VERSION 5.8 ;
BUSBITCHARS "[]" ;
DIVIDERCHAR "/" ;
UNITS
    DATABASE MICRONS 1000 ;
END UNITS

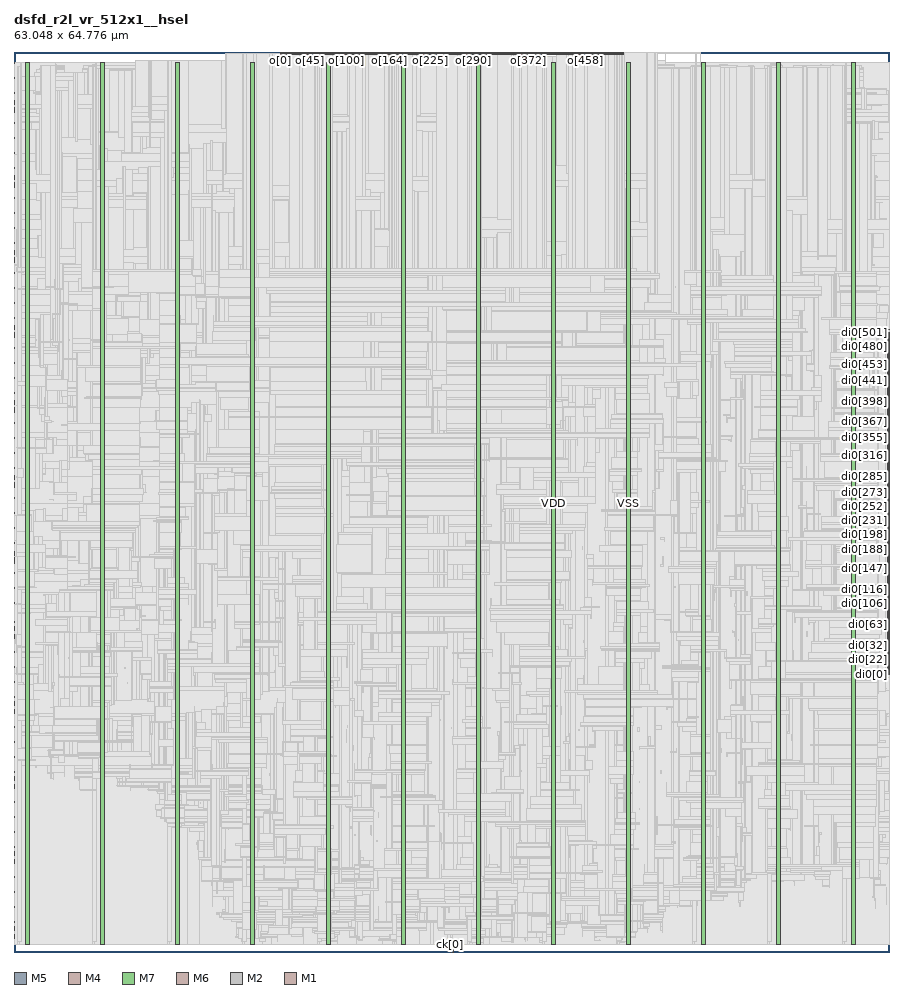
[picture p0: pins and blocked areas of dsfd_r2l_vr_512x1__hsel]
MACRO dsfd_r2l_vr_512x1__hsel
  FOREIGN dsfd_r2l_vr_512x1__hsel 0 0 ;
  CLASS BLOCK ;
  SIZE 63.048 BY 64.776 ;
  PIN ck[0]
    DIRECTION INPUT ;
    USE SIGNAL ;
    PORT
      LAYER M5 ;
        RECT  31.392 0 31.416 0.192 ;
    END
  END ck[0]
  PIN di0[0]
    DIRECTION INPUT ;
    USE SIGNAL ;
    PORT
      LAYER M4 ;
        RECT  62.856 19.968 63.048 19.992 ;
    END
  END di0[0]
  PIN di0[100]
    DIRECTION INPUT ;
    USE SIGNAL ;
    PORT
      LAYER M4 ;
        RECT  62.856 24.768 63.048 24.792 ;
    END
  END di0[100]
  PIN di0[101]
    DIRECTION INPUT ;
    USE SIGNAL ;
    PORT
      LAYER M4 ;
        RECT  62.856 24.816 63.048 24.84 ;
    END
  END di0[101]
  PIN di0[102]
    DIRECTION INPUT ;
    USE SIGNAL ;
    PORT
      LAYER M4 ;
        RECT  62.856 24.864 63.048 24.888 ;
    END
  END di0[102]
  PIN di0[103]
    DIRECTION INPUT ;
    USE SIGNAL ;
    PORT
      LAYER M4 ;
        RECT  62.856 24.912 63.048 24.936 ;
    END
  END di0[103]
  PIN di0[104]
    DIRECTION INPUT ;
    USE SIGNAL ;
    PORT
      LAYER M4 ;
        RECT  62.856 24.96 63.048 24.984 ;
    END
  END di0[104]
  PIN di0[105]
    DIRECTION INPUT ;
    USE SIGNAL ;
    PORT
      LAYER M4 ;
        RECT  62.856 25.008 63.048 25.032 ;
    END
  END di0[105]
  PIN di0[106]
    DIRECTION INPUT ;
    USE SIGNAL ;
    PORT
      LAYER M4 ;
        RECT  62.856 25.056 63.048 25.08 ;
    END
  END di0[106]
  PIN di0[107]
    DIRECTION INPUT ;
    USE SIGNAL ;
    PORT
      LAYER M4 ;
        RECT  62.856 25.104 63.048 25.128 ;
    END
  END di0[107]
  PIN di0[108]
    DIRECTION INPUT ;
    USE SIGNAL ;
    PORT
      LAYER M4 ;
        RECT  62.856 25.152 63.048 25.176 ;
    END
  END di0[108]
  PIN di0[109]
    DIRECTION INPUT ;
    USE SIGNAL ;
    PORT
      LAYER M4 ;
        RECT  62.856 25.2 63.048 25.224 ;
    END
  END di0[109]
  PIN di0[10]
    DIRECTION INPUT ;
    USE SIGNAL ;
    PORT
      LAYER M4 ;
        RECT  62.856 20.448 63.048 20.472 ;
    END
  END di0[10]
  PIN di0[110]
    DIRECTION INPUT ;
    USE SIGNAL ;
    PORT
      LAYER M4 ;
        RECT  62.856 25.248 63.048 25.272 ;
    END
  END di0[110]
  PIN di0[111]
    DIRECTION INPUT ;
    USE SIGNAL ;
    PORT
      LAYER M4 ;
        RECT  62.856 25.296 63.048 25.32 ;
    END
  END di0[111]
  PIN di0[112]
    DIRECTION INPUT ;
    USE SIGNAL ;
    PORT
      LAYER M4 ;
        RECT  62.856 25.344 63.048 25.368 ;
    END
  END di0[112]
  PIN di0[113]
    DIRECTION INPUT ;
    USE SIGNAL ;
    PORT
      LAYER M4 ;
        RECT  62.856 25.392 63.048 25.416 ;
    END
  END di0[113]
  PIN di0[114]
    DIRECTION INPUT ;
    USE SIGNAL ;
    PORT
      LAYER M4 ;
        RECT  62.856 25.44 63.048 25.464 ;
    END
  END di0[114]
  PIN di0[115]
    DIRECTION INPUT ;
    USE SIGNAL ;
    PORT
      LAYER M4 ;
        RECT  62.856 25.488 63.048 25.512 ;
    END
  END di0[115]
  PIN di0[116]
    DIRECTION INPUT ;
    USE SIGNAL ;
    PORT
      LAYER M4 ;
        RECT  62.856 25.536 63.048 25.56 ;
    END
  END di0[116]
  PIN di0[117]
    DIRECTION INPUT ;
    USE SIGNAL ;
    PORT
      LAYER M4 ;
        RECT  62.856 25.584 63.048 25.608 ;
    END
  END di0[117]
  PIN di0[118]
    DIRECTION INPUT ;
    USE SIGNAL ;
    PORT
      LAYER M4 ;
        RECT  62.856 25.632 63.048 25.656 ;
    END
  END di0[118]
  PIN di0[119]
    DIRECTION INPUT ;
    USE SIGNAL ;
    PORT
      LAYER M4 ;
        RECT  62.856 25.68 63.048 25.704 ;
    END
  END di0[119]
  PIN di0[11]
    DIRECTION INPUT ;
    USE SIGNAL ;
    PORT
      LAYER M4 ;
        RECT  62.856 20.496 63.048 20.52 ;
    END
  END di0[11]
  PIN di0[120]
    DIRECTION INPUT ;
    USE SIGNAL ;
    PORT
      LAYER M4 ;
        RECT  62.856 25.728 63.048 25.752 ;
    END
  END di0[120]
  PIN di0[121]
    DIRECTION INPUT ;
    USE SIGNAL ;
    PORT
      LAYER M4 ;
        RECT  62.856 25.776 63.048 25.8 ;
    END
  END di0[121]
  PIN di0[122]
    DIRECTION INPUT ;
    USE SIGNAL ;
    PORT
      LAYER M4 ;
        RECT  62.856 25.824 63.048 25.848 ;
    END
  END di0[122]
  PIN di0[123]
    DIRECTION INPUT ;
    USE SIGNAL ;
    PORT
      LAYER M4 ;
        RECT  62.856 25.872 63.048 25.896 ;
    END
  END di0[123]
  PIN di0[124]
    DIRECTION INPUT ;
    USE SIGNAL ;
    PORT
      LAYER M4 ;
        RECT  62.856 25.92 63.048 25.944 ;
    END
  END di0[124]
  PIN di0[125]
    DIRECTION INPUT ;
    USE SIGNAL ;
    PORT
      LAYER M4 ;
        RECT  62.856 25.968 63.048 25.992 ;
    END
  END di0[125]
  PIN di0[126]
    DIRECTION INPUT ;
    USE SIGNAL ;
    PORT
      LAYER M4 ;
        RECT  62.856 26.016 63.048 26.04 ;
    END
  END di0[126]
  PIN di0[127]
    DIRECTION INPUT ;
    USE SIGNAL ;
    PORT
      LAYER M4 ;
        RECT  62.856 26.064 63.048 26.088 ;
    END
  END di0[127]
  PIN di0[128]
    DIRECTION INPUT ;
    USE SIGNAL ;
    PORT
      LAYER M4 ;
        RECT  62.856 26.112 63.048 26.136 ;
    END
  END di0[128]
  PIN di0[129]
    DIRECTION INPUT ;
    USE SIGNAL ;
    PORT
      LAYER M4 ;
        RECT  62.856 26.16 63.048 26.184 ;
    END
  END di0[129]
  PIN di0[12]
    DIRECTION INPUT ;
    USE SIGNAL ;
    PORT
      LAYER M4 ;
        RECT  62.856 20.544 63.048 20.568 ;
    END
  END di0[12]
  PIN di0[130]
    DIRECTION INPUT ;
    USE SIGNAL ;
    PORT
      LAYER M4 ;
        RECT  62.856 26.208 63.048 26.232 ;
    END
  END di0[130]
  PIN di0[131]
    DIRECTION INPUT ;
    USE SIGNAL ;
    PORT
      LAYER M4 ;
        RECT  62.856 26.256 63.048 26.28 ;
    END
  END di0[131]
  PIN di0[132]
    DIRECTION INPUT ;
    USE SIGNAL ;
    PORT
      LAYER M4 ;
        RECT  62.856 26.304 63.048 26.328 ;
    END
  END di0[132]
  PIN di0[133]
    DIRECTION INPUT ;
    USE SIGNAL ;
    PORT
      LAYER M4 ;
        RECT  62.856 26.352 63.048 26.376 ;
    END
  END di0[133]
  PIN di0[134]
    DIRECTION INPUT ;
    USE SIGNAL ;
    PORT
      LAYER M4 ;
        RECT  62.856 26.4 63.048 26.424 ;
    END
  END di0[134]
  PIN di0[135]
    DIRECTION INPUT ;
    USE SIGNAL ;
    PORT
      LAYER M4 ;
        RECT  62.856 26.448 63.048 26.472 ;
    END
  END di0[135]
  PIN di0[136]
    DIRECTION INPUT ;
    USE SIGNAL ;
    PORT
      LAYER M4 ;
        RECT  62.856 26.496 63.048 26.52 ;
    END
  END di0[136]
  PIN di0[137]
    DIRECTION INPUT ;
    USE SIGNAL ;
    PORT
      LAYER M4 ;
        RECT  62.856 26.544 63.048 26.568 ;
    END
  END di0[137]
  PIN di0[138]
    DIRECTION INPUT ;
    USE SIGNAL ;
    PORT
      LAYER M4 ;
        RECT  62.856 26.592 63.048 26.616 ;
    END
  END di0[138]
  PIN di0[139]
    DIRECTION INPUT ;
    USE SIGNAL ;
    PORT
      LAYER M4 ;
        RECT  62.856 26.64 63.048 26.664 ;
    END
  END di0[139]
  PIN di0[13]
    DIRECTION INPUT ;
    USE SIGNAL ;
    PORT
      LAYER M4 ;
        RECT  62.856 20.592 63.048 20.616 ;
    END
  END di0[13]
  PIN di0[140]
    DIRECTION INPUT ;
    USE SIGNAL ;
    PORT
      LAYER M4 ;
        RECT  62.856 26.688 63.048 26.712 ;
    END
  END di0[140]
  PIN di0[141]
    DIRECTION INPUT ;
    USE SIGNAL ;
    PORT
      LAYER M4 ;
        RECT  62.856 26.736 63.048 26.76 ;
    END
  END di0[141]
  PIN di0[142]
    DIRECTION INPUT ;
    USE SIGNAL ;
    PORT
      LAYER M4 ;
        RECT  62.856 26.784 63.048 26.808 ;
    END
  END di0[142]
  PIN di0[143]
    DIRECTION INPUT ;
    USE SIGNAL ;
    PORT
      LAYER M4 ;
        RECT  62.856 26.832 63.048 26.856 ;
    END
  END di0[143]
  PIN di0[144]
    DIRECTION INPUT ;
    USE SIGNAL ;
    PORT
      LAYER M4 ;
        RECT  62.856 26.88 63.048 26.904 ;
    END
  END di0[144]
  PIN di0[145]
    DIRECTION INPUT ;
    USE SIGNAL ;
    PORT
      LAYER M4 ;
        RECT  62.856 26.928 63.048 26.952 ;
    END
  END di0[145]
  PIN di0[146]
    DIRECTION INPUT ;
    USE SIGNAL ;
    PORT
      LAYER M4 ;
        RECT  62.856 26.976 63.048 27 ;
    END
  END di0[146]
  PIN di0[147]
    DIRECTION INPUT ;
    USE SIGNAL ;
    PORT
      LAYER M4 ;
        RECT  62.856 27.024 63.048 27.048 ;
    END
  END di0[147]
  PIN di0[148]
    DIRECTION INPUT ;
    USE SIGNAL ;
    PORT
      LAYER M4 ;
        RECT  62.856 27.072 63.048 27.096 ;
    END
  END di0[148]
  PIN di0[149]
    DIRECTION INPUT ;
    USE SIGNAL ;
    PORT
      LAYER M4 ;
        RECT  62.856 27.12 63.048 27.144 ;
    END
  END di0[149]
  PIN di0[14]
    DIRECTION INPUT ;
    USE SIGNAL ;
    PORT
      LAYER M4 ;
        RECT  62.856 20.64 63.048 20.664 ;
    END
  END di0[14]
  PIN di0[150]
    DIRECTION INPUT ;
    USE SIGNAL ;
    PORT
      LAYER M4 ;
        RECT  62.856 27.168 63.048 27.192 ;
    END
  END di0[150]
  PIN di0[151]
    DIRECTION INPUT ;
    USE SIGNAL ;
    PORT
      LAYER M4 ;
        RECT  62.856 27.216 63.048 27.24 ;
    END
  END di0[151]
  PIN di0[152]
    DIRECTION INPUT ;
    USE SIGNAL ;
    PORT
      LAYER M4 ;
        RECT  62.856 27.264 63.048 27.288 ;
    END
  END di0[152]
  PIN di0[153]
    DIRECTION INPUT ;
    USE SIGNAL ;
    PORT
      LAYER M4 ;
        RECT  62.856 27.312 63.048 27.336 ;
    END
  END di0[153]
  PIN di0[154]
    DIRECTION INPUT ;
    USE SIGNAL ;
    PORT
      LAYER M4 ;
        RECT  62.856 27.36 63.048 27.384 ;
    END
  END di0[154]
  PIN di0[155]
    DIRECTION INPUT ;
    USE SIGNAL ;
    PORT
      LAYER M4 ;
        RECT  62.856 27.408 63.048 27.432 ;
    END
  END di0[155]
  PIN di0[156]
    DIRECTION INPUT ;
    USE SIGNAL ;
    PORT
      LAYER M4 ;
        RECT  62.856 27.456 63.048 27.48 ;
    END
  END di0[156]
  PIN di0[157]
    DIRECTION INPUT ;
    USE SIGNAL ;
    PORT
      LAYER M4 ;
        RECT  62.856 27.504 63.048 27.528 ;
    END
  END di0[157]
  PIN di0[158]
    DIRECTION INPUT ;
    USE SIGNAL ;
    PORT
      LAYER M4 ;
        RECT  62.856 27.552 63.048 27.576 ;
    END
  END di0[158]
  PIN di0[159]
    DIRECTION INPUT ;
    USE SIGNAL ;
    PORT
      LAYER M4 ;
        RECT  62.856 27.6 63.048 27.624 ;
    END
  END di0[159]
  PIN di0[15]
    DIRECTION INPUT ;
    USE SIGNAL ;
    PORT
      LAYER M4 ;
        RECT  62.856 20.688 63.048 20.712 ;
    END
  END di0[15]
  PIN di0[160]
    DIRECTION INPUT ;
    USE SIGNAL ;
    PORT
      LAYER M4 ;
        RECT  62.856 27.648 63.048 27.672 ;
    END
  END di0[160]
  PIN di0[161]
    DIRECTION INPUT ;
    USE SIGNAL ;
    PORT
      LAYER M4 ;
        RECT  62.856 27.696 63.048 27.72 ;
    END
  END di0[161]
  PIN di0[162]
    DIRECTION INPUT ;
    USE SIGNAL ;
    PORT
      LAYER M4 ;
        RECT  62.856 27.744 63.048 27.768 ;
    END
  END di0[162]
  PIN di0[163]
    DIRECTION INPUT ;
    USE SIGNAL ;
    PORT
      LAYER M4 ;
        RECT  62.856 27.792 63.048 27.816 ;
    END
  END di0[163]
  PIN di0[164]
    DIRECTION INPUT ;
    USE SIGNAL ;
    PORT
      LAYER M4 ;
        RECT  62.856 27.84 63.048 27.864 ;
    END
  END di0[164]
  PIN di0[165]
    DIRECTION INPUT ;
    USE SIGNAL ;
    PORT
      LAYER M4 ;
        RECT  62.856 27.888 63.048 27.912 ;
    END
  END di0[165]
  PIN di0[166]
    DIRECTION INPUT ;
    USE SIGNAL ;
    PORT
      LAYER M4 ;
        RECT  62.856 27.936 63.048 27.96 ;
    END
  END di0[166]
  PIN di0[167]
    DIRECTION INPUT ;
    USE SIGNAL ;
    PORT
      LAYER M4 ;
        RECT  62.856 27.984 63.048 28.008 ;
    END
  END di0[167]
  PIN di0[168]
    DIRECTION INPUT ;
    USE SIGNAL ;
    PORT
      LAYER M4 ;
        RECT  62.856 28.032 63.048 28.056 ;
    END
  END di0[168]
  PIN di0[169]
    DIRECTION INPUT ;
    USE SIGNAL ;
    PORT
      LAYER M4 ;
        RECT  62.856 28.08 63.048 28.104 ;
    END
  END di0[169]
  PIN di0[16]
    DIRECTION INPUT ;
    USE SIGNAL ;
    PORT
      LAYER M4 ;
        RECT  62.856 20.736 63.048 20.76 ;
    END
  END di0[16]
  PIN di0[170]
    DIRECTION INPUT ;
    USE SIGNAL ;
    PORT
      LAYER M4 ;
        RECT  62.856 28.128 63.048 28.152 ;
    END
  END di0[170]
  PIN di0[171]
    DIRECTION INPUT ;
    USE SIGNAL ;
    PORT
      LAYER M4 ;
        RECT  62.856 28.176 63.048 28.2 ;
    END
  END di0[171]
  PIN di0[172]
    DIRECTION INPUT ;
    USE SIGNAL ;
    PORT
      LAYER M4 ;
        RECT  62.856 28.224 63.048 28.248 ;
    END
  END di0[172]
  PIN di0[173]
    DIRECTION INPUT ;
    USE SIGNAL ;
    PORT
      LAYER M4 ;
        RECT  62.856 28.272 63.048 28.296 ;
    END
  END di0[173]
  PIN di0[174]
    DIRECTION INPUT ;
    USE SIGNAL ;
    PORT
      LAYER M4 ;
        RECT  62.856 28.32 63.048 28.344 ;
    END
  END di0[174]
  PIN di0[175]
    DIRECTION INPUT ;
    USE SIGNAL ;
    PORT
      LAYER M4 ;
        RECT  62.856 28.368 63.048 28.392 ;
    END
  END di0[175]
  PIN di0[176]
    DIRECTION INPUT ;
    USE SIGNAL ;
    PORT
      LAYER M4 ;
        RECT  62.856 28.416 63.048 28.44 ;
    END
  END di0[176]
  PIN di0[177]
    DIRECTION INPUT ;
    USE SIGNAL ;
    PORT
      LAYER M4 ;
        RECT  62.856 28.464 63.048 28.488 ;
    END
  END di0[177]
  PIN di0[178]
    DIRECTION INPUT ;
    USE SIGNAL ;
    PORT
      LAYER M4 ;
        RECT  62.856 28.512 63.048 28.536 ;
    END
  END di0[178]
  PIN di0[179]
    DIRECTION INPUT ;
    USE SIGNAL ;
    PORT
      LAYER M4 ;
        RECT  62.856 28.56 63.048 28.584 ;
    END
  END di0[179]
  PIN di0[17]
    DIRECTION INPUT ;
    USE SIGNAL ;
    PORT
      LAYER M4 ;
        RECT  62.856 20.784 63.048 20.808 ;
    END
  END di0[17]
  PIN di0[180]
    DIRECTION INPUT ;
    USE SIGNAL ;
    PORT
      LAYER M4 ;
        RECT  62.856 28.608 63.048 28.632 ;
    END
  END di0[180]
  PIN di0[181]
    DIRECTION INPUT ;
    USE SIGNAL ;
    PORT
      LAYER M4 ;
        RECT  62.856 28.656 63.048 28.68 ;
    END
  END di0[181]
  PIN di0[182]
    DIRECTION INPUT ;
    USE SIGNAL ;
    PORT
      LAYER M4 ;
        RECT  62.856 28.704 63.048 28.728 ;
    END
  END di0[182]
  PIN di0[183]
    DIRECTION INPUT ;
    USE SIGNAL ;
    PORT
      LAYER M4 ;
        RECT  62.856 28.752 63.048 28.776 ;
    END
  END di0[183]
  PIN di0[184]
    DIRECTION INPUT ;
    USE SIGNAL ;
    PORT
      LAYER M4 ;
        RECT  62.856 28.8 63.048 28.824 ;
    END
  END di0[184]
  PIN di0[185]
    DIRECTION INPUT ;
    USE SIGNAL ;
    PORT
      LAYER M4 ;
        RECT  62.856 28.848 63.048 28.872 ;
    END
  END di0[185]
  PIN di0[186]
    DIRECTION INPUT ;
    USE SIGNAL ;
    PORT
      LAYER M4 ;
        RECT  62.856 28.896 63.048 28.92 ;
    END
  END di0[186]
  PIN di0[187]
    DIRECTION INPUT ;
    USE SIGNAL ;
    PORT
      LAYER M4 ;
        RECT  62.856 28.944 63.048 28.968 ;
    END
  END di0[187]
  PIN di0[188]
    DIRECTION INPUT ;
    USE SIGNAL ;
    PORT
      LAYER M4 ;
        RECT  62.856 28.992 63.048 29.016 ;
    END
  END di0[188]
  PIN di0[189]
    DIRECTION INPUT ;
    USE SIGNAL ;
    PORT
      LAYER M4 ;
        RECT  62.856 29.04 63.048 29.064 ;
    END
  END di0[189]
  PIN di0[18]
    DIRECTION INPUT ;
    USE SIGNAL ;
    PORT
      LAYER M4 ;
        RECT  62.856 20.832 63.048 20.856 ;
    END
  END di0[18]
  PIN di0[190]
    DIRECTION INPUT ;
    USE SIGNAL ;
    PORT
      LAYER M4 ;
        RECT  62.856 29.088 63.048 29.112 ;
    END
  END di0[190]
  PIN di0[191]
    DIRECTION INPUT ;
    USE SIGNAL ;
    PORT
      LAYER M4 ;
        RECT  62.856 29.136 63.048 29.16 ;
    END
  END di0[191]
  PIN di0[192]
    DIRECTION INPUT ;
    USE SIGNAL ;
    PORT
      LAYER M4 ;
        RECT  62.856 29.184 63.048 29.208 ;
    END
  END di0[192]
  PIN di0[193]
    DIRECTION INPUT ;
    USE SIGNAL ;
    PORT
      LAYER M4 ;
        RECT  62.856 29.232 63.048 29.256 ;
    END
  END di0[193]
  PIN di0[194]
    DIRECTION INPUT ;
    USE SIGNAL ;
    PORT
      LAYER M4 ;
        RECT  62.856 29.28 63.048 29.304 ;
    END
  END di0[194]
  PIN di0[195]
    DIRECTION INPUT ;
    USE SIGNAL ;
    PORT
      LAYER M4 ;
        RECT  62.856 29.328 63.048 29.352 ;
    END
  END di0[195]
  PIN di0[196]
    DIRECTION INPUT ;
    USE SIGNAL ;
    PORT
      LAYER M4 ;
        RECT  62.856 29.376 63.048 29.4 ;
    END
  END di0[196]
  PIN di0[197]
    DIRECTION INPUT ;
    USE SIGNAL ;
    PORT
      LAYER M4 ;
        RECT  62.856 29.424 63.048 29.448 ;
    END
  END di0[197]
  PIN di0[198]
    DIRECTION INPUT ;
    USE SIGNAL ;
    PORT
      LAYER M4 ;
        RECT  62.856 29.472 63.048 29.496 ;
    END
  END di0[198]
  PIN di0[199]
    DIRECTION INPUT ;
    USE SIGNAL ;
    PORT
      LAYER M4 ;
        RECT  62.856 29.52 63.048 29.544 ;
    END
  END di0[199]
  PIN di0[19]
    DIRECTION INPUT ;
    USE SIGNAL ;
    PORT
      LAYER M4 ;
        RECT  62.856 20.88 63.048 20.904 ;
    END
  END di0[19]
  PIN di0[1]
    DIRECTION INPUT ;
    USE SIGNAL ;
    PORT
      LAYER M4 ;
        RECT  62.856 20.016 63.048 20.04 ;
    END
  END di0[1]
  PIN di0[200]
    DIRECTION INPUT ;
    USE SIGNAL ;
    PORT
      LAYER M4 ;
        RECT  62.856 29.568 63.048 29.592 ;
    END
  END di0[200]
  PIN di0[201]
    DIRECTION INPUT ;
    USE SIGNAL ;
    PORT
      LAYER M4 ;
        RECT  62.856 29.616 63.048 29.64 ;
    END
  END di0[201]
  PIN di0[202]
    DIRECTION INPUT ;
    USE SIGNAL ;
    PORT
      LAYER M4 ;
        RECT  62.856 29.664 63.048 29.688 ;
    END
  END di0[202]
  PIN di0[203]
    DIRECTION INPUT ;
    USE SIGNAL ;
    PORT
      LAYER M4 ;
        RECT  62.856 29.712 63.048 29.736 ;
    END
  END di0[203]
  PIN di0[204]
    DIRECTION INPUT ;
    USE SIGNAL ;
    PORT
      LAYER M4 ;
        RECT  62.856 29.76 63.048 29.784 ;
    END
  END di0[204]
  PIN di0[205]
    DIRECTION INPUT ;
    USE SIGNAL ;
    PORT
      LAYER M4 ;
        RECT  62.856 29.808 63.048 29.832 ;
    END
  END di0[205]
  PIN di0[206]
    DIRECTION INPUT ;
    USE SIGNAL ;
    PORT
      LAYER M4 ;
        RECT  62.856 29.856 63.048 29.88 ;
    END
  END di0[206]
  PIN di0[207]
    DIRECTION INPUT ;
    USE SIGNAL ;
    PORT
      LAYER M4 ;
        RECT  62.856 29.904 63.048 29.928 ;
    END
  END di0[207]
  PIN di0[208]
    DIRECTION INPUT ;
    USE SIGNAL ;
    PORT
      LAYER M4 ;
        RECT  62.856 29.952 63.048 29.976 ;
    END
  END di0[208]
  PIN di0[209]
    DIRECTION INPUT ;
    USE SIGNAL ;
    PORT
      LAYER M4 ;
        RECT  62.856 30 63.048 30.024 ;
    END
  END di0[209]
  PIN di0[20]
    DIRECTION INPUT ;
    USE SIGNAL ;
    PORT
      LAYER M4 ;
        RECT  62.856 20.928 63.048 20.952 ;
    END
  END di0[20]
  PIN di0[210]
    DIRECTION INPUT ;
    USE SIGNAL ;
    PORT
      LAYER M4 ;
        RECT  62.856 30.048 63.048 30.072 ;
    END
  END di0[210]
  PIN di0[211]
    DIRECTION INPUT ;
    USE SIGNAL ;
    PORT
      LAYER M4 ;
        RECT  62.856 30.096 63.048 30.12 ;
    END
  END di0[211]
  PIN di0[212]
    DIRECTION INPUT ;
    USE SIGNAL ;
    PORT
      LAYER M4 ;
        RECT  62.856 30.144 63.048 30.168 ;
    END
  END di0[212]
  PIN di0[213]
    DIRECTION INPUT ;
    USE SIGNAL ;
    PORT
      LAYER M4 ;
        RECT  62.856 30.192 63.048 30.216 ;
    END
  END di0[213]
  PIN di0[214]
    DIRECTION INPUT ;
    USE SIGNAL ;
    PORT
      LAYER M4 ;
        RECT  62.856 30.24 63.048 30.264 ;
    END
  END di0[214]
  PIN di0[215]
    DIRECTION INPUT ;
    USE SIGNAL ;
    PORT
      LAYER M4 ;
        RECT  62.856 30.288 63.048 30.312 ;
    END
  END di0[215]
  PIN di0[216]
    DIRECTION INPUT ;
    USE SIGNAL ;
    PORT
      LAYER M4 ;
        RECT  62.856 30.336 63.048 30.36 ;
    END
  END di0[216]
  PIN di0[217]
    DIRECTION INPUT ;
    USE SIGNAL ;
    PORT
      LAYER M4 ;
        RECT  62.856 30.384 63.048 30.408 ;
    END
  END di0[217]
  PIN di0[218]
    DIRECTION INPUT ;
    USE SIGNAL ;
    PORT
      LAYER M4 ;
        RECT  62.856 30.432 63.048 30.456 ;
    END
  END di0[218]
  PIN di0[219]
    DIRECTION INPUT ;
    USE SIGNAL ;
    PORT
      LAYER M4 ;
        RECT  62.856 30.48 63.048 30.504 ;
    END
  END di0[219]
  PIN di0[21]
    DIRECTION INPUT ;
    USE SIGNAL ;
    PORT
      LAYER M4 ;
        RECT  62.856 20.976 63.048 21 ;
    END
  END di0[21]
  PIN di0[220]
    DIRECTION INPUT ;
    USE SIGNAL ;
    PORT
      LAYER M4 ;
        RECT  62.856 30.528 63.048 30.552 ;
    END
  END di0[220]
  PIN di0[221]
    DIRECTION INPUT ;
    USE SIGNAL ;
    PORT
      LAYER M4 ;
        RECT  62.856 30.576 63.048 30.6 ;
    END
  END di0[221]
  PIN di0[222]
    DIRECTION INPUT ;
    USE SIGNAL ;
    PORT
      LAYER M4 ;
        RECT  62.856 30.624 63.048 30.648 ;
    END
  END di0[222]
  PIN di0[223]
    DIRECTION INPUT ;
    USE SIGNAL ;
    PORT
      LAYER M4 ;
        RECT  62.856 30.672 63.048 30.696 ;
    END
  END di0[223]
  PIN di0[224]
    DIRECTION INPUT ;
    USE SIGNAL ;
    PORT
      LAYER M4 ;
        RECT  62.856 30.72 63.048 30.744 ;
    END
  END di0[224]
  PIN di0[225]
    DIRECTION INPUT ;
    USE SIGNAL ;
    PORT
      LAYER M4 ;
        RECT  62.856 30.768 63.048 30.792 ;
    END
  END di0[225]
  PIN di0[226]
    DIRECTION INPUT ;
    USE SIGNAL ;
    PORT
      LAYER M4 ;
        RECT  62.856 30.816 63.048 30.84 ;
    END
  END di0[226]
  PIN di0[227]
    DIRECTION INPUT ;
    USE SIGNAL ;
    PORT
      LAYER M4 ;
        RECT  62.856 30.864 63.048 30.888 ;
    END
  END di0[227]
  PIN di0[228]
    DIRECTION INPUT ;
    USE SIGNAL ;
    PORT
      LAYER M4 ;
        RECT  62.856 30.912 63.048 30.936 ;
    END
  END di0[228]
  PIN di0[229]
    DIRECTION INPUT ;
    USE SIGNAL ;
    PORT
      LAYER M4 ;
        RECT  62.856 30.96 63.048 30.984 ;
    END
  END di0[229]
  PIN di0[22]
    DIRECTION INPUT ;
    USE SIGNAL ;
    PORT
      LAYER M4 ;
        RECT  62.856 21.024 63.048 21.048 ;
    END
  END di0[22]
  PIN di0[230]
    DIRECTION INPUT ;
    USE SIGNAL ;
    PORT
      LAYER M4 ;
        RECT  62.856 31.008 63.048 31.032 ;
    END
  END di0[230]
  PIN di0[231]
    DIRECTION INPUT ;
    USE SIGNAL ;
    PORT
      LAYER M4 ;
        RECT  62.856 31.056 63.048 31.08 ;
    END
  END di0[231]
  PIN di0[232]
    DIRECTION INPUT ;
    USE SIGNAL ;
    PORT
      LAYER M4 ;
        RECT  62.856 31.104 63.048 31.128 ;
    END
  END di0[232]
  PIN di0[233]
    DIRECTION INPUT ;
    USE SIGNAL ;
    PORT
      LAYER M4 ;
        RECT  62.856 31.152 63.048 31.176 ;
    END
  END di0[233]
  PIN di0[234]
    DIRECTION INPUT ;
    USE SIGNAL ;
    PORT
      LAYER M4 ;
        RECT  62.856 31.2 63.048 31.224 ;
    END
  END di0[234]
  PIN di0[235]
    DIRECTION INPUT ;
    USE SIGNAL ;
    PORT
      LAYER M4 ;
        RECT  62.856 31.248 63.048 31.272 ;
    END
  END di0[235]
  PIN di0[236]
    DIRECTION INPUT ;
    USE SIGNAL ;
    PORT
      LAYER M4 ;
        RECT  62.856 31.296 63.048 31.32 ;
    END
  END di0[236]
  PIN di0[237]
    DIRECTION INPUT ;
    USE SIGNAL ;
    PORT
      LAYER M4 ;
        RECT  62.856 31.344 63.048 31.368 ;
    END
  END di0[237]
  PIN di0[238]
    DIRECTION INPUT ;
    USE SIGNAL ;
    PORT
      LAYER M4 ;
        RECT  62.856 31.392 63.048 31.416 ;
    END
  END di0[238]
  PIN di0[239]
    DIRECTION INPUT ;
    USE SIGNAL ;
    PORT
      LAYER M4 ;
        RECT  62.856 31.44 63.048 31.464 ;
    END
  END di0[239]
  PIN di0[23]
    DIRECTION INPUT ;
    USE SIGNAL ;
    PORT
      LAYER M4 ;
        RECT  62.856 21.072 63.048 21.096 ;
    END
  END di0[23]
  PIN di0[240]
    DIRECTION INPUT ;
    USE SIGNAL ;
    PORT
      LAYER M4 ;
        RECT  62.856 31.488 63.048 31.512 ;
    END
  END di0[240]
  PIN di0[241]
    DIRECTION INPUT ;
    USE SIGNAL ;
    PORT
      LAYER M4 ;
        RECT  62.856 31.536 63.048 31.56 ;
    END
  END di0[241]
  PIN di0[242]
    DIRECTION INPUT ;
    USE SIGNAL ;
    PORT
      LAYER M4 ;
        RECT  62.856 31.584 63.048 31.608 ;
    END
  END di0[242]
  PIN di0[243]
    DIRECTION INPUT ;
    USE SIGNAL ;
    PORT
      LAYER M4 ;
        RECT  62.856 31.632 63.048 31.656 ;
    END
  END di0[243]
  PIN di0[244]
    DIRECTION INPUT ;
    USE SIGNAL ;
    PORT
      LAYER M4 ;
        RECT  62.856 31.68 63.048 31.704 ;
    END
  END di0[244]
  PIN di0[245]
    DIRECTION INPUT ;
    USE SIGNAL ;
    PORT
      LAYER M4 ;
        RECT  62.856 31.728 63.048 31.752 ;
    END
  END di0[245]
  PIN di0[246]
    DIRECTION INPUT ;
    USE SIGNAL ;
    PORT
      LAYER M4 ;
        RECT  62.856 31.776 63.048 31.8 ;
    END
  END di0[246]
  PIN di0[247]
    DIRECTION INPUT ;
    USE SIGNAL ;
    PORT
      LAYER M4 ;
        RECT  62.856 31.824 63.048 31.848 ;
    END
  END di0[247]
  PIN di0[248]
    DIRECTION INPUT ;
    USE SIGNAL ;
    PORT
      LAYER M4 ;
        RECT  62.856 31.872 63.048 31.896 ;
    END
  END di0[248]
  PIN di0[249]
    DIRECTION INPUT ;
    USE SIGNAL ;
    PORT
      LAYER M4 ;
        RECT  62.856 31.92 63.048 31.944 ;
    END
  END di0[249]
  PIN di0[24]
    DIRECTION INPUT ;
    USE SIGNAL ;
    PORT
      LAYER M4 ;
        RECT  62.856 21.12 63.048 21.144 ;
    END
  END di0[24]
  PIN di0[250]
    DIRECTION INPUT ;
    USE SIGNAL ;
    PORT
      LAYER M4 ;
        RECT  62.856 31.968 63.048 31.992 ;
    END
  END di0[250]
  PIN di0[251]
    DIRECTION INPUT ;
    USE SIGNAL ;
    PORT
      LAYER M4 ;
        RECT  62.856 32.016 63.048 32.04 ;
    END
  END di0[251]
  PIN di0[252]
    DIRECTION INPUT ;
    USE SIGNAL ;
    PORT
      LAYER M4 ;
        RECT  62.856 32.064 63.048 32.088 ;
    END
  END di0[252]
  PIN di0[253]
    DIRECTION INPUT ;
    USE SIGNAL ;
    PORT
      LAYER M4 ;
        RECT  62.856 32.112 63.048 32.136 ;
    END
  END di0[253]
  PIN di0[254]
    DIRECTION INPUT ;
    USE SIGNAL ;
    PORT
      LAYER M4 ;
        RECT  62.856 32.16 63.048 32.184 ;
    END
  END di0[254]
  PIN di0[255]
    DIRECTION INPUT ;
    USE SIGNAL ;
    PORT
      LAYER M4 ;
        RECT  62.856 32.208 63.048 32.232 ;
    END
  END di0[255]
  PIN di0[256]
    DIRECTION INPUT ;
    USE SIGNAL ;
    PORT
      LAYER M4 ;
        RECT  62.856 32.256 63.048 32.28 ;
    END
  END di0[256]
  PIN di0[257]
    DIRECTION INPUT ;
    USE SIGNAL ;
    PORT
      LAYER M4 ;
        RECT  62.856 32.304 63.048 32.328 ;
    END
  END di0[257]
  PIN di0[258]
    DIRECTION INPUT ;
    USE SIGNAL ;
    PORT
      LAYER M4 ;
        RECT  62.856 32.352 63.048 32.376 ;
    END
  END di0[258]
  PIN di0[259]
    DIRECTION INPUT ;
    USE SIGNAL ;
    PORT
      LAYER M4 ;
        RECT  62.856 32.4 63.048 32.424 ;
    END
  END di0[259]
  PIN di0[25]
    DIRECTION INPUT ;
    USE SIGNAL ;
    PORT
      LAYER M4 ;
        RECT  62.856 21.168 63.048 21.192 ;
    END
  END di0[25]
  PIN di0[260]
    DIRECTION INPUT ;
    USE SIGNAL ;
    PORT
      LAYER M4 ;
        RECT  62.856 32.448 63.048 32.472 ;
    END
  END di0[260]
  PIN di0[261]
    DIRECTION INPUT ;
    USE SIGNAL ;
    PORT
      LAYER M4 ;
        RECT  62.856 32.496 63.048 32.52 ;
    END
  END di0[261]
  PIN di0[262]
    DIRECTION INPUT ;
    USE SIGNAL ;
    PORT
      LAYER M4 ;
        RECT  62.856 32.544 63.048 32.568 ;
    END
  END di0[262]
  PIN di0[263]
    DIRECTION INPUT ;
    USE SIGNAL ;
    PORT
      LAYER M4 ;
        RECT  62.856 32.592 63.048 32.616 ;
    END
  END di0[263]
  PIN di0[264]
    DIRECTION INPUT ;
    USE SIGNAL ;
    PORT
      LAYER M4 ;
        RECT  62.856 32.64 63.048 32.664 ;
    END
  END di0[264]
  PIN di0[265]
    DIRECTION INPUT ;
    USE SIGNAL ;
    PORT
      LAYER M4 ;
        RECT  62.856 32.688 63.048 32.712 ;
    END
  END di0[265]
  PIN di0[266]
    DIRECTION INPUT ;
    USE SIGNAL ;
    PORT
      LAYER M4 ;
        RECT  62.856 32.736 63.048 32.76 ;
    END
  END di0[266]
  PIN di0[267]
    DIRECTION INPUT ;
    USE SIGNAL ;
    PORT
      LAYER M4 ;
        RECT  62.856 32.784 63.048 32.808 ;
    END
  END di0[267]
  PIN di0[268]
    DIRECTION INPUT ;
    USE SIGNAL ;
    PORT
      LAYER M4 ;
        RECT  62.856 32.832 63.048 32.856 ;
    END
  END di0[268]
  PIN di0[269]
    DIRECTION INPUT ;
    USE SIGNAL ;
    PORT
      LAYER M4 ;
        RECT  62.856 32.88 63.048 32.904 ;
    END
  END di0[269]
  PIN di0[26]
    DIRECTION INPUT ;
    USE SIGNAL ;
    PORT
      LAYER M4 ;
        RECT  62.856 21.216 63.048 21.24 ;
    END
  END di0[26]
  PIN di0[270]
    DIRECTION INPUT ;
    USE SIGNAL ;
    PORT
      LAYER M4 ;
        RECT  62.856 32.928 63.048 32.952 ;
    END
  END di0[270]
  PIN di0[271]
    DIRECTION INPUT ;
    USE SIGNAL ;
    PORT
      LAYER M4 ;
        RECT  62.856 32.976 63.048 33 ;
    END
  END di0[271]
  PIN di0[272]
    DIRECTION INPUT ;
    USE SIGNAL ;
    PORT
      LAYER M4 ;
        RECT  62.856 33.024 63.048 33.048 ;
    END
  END di0[272]
  PIN di0[273]
    DIRECTION INPUT ;
    USE SIGNAL ;
    PORT
      LAYER M4 ;
        RECT  62.856 33.072 63.048 33.096 ;
    END
  END di0[273]
  PIN di0[274]
    DIRECTION INPUT ;
    USE SIGNAL ;
    PORT
      LAYER M4 ;
        RECT  62.856 33.12 63.048 33.144 ;
    END
  END di0[274]
  PIN di0[275]
    DIRECTION INPUT ;
    USE SIGNAL ;
    PORT
      LAYER M4 ;
        RECT  62.856 33.168 63.048 33.192 ;
    END
  END di0[275]
  PIN di0[276]
    DIRECTION INPUT ;
    USE SIGNAL ;
    PORT
      LAYER M4 ;
        RECT  62.856 33.216 63.048 33.24 ;
    END
  END di0[276]
  PIN di0[277]
    DIRECTION INPUT ;
    USE SIGNAL ;
    PORT
      LAYER M4 ;
        RECT  62.856 33.264 63.048 33.288 ;
    END
  END di0[277]
  PIN di0[278]
    DIRECTION INPUT ;
    USE SIGNAL ;
    PORT
      LAYER M4 ;
        RECT  62.856 33.312 63.048 33.336 ;
    END
  END di0[278]
  PIN di0[279]
    DIRECTION INPUT ;
    USE SIGNAL ;
    PORT
      LAYER M4 ;
        RECT  62.856 33.36 63.048 33.384 ;
    END
  END di0[279]
  PIN di0[27]
    DIRECTION INPUT ;
    USE SIGNAL ;
    PORT
      LAYER M4 ;
        RECT  62.856 21.264 63.048 21.288 ;
    END
  END di0[27]
  PIN di0[280]
    DIRECTION INPUT ;
    USE SIGNAL ;
    PORT
      LAYER M4 ;
        RECT  62.856 33.408 63.048 33.432 ;
    END
  END di0[280]
  PIN di0[281]
    DIRECTION INPUT ;
    USE SIGNAL ;
    PORT
      LAYER M4 ;
        RECT  62.856 33.456 63.048 33.48 ;
    END
  END di0[281]
  PIN di0[282]
    DIRECTION INPUT ;
    USE SIGNAL ;
    PORT
      LAYER M4 ;
        RECT  62.856 33.504 63.048 33.528 ;
    END
  END di0[282]
  PIN di0[283]
    DIRECTION INPUT ;
    USE SIGNAL ;
    PORT
      LAYER M4 ;
        RECT  62.856 33.552 63.048 33.576 ;
    END
  END di0[283]
  PIN di0[284]
    DIRECTION INPUT ;
    USE SIGNAL ;
    PORT
      LAYER M4 ;
        RECT  62.856 33.6 63.048 33.624 ;
    END
  END di0[284]
  PIN di0[285]
    DIRECTION INPUT ;
    USE SIGNAL ;
    PORT
      LAYER M4 ;
        RECT  62.856 33.648 63.048 33.672 ;
    END
  END di0[285]
  PIN di0[286]
    DIRECTION INPUT ;
    USE SIGNAL ;
    PORT
      LAYER M4 ;
        RECT  62.856 33.696 63.048 33.72 ;
    END
  END di0[286]
  PIN di0[287]
    DIRECTION INPUT ;
    USE SIGNAL ;
    PORT
      LAYER M4 ;
        RECT  62.856 33.744 63.048 33.768 ;
    END
  END di0[287]
  PIN di0[288]
    DIRECTION INPUT ;
    USE SIGNAL ;
    PORT
      LAYER M4 ;
        RECT  62.856 33.792 63.048 33.816 ;
    END
  END di0[288]
  PIN di0[289]
    DIRECTION INPUT ;
    USE SIGNAL ;
    PORT
      LAYER M4 ;
        RECT  62.856 33.84 63.048 33.864 ;
    END
  END di0[289]
  PIN di0[28]
    DIRECTION INPUT ;
    USE SIGNAL ;
    PORT
      LAYER M4 ;
        RECT  62.856 21.312 63.048 21.336 ;
    END
  END di0[28]
  PIN di0[290]
    DIRECTION INPUT ;
    USE SIGNAL ;
    PORT
      LAYER M4 ;
        RECT  62.856 33.888 63.048 33.912 ;
    END
  END di0[290]
  PIN di0[291]
    DIRECTION INPUT ;
    USE SIGNAL ;
    PORT
      LAYER M4 ;
        RECT  62.856 33.936 63.048 33.96 ;
    END
  END di0[291]
  PIN di0[292]
    DIRECTION INPUT ;
    USE SIGNAL ;
    PORT
      LAYER M4 ;
        RECT  62.856 33.984 63.048 34.008 ;
    END
  END di0[292]
  PIN di0[293]
    DIRECTION INPUT ;
    USE SIGNAL ;
    PORT
      LAYER M4 ;
        RECT  62.856 34.032 63.048 34.056 ;
    END
  END di0[293]
  PIN di0[294]
    DIRECTION INPUT ;
    USE SIGNAL ;
    PORT
      LAYER M4 ;
        RECT  62.856 34.08 63.048 34.104 ;
    END
  END di0[294]
  PIN di0[295]
    DIRECTION INPUT ;
    USE SIGNAL ;
    PORT
      LAYER M4 ;
        RECT  62.856 34.128 63.048 34.152 ;
    END
  END di0[295]
  PIN di0[296]
    DIRECTION INPUT ;
    USE SIGNAL ;
    PORT
      LAYER M4 ;
        RECT  62.856 34.176 63.048 34.2 ;
    END
  END di0[296]
  PIN di0[297]
    DIRECTION INPUT ;
    USE SIGNAL ;
    PORT
      LAYER M4 ;
        RECT  62.856 34.224 63.048 34.248 ;
    END
  END di0[297]
  PIN di0[298]
    DIRECTION INPUT ;
    USE SIGNAL ;
    PORT
      LAYER M4 ;
        RECT  62.856 34.272 63.048 34.296 ;
    END
  END di0[298]
  PIN di0[299]
    DIRECTION INPUT ;
    USE SIGNAL ;
    PORT
      LAYER M4 ;
        RECT  62.856 34.32 63.048 34.344 ;
    END
  END di0[299]
  PIN di0[29]
    DIRECTION INPUT ;
    USE SIGNAL ;
    PORT
      LAYER M4 ;
        RECT  62.856 21.36 63.048 21.384 ;
    END
  END di0[29]
  PIN di0[2]
    DIRECTION INPUT ;
    USE SIGNAL ;
    PORT
      LAYER M4 ;
        RECT  62.856 20.064 63.048 20.088 ;
    END
  END di0[2]
  PIN di0[300]
    DIRECTION INPUT ;
    USE SIGNAL ;
    PORT
      LAYER M4 ;
        RECT  62.856 34.368 63.048 34.392 ;
    END
  END di0[300]
  PIN di0[301]
    DIRECTION INPUT ;
    USE SIGNAL ;
    PORT
      LAYER M4 ;
        RECT  62.856 34.416 63.048 34.44 ;
    END
  END di0[301]
  PIN di0[302]
    DIRECTION INPUT ;
    USE SIGNAL ;
    PORT
      LAYER M4 ;
        RECT  62.856 34.464 63.048 34.488 ;
    END
  END di0[302]
  PIN di0[303]
    DIRECTION INPUT ;
    USE SIGNAL ;
    PORT
      LAYER M4 ;
        RECT  62.856 34.512 63.048 34.536 ;
    END
  END di0[303]
  PIN di0[304]
    DIRECTION INPUT ;
    USE SIGNAL ;
    PORT
      LAYER M4 ;
        RECT  62.856 34.56 63.048 34.584 ;
    END
  END di0[304]
  PIN di0[305]
    DIRECTION INPUT ;
    USE SIGNAL ;
    PORT
      LAYER M4 ;
        RECT  62.856 34.608 63.048 34.632 ;
    END
  END di0[305]
  PIN di0[306]
    DIRECTION INPUT ;
    USE SIGNAL ;
    PORT
      LAYER M4 ;
        RECT  62.856 34.656 63.048 34.68 ;
    END
  END di0[306]
  PIN di0[307]
    DIRECTION INPUT ;
    USE SIGNAL ;
    PORT
      LAYER M4 ;
        RECT  62.856 34.704 63.048 34.728 ;
    END
  END di0[307]
  PIN di0[308]
    DIRECTION INPUT ;
    USE SIGNAL ;
    PORT
      LAYER M4 ;
        RECT  62.856 34.752 63.048 34.776 ;
    END
  END di0[308]
  PIN di0[309]
    DIRECTION INPUT ;
    USE SIGNAL ;
    PORT
      LAYER M4 ;
        RECT  62.856 34.8 63.048 34.824 ;
    END
  END di0[309]
  PIN di0[30]
    DIRECTION INPUT ;
    USE SIGNAL ;
    PORT
      LAYER M4 ;
        RECT  62.856 21.408 63.048 21.432 ;
    END
  END di0[30]
  PIN di0[310]
    DIRECTION INPUT ;
    USE SIGNAL ;
    PORT
      LAYER M4 ;
        RECT  62.856 34.848 63.048 34.872 ;
    END
  END di0[310]
  PIN di0[311]
    DIRECTION INPUT ;
    USE SIGNAL ;
    PORT
      LAYER M4 ;
        RECT  62.856 34.896 63.048 34.92 ;
    END
  END di0[311]
  PIN di0[312]
    DIRECTION INPUT ;
    USE SIGNAL ;
    PORT
      LAYER M4 ;
        RECT  62.856 34.944 63.048 34.968 ;
    END
  END di0[312]
  PIN di0[313]
    DIRECTION INPUT ;
    USE SIGNAL ;
    PORT
      LAYER M4 ;
        RECT  62.856 34.992 63.048 35.016 ;
    END
  END di0[313]
  PIN di0[314]
    DIRECTION INPUT ;
    USE SIGNAL ;
    PORT
      LAYER M4 ;
        RECT  62.856 35.04 63.048 35.064 ;
    END
  END di0[314]
  PIN di0[315]
    DIRECTION INPUT ;
    USE SIGNAL ;
    PORT
      LAYER M4 ;
        RECT  62.856 35.088 63.048 35.112 ;
    END
  END di0[315]
  PIN di0[316]
    DIRECTION INPUT ;
    USE SIGNAL ;
    PORT
      LAYER M4 ;
        RECT  62.856 35.136 63.048 35.16 ;
    END
  END di0[316]
  PIN di0[317]
    DIRECTION INPUT ;
    USE SIGNAL ;
    PORT
      LAYER M4 ;
        RECT  62.856 35.184 63.048 35.208 ;
    END
  END di0[317]
  PIN di0[318]
    DIRECTION INPUT ;
    USE SIGNAL ;
    PORT
      LAYER M4 ;
        RECT  62.856 35.232 63.048 35.256 ;
    END
  END di0[318]
  PIN di0[319]
    DIRECTION INPUT ;
    USE SIGNAL ;
    PORT
      LAYER M4 ;
        RECT  62.856 35.28 63.048 35.304 ;
    END
  END di0[319]
  PIN di0[31]
    DIRECTION INPUT ;
    USE SIGNAL ;
    PORT
      LAYER M4 ;
        RECT  62.856 21.456 63.048 21.48 ;
    END
  END di0[31]
  PIN di0[320]
    DIRECTION INPUT ;
    USE SIGNAL ;
    PORT
      LAYER M4 ;
        RECT  62.856 35.328 63.048 35.352 ;
    END
  END di0[320]
  PIN di0[321]
    DIRECTION INPUT ;
    USE SIGNAL ;
    PORT
      LAYER M4 ;
        RECT  62.856 35.376 63.048 35.4 ;
    END
  END di0[321]
  PIN di0[322]
    DIRECTION INPUT ;
    USE SIGNAL ;
    PORT
      LAYER M4 ;
        RECT  62.856 35.424 63.048 35.448 ;
    END
  END di0[322]
  PIN di0[323]
    DIRECTION INPUT ;
    USE SIGNAL ;
    PORT
      LAYER M4 ;
        RECT  62.856 35.472 63.048 35.496 ;
    END
  END di0[323]
  PIN di0[324]
    DIRECTION INPUT ;
    USE SIGNAL ;
    PORT
      LAYER M4 ;
        RECT  62.856 35.52 63.048 35.544 ;
    END
  END di0[324]
  PIN di0[325]
    DIRECTION INPUT ;
    USE SIGNAL ;
    PORT
      LAYER M4 ;
        RECT  62.856 35.568 63.048 35.592 ;
    END
  END di0[325]
  PIN di0[326]
    DIRECTION INPUT ;
    USE SIGNAL ;
    PORT
      LAYER M4 ;
        RECT  62.856 35.616 63.048 35.64 ;
    END
  END di0[326]
  PIN di0[327]
    DIRECTION INPUT ;
    USE SIGNAL ;
    PORT
      LAYER M4 ;
        RECT  62.856 35.664 63.048 35.688 ;
    END
  END di0[327]
  PIN di0[328]
    DIRECTION INPUT ;
    USE SIGNAL ;
    PORT
      LAYER M4 ;
        RECT  62.856 35.712 63.048 35.736 ;
    END
  END di0[328]
  PIN di0[329]
    DIRECTION INPUT ;
    USE SIGNAL ;
    PORT
      LAYER M4 ;
        RECT  62.856 35.76 63.048 35.784 ;
    END
  END di0[329]
  PIN di0[32]
    DIRECTION INPUT ;
    USE SIGNAL ;
    PORT
      LAYER M4 ;
        RECT  62.856 21.504 63.048 21.528 ;
    END
  END di0[32]
  PIN di0[330]
    DIRECTION INPUT ;
    USE SIGNAL ;
    PORT
      LAYER M4 ;
        RECT  62.856 35.808 63.048 35.832 ;
    END
  END di0[330]
  PIN di0[331]
    DIRECTION INPUT ;
    USE SIGNAL ;
    PORT
      LAYER M4 ;
        RECT  62.856 35.856 63.048 35.88 ;
    END
  END di0[331]
  PIN di0[332]
    DIRECTION INPUT ;
    USE SIGNAL ;
    PORT
      LAYER M4 ;
        RECT  62.856 35.904 63.048 35.928 ;
    END
  END di0[332]
  PIN di0[333]
    DIRECTION INPUT ;
    USE SIGNAL ;
    PORT
      LAYER M4 ;
        RECT  62.856 35.952 63.048 35.976 ;
    END
  END di0[333]
  PIN di0[334]
    DIRECTION INPUT ;
    USE SIGNAL ;
    PORT
      LAYER M4 ;
        RECT  62.856 36 63.048 36.024 ;
    END
  END di0[334]
  PIN di0[335]
    DIRECTION INPUT ;
    USE SIGNAL ;
    PORT
      LAYER M4 ;
        RECT  62.856 36.048 63.048 36.072 ;
    END
  END di0[335]
  PIN di0[336]
    DIRECTION INPUT ;
    USE SIGNAL ;
    PORT
      LAYER M4 ;
        RECT  62.856 36.096 63.048 36.12 ;
    END
  END di0[336]
  PIN di0[337]
    DIRECTION INPUT ;
    USE SIGNAL ;
    PORT
      LAYER M4 ;
        RECT  62.856 36.144 63.048 36.168 ;
    END
  END di0[337]
  PIN di0[338]
    DIRECTION INPUT ;
    USE SIGNAL ;
    PORT
      LAYER M4 ;
        RECT  62.856 36.192 63.048 36.216 ;
    END
  END di0[338]
  PIN di0[339]
    DIRECTION INPUT ;
    USE SIGNAL ;
    PORT
      LAYER M4 ;
        RECT  62.856 36.24 63.048 36.264 ;
    END
  END di0[339]
  PIN di0[33]
    DIRECTION INPUT ;
    USE SIGNAL ;
    PORT
      LAYER M4 ;
        RECT  62.856 21.552 63.048 21.576 ;
    END
  END di0[33]
  PIN di0[340]
    DIRECTION INPUT ;
    USE SIGNAL ;
    PORT
      LAYER M4 ;
        RECT  62.856 36.288 63.048 36.312 ;
    END
  END di0[340]
  PIN di0[341]
    DIRECTION INPUT ;
    USE SIGNAL ;
    PORT
      LAYER M4 ;
        RECT  62.856 36.336 63.048 36.36 ;
    END
  END di0[341]
  PIN di0[342]
    DIRECTION INPUT ;
    USE SIGNAL ;
    PORT
      LAYER M4 ;
        RECT  62.856 36.384 63.048 36.408 ;
    END
  END di0[342]
  PIN di0[343]
    DIRECTION INPUT ;
    USE SIGNAL ;
    PORT
      LAYER M4 ;
        RECT  62.856 36.432 63.048 36.456 ;
    END
  END di0[343]
  PIN di0[344]
    DIRECTION INPUT ;
    USE SIGNAL ;
    PORT
      LAYER M4 ;
        RECT  62.856 36.48 63.048 36.504 ;
    END
  END di0[344]
  PIN di0[345]
    DIRECTION INPUT ;
    USE SIGNAL ;
    PORT
      LAYER M4 ;
        RECT  62.856 36.528 63.048 36.552 ;
    END
  END di0[345]
  PIN di0[346]
    DIRECTION INPUT ;
    USE SIGNAL ;
    PORT
      LAYER M4 ;
        RECT  62.856 36.576 63.048 36.6 ;
    END
  END di0[346]
  PIN di0[347]
    DIRECTION INPUT ;
    USE SIGNAL ;
    PORT
      LAYER M4 ;
        RECT  62.856 36.624 63.048 36.648 ;
    END
  END di0[347]
  PIN di0[348]
    DIRECTION INPUT ;
    USE SIGNAL ;
    PORT
      LAYER M4 ;
        RECT  62.856 36.672 63.048 36.696 ;
    END
  END di0[348]
  PIN di0[349]
    DIRECTION INPUT ;
    USE SIGNAL ;
    PORT
      LAYER M4 ;
        RECT  62.856 36.72 63.048 36.744 ;
    END
  END di0[349]
  PIN di0[34]
    DIRECTION INPUT ;
    USE SIGNAL ;
    PORT
      LAYER M4 ;
        RECT  62.856 21.6 63.048 21.624 ;
    END
  END di0[34]
  PIN di0[350]
    DIRECTION INPUT ;
    USE SIGNAL ;
    PORT
      LAYER M4 ;
        RECT  62.856 36.768 63.048 36.792 ;
    END
  END di0[350]
  PIN di0[351]
    DIRECTION INPUT ;
    USE SIGNAL ;
    PORT
      LAYER M4 ;
        RECT  62.856 36.816 63.048 36.84 ;
    END
  END di0[351]
  PIN di0[352]
    DIRECTION INPUT ;
    USE SIGNAL ;
    PORT
      LAYER M4 ;
        RECT  62.856 36.864 63.048 36.888 ;
    END
  END di0[352]
  PIN di0[353]
    DIRECTION INPUT ;
    USE SIGNAL ;
    PORT
      LAYER M4 ;
        RECT  62.856 36.912 63.048 36.936 ;
    END
  END di0[353]
  PIN di0[354]
    DIRECTION INPUT ;
    USE SIGNAL ;
    PORT
      LAYER M4 ;
        RECT  62.856 36.96 63.048 36.984 ;
    END
  END di0[354]
  PIN di0[355]
    DIRECTION INPUT ;
    USE SIGNAL ;
    PORT
      LAYER M4 ;
        RECT  62.856 37.008 63.048 37.032 ;
    END
  END di0[355]
  PIN di0[356]
    DIRECTION INPUT ;
    USE SIGNAL ;
    PORT
      LAYER M4 ;
        RECT  62.856 37.056 63.048 37.08 ;
    END
  END di0[356]
  PIN di0[357]
    DIRECTION INPUT ;
    USE SIGNAL ;
    PORT
      LAYER M4 ;
        RECT  62.856 37.104 63.048 37.128 ;
    END
  END di0[357]
  PIN di0[358]
    DIRECTION INPUT ;
    USE SIGNAL ;
    PORT
      LAYER M4 ;
        RECT  62.856 37.152 63.048 37.176 ;
    END
  END di0[358]
  PIN di0[359]
    DIRECTION INPUT ;
    USE SIGNAL ;
    PORT
      LAYER M4 ;
        RECT  62.856 37.2 63.048 37.224 ;
    END
  END di0[359]
  PIN di0[35]
    DIRECTION INPUT ;
    USE SIGNAL ;
    PORT
      LAYER M4 ;
        RECT  62.856 21.648 63.048 21.672 ;
    END
  END di0[35]
  PIN di0[360]
    DIRECTION INPUT ;
    USE SIGNAL ;
    PORT
      LAYER M4 ;
        RECT  62.856 37.248 63.048 37.272 ;
    END
  END di0[360]
  PIN di0[361]
    DIRECTION INPUT ;
    USE SIGNAL ;
    PORT
      LAYER M4 ;
        RECT  62.856 37.296 63.048 37.32 ;
    END
  END di0[361]
  PIN di0[362]
    DIRECTION INPUT ;
    USE SIGNAL ;
    PORT
      LAYER M4 ;
        RECT  62.856 37.344 63.048 37.368 ;
    END
  END di0[362]
  PIN di0[363]
    DIRECTION INPUT ;
    USE SIGNAL ;
    PORT
      LAYER M4 ;
        RECT  62.856 37.392 63.048 37.416 ;
    END
  END di0[363]
  PIN di0[364]
    DIRECTION INPUT ;
    USE SIGNAL ;
    PORT
      LAYER M4 ;
        RECT  62.856 37.44 63.048 37.464 ;
    END
  END di0[364]
  PIN di0[365]
    DIRECTION INPUT ;
    USE SIGNAL ;
    PORT
      LAYER M4 ;
        RECT  62.856 37.488 63.048 37.512 ;
    END
  END di0[365]
  PIN di0[366]
    DIRECTION INPUT ;
    USE SIGNAL ;
    PORT
      LAYER M4 ;
        RECT  62.856 37.536 63.048 37.56 ;
    END
  END di0[366]
  PIN di0[367]
    DIRECTION INPUT ;
    USE SIGNAL ;
    PORT
      LAYER M4 ;
        RECT  62.856 37.584 63.048 37.608 ;
    END
  END di0[367]
  PIN di0[368]
    DIRECTION INPUT ;
    USE SIGNAL ;
    PORT
      LAYER M4 ;
        RECT  62.856 37.632 63.048 37.656 ;
    END
  END di0[368]
  PIN di0[369]
    DIRECTION INPUT ;
    USE SIGNAL ;
    PORT
      LAYER M4 ;
        RECT  62.856 37.68 63.048 37.704 ;
    END
  END di0[369]
  PIN di0[36]
    DIRECTION INPUT ;
    USE SIGNAL ;
    PORT
      LAYER M4 ;
        RECT  62.856 21.696 63.048 21.72 ;
    END
  END di0[36]
  PIN di0[370]
    DIRECTION INPUT ;
    USE SIGNAL ;
    PORT
      LAYER M4 ;
        RECT  62.856 37.728 63.048 37.752 ;
    END
  END di0[370]
  PIN di0[371]
    DIRECTION INPUT ;
    USE SIGNAL ;
    PORT
      LAYER M4 ;
        RECT  62.856 37.776 63.048 37.8 ;
    END
  END di0[371]
  PIN di0[372]
    DIRECTION INPUT ;
    USE SIGNAL ;
    PORT
      LAYER M4 ;
        RECT  62.856 37.824 63.048 37.848 ;
    END
  END di0[372]
  PIN di0[373]
    DIRECTION INPUT ;
    USE SIGNAL ;
    PORT
      LAYER M4 ;
        RECT  62.856 37.872 63.048 37.896 ;
    END
  END di0[373]
  PIN di0[374]
    DIRECTION INPUT ;
    USE SIGNAL ;
    PORT
      LAYER M4 ;
        RECT  62.856 37.92 63.048 37.944 ;
    END
  END di0[374]
  PIN di0[375]
    DIRECTION INPUT ;
    USE SIGNAL ;
    PORT
      LAYER M4 ;
        RECT  62.856 37.968 63.048 37.992 ;
    END
  END di0[375]
  PIN di0[376]
    DIRECTION INPUT ;
    USE SIGNAL ;
    PORT
      LAYER M4 ;
        RECT  62.856 38.016 63.048 38.04 ;
    END
  END di0[376]
  PIN di0[377]
    DIRECTION INPUT ;
    USE SIGNAL ;
    PORT
      LAYER M4 ;
        RECT  62.856 38.064 63.048 38.088 ;
    END
  END di0[377]
  PIN di0[378]
    DIRECTION INPUT ;
    USE SIGNAL ;
    PORT
      LAYER M4 ;
        RECT  62.856 38.112 63.048 38.136 ;
    END
  END di0[378]
  PIN di0[379]
    DIRECTION INPUT ;
    USE SIGNAL ;
    PORT
      LAYER M4 ;
        RECT  62.856 38.16 63.048 38.184 ;
    END
  END di0[379]
  PIN di0[37]
    DIRECTION INPUT ;
    USE SIGNAL ;
    PORT
      LAYER M4 ;
        RECT  62.856 21.744 63.048 21.768 ;
    END
  END di0[37]
  PIN di0[380]
    DIRECTION INPUT ;
    USE SIGNAL ;
    PORT
      LAYER M4 ;
        RECT  62.856 38.208 63.048 38.232 ;
    END
  END di0[380]
  PIN di0[381]
    DIRECTION INPUT ;
    USE SIGNAL ;
    PORT
      LAYER M4 ;
        RECT  62.856 38.256 63.048 38.28 ;
    END
  END di0[381]
  PIN di0[382]
    DIRECTION INPUT ;
    USE SIGNAL ;
    PORT
      LAYER M4 ;
        RECT  62.856 38.304 63.048 38.328 ;
    END
  END di0[382]
  PIN di0[383]
    DIRECTION INPUT ;
    USE SIGNAL ;
    PORT
      LAYER M4 ;
        RECT  62.856 38.352 63.048 38.376 ;
    END
  END di0[383]
  PIN di0[384]
    DIRECTION INPUT ;
    USE SIGNAL ;
    PORT
      LAYER M4 ;
        RECT  62.856 38.4 63.048 38.424 ;
    END
  END di0[384]
  PIN di0[385]
    DIRECTION INPUT ;
    USE SIGNAL ;
    PORT
      LAYER M4 ;
        RECT  62.856 38.448 63.048 38.472 ;
    END
  END di0[385]
  PIN di0[386]
    DIRECTION INPUT ;
    USE SIGNAL ;
    PORT
      LAYER M4 ;
        RECT  62.856 38.496 63.048 38.52 ;
    END
  END di0[386]
  PIN di0[387]
    DIRECTION INPUT ;
    USE SIGNAL ;
    PORT
      LAYER M4 ;
        RECT  62.856 38.544 63.048 38.568 ;
    END
  END di0[387]
  PIN di0[388]
    DIRECTION INPUT ;
    USE SIGNAL ;
    PORT
      LAYER M4 ;
        RECT  62.856 38.592 63.048 38.616 ;
    END
  END di0[388]
  PIN di0[389]
    DIRECTION INPUT ;
    USE SIGNAL ;
    PORT
      LAYER M4 ;
        RECT  62.856 38.64 63.048 38.664 ;
    END
  END di0[389]
  PIN di0[38]
    DIRECTION INPUT ;
    USE SIGNAL ;
    PORT
      LAYER M4 ;
        RECT  62.856 21.792 63.048 21.816 ;
    END
  END di0[38]
  PIN di0[390]
    DIRECTION INPUT ;
    USE SIGNAL ;
    PORT
      LAYER M4 ;
        RECT  62.856 38.688 63.048 38.712 ;
    END
  END di0[390]
  PIN di0[391]
    DIRECTION INPUT ;
    USE SIGNAL ;
    PORT
      LAYER M4 ;
        RECT  62.856 38.736 63.048 38.76 ;
    END
  END di0[391]
  PIN di0[392]
    DIRECTION INPUT ;
    USE SIGNAL ;
    PORT
      LAYER M4 ;
        RECT  62.856 38.784 63.048 38.808 ;
    END
  END di0[392]
  PIN di0[393]
    DIRECTION INPUT ;
    USE SIGNAL ;
    PORT
      LAYER M4 ;
        RECT  62.856 38.832 63.048 38.856 ;
    END
  END di0[393]
  PIN di0[394]
    DIRECTION INPUT ;
    USE SIGNAL ;
    PORT
      LAYER M4 ;
        RECT  62.856 38.88 63.048 38.904 ;
    END
  END di0[394]
  PIN di0[395]
    DIRECTION INPUT ;
    USE SIGNAL ;
    PORT
      LAYER M4 ;
        RECT  62.856 38.928 63.048 38.952 ;
    END
  END di0[395]
  PIN di0[396]
    DIRECTION INPUT ;
    USE SIGNAL ;
    PORT
      LAYER M4 ;
        RECT  62.856 38.976 63.048 39 ;
    END
  END di0[396]
  PIN di0[397]
    DIRECTION INPUT ;
    USE SIGNAL ;
    PORT
      LAYER M4 ;
        RECT  62.856 39.024 63.048 39.048 ;
    END
  END di0[397]
  PIN di0[398]
    DIRECTION INPUT ;
    USE SIGNAL ;
    PORT
      LAYER M4 ;
        RECT  62.856 39.072 63.048 39.096 ;
    END
  END di0[398]
  PIN di0[399]
    DIRECTION INPUT ;
    USE SIGNAL ;
    PORT
      LAYER M4 ;
        RECT  62.856 39.12 63.048 39.144 ;
    END
  END di0[399]
  PIN di0[39]
    DIRECTION INPUT ;
    USE SIGNAL ;
    PORT
      LAYER M4 ;
        RECT  62.856 21.84 63.048 21.864 ;
    END
  END di0[39]
  PIN di0[3]
    DIRECTION INPUT ;
    USE SIGNAL ;
    PORT
      LAYER M4 ;
        RECT  62.856 20.112 63.048 20.136 ;
    END
  END di0[3]
  PIN di0[400]
    DIRECTION INPUT ;
    USE SIGNAL ;
    PORT
      LAYER M4 ;
        RECT  62.856 39.168 63.048 39.192 ;
    END
  END di0[400]
  PIN di0[401]
    DIRECTION INPUT ;
    USE SIGNAL ;
    PORT
      LAYER M4 ;
        RECT  62.856 39.216 63.048 39.24 ;
    END
  END di0[401]
  PIN di0[402]
    DIRECTION INPUT ;
    USE SIGNAL ;
    PORT
      LAYER M4 ;
        RECT  62.856 39.264 63.048 39.288 ;
    END
  END di0[402]
  PIN di0[403]
    DIRECTION INPUT ;
    USE SIGNAL ;
    PORT
      LAYER M4 ;
        RECT  62.856 39.312 63.048 39.336 ;
    END
  END di0[403]
  PIN di0[404]
    DIRECTION INPUT ;
    USE SIGNAL ;
    PORT
      LAYER M4 ;
        RECT  62.856 39.36 63.048 39.384 ;
    END
  END di0[404]
  PIN di0[405]
    DIRECTION INPUT ;
    USE SIGNAL ;
    PORT
      LAYER M4 ;
        RECT  62.856 39.408 63.048 39.432 ;
    END
  END di0[405]
  PIN di0[406]
    DIRECTION INPUT ;
    USE SIGNAL ;
    PORT
      LAYER M4 ;
        RECT  62.856 39.456 63.048 39.48 ;
    END
  END di0[406]
  PIN di0[407]
    DIRECTION INPUT ;
    USE SIGNAL ;
    PORT
      LAYER M4 ;
        RECT  62.856 39.504 63.048 39.528 ;
    END
  END di0[407]
  PIN di0[408]
    DIRECTION INPUT ;
    USE SIGNAL ;
    PORT
      LAYER M4 ;
        RECT  62.856 39.552 63.048 39.576 ;
    END
  END di0[408]
  PIN di0[409]
    DIRECTION INPUT ;
    USE SIGNAL ;
    PORT
      LAYER M4 ;
        RECT  62.856 39.6 63.048 39.624 ;
    END
  END di0[409]
  PIN di0[40]
    DIRECTION INPUT ;
    USE SIGNAL ;
    PORT
      LAYER M4 ;
        RECT  62.856 21.888 63.048 21.912 ;
    END
  END di0[40]
  PIN di0[410]
    DIRECTION INPUT ;
    USE SIGNAL ;
    PORT
      LAYER M4 ;
        RECT  62.856 39.648 63.048 39.672 ;
    END
  END di0[410]
  PIN di0[411]
    DIRECTION INPUT ;
    USE SIGNAL ;
    PORT
      LAYER M4 ;
        RECT  62.856 39.696 63.048 39.72 ;
    END
  END di0[411]
  PIN di0[412]
    DIRECTION INPUT ;
    USE SIGNAL ;
    PORT
      LAYER M4 ;
        RECT  62.856 39.744 63.048 39.768 ;
    END
  END di0[412]
  PIN di0[413]
    DIRECTION INPUT ;
    USE SIGNAL ;
    PORT
      LAYER M4 ;
        RECT  62.856 39.792 63.048 39.816 ;
    END
  END di0[413]
  PIN di0[414]
    DIRECTION INPUT ;
    USE SIGNAL ;
    PORT
      LAYER M4 ;
        RECT  62.856 39.84 63.048 39.864 ;
    END
  END di0[414]
  PIN di0[415]
    DIRECTION INPUT ;
    USE SIGNAL ;
    PORT
      LAYER M4 ;
        RECT  62.856 39.888 63.048 39.912 ;
    END
  END di0[415]
  PIN di0[416]
    DIRECTION INPUT ;
    USE SIGNAL ;
    PORT
      LAYER M4 ;
        RECT  62.856 39.936 63.048 39.96 ;
    END
  END di0[416]
  PIN di0[417]
    DIRECTION INPUT ;
    USE SIGNAL ;
    PORT
      LAYER M4 ;
        RECT  62.856 39.984 63.048 40.008 ;
    END
  END di0[417]
  PIN di0[418]
    DIRECTION INPUT ;
    USE SIGNAL ;
    PORT
      LAYER M4 ;
        RECT  62.856 40.032 63.048 40.056 ;
    END
  END di0[418]
  PIN di0[419]
    DIRECTION INPUT ;
    USE SIGNAL ;
    PORT
      LAYER M4 ;
        RECT  62.856 40.08 63.048 40.104 ;
    END
  END di0[419]
  PIN di0[41]
    DIRECTION INPUT ;
    USE SIGNAL ;
    PORT
      LAYER M4 ;
        RECT  62.856 21.936 63.048 21.96 ;
    END
  END di0[41]
  PIN di0[420]
    DIRECTION INPUT ;
    USE SIGNAL ;
    PORT
      LAYER M4 ;
        RECT  62.856 40.128 63.048 40.152 ;
    END
  END di0[420]
  PIN di0[421]
    DIRECTION INPUT ;
    USE SIGNAL ;
    PORT
      LAYER M4 ;
        RECT  62.856 40.176 63.048 40.2 ;
    END
  END di0[421]
  PIN di0[422]
    DIRECTION INPUT ;
    USE SIGNAL ;
    PORT
      LAYER M4 ;
        RECT  62.856 40.224 63.048 40.248 ;
    END
  END di0[422]
  PIN di0[423]
    DIRECTION INPUT ;
    USE SIGNAL ;
    PORT
      LAYER M4 ;
        RECT  62.856 40.272 63.048 40.296 ;
    END
  END di0[423]
  PIN di0[424]
    DIRECTION INPUT ;
    USE SIGNAL ;
    PORT
      LAYER M4 ;
        RECT  62.856 40.32 63.048 40.344 ;
    END
  END di0[424]
  PIN di0[425]
    DIRECTION INPUT ;
    USE SIGNAL ;
    PORT
      LAYER M4 ;
        RECT  62.856 40.368 63.048 40.392 ;
    END
  END di0[425]
  PIN di0[426]
    DIRECTION INPUT ;
    USE SIGNAL ;
    PORT
      LAYER M4 ;
        RECT  62.856 40.416 63.048 40.44 ;
    END
  END di0[426]
  PIN di0[427]
    DIRECTION INPUT ;
    USE SIGNAL ;
    PORT
      LAYER M4 ;
        RECT  62.856 40.464 63.048 40.488 ;
    END
  END di0[427]
  PIN di0[428]
    DIRECTION INPUT ;
    USE SIGNAL ;
    PORT
      LAYER M4 ;
        RECT  62.856 40.512 63.048 40.536 ;
    END
  END di0[428]
  PIN di0[429]
    DIRECTION INPUT ;
    USE SIGNAL ;
    PORT
      LAYER M4 ;
        RECT  62.856 40.56 63.048 40.584 ;
    END
  END di0[429]
  PIN di0[42]
    DIRECTION INPUT ;
    USE SIGNAL ;
    PORT
      LAYER M4 ;
        RECT  62.856 21.984 63.048 22.008 ;
    END
  END di0[42]
  PIN di0[430]
    DIRECTION INPUT ;
    USE SIGNAL ;
    PORT
      LAYER M4 ;
        RECT  62.856 40.608 63.048 40.632 ;
    END
  END di0[430]
  PIN di0[431]
    DIRECTION INPUT ;
    USE SIGNAL ;
    PORT
      LAYER M4 ;
        RECT  62.856 40.656 63.048 40.68 ;
    END
  END di0[431]
  PIN di0[432]
    DIRECTION INPUT ;
    USE SIGNAL ;
    PORT
      LAYER M4 ;
        RECT  62.856 40.704 63.048 40.728 ;
    END
  END di0[432]
  PIN di0[433]
    DIRECTION INPUT ;
    USE SIGNAL ;
    PORT
      LAYER M4 ;
        RECT  62.856 40.752 63.048 40.776 ;
    END
  END di0[433]
  PIN di0[434]
    DIRECTION INPUT ;
    USE SIGNAL ;
    PORT
      LAYER M4 ;
        RECT  62.856 40.8 63.048 40.824 ;
    END
  END di0[434]
  PIN di0[435]
    DIRECTION INPUT ;
    USE SIGNAL ;
    PORT
      LAYER M4 ;
        RECT  62.856 40.848 63.048 40.872 ;
    END
  END di0[435]
  PIN di0[436]
    DIRECTION INPUT ;
    USE SIGNAL ;
    PORT
      LAYER M4 ;
        RECT  62.856 40.896 63.048 40.92 ;
    END
  END di0[436]
  PIN di0[437]
    DIRECTION INPUT ;
    USE SIGNAL ;
    PORT
      LAYER M4 ;
        RECT  62.856 40.944 63.048 40.968 ;
    END
  END di0[437]
  PIN di0[438]
    DIRECTION INPUT ;
    USE SIGNAL ;
    PORT
      LAYER M4 ;
        RECT  62.856 40.992 63.048 41.016 ;
    END
  END di0[438]
  PIN di0[439]
    DIRECTION INPUT ;
    USE SIGNAL ;
    PORT
      LAYER M4 ;
        RECT  62.856 41.04 63.048 41.064 ;
    END
  END di0[439]
  PIN di0[43]
    DIRECTION INPUT ;
    USE SIGNAL ;
    PORT
      LAYER M4 ;
        RECT  62.856 22.032 63.048 22.056 ;
    END
  END di0[43]
  PIN di0[440]
    DIRECTION INPUT ;
    USE SIGNAL ;
    PORT
      LAYER M4 ;
        RECT  62.856 41.088 63.048 41.112 ;
    END
  END di0[440]
  PIN di0[441]
    DIRECTION INPUT ;
    USE SIGNAL ;
    PORT
      LAYER M4 ;
        RECT  62.856 41.136 63.048 41.16 ;
    END
  END di0[441]
  PIN di0[442]
    DIRECTION INPUT ;
    USE SIGNAL ;
    PORT
      LAYER M4 ;
        RECT  62.856 41.184 63.048 41.208 ;
    END
  END di0[442]
  PIN di0[443]
    DIRECTION INPUT ;
    USE SIGNAL ;
    PORT
      LAYER M4 ;
        RECT  62.856 41.232 63.048 41.256 ;
    END
  END di0[443]
  PIN di0[444]
    DIRECTION INPUT ;
    USE SIGNAL ;
    PORT
      LAYER M4 ;
        RECT  62.856 41.28 63.048 41.304 ;
    END
  END di0[444]
  PIN di0[445]
    DIRECTION INPUT ;
    USE SIGNAL ;
    PORT
      LAYER M4 ;
        RECT  62.856 41.328 63.048 41.352 ;
    END
  END di0[445]
  PIN di0[446]
    DIRECTION INPUT ;
    USE SIGNAL ;
    PORT
      LAYER M4 ;
        RECT  62.856 41.376 63.048 41.4 ;
    END
  END di0[446]
  PIN di0[447]
    DIRECTION INPUT ;
    USE SIGNAL ;
    PORT
      LAYER M4 ;
        RECT  62.856 41.424 63.048 41.448 ;
    END
  END di0[447]
  PIN di0[448]
    DIRECTION INPUT ;
    USE SIGNAL ;
    PORT
      LAYER M4 ;
        RECT  62.856 41.472 63.048 41.496 ;
    END
  END di0[448]
  PIN di0[449]
    DIRECTION INPUT ;
    USE SIGNAL ;
    PORT
      LAYER M4 ;
        RECT  62.856 41.52 63.048 41.544 ;
    END
  END di0[449]
  PIN di0[44]
    DIRECTION INPUT ;
    USE SIGNAL ;
    PORT
      LAYER M4 ;
        RECT  62.856 22.08 63.048 22.104 ;
    END
  END di0[44]
  PIN di0[450]
    DIRECTION INPUT ;
    USE SIGNAL ;
    PORT
      LAYER M4 ;
        RECT  62.856 41.568 63.048 41.592 ;
    END
  END di0[450]
  PIN di0[451]
    DIRECTION INPUT ;
    USE SIGNAL ;
    PORT
      LAYER M4 ;
        RECT  62.856 41.616 63.048 41.64 ;
    END
  END di0[451]
  PIN di0[452]
    DIRECTION INPUT ;
    USE SIGNAL ;
    PORT
      LAYER M4 ;
        RECT  62.856 41.664 63.048 41.688 ;
    END
  END di0[452]
  PIN di0[453]
    DIRECTION INPUT ;
    USE SIGNAL ;
    PORT
      LAYER M4 ;
        RECT  62.856 41.712 63.048 41.736 ;
    END
  END di0[453]
  PIN di0[454]
    DIRECTION INPUT ;
    USE SIGNAL ;
    PORT
      LAYER M4 ;
        RECT  62.856 41.76 63.048 41.784 ;
    END
  END di0[454]
  PIN di0[455]
    DIRECTION INPUT ;
    USE SIGNAL ;
    PORT
      LAYER M4 ;
        RECT  62.856 41.808 63.048 41.832 ;
    END
  END di0[455]
  PIN di0[456]
    DIRECTION INPUT ;
    USE SIGNAL ;
    PORT
      LAYER M4 ;
        RECT  62.856 41.856 63.048 41.88 ;
    END
  END di0[456]
  PIN di0[457]
    DIRECTION INPUT ;
    USE SIGNAL ;
    PORT
      LAYER M4 ;
        RECT  62.856 41.904 63.048 41.928 ;
    END
  END di0[457]
  PIN di0[458]
    DIRECTION INPUT ;
    USE SIGNAL ;
    PORT
      LAYER M4 ;
        RECT  62.856 41.952 63.048 41.976 ;
    END
  END di0[458]
  PIN di0[459]
    DIRECTION INPUT ;
    USE SIGNAL ;
    PORT
      LAYER M4 ;
        RECT  62.856 42 63.048 42.024 ;
    END
  END di0[459]
  PIN di0[45]
    DIRECTION INPUT ;
    USE SIGNAL ;
    PORT
      LAYER M4 ;
        RECT  62.856 22.128 63.048 22.152 ;
    END
  END di0[45]
  PIN di0[460]
    DIRECTION INPUT ;
    USE SIGNAL ;
    PORT
      LAYER M4 ;
        RECT  62.856 42.048 63.048 42.072 ;
    END
  END di0[460]
  PIN di0[461]
    DIRECTION INPUT ;
    USE SIGNAL ;
    PORT
      LAYER M4 ;
        RECT  62.856 42.096 63.048 42.12 ;
    END
  END di0[461]
  PIN di0[462]
    DIRECTION INPUT ;
    USE SIGNAL ;
    PORT
      LAYER M4 ;
        RECT  62.856 42.144 63.048 42.168 ;
    END
  END di0[462]
  PIN di0[463]
    DIRECTION INPUT ;
    USE SIGNAL ;
    PORT
      LAYER M4 ;
        RECT  62.856 42.192 63.048 42.216 ;
    END
  END di0[463]
  PIN di0[464]
    DIRECTION INPUT ;
    USE SIGNAL ;
    PORT
      LAYER M4 ;
        RECT  62.856 42.24 63.048 42.264 ;
    END
  END di0[464]
  PIN di0[465]
    DIRECTION INPUT ;
    USE SIGNAL ;
    PORT
      LAYER M4 ;
        RECT  62.856 42.288 63.048 42.312 ;
    END
  END di0[465]
  PIN di0[466]
    DIRECTION INPUT ;
    USE SIGNAL ;
    PORT
      LAYER M4 ;
        RECT  62.856 42.336 63.048 42.36 ;
    END
  END di0[466]
  PIN di0[467]
    DIRECTION INPUT ;
    USE SIGNAL ;
    PORT
      LAYER M4 ;
        RECT  62.856 42.384 63.048 42.408 ;
    END
  END di0[467]
  PIN di0[468]
    DIRECTION INPUT ;
    USE SIGNAL ;
    PORT
      LAYER M4 ;
        RECT  62.856 42.432 63.048 42.456 ;
    END
  END di0[468]
  PIN di0[469]
    DIRECTION INPUT ;
    USE SIGNAL ;
    PORT
      LAYER M4 ;
        RECT  62.856 42.48 63.048 42.504 ;
    END
  END di0[469]
  PIN di0[46]
    DIRECTION INPUT ;
    USE SIGNAL ;
    PORT
      LAYER M4 ;
        RECT  62.856 22.176 63.048 22.2 ;
    END
  END di0[46]
  PIN di0[470]
    DIRECTION INPUT ;
    USE SIGNAL ;
    PORT
      LAYER M4 ;
        RECT  62.856 42.528 63.048 42.552 ;
    END
  END di0[470]
  PIN di0[471]
    DIRECTION INPUT ;
    USE SIGNAL ;
    PORT
      LAYER M4 ;
        RECT  62.856 42.576 63.048 42.6 ;
    END
  END di0[471]
  PIN di0[472]
    DIRECTION INPUT ;
    USE SIGNAL ;
    PORT
      LAYER M4 ;
        RECT  62.856 42.624 63.048 42.648 ;
    END
  END di0[472]
  PIN di0[473]
    DIRECTION INPUT ;
    USE SIGNAL ;
    PORT
      LAYER M4 ;
        RECT  62.856 42.672 63.048 42.696 ;
    END
  END di0[473]
  PIN di0[474]
    DIRECTION INPUT ;
    USE SIGNAL ;
    PORT
      LAYER M4 ;
        RECT  62.856 42.72 63.048 42.744 ;
    END
  END di0[474]
  PIN di0[475]
    DIRECTION INPUT ;
    USE SIGNAL ;
    PORT
      LAYER M4 ;
        RECT  62.856 42.768 63.048 42.792 ;
    END
  END di0[475]
  PIN di0[476]
    DIRECTION INPUT ;
    USE SIGNAL ;
    PORT
      LAYER M4 ;
        RECT  62.856 42.816 63.048 42.84 ;
    END
  END di0[476]
  PIN di0[477]
    DIRECTION INPUT ;
    USE SIGNAL ;
    PORT
      LAYER M4 ;
        RECT  62.856 42.864 63.048 42.888 ;
    END
  END di0[477]
  PIN di0[478]
    DIRECTION INPUT ;
    USE SIGNAL ;
    PORT
      LAYER M4 ;
        RECT  62.856 42.912 63.048 42.936 ;
    END
  END di0[478]
  PIN di0[479]
    DIRECTION INPUT ;
    USE SIGNAL ;
    PORT
      LAYER M4 ;
        RECT  62.856 42.96 63.048 42.984 ;
    END
  END di0[479]
  PIN di0[47]
    DIRECTION INPUT ;
    USE SIGNAL ;
    PORT
      LAYER M4 ;
        RECT  62.856 22.224 63.048 22.248 ;
    END
  END di0[47]
  PIN di0[480]
    DIRECTION INPUT ;
    USE SIGNAL ;
    PORT
      LAYER M4 ;
        RECT  62.856 43.008 63.048 43.032 ;
    END
  END di0[480]
  PIN di0[481]
    DIRECTION INPUT ;
    USE SIGNAL ;
    PORT
      LAYER M4 ;
        RECT  62.856 43.056 63.048 43.08 ;
    END
  END di0[481]
  PIN di0[482]
    DIRECTION INPUT ;
    USE SIGNAL ;
    PORT
      LAYER M4 ;
        RECT  62.856 43.104 63.048 43.128 ;
    END
  END di0[482]
  PIN di0[483]
    DIRECTION INPUT ;
    USE SIGNAL ;
    PORT
      LAYER M4 ;
        RECT  62.856 43.152 63.048 43.176 ;
    END
  END di0[483]
  PIN di0[484]
    DIRECTION INPUT ;
    USE SIGNAL ;
    PORT
      LAYER M4 ;
        RECT  62.856 43.2 63.048 43.224 ;
    END
  END di0[484]
  PIN di0[485]
    DIRECTION INPUT ;
    USE SIGNAL ;
    PORT
      LAYER M4 ;
        RECT  62.856 43.248 63.048 43.272 ;
    END
  END di0[485]
  PIN di0[486]
    DIRECTION INPUT ;
    USE SIGNAL ;
    PORT
      LAYER M4 ;
        RECT  62.856 43.296 63.048 43.32 ;
    END
  END di0[486]
  PIN di0[487]
    DIRECTION INPUT ;
    USE SIGNAL ;
    PORT
      LAYER M4 ;
        RECT  62.856 43.344 63.048 43.368 ;
    END
  END di0[487]
  PIN di0[488]
    DIRECTION INPUT ;
    USE SIGNAL ;
    PORT
      LAYER M4 ;
        RECT  62.856 43.392 63.048 43.416 ;
    END
  END di0[488]
  PIN di0[489]
    DIRECTION INPUT ;
    USE SIGNAL ;
    PORT
      LAYER M4 ;
        RECT  62.856 43.44 63.048 43.464 ;
    END
  END di0[489]
  PIN di0[48]
    DIRECTION INPUT ;
    USE SIGNAL ;
    PORT
      LAYER M4 ;
        RECT  62.856 22.272 63.048 22.296 ;
    END
  END di0[48]
  PIN di0[490]
    DIRECTION INPUT ;
    USE SIGNAL ;
    PORT
      LAYER M4 ;
        RECT  62.856 43.488 63.048 43.512 ;
    END
  END di0[490]
  PIN di0[491]
    DIRECTION INPUT ;
    USE SIGNAL ;
    PORT
      LAYER M4 ;
        RECT  62.856 43.536 63.048 43.56 ;
    END
  END di0[491]
  PIN di0[492]
    DIRECTION INPUT ;
    USE SIGNAL ;
    PORT
      LAYER M4 ;
        RECT  62.856 43.584 63.048 43.608 ;
    END
  END di0[492]
  PIN di0[493]
    DIRECTION INPUT ;
    USE SIGNAL ;
    PORT
      LAYER M4 ;
        RECT  62.856 43.632 63.048 43.656 ;
    END
  END di0[493]
  PIN di0[494]
    DIRECTION INPUT ;
    USE SIGNAL ;
    PORT
      LAYER M4 ;
        RECT  62.856 43.68 63.048 43.704 ;
    END
  END di0[494]
  PIN di0[495]
    DIRECTION INPUT ;
    USE SIGNAL ;
    PORT
      LAYER M4 ;
        RECT  62.856 43.728 63.048 43.752 ;
    END
  END di0[495]
  PIN di0[496]
    DIRECTION INPUT ;
    USE SIGNAL ;
    PORT
      LAYER M4 ;
        RECT  62.856 43.776 63.048 43.8 ;
    END
  END di0[496]
  PIN di0[497]
    DIRECTION INPUT ;
    USE SIGNAL ;
    PORT
      LAYER M4 ;
        RECT  62.856 43.824 63.048 43.848 ;
    END
  END di0[497]
  PIN di0[498]
    DIRECTION INPUT ;
    USE SIGNAL ;
    PORT
      LAYER M4 ;
        RECT  62.856 43.872 63.048 43.896 ;
    END
  END di0[498]
  PIN di0[499]
    DIRECTION INPUT ;
    USE SIGNAL ;
    PORT
      LAYER M4 ;
        RECT  62.856 43.92 63.048 43.944 ;
    END
  END di0[499]
  PIN di0[49]
    DIRECTION INPUT ;
    USE SIGNAL ;
    PORT
      LAYER M4 ;
        RECT  62.856 22.32 63.048 22.344 ;
    END
  END di0[49]
  PIN di0[4]
    DIRECTION INPUT ;
    USE SIGNAL ;
    PORT
      LAYER M4 ;
        RECT  62.856 20.16 63.048 20.184 ;
    END
  END di0[4]
  PIN di0[500]
    DIRECTION INPUT ;
    USE SIGNAL ;
    PORT
      LAYER M4 ;
        RECT  62.856 43.968 63.048 43.992 ;
    END
  END di0[500]
  PIN di0[501]
    DIRECTION INPUT ;
    USE SIGNAL ;
    PORT
      LAYER M4 ;
        RECT  62.856 44.016 63.048 44.04 ;
    END
  END di0[501]
  PIN di0[502]
    DIRECTION INPUT ;
    USE SIGNAL ;
    PORT
      LAYER M4 ;
        RECT  62.856 44.064 63.048 44.088 ;
    END
  END di0[502]
  PIN di0[503]
    DIRECTION INPUT ;
    USE SIGNAL ;
    PORT
      LAYER M4 ;
        RECT  62.856 44.112 63.048 44.136 ;
    END
  END di0[503]
  PIN di0[504]
    DIRECTION INPUT ;
    USE SIGNAL ;
    PORT
      LAYER M4 ;
        RECT  62.856 44.16 63.048 44.184 ;
    END
  END di0[504]
  PIN di0[505]
    DIRECTION INPUT ;
    USE SIGNAL ;
    PORT
      LAYER M4 ;
        RECT  62.856 44.208 63.048 44.232 ;
    END
  END di0[505]
  PIN di0[506]
    DIRECTION INPUT ;
    USE SIGNAL ;
    PORT
      LAYER M4 ;
        RECT  62.856 44.256 63.048 44.28 ;
    END
  END di0[506]
  PIN di0[507]
    DIRECTION INPUT ;
    USE SIGNAL ;
    PORT
      LAYER M4 ;
        RECT  62.856 44.304 63.048 44.328 ;
    END
  END di0[507]
  PIN di0[508]
    DIRECTION INPUT ;
    USE SIGNAL ;
    PORT
      LAYER M4 ;
        RECT  62.856 44.352 63.048 44.376 ;
    END
  END di0[508]
  PIN di0[509]
    DIRECTION INPUT ;
    USE SIGNAL ;
    PORT
      LAYER M4 ;
        RECT  62.856 44.4 63.048 44.424 ;
    END
  END di0[509]
  PIN di0[50]
    DIRECTION INPUT ;
    USE SIGNAL ;
    PORT
      LAYER M4 ;
        RECT  62.856 22.368 63.048 22.392 ;
    END
  END di0[50]
  PIN di0[510]
    DIRECTION INPUT ;
    USE SIGNAL ;
    PORT
      LAYER M4 ;
        RECT  62.856 44.448 63.048 44.472 ;
    END
  END di0[510]
  PIN di0[511]
    DIRECTION INPUT ;
    USE SIGNAL ;
    PORT
      LAYER M4 ;
        RECT  62.856 44.496 63.048 44.52 ;
    END
  END di0[511]
  PIN di0[512]
    DIRECTION INPUT ;
    USE SIGNAL ;
    PORT
      LAYER M4 ;
        RECT  62.856 44.544 63.048 44.568 ;
    END
  END di0[512]
  PIN di0[513]
    DIRECTION INPUT ;
    USE SIGNAL ;
    PORT
      LAYER M4 ;
        RECT  62.856 44.592 63.048 44.616 ;
    END
  END di0[513]
  PIN di0[51]
    DIRECTION INPUT ;
    USE SIGNAL ;
    PORT
      LAYER M4 ;
        RECT  62.856 22.416 63.048 22.44 ;
    END
  END di0[51]
  PIN di0[52]
    DIRECTION INPUT ;
    USE SIGNAL ;
    PORT
      LAYER M4 ;
        RECT  62.856 22.464 63.048 22.488 ;
    END
  END di0[52]
  PIN di0[53]
    DIRECTION INPUT ;
    USE SIGNAL ;
    PORT
      LAYER M4 ;
        RECT  62.856 22.512 63.048 22.536 ;
    END
  END di0[53]
  PIN di0[54]
    DIRECTION INPUT ;
    USE SIGNAL ;
    PORT
      LAYER M4 ;
        RECT  62.856 22.56 63.048 22.584 ;
    END
  END di0[54]
  PIN di0[55]
    DIRECTION INPUT ;
    USE SIGNAL ;
    PORT
      LAYER M4 ;
        RECT  62.856 22.608 63.048 22.632 ;
    END
  END di0[55]
  PIN di0[56]
    DIRECTION INPUT ;
    USE SIGNAL ;
    PORT
      LAYER M4 ;
        RECT  62.856 22.656 63.048 22.68 ;
    END
  END di0[56]
  PIN di0[57]
    DIRECTION INPUT ;
    USE SIGNAL ;
    PORT
      LAYER M4 ;
        RECT  62.856 22.704 63.048 22.728 ;
    END
  END di0[57]
  PIN di0[58]
    DIRECTION INPUT ;
    USE SIGNAL ;
    PORT
      LAYER M4 ;
        RECT  62.856 22.752 63.048 22.776 ;
    END
  END di0[58]
  PIN di0[59]
    DIRECTION INPUT ;
    USE SIGNAL ;
    PORT
      LAYER M4 ;
        RECT  62.856 22.8 63.048 22.824 ;
    END
  END di0[59]
  PIN di0[5]
    DIRECTION INPUT ;
    USE SIGNAL ;
    PORT
      LAYER M4 ;
        RECT  62.856 20.208 63.048 20.232 ;
    END
  END di0[5]
  PIN di0[60]
    DIRECTION INPUT ;
    USE SIGNAL ;
    PORT
      LAYER M4 ;
        RECT  62.856 22.848 63.048 22.872 ;
    END
  END di0[60]
  PIN di0[61]
    DIRECTION INPUT ;
    USE SIGNAL ;
    PORT
      LAYER M4 ;
        RECT  62.856 22.896 63.048 22.92 ;
    END
  END di0[61]
  PIN di0[62]
    DIRECTION INPUT ;
    USE SIGNAL ;
    PORT
      LAYER M4 ;
        RECT  62.856 22.944 63.048 22.968 ;
    END
  END di0[62]
  PIN di0[63]
    DIRECTION INPUT ;
    USE SIGNAL ;
    PORT
      LAYER M4 ;
        RECT  62.856 22.992 63.048 23.016 ;
    END
  END di0[63]
  PIN di0[64]
    DIRECTION INPUT ;
    USE SIGNAL ;
    PORT
      LAYER M4 ;
        RECT  62.856 23.04 63.048 23.064 ;
    END
  END di0[64]
  PIN di0[65]
    DIRECTION INPUT ;
    USE SIGNAL ;
    PORT
      LAYER M4 ;
        RECT  62.856 23.088 63.048 23.112 ;
    END
  END di0[65]
  PIN di0[66]
    DIRECTION INPUT ;
    USE SIGNAL ;
    PORT
      LAYER M4 ;
        RECT  62.856 23.136 63.048 23.16 ;
    END
  END di0[66]
  PIN di0[67]
    DIRECTION INPUT ;
    USE SIGNAL ;
    PORT
      LAYER M4 ;
        RECT  62.856 23.184 63.048 23.208 ;
    END
  END di0[67]
  PIN di0[68]
    DIRECTION INPUT ;
    USE SIGNAL ;
    PORT
      LAYER M4 ;
        RECT  62.856 23.232 63.048 23.256 ;
    END
  END di0[68]
  PIN di0[69]
    DIRECTION INPUT ;
    USE SIGNAL ;
    PORT
      LAYER M4 ;
        RECT  62.856 23.28 63.048 23.304 ;
    END
  END di0[69]
  PIN di0[6]
    DIRECTION INPUT ;
    USE SIGNAL ;
    PORT
      LAYER M4 ;
        RECT  62.856 20.256 63.048 20.28 ;
    END
  END di0[6]
  PIN di0[70]
    DIRECTION INPUT ;
    USE SIGNAL ;
    PORT
      LAYER M4 ;
        RECT  62.856 23.328 63.048 23.352 ;
    END
  END di0[70]
  PIN di0[71]
    DIRECTION INPUT ;
    USE SIGNAL ;
    PORT
      LAYER M4 ;
        RECT  62.856 23.376 63.048 23.4 ;
    END
  END di0[71]
  PIN di0[72]
    DIRECTION INPUT ;
    USE SIGNAL ;
    PORT
      LAYER M4 ;
        RECT  62.856 23.424 63.048 23.448 ;
    END
  END di0[72]
  PIN di0[73]
    DIRECTION INPUT ;
    USE SIGNAL ;
    PORT
      LAYER M4 ;
        RECT  62.856 23.472 63.048 23.496 ;
    END
  END di0[73]
  PIN di0[74]
    DIRECTION INPUT ;
    USE SIGNAL ;
    PORT
      LAYER M4 ;
        RECT  62.856 23.52 63.048 23.544 ;
    END
  END di0[74]
  PIN di0[75]
    DIRECTION INPUT ;
    USE SIGNAL ;
    PORT
      LAYER M4 ;
        RECT  62.856 23.568 63.048 23.592 ;
    END
  END di0[75]
  PIN di0[76]
    DIRECTION INPUT ;
    USE SIGNAL ;
    PORT
      LAYER M4 ;
        RECT  62.856 23.616 63.048 23.64 ;
    END
  END di0[76]
  PIN di0[77]
    DIRECTION INPUT ;
    USE SIGNAL ;
    PORT
      LAYER M4 ;
        RECT  62.856 23.664 63.048 23.688 ;
    END
  END di0[77]
  PIN di0[78]
    DIRECTION INPUT ;
    USE SIGNAL ;
    PORT
      LAYER M4 ;
        RECT  62.856 23.712 63.048 23.736 ;
    END
  END di0[78]
  PIN di0[79]
    DIRECTION INPUT ;
    USE SIGNAL ;
    PORT
      LAYER M4 ;
        RECT  62.856 23.76 63.048 23.784 ;
    END
  END di0[79]
  PIN di0[7]
    DIRECTION INPUT ;
    USE SIGNAL ;
    PORT
      LAYER M4 ;
        RECT  62.856 20.304 63.048 20.328 ;
    END
  END di0[7]
  PIN di0[80]
    DIRECTION INPUT ;
    USE SIGNAL ;
    PORT
      LAYER M4 ;
        RECT  62.856 23.808 63.048 23.832 ;
    END
  END di0[80]
  PIN di0[81]
    DIRECTION INPUT ;
    USE SIGNAL ;
    PORT
      LAYER M4 ;
        RECT  62.856 23.856 63.048 23.88 ;
    END
  END di0[81]
  PIN di0[82]
    DIRECTION INPUT ;
    USE SIGNAL ;
    PORT
      LAYER M4 ;
        RECT  62.856 23.904 63.048 23.928 ;
    END
  END di0[82]
  PIN di0[83]
    DIRECTION INPUT ;
    USE SIGNAL ;
    PORT
      LAYER M4 ;
        RECT  62.856 23.952 63.048 23.976 ;
    END
  END di0[83]
  PIN di0[84]
    DIRECTION INPUT ;
    USE SIGNAL ;
    PORT
      LAYER M4 ;
        RECT  62.856 24 63.048 24.024 ;
    END
  END di0[84]
  PIN di0[85]
    DIRECTION INPUT ;
    USE SIGNAL ;
    PORT
      LAYER M4 ;
        RECT  62.856 24.048 63.048 24.072 ;
    END
  END di0[85]
  PIN di0[86]
    DIRECTION INPUT ;
    USE SIGNAL ;
    PORT
      LAYER M4 ;
        RECT  62.856 24.096 63.048 24.12 ;
    END
  END di0[86]
  PIN di0[87]
    DIRECTION INPUT ;
    USE SIGNAL ;
    PORT
      LAYER M4 ;
        RECT  62.856 24.144 63.048 24.168 ;
    END
  END di0[87]
  PIN di0[88]
    DIRECTION INPUT ;
    USE SIGNAL ;
    PORT
      LAYER M4 ;
        RECT  62.856 24.192 63.048 24.216 ;
    END
  END di0[88]
  PIN di0[89]
    DIRECTION INPUT ;
    USE SIGNAL ;
    PORT
      LAYER M4 ;
        RECT  62.856 24.24 63.048 24.264 ;
    END
  END di0[89]
  PIN di0[8]
    DIRECTION INPUT ;
    USE SIGNAL ;
    PORT
      LAYER M4 ;
        RECT  62.856 20.352 63.048 20.376 ;
    END
  END di0[8]
  PIN di0[90]
    DIRECTION INPUT ;
    USE SIGNAL ;
    PORT
      LAYER M4 ;
        RECT  62.856 24.288 63.048 24.312 ;
    END
  END di0[90]
  PIN di0[91]
    DIRECTION INPUT ;
    USE SIGNAL ;
    PORT
      LAYER M4 ;
        RECT  62.856 24.336 63.048 24.36 ;
    END
  END di0[91]
  PIN di0[92]
    DIRECTION INPUT ;
    USE SIGNAL ;
    PORT
      LAYER M4 ;
        RECT  62.856 24.384 63.048 24.408 ;
    END
  END di0[92]
  PIN di0[93]
    DIRECTION INPUT ;
    USE SIGNAL ;
    PORT
      LAYER M4 ;
        RECT  62.856 24.432 63.048 24.456 ;
    END
  END di0[93]
  PIN di0[94]
    DIRECTION INPUT ;
    USE SIGNAL ;
    PORT
      LAYER M4 ;
        RECT  62.856 24.48 63.048 24.504 ;
    END
  END di0[94]
  PIN di0[95]
    DIRECTION INPUT ;
    USE SIGNAL ;
    PORT
      LAYER M4 ;
        RECT  62.856 24.528 63.048 24.552 ;
    END
  END di0[95]
  PIN di0[96]
    DIRECTION INPUT ;
    USE SIGNAL ;
    PORT
      LAYER M4 ;
        RECT  62.856 24.576 63.048 24.6 ;
    END
  END di0[96]
  PIN di0[97]
    DIRECTION INPUT ;
    USE SIGNAL ;
    PORT
      LAYER M4 ;
        RECT  62.856 24.624 63.048 24.648 ;
    END
  END di0[97]
  PIN di0[98]
    DIRECTION INPUT ;
    USE SIGNAL ;
    PORT
      LAYER M4 ;
        RECT  62.856 24.672 63.048 24.696 ;
    END
  END di0[98]
  PIN di0[99]
    DIRECTION INPUT ;
    USE SIGNAL ;
    PORT
      LAYER M4 ;
        RECT  62.856 24.72 63.048 24.744 ;
    END
  END di0[99]
  PIN di0[9]
    DIRECTION INPUT ;
    USE SIGNAL ;
    PORT
      LAYER M4 ;
        RECT  62.856 20.4 63.048 20.424 ;
    END
  END di0[9]
  PIN fi0[0]
    DIRECTION INPUT ;
    USE SIGNAL ;
    PORT
      LAYER M4 ;
        RECT  62.856 44.784 63.048 44.808 ;
    END
  END fi0[0]
  PIN o[0]
    DIRECTION OUTPUT ;
    USE SIGNAL ;
    PORT
      LAYER M5 ;
        RECT  19.152 64.584 19.176 64.776 ;
    END
  END o[0]
  PIN o[100]
    DIRECTION OUTPUT ;
    USE SIGNAL ;
    PORT
      LAYER M5 ;
        RECT  23.952 64.584 23.976 64.776 ;
    END
  END o[100]
  PIN o[101]
    DIRECTION OUTPUT ;
    USE SIGNAL ;
    PORT
      LAYER M5 ;
        RECT  24 64.584 24.024 64.776 ;
    END
  END o[101]
  PIN o[102]
    DIRECTION OUTPUT ;
    USE SIGNAL ;
    PORT
      LAYER M5 ;
        RECT  24.048 64.584 24.072 64.776 ;
    END
  END o[102]
  PIN o[103]
    DIRECTION OUTPUT ;
    USE SIGNAL ;
    PORT
      LAYER M5 ;
        RECT  24.096 64.584 24.12 64.776 ;
    END
  END o[103]
  PIN o[104]
    DIRECTION OUTPUT ;
    USE SIGNAL ;
    PORT
      LAYER M5 ;
        RECT  24.144 64.584 24.168 64.776 ;
    END
  END o[104]
  PIN o[105]
    DIRECTION OUTPUT ;
    USE SIGNAL ;
    PORT
      LAYER M5 ;
        RECT  24.192 64.584 24.216 64.776 ;
    END
  END o[105]
  PIN o[106]
    DIRECTION OUTPUT ;
    USE SIGNAL ;
    PORT
      LAYER M5 ;
        RECT  24.24 64.584 24.264 64.776 ;
    END
  END o[106]
  PIN o[107]
    DIRECTION OUTPUT ;
    USE SIGNAL ;
    PORT
      LAYER M5 ;
        RECT  24.288 64.584 24.312 64.776 ;
    END
  END o[107]
  PIN o[108]
    DIRECTION OUTPUT ;
    USE SIGNAL ;
    PORT
      LAYER M5 ;
        RECT  24.336 64.584 24.36 64.776 ;
    END
  END o[108]
  PIN o[109]
    DIRECTION OUTPUT ;
    USE SIGNAL ;
    PORT
      LAYER M5 ;
        RECT  24.384 64.584 24.408 64.776 ;
    END
  END o[109]
  PIN o[10]
    DIRECTION OUTPUT ;
    USE SIGNAL ;
    PORT
      LAYER M5 ;
        RECT  19.632 64.584 19.656 64.776 ;
    END
  END o[10]
  PIN o[110]
    DIRECTION OUTPUT ;
    USE SIGNAL ;
    PORT
      LAYER M5 ;
        RECT  24.432 64.584 24.456 64.776 ;
    END
  END o[110]
  PIN o[111]
    DIRECTION OUTPUT ;
    USE SIGNAL ;
    PORT
      LAYER M5 ;
        RECT  24.48 64.584 24.504 64.776 ;
    END
  END o[111]
  PIN o[112]
    DIRECTION OUTPUT ;
    USE SIGNAL ;
    PORT
      LAYER M5 ;
        RECT  24.528 64.584 24.552 64.776 ;
    END
  END o[112]
  PIN o[113]
    DIRECTION OUTPUT ;
    USE SIGNAL ;
    PORT
      LAYER M5 ;
        RECT  24.576 64.584 24.6 64.776 ;
    END
  END o[113]
  PIN o[114]
    DIRECTION OUTPUT ;
    USE SIGNAL ;
    PORT
      LAYER M5 ;
        RECT  24.624 64.584 24.648 64.776 ;
    END
  END o[114]
  PIN o[115]
    DIRECTION OUTPUT ;
    USE SIGNAL ;
    PORT
      LAYER M5 ;
        RECT  24.672 64.584 24.696 64.776 ;
    END
  END o[115]
  PIN o[116]
    DIRECTION OUTPUT ;
    USE SIGNAL ;
    PORT
      LAYER M5 ;
        RECT  24.72 64.584 24.744 64.776 ;
    END
  END o[116]
  PIN o[117]
    DIRECTION OUTPUT ;
    USE SIGNAL ;
    PORT
      LAYER M5 ;
        RECT  24.768 64.584 24.792 64.776 ;
    END
  END o[117]
  PIN o[118]
    DIRECTION OUTPUT ;
    USE SIGNAL ;
    PORT
      LAYER M5 ;
        RECT  24.816 64.584 24.84 64.776 ;
    END
  END o[118]
  PIN o[119]
    DIRECTION OUTPUT ;
    USE SIGNAL ;
    PORT
      LAYER M5 ;
        RECT  24.864 64.584 24.888 64.776 ;
    END
  END o[119]
  PIN o[11]
    DIRECTION OUTPUT ;
    USE SIGNAL ;
    PORT
      LAYER M5 ;
        RECT  19.68 64.584 19.704 64.776 ;
    END
  END o[11]
  PIN o[120]
    DIRECTION OUTPUT ;
    USE SIGNAL ;
    PORT
      LAYER M5 ;
        RECT  24.912 64.584 24.936 64.776 ;
    END
  END o[120]
  PIN o[121]
    DIRECTION OUTPUT ;
    USE SIGNAL ;
    PORT
      LAYER M5 ;
        RECT  24.96 64.584 24.984 64.776 ;
    END
  END o[121]
  PIN o[122]
    DIRECTION OUTPUT ;
    USE SIGNAL ;
    PORT
      LAYER M5 ;
        RECT  25.008 64.584 25.032 64.776 ;
    END
  END o[122]
  PIN o[123]
    DIRECTION OUTPUT ;
    USE SIGNAL ;
    PORT
      LAYER M5 ;
        RECT  25.056 64.584 25.08 64.776 ;
    END
  END o[123]
  PIN o[124]
    DIRECTION OUTPUT ;
    USE SIGNAL ;
    PORT
      LAYER M5 ;
        RECT  25.104 64.584 25.128 64.776 ;
    END
  END o[124]
  PIN o[125]
    DIRECTION OUTPUT ;
    USE SIGNAL ;
    PORT
      LAYER M5 ;
        RECT  25.152 64.584 25.176 64.776 ;
    END
  END o[125]
  PIN o[126]
    DIRECTION OUTPUT ;
    USE SIGNAL ;
    PORT
      LAYER M5 ;
        RECT  25.2 64.584 25.224 64.776 ;
    END
  END o[126]
  PIN o[127]
    DIRECTION OUTPUT ;
    USE SIGNAL ;
    PORT
      LAYER M5 ;
        RECT  25.248 64.584 25.272 64.776 ;
    END
  END o[127]
  PIN o[128]
    DIRECTION OUTPUT ;
    USE SIGNAL ;
    PORT
      LAYER M5 ;
        RECT  25.296 64.584 25.32 64.776 ;
    END
  END o[128]
  PIN o[129]
    DIRECTION OUTPUT ;
    USE SIGNAL ;
    PORT
      LAYER M5 ;
        RECT  25.344 64.584 25.368 64.776 ;
    END
  END o[129]
  PIN o[12]
    DIRECTION OUTPUT ;
    USE SIGNAL ;
    PORT
      LAYER M5 ;
        RECT  19.728 64.584 19.752 64.776 ;
    END
  END o[12]
  PIN o[130]
    DIRECTION OUTPUT ;
    USE SIGNAL ;
    PORT
      LAYER M5 ;
        RECT  25.392 64.584 25.416 64.776 ;
    END
  END o[130]
  PIN o[131]
    DIRECTION OUTPUT ;
    USE SIGNAL ;
    PORT
      LAYER M5 ;
        RECT  25.44 64.584 25.464 64.776 ;
    END
  END o[131]
  PIN o[132]
    DIRECTION OUTPUT ;
    USE SIGNAL ;
    PORT
      LAYER M5 ;
        RECT  25.488 64.584 25.512 64.776 ;
    END
  END o[132]
  PIN o[133]
    DIRECTION OUTPUT ;
    USE SIGNAL ;
    PORT
      LAYER M5 ;
        RECT  25.536 64.584 25.56 64.776 ;
    END
  END o[133]
  PIN o[134]
    DIRECTION OUTPUT ;
    USE SIGNAL ;
    PORT
      LAYER M5 ;
        RECT  25.584 64.584 25.608 64.776 ;
    END
  END o[134]
  PIN o[135]
    DIRECTION OUTPUT ;
    USE SIGNAL ;
    PORT
      LAYER M5 ;
        RECT  25.632 64.584 25.656 64.776 ;
    END
  END o[135]
  PIN o[136]
    DIRECTION OUTPUT ;
    USE SIGNAL ;
    PORT
      LAYER M5 ;
        RECT  25.68 64.584 25.704 64.776 ;
    END
  END o[136]
  PIN o[137]
    DIRECTION OUTPUT ;
    USE SIGNAL ;
    PORT
      LAYER M5 ;
        RECT  25.728 64.584 25.752 64.776 ;
    END
  END o[137]
  PIN o[138]
    DIRECTION OUTPUT ;
    USE SIGNAL ;
    PORT
      LAYER M5 ;
        RECT  25.776 64.584 25.8 64.776 ;
    END
  END o[138]
  PIN o[139]
    DIRECTION OUTPUT ;
    USE SIGNAL ;
    PORT
      LAYER M5 ;
        RECT  25.824 64.584 25.848 64.776 ;
    END
  END o[139]
  PIN o[13]
    DIRECTION OUTPUT ;
    USE SIGNAL ;
    PORT
      LAYER M5 ;
        RECT  19.776 64.584 19.8 64.776 ;
    END
  END o[13]
  PIN o[140]
    DIRECTION OUTPUT ;
    USE SIGNAL ;
    PORT
      LAYER M5 ;
        RECT  25.872 64.584 25.896 64.776 ;
    END
  END o[140]
  PIN o[141]
    DIRECTION OUTPUT ;
    USE SIGNAL ;
    PORT
      LAYER M5 ;
        RECT  25.92 64.584 25.944 64.776 ;
    END
  END o[141]
  PIN o[142]
    DIRECTION OUTPUT ;
    USE SIGNAL ;
    PORT
      LAYER M5 ;
        RECT  25.968 64.584 25.992 64.776 ;
    END
  END o[142]
  PIN o[143]
    DIRECTION OUTPUT ;
    USE SIGNAL ;
    PORT
      LAYER M5 ;
        RECT  26.016 64.584 26.04 64.776 ;
    END
  END o[143]
  PIN o[144]
    DIRECTION OUTPUT ;
    USE SIGNAL ;
    PORT
      LAYER M5 ;
        RECT  26.064 64.584 26.088 64.776 ;
    END
  END o[144]
  PIN o[145]
    DIRECTION OUTPUT ;
    USE SIGNAL ;
    PORT
      LAYER M5 ;
        RECT  26.112 64.584 26.136 64.776 ;
    END
  END o[145]
  PIN o[146]
    DIRECTION OUTPUT ;
    USE SIGNAL ;
    PORT
      LAYER M5 ;
        RECT  26.16 64.584 26.184 64.776 ;
    END
  END o[146]
  PIN o[147]
    DIRECTION OUTPUT ;
    USE SIGNAL ;
    PORT
      LAYER M5 ;
        RECT  26.208 64.584 26.232 64.776 ;
    END
  END o[147]
  PIN o[148]
    DIRECTION OUTPUT ;
    USE SIGNAL ;
    PORT
      LAYER M5 ;
        RECT  26.256 64.584 26.28 64.776 ;
    END
  END o[148]
  PIN o[149]
    DIRECTION OUTPUT ;
    USE SIGNAL ;
    PORT
      LAYER M5 ;
        RECT  26.304 64.584 26.328 64.776 ;
    END
  END o[149]
  PIN o[14]
    DIRECTION OUTPUT ;
    USE SIGNAL ;
    PORT
      LAYER M5 ;
        RECT  19.824 64.584 19.848 64.776 ;
    END
  END o[14]
  PIN o[150]
    DIRECTION OUTPUT ;
    USE SIGNAL ;
    PORT
      LAYER M5 ;
        RECT  26.352 64.584 26.376 64.776 ;
    END
  END o[150]
  PIN o[151]
    DIRECTION OUTPUT ;
    USE SIGNAL ;
    PORT
      LAYER M5 ;
        RECT  26.4 64.584 26.424 64.776 ;
    END
  END o[151]
  PIN o[152]
    DIRECTION OUTPUT ;
    USE SIGNAL ;
    PORT
      LAYER M5 ;
        RECT  26.448 64.584 26.472 64.776 ;
    END
  END o[152]
  PIN o[153]
    DIRECTION OUTPUT ;
    USE SIGNAL ;
    PORT
      LAYER M5 ;
        RECT  26.496 64.584 26.52 64.776 ;
    END
  END o[153]
  PIN o[154]
    DIRECTION OUTPUT ;
    USE SIGNAL ;
    PORT
      LAYER M5 ;
        RECT  26.544 64.584 26.568 64.776 ;
    END
  END o[154]
  PIN o[155]
    DIRECTION OUTPUT ;
    USE SIGNAL ;
    PORT
      LAYER M5 ;
        RECT  26.592 64.584 26.616 64.776 ;
    END
  END o[155]
  PIN o[156]
    DIRECTION OUTPUT ;
    USE SIGNAL ;
    PORT
      LAYER M5 ;
        RECT  26.64 64.584 26.664 64.776 ;
    END
  END o[156]
  PIN o[157]
    DIRECTION OUTPUT ;
    USE SIGNAL ;
    PORT
      LAYER M5 ;
        RECT  26.688 64.584 26.712 64.776 ;
    END
  END o[157]
  PIN o[158]
    DIRECTION OUTPUT ;
    USE SIGNAL ;
    PORT
      LAYER M5 ;
        RECT  26.736 64.584 26.76 64.776 ;
    END
  END o[158]
  PIN o[159]
    DIRECTION OUTPUT ;
    USE SIGNAL ;
    PORT
      LAYER M5 ;
        RECT  26.784 64.584 26.808 64.776 ;
    END
  END o[159]
  PIN o[15]
    DIRECTION OUTPUT ;
    USE SIGNAL ;
    PORT
      LAYER M5 ;
        RECT  19.872 64.584 19.896 64.776 ;
    END
  END o[15]
  PIN o[160]
    DIRECTION OUTPUT ;
    USE SIGNAL ;
    PORT
      LAYER M5 ;
        RECT  26.832 64.584 26.856 64.776 ;
    END
  END o[160]
  PIN o[161]
    DIRECTION OUTPUT ;
    USE SIGNAL ;
    PORT
      LAYER M5 ;
        RECT  26.88 64.584 26.904 64.776 ;
    END
  END o[161]
  PIN o[162]
    DIRECTION OUTPUT ;
    USE SIGNAL ;
    PORT
      LAYER M5 ;
        RECT  26.928 64.584 26.952 64.776 ;
    END
  END o[162]
  PIN o[163]
    DIRECTION OUTPUT ;
    USE SIGNAL ;
    PORT
      LAYER M5 ;
        RECT  26.976 64.584 27 64.776 ;
    END
  END o[163]
  PIN o[164]
    DIRECTION OUTPUT ;
    USE SIGNAL ;
    PORT
      LAYER M5 ;
        RECT  27.024 64.584 27.048 64.776 ;
    END
  END o[164]
  PIN o[165]
    DIRECTION OUTPUT ;
    USE SIGNAL ;
    PORT
      LAYER M5 ;
        RECT  27.072 64.584 27.096 64.776 ;
    END
  END o[165]
  PIN o[166]
    DIRECTION OUTPUT ;
    USE SIGNAL ;
    PORT
      LAYER M5 ;
        RECT  27.12 64.584 27.144 64.776 ;
    END
  END o[166]
  PIN o[167]
    DIRECTION OUTPUT ;
    USE SIGNAL ;
    PORT
      LAYER M5 ;
        RECT  27.168 64.584 27.192 64.776 ;
    END
  END o[167]
  PIN o[168]
    DIRECTION OUTPUT ;
    USE SIGNAL ;
    PORT
      LAYER M5 ;
        RECT  27.216 64.584 27.24 64.776 ;
    END
  END o[168]
  PIN o[169]
    DIRECTION OUTPUT ;
    USE SIGNAL ;
    PORT
      LAYER M5 ;
        RECT  27.264 64.584 27.288 64.776 ;
    END
  END o[169]
  PIN o[16]
    DIRECTION OUTPUT ;
    USE SIGNAL ;
    PORT
      LAYER M5 ;
        RECT  19.92 64.584 19.944 64.776 ;
    END
  END o[16]
  PIN o[170]
    DIRECTION OUTPUT ;
    USE SIGNAL ;
    PORT
      LAYER M5 ;
        RECT  27.312 64.584 27.336 64.776 ;
    END
  END o[170]
  PIN o[171]
    DIRECTION OUTPUT ;
    USE SIGNAL ;
    PORT
      LAYER M5 ;
        RECT  27.36 64.584 27.384 64.776 ;
    END
  END o[171]
  PIN o[172]
    DIRECTION OUTPUT ;
    USE SIGNAL ;
    PORT
      LAYER M5 ;
        RECT  27.408 64.584 27.432 64.776 ;
    END
  END o[172]
  PIN o[173]
    DIRECTION OUTPUT ;
    USE SIGNAL ;
    PORT
      LAYER M5 ;
        RECT  27.456 64.584 27.48 64.776 ;
    END
  END o[173]
  PIN o[174]
    DIRECTION OUTPUT ;
    USE SIGNAL ;
    PORT
      LAYER M5 ;
        RECT  27.504 64.584 27.528 64.776 ;
    END
  END o[174]
  PIN o[175]
    DIRECTION OUTPUT ;
    USE SIGNAL ;
    PORT
      LAYER M5 ;
        RECT  27.552 64.584 27.576 64.776 ;
    END
  END o[175]
  PIN o[176]
    DIRECTION OUTPUT ;
    USE SIGNAL ;
    PORT
      LAYER M5 ;
        RECT  27.6 64.584 27.624 64.776 ;
    END
  END o[176]
  PIN o[177]
    DIRECTION OUTPUT ;
    USE SIGNAL ;
    PORT
      LAYER M5 ;
        RECT  27.648 64.584 27.672 64.776 ;
    END
  END o[177]
  PIN o[178]
    DIRECTION OUTPUT ;
    USE SIGNAL ;
    PORT
      LAYER M5 ;
        RECT  27.696 64.584 27.72 64.776 ;
    END
  END o[178]
  PIN o[179]
    DIRECTION OUTPUT ;
    USE SIGNAL ;
    PORT
      LAYER M5 ;
        RECT  27.744 64.584 27.768 64.776 ;
    END
  END o[179]
  PIN o[17]
    DIRECTION OUTPUT ;
    USE SIGNAL ;
    PORT
      LAYER M5 ;
        RECT  19.968 64.584 19.992 64.776 ;
    END
  END o[17]
  PIN o[180]
    DIRECTION OUTPUT ;
    USE SIGNAL ;
    PORT
      LAYER M5 ;
        RECT  27.792 64.584 27.816 64.776 ;
    END
  END o[180]
  PIN o[181]
    DIRECTION OUTPUT ;
    USE SIGNAL ;
    PORT
      LAYER M5 ;
        RECT  27.84 64.584 27.864 64.776 ;
    END
  END o[181]
  PIN o[182]
    DIRECTION OUTPUT ;
    USE SIGNAL ;
    PORT
      LAYER M5 ;
        RECT  27.888 64.584 27.912 64.776 ;
    END
  END o[182]
  PIN o[183]
    DIRECTION OUTPUT ;
    USE SIGNAL ;
    PORT
      LAYER M5 ;
        RECT  27.936 64.584 27.96 64.776 ;
    END
  END o[183]
  PIN o[184]
    DIRECTION OUTPUT ;
    USE SIGNAL ;
    PORT
      LAYER M5 ;
        RECT  27.984 64.584 28.008 64.776 ;
    END
  END o[184]
  PIN o[185]
    DIRECTION OUTPUT ;
    USE SIGNAL ;
    PORT
      LAYER M5 ;
        RECT  28.032 64.584 28.056 64.776 ;
    END
  END o[185]
  PIN o[186]
    DIRECTION OUTPUT ;
    USE SIGNAL ;
    PORT
      LAYER M5 ;
        RECT  28.08 64.584 28.104 64.776 ;
    END
  END o[186]
  PIN o[187]
    DIRECTION OUTPUT ;
    USE SIGNAL ;
    PORT
      LAYER M5 ;
        RECT  28.128 64.584 28.152 64.776 ;
    END
  END o[187]
  PIN o[188]
    DIRECTION OUTPUT ;
    USE SIGNAL ;
    PORT
      LAYER M5 ;
        RECT  28.176 64.584 28.2 64.776 ;
    END
  END o[188]
  PIN o[189]
    DIRECTION OUTPUT ;
    USE SIGNAL ;
    PORT
      LAYER M5 ;
        RECT  28.224 64.584 28.248 64.776 ;
    END
  END o[189]
  PIN o[18]
    DIRECTION OUTPUT ;
    USE SIGNAL ;
    PORT
      LAYER M5 ;
        RECT  20.016 64.584 20.04 64.776 ;
    END
  END o[18]
  PIN o[190]
    DIRECTION OUTPUT ;
    USE SIGNAL ;
    PORT
      LAYER M5 ;
        RECT  28.272 64.584 28.296 64.776 ;
    END
  END o[190]
  PIN o[191]
    DIRECTION OUTPUT ;
    USE SIGNAL ;
    PORT
      LAYER M5 ;
        RECT  28.32 64.584 28.344 64.776 ;
    END
  END o[191]
  PIN o[192]
    DIRECTION OUTPUT ;
    USE SIGNAL ;
    PORT
      LAYER M5 ;
        RECT  28.368 64.584 28.392 64.776 ;
    END
  END o[192]
  PIN o[193]
    DIRECTION OUTPUT ;
    USE SIGNAL ;
    PORT
      LAYER M5 ;
        RECT  28.416 64.584 28.44 64.776 ;
    END
  END o[193]
  PIN o[194]
    DIRECTION OUTPUT ;
    USE SIGNAL ;
    PORT
      LAYER M5 ;
        RECT  28.464 64.584 28.488 64.776 ;
    END
  END o[194]
  PIN o[195]
    DIRECTION OUTPUT ;
    USE SIGNAL ;
    PORT
      LAYER M5 ;
        RECT  28.512 64.584 28.536 64.776 ;
    END
  END o[195]
  PIN o[196]
    DIRECTION OUTPUT ;
    USE SIGNAL ;
    PORT
      LAYER M5 ;
        RECT  28.56 64.584 28.584 64.776 ;
    END
  END o[196]
  PIN o[197]
    DIRECTION OUTPUT ;
    USE SIGNAL ;
    PORT
      LAYER M5 ;
        RECT  28.608 64.584 28.632 64.776 ;
    END
  END o[197]
  PIN o[198]
    DIRECTION OUTPUT ;
    USE SIGNAL ;
    PORT
      LAYER M5 ;
        RECT  28.656 64.584 28.68 64.776 ;
    END
  END o[198]
  PIN o[199]
    DIRECTION OUTPUT ;
    USE SIGNAL ;
    PORT
      LAYER M5 ;
        RECT  28.704 64.584 28.728 64.776 ;
    END
  END o[199]
  PIN o[19]
    DIRECTION OUTPUT ;
    USE SIGNAL ;
    PORT
      LAYER M5 ;
        RECT  20.064 64.584 20.088 64.776 ;
    END
  END o[19]
  PIN o[1]
    DIRECTION OUTPUT ;
    USE SIGNAL ;
    PORT
      LAYER M5 ;
        RECT  19.2 64.584 19.224 64.776 ;
    END
  END o[1]
  PIN o[200]
    DIRECTION OUTPUT ;
    USE SIGNAL ;
    PORT
      LAYER M5 ;
        RECT  28.752 64.584 28.776 64.776 ;
    END
  END o[200]
  PIN o[201]
    DIRECTION OUTPUT ;
    USE SIGNAL ;
    PORT
      LAYER M5 ;
        RECT  28.8 64.584 28.824 64.776 ;
    END
  END o[201]
  PIN o[202]
    DIRECTION OUTPUT ;
    USE SIGNAL ;
    PORT
      LAYER M5 ;
        RECT  28.848 64.584 28.872 64.776 ;
    END
  END o[202]
  PIN o[203]
    DIRECTION OUTPUT ;
    USE SIGNAL ;
    PORT
      LAYER M5 ;
        RECT  28.896 64.584 28.92 64.776 ;
    END
  END o[203]
  PIN o[204]
    DIRECTION OUTPUT ;
    USE SIGNAL ;
    PORT
      LAYER M5 ;
        RECT  28.944 64.584 28.968 64.776 ;
    END
  END o[204]
  PIN o[205]
    DIRECTION OUTPUT ;
    USE SIGNAL ;
    PORT
      LAYER M5 ;
        RECT  28.992 64.584 29.016 64.776 ;
    END
  END o[205]
  PIN o[206]
    DIRECTION OUTPUT ;
    USE SIGNAL ;
    PORT
      LAYER M5 ;
        RECT  29.04 64.584 29.064 64.776 ;
    END
  END o[206]
  PIN o[207]
    DIRECTION OUTPUT ;
    USE SIGNAL ;
    PORT
      LAYER M5 ;
        RECT  29.088 64.584 29.112 64.776 ;
    END
  END o[207]
  PIN o[208]
    DIRECTION OUTPUT ;
    USE SIGNAL ;
    PORT
      LAYER M5 ;
        RECT  29.136 64.584 29.16 64.776 ;
    END
  END o[208]
  PIN o[209]
    DIRECTION OUTPUT ;
    USE SIGNAL ;
    PORT
      LAYER M5 ;
        RECT  29.184 64.584 29.208 64.776 ;
    END
  END o[209]
  PIN o[20]
    DIRECTION OUTPUT ;
    USE SIGNAL ;
    PORT
      LAYER M5 ;
        RECT  20.112 64.584 20.136 64.776 ;
    END
  END o[20]
  PIN o[210]
    DIRECTION OUTPUT ;
    USE SIGNAL ;
    PORT
      LAYER M5 ;
        RECT  29.232 64.584 29.256 64.776 ;
    END
  END o[210]
  PIN o[211]
    DIRECTION OUTPUT ;
    USE SIGNAL ;
    PORT
      LAYER M5 ;
        RECT  29.28 64.584 29.304 64.776 ;
    END
  END o[211]
  PIN o[212]
    DIRECTION OUTPUT ;
    USE SIGNAL ;
    PORT
      LAYER M5 ;
        RECT  29.328 64.584 29.352 64.776 ;
    END
  END o[212]
  PIN o[213]
    DIRECTION OUTPUT ;
    USE SIGNAL ;
    PORT
      LAYER M5 ;
        RECT  29.376 64.584 29.4 64.776 ;
    END
  END o[213]
  PIN o[214]
    DIRECTION OUTPUT ;
    USE SIGNAL ;
    PORT
      LAYER M5 ;
        RECT  29.424 64.584 29.448 64.776 ;
    END
  END o[214]
  PIN o[215]
    DIRECTION OUTPUT ;
    USE SIGNAL ;
    PORT
      LAYER M5 ;
        RECT  29.472 64.584 29.496 64.776 ;
    END
  END o[215]
  PIN o[216]
    DIRECTION OUTPUT ;
    USE SIGNAL ;
    PORT
      LAYER M5 ;
        RECT  29.52 64.584 29.544 64.776 ;
    END
  END o[216]
  PIN o[217]
    DIRECTION OUTPUT ;
    USE SIGNAL ;
    PORT
      LAYER M5 ;
        RECT  29.568 64.584 29.592 64.776 ;
    END
  END o[217]
  PIN o[218]
    DIRECTION OUTPUT ;
    USE SIGNAL ;
    PORT
      LAYER M5 ;
        RECT  29.616 64.584 29.64 64.776 ;
    END
  END o[218]
  PIN o[219]
    DIRECTION OUTPUT ;
    USE SIGNAL ;
    PORT
      LAYER M5 ;
        RECT  29.664 64.584 29.688 64.776 ;
    END
  END o[219]
  PIN o[21]
    DIRECTION OUTPUT ;
    USE SIGNAL ;
    PORT
      LAYER M5 ;
        RECT  20.16 64.584 20.184 64.776 ;
    END
  END o[21]
  PIN o[220]
    DIRECTION OUTPUT ;
    USE SIGNAL ;
    PORT
      LAYER M5 ;
        RECT  29.712 64.584 29.736 64.776 ;
    END
  END o[220]
  PIN o[221]
    DIRECTION OUTPUT ;
    USE SIGNAL ;
    PORT
      LAYER M5 ;
        RECT  29.76 64.584 29.784 64.776 ;
    END
  END o[221]
  PIN o[222]
    DIRECTION OUTPUT ;
    USE SIGNAL ;
    PORT
      LAYER M5 ;
        RECT  29.808 64.584 29.832 64.776 ;
    END
  END o[222]
  PIN o[223]
    DIRECTION OUTPUT ;
    USE SIGNAL ;
    PORT
      LAYER M5 ;
        RECT  29.856 64.584 29.88 64.776 ;
    END
  END o[223]
  PIN o[224]
    DIRECTION OUTPUT ;
    USE SIGNAL ;
    PORT
      LAYER M5 ;
        RECT  29.904 64.584 29.928 64.776 ;
    END
  END o[224]
  PIN o[225]
    DIRECTION OUTPUT ;
    USE SIGNAL ;
    PORT
      LAYER M5 ;
        RECT  29.952 64.584 29.976 64.776 ;
    END
  END o[225]
  PIN o[226]
    DIRECTION OUTPUT ;
    USE SIGNAL ;
    PORT
      LAYER M5 ;
        RECT  30 64.584 30.024 64.776 ;
    END
  END o[226]
  PIN o[227]
    DIRECTION OUTPUT ;
    USE SIGNAL ;
    PORT
      LAYER M5 ;
        RECT  30.048 64.584 30.072 64.776 ;
    END
  END o[227]
  PIN o[228]
    DIRECTION OUTPUT ;
    USE SIGNAL ;
    PORT
      LAYER M5 ;
        RECT  30.096 64.584 30.12 64.776 ;
    END
  END o[228]
  PIN o[229]
    DIRECTION OUTPUT ;
    USE SIGNAL ;
    PORT
      LAYER M5 ;
        RECT  30.144 64.584 30.168 64.776 ;
    END
  END o[229]
  PIN o[22]
    DIRECTION OUTPUT ;
    USE SIGNAL ;
    PORT
      LAYER M5 ;
        RECT  20.208 64.584 20.232 64.776 ;
    END
  END o[22]
  PIN o[230]
    DIRECTION OUTPUT ;
    USE SIGNAL ;
    PORT
      LAYER M5 ;
        RECT  30.192 64.584 30.216 64.776 ;
    END
  END o[230]
  PIN o[231]
    DIRECTION OUTPUT ;
    USE SIGNAL ;
    PORT
      LAYER M5 ;
        RECT  30.24 64.584 30.264 64.776 ;
    END
  END o[231]
  PIN o[232]
    DIRECTION OUTPUT ;
    USE SIGNAL ;
    PORT
      LAYER M5 ;
        RECT  30.288 64.584 30.312 64.776 ;
    END
  END o[232]
  PIN o[233]
    DIRECTION OUTPUT ;
    USE SIGNAL ;
    PORT
      LAYER M5 ;
        RECT  30.336 64.584 30.36 64.776 ;
    END
  END o[233]
  PIN o[234]
    DIRECTION OUTPUT ;
    USE SIGNAL ;
    PORT
      LAYER M5 ;
        RECT  30.384 64.584 30.408 64.776 ;
    END
  END o[234]
  PIN o[235]
    DIRECTION OUTPUT ;
    USE SIGNAL ;
    PORT
      LAYER M5 ;
        RECT  30.432 64.584 30.456 64.776 ;
    END
  END o[235]
  PIN o[236]
    DIRECTION OUTPUT ;
    USE SIGNAL ;
    PORT
      LAYER M5 ;
        RECT  30.48 64.584 30.504 64.776 ;
    END
  END o[236]
  PIN o[237]
    DIRECTION OUTPUT ;
    USE SIGNAL ;
    PORT
      LAYER M5 ;
        RECT  30.528 64.584 30.552 64.776 ;
    END
  END o[237]
  PIN o[238]
    DIRECTION OUTPUT ;
    USE SIGNAL ;
    PORT
      LAYER M5 ;
        RECT  30.576 64.584 30.6 64.776 ;
    END
  END o[238]
  PIN o[239]
    DIRECTION OUTPUT ;
    USE SIGNAL ;
    PORT
      LAYER M5 ;
        RECT  30.624 64.584 30.648 64.776 ;
    END
  END o[239]
  PIN o[23]
    DIRECTION OUTPUT ;
    USE SIGNAL ;
    PORT
      LAYER M5 ;
        RECT  20.256 64.584 20.28 64.776 ;
    END
  END o[23]
  PIN o[240]
    DIRECTION OUTPUT ;
    USE SIGNAL ;
    PORT
      LAYER M5 ;
        RECT  30.672 64.584 30.696 64.776 ;
    END
  END o[240]
  PIN o[241]
    DIRECTION OUTPUT ;
    USE SIGNAL ;
    PORT
      LAYER M5 ;
        RECT  30.72 64.584 30.744 64.776 ;
    END
  END o[241]
  PIN o[242]
    DIRECTION OUTPUT ;
    USE SIGNAL ;
    PORT
      LAYER M5 ;
        RECT  30.768 64.584 30.792 64.776 ;
    END
  END o[242]
  PIN o[243]
    DIRECTION OUTPUT ;
    USE SIGNAL ;
    PORT
      LAYER M5 ;
        RECT  30.816 64.584 30.84 64.776 ;
    END
  END o[243]
  PIN o[244]
    DIRECTION OUTPUT ;
    USE SIGNAL ;
    PORT
      LAYER M5 ;
        RECT  30.864 64.584 30.888 64.776 ;
    END
  END o[244]
  PIN o[245]
    DIRECTION OUTPUT ;
    USE SIGNAL ;
    PORT
      LAYER M5 ;
        RECT  30.912 64.584 30.936 64.776 ;
    END
  END o[245]
  PIN o[246]
    DIRECTION OUTPUT ;
    USE SIGNAL ;
    PORT
      LAYER M5 ;
        RECT  30.96 64.584 30.984 64.776 ;
    END
  END o[246]
  PIN o[247]
    DIRECTION OUTPUT ;
    USE SIGNAL ;
    PORT
      LAYER M5 ;
        RECT  31.008 64.584 31.032 64.776 ;
    END
  END o[247]
  PIN o[248]
    DIRECTION OUTPUT ;
    USE SIGNAL ;
    PORT
      LAYER M5 ;
        RECT  31.056 64.584 31.08 64.776 ;
    END
  END o[248]
  PIN o[249]
    DIRECTION OUTPUT ;
    USE SIGNAL ;
    PORT
      LAYER M5 ;
        RECT  31.104 64.584 31.128 64.776 ;
    END
  END o[249]
  PIN o[24]
    DIRECTION OUTPUT ;
    USE SIGNAL ;
    PORT
      LAYER M5 ;
        RECT  20.304 64.584 20.328 64.776 ;
    END
  END o[24]
  PIN o[250]
    DIRECTION OUTPUT ;
    USE SIGNAL ;
    PORT
      LAYER M5 ;
        RECT  31.152 64.584 31.176 64.776 ;
    END
  END o[250]
  PIN o[251]
    DIRECTION OUTPUT ;
    USE SIGNAL ;
    PORT
      LAYER M5 ;
        RECT  31.2 64.584 31.224 64.776 ;
    END
  END o[251]
  PIN o[252]
    DIRECTION OUTPUT ;
    USE SIGNAL ;
    PORT
      LAYER M5 ;
        RECT  31.248 64.584 31.272 64.776 ;
    END
  END o[252]
  PIN o[253]
    DIRECTION OUTPUT ;
    USE SIGNAL ;
    PORT
      LAYER M5 ;
        RECT  31.296 64.584 31.32 64.776 ;
    END
  END o[253]
  PIN o[254]
    DIRECTION OUTPUT ;
    USE SIGNAL ;
    PORT
      LAYER M5 ;
        RECT  31.344 64.584 31.368 64.776 ;
    END
  END o[254]
  PIN o[255]
    DIRECTION OUTPUT ;
    USE SIGNAL ;
    PORT
      LAYER M5 ;
        RECT  31.392 64.584 31.416 64.776 ;
    END
  END o[255]
  PIN o[256]
    DIRECTION OUTPUT ;
    USE SIGNAL ;
    PORT
      LAYER M5 ;
        RECT  31.44 64.584 31.464 64.776 ;
    END
  END o[256]
  PIN o[257]
    DIRECTION OUTPUT ;
    USE SIGNAL ;
    PORT
      LAYER M5 ;
        RECT  31.488 64.584 31.512 64.776 ;
    END
  END o[257]
  PIN o[258]
    DIRECTION OUTPUT ;
    USE SIGNAL ;
    PORT
      LAYER M5 ;
        RECT  31.536 64.584 31.56 64.776 ;
    END
  END o[258]
  PIN o[259]
    DIRECTION OUTPUT ;
    USE SIGNAL ;
    PORT
      LAYER M5 ;
        RECT  31.584 64.584 31.608 64.776 ;
    END
  END o[259]
  PIN o[25]
    DIRECTION OUTPUT ;
    USE SIGNAL ;
    PORT
      LAYER M5 ;
        RECT  20.352 64.584 20.376 64.776 ;
    END
  END o[25]
  PIN o[260]
    DIRECTION OUTPUT ;
    USE SIGNAL ;
    PORT
      LAYER M5 ;
        RECT  31.632 64.584 31.656 64.776 ;
    END
  END o[260]
  PIN o[261]
    DIRECTION OUTPUT ;
    USE SIGNAL ;
    PORT
      LAYER M5 ;
        RECT  31.68 64.584 31.704 64.776 ;
    END
  END o[261]
  PIN o[262]
    DIRECTION OUTPUT ;
    USE SIGNAL ;
    PORT
      LAYER M5 ;
        RECT  31.728 64.584 31.752 64.776 ;
    END
  END o[262]
  PIN o[263]
    DIRECTION OUTPUT ;
    USE SIGNAL ;
    PORT
      LAYER M5 ;
        RECT  31.776 64.584 31.8 64.776 ;
    END
  END o[263]
  PIN o[264]
    DIRECTION OUTPUT ;
    USE SIGNAL ;
    PORT
      LAYER M5 ;
        RECT  31.824 64.584 31.848 64.776 ;
    END
  END o[264]
  PIN o[265]
    DIRECTION OUTPUT ;
    USE SIGNAL ;
    PORT
      LAYER M5 ;
        RECT  31.872 64.584 31.896 64.776 ;
    END
  END o[265]
  PIN o[266]
    DIRECTION OUTPUT ;
    USE SIGNAL ;
    PORT
      LAYER M5 ;
        RECT  31.92 64.584 31.944 64.776 ;
    END
  END o[266]
  PIN o[267]
    DIRECTION OUTPUT ;
    USE SIGNAL ;
    PORT
      LAYER M5 ;
        RECT  31.968 64.584 31.992 64.776 ;
    END
  END o[267]
  PIN o[268]
    DIRECTION OUTPUT ;
    USE SIGNAL ;
    PORT
      LAYER M5 ;
        RECT  32.016 64.584 32.04 64.776 ;
    END
  END o[268]
  PIN o[269]
    DIRECTION OUTPUT ;
    USE SIGNAL ;
    PORT
      LAYER M5 ;
        RECT  32.064 64.584 32.088 64.776 ;
    END
  END o[269]
  PIN o[26]
    DIRECTION OUTPUT ;
    USE SIGNAL ;
    PORT
      LAYER M5 ;
        RECT  20.4 64.584 20.424 64.776 ;
    END
  END o[26]
  PIN o[270]
    DIRECTION OUTPUT ;
    USE SIGNAL ;
    PORT
      LAYER M5 ;
        RECT  32.112 64.584 32.136 64.776 ;
    END
  END o[270]
  PIN o[271]
    DIRECTION OUTPUT ;
    USE SIGNAL ;
    PORT
      LAYER M5 ;
        RECT  32.16 64.584 32.184 64.776 ;
    END
  END o[271]
  PIN o[272]
    DIRECTION OUTPUT ;
    USE SIGNAL ;
    PORT
      LAYER M5 ;
        RECT  32.208 64.584 32.232 64.776 ;
    END
  END o[272]
  PIN o[273]
    DIRECTION OUTPUT ;
    USE SIGNAL ;
    PORT
      LAYER M5 ;
        RECT  32.256 64.584 32.28 64.776 ;
    END
  END o[273]
  PIN o[274]
    DIRECTION OUTPUT ;
    USE SIGNAL ;
    PORT
      LAYER M5 ;
        RECT  32.304 64.584 32.328 64.776 ;
    END
  END o[274]
  PIN o[275]
    DIRECTION OUTPUT ;
    USE SIGNAL ;
    PORT
      LAYER M5 ;
        RECT  32.352 64.584 32.376 64.776 ;
    END
  END o[275]
  PIN o[276]
    DIRECTION OUTPUT ;
    USE SIGNAL ;
    PORT
      LAYER M5 ;
        RECT  32.4 64.584 32.424 64.776 ;
    END
  END o[276]
  PIN o[277]
    DIRECTION OUTPUT ;
    USE SIGNAL ;
    PORT
      LAYER M5 ;
        RECT  32.448 64.584 32.472 64.776 ;
    END
  END o[277]
  PIN o[278]
    DIRECTION OUTPUT ;
    USE SIGNAL ;
    PORT
      LAYER M5 ;
        RECT  32.496 64.584 32.52 64.776 ;
    END
  END o[278]
  PIN o[279]
    DIRECTION OUTPUT ;
    USE SIGNAL ;
    PORT
      LAYER M5 ;
        RECT  32.544 64.584 32.568 64.776 ;
    END
  END o[279]
  PIN o[27]
    DIRECTION OUTPUT ;
    USE SIGNAL ;
    PORT
      LAYER M5 ;
        RECT  20.448 64.584 20.472 64.776 ;
    END
  END o[27]
  PIN o[280]
    DIRECTION OUTPUT ;
    USE SIGNAL ;
    PORT
      LAYER M5 ;
        RECT  32.592 64.584 32.616 64.776 ;
    END
  END o[280]
  PIN o[281]
    DIRECTION OUTPUT ;
    USE SIGNAL ;
    PORT
      LAYER M5 ;
        RECT  32.64 64.584 32.664 64.776 ;
    END
  END o[281]
  PIN o[282]
    DIRECTION OUTPUT ;
    USE SIGNAL ;
    PORT
      LAYER M5 ;
        RECT  32.688 64.584 32.712 64.776 ;
    END
  END o[282]
  PIN o[283]
    DIRECTION OUTPUT ;
    USE SIGNAL ;
    PORT
      LAYER M5 ;
        RECT  32.736 64.584 32.76 64.776 ;
    END
  END o[283]
  PIN o[284]
    DIRECTION OUTPUT ;
    USE SIGNAL ;
    PORT
      LAYER M5 ;
        RECT  32.784 64.584 32.808 64.776 ;
    END
  END o[284]
  PIN o[285]
    DIRECTION OUTPUT ;
    USE SIGNAL ;
    PORT
      LAYER M5 ;
        RECT  32.832 64.584 32.856 64.776 ;
    END
  END o[285]
  PIN o[286]
    DIRECTION OUTPUT ;
    USE SIGNAL ;
    PORT
      LAYER M5 ;
        RECT  32.88 64.584 32.904 64.776 ;
    END
  END o[286]
  PIN o[287]
    DIRECTION OUTPUT ;
    USE SIGNAL ;
    PORT
      LAYER M5 ;
        RECT  32.928 64.584 32.952 64.776 ;
    END
  END o[287]
  PIN o[288]
    DIRECTION OUTPUT ;
    USE SIGNAL ;
    PORT
      LAYER M5 ;
        RECT  32.976 64.584 33 64.776 ;
    END
  END o[288]
  PIN o[289]
    DIRECTION OUTPUT ;
    USE SIGNAL ;
    PORT
      LAYER M5 ;
        RECT  33.024 64.584 33.048 64.776 ;
    END
  END o[289]
  PIN o[28]
    DIRECTION OUTPUT ;
    USE SIGNAL ;
    PORT
      LAYER M5 ;
        RECT  20.496 64.584 20.52 64.776 ;
    END
  END o[28]
  PIN o[290]
    DIRECTION OUTPUT ;
    USE SIGNAL ;
    PORT
      LAYER M5 ;
        RECT  33.072 64.584 33.096 64.776 ;
    END
  END o[290]
  PIN o[291]
    DIRECTION OUTPUT ;
    USE SIGNAL ;
    PORT
      LAYER M5 ;
        RECT  33.12 64.584 33.144 64.776 ;
    END
  END o[291]
  PIN o[292]
    DIRECTION OUTPUT ;
    USE SIGNAL ;
    PORT
      LAYER M5 ;
        RECT  33.168 64.584 33.192 64.776 ;
    END
  END o[292]
  PIN o[293]
    DIRECTION OUTPUT ;
    USE SIGNAL ;
    PORT
      LAYER M5 ;
        RECT  33.216 64.584 33.24 64.776 ;
    END
  END o[293]
  PIN o[294]
    DIRECTION OUTPUT ;
    USE SIGNAL ;
    PORT
      LAYER M5 ;
        RECT  33.264 64.584 33.288 64.776 ;
    END
  END o[294]
  PIN o[295]
    DIRECTION OUTPUT ;
    USE SIGNAL ;
    PORT
      LAYER M5 ;
        RECT  33.312 64.584 33.336 64.776 ;
    END
  END o[295]
  PIN o[296]
    DIRECTION OUTPUT ;
    USE SIGNAL ;
    PORT
      LAYER M5 ;
        RECT  33.36 64.584 33.384 64.776 ;
    END
  END o[296]
  PIN o[297]
    DIRECTION OUTPUT ;
    USE SIGNAL ;
    PORT
      LAYER M5 ;
        RECT  33.408 64.584 33.432 64.776 ;
    END
  END o[297]
  PIN o[298]
    DIRECTION OUTPUT ;
    USE SIGNAL ;
    PORT
      LAYER M5 ;
        RECT  33.456 64.584 33.48 64.776 ;
    END
  END o[298]
  PIN o[299]
    DIRECTION OUTPUT ;
    USE SIGNAL ;
    PORT
      LAYER M5 ;
        RECT  33.504 64.584 33.528 64.776 ;
    END
  END o[299]
  PIN o[29]
    DIRECTION OUTPUT ;
    USE SIGNAL ;
    PORT
      LAYER M5 ;
        RECT  20.544 64.584 20.568 64.776 ;
    END
  END o[29]
  PIN o[2]
    DIRECTION OUTPUT ;
    USE SIGNAL ;
    PORT
      LAYER M5 ;
        RECT  19.248 64.584 19.272 64.776 ;
    END
  END o[2]
  PIN o[300]
    DIRECTION OUTPUT ;
    USE SIGNAL ;
    PORT
      LAYER M5 ;
        RECT  33.552 64.584 33.576 64.776 ;
    END
  END o[300]
  PIN o[301]
    DIRECTION OUTPUT ;
    USE SIGNAL ;
    PORT
      LAYER M5 ;
        RECT  33.6 64.584 33.624 64.776 ;
    END
  END o[301]
  PIN o[302]
    DIRECTION OUTPUT ;
    USE SIGNAL ;
    PORT
      LAYER M5 ;
        RECT  33.648 64.584 33.672 64.776 ;
    END
  END o[302]
  PIN o[303]
    DIRECTION OUTPUT ;
    USE SIGNAL ;
    PORT
      LAYER M5 ;
        RECT  33.696 64.584 33.72 64.776 ;
    END
  END o[303]
  PIN o[304]
    DIRECTION OUTPUT ;
    USE SIGNAL ;
    PORT
      LAYER M5 ;
        RECT  33.744 64.584 33.768 64.776 ;
    END
  END o[304]
  PIN o[305]
    DIRECTION OUTPUT ;
    USE SIGNAL ;
    PORT
      LAYER M5 ;
        RECT  33.792 64.584 33.816 64.776 ;
    END
  END o[305]
  PIN o[306]
    DIRECTION OUTPUT ;
    USE SIGNAL ;
    PORT
      LAYER M5 ;
        RECT  33.84 64.584 33.864 64.776 ;
    END
  END o[306]
  PIN o[307]
    DIRECTION OUTPUT ;
    USE SIGNAL ;
    PORT
      LAYER M5 ;
        RECT  33.888 64.584 33.912 64.776 ;
    END
  END o[307]
  PIN o[308]
    DIRECTION OUTPUT ;
    USE SIGNAL ;
    PORT
      LAYER M5 ;
        RECT  33.936 64.584 33.96 64.776 ;
    END
  END o[308]
  PIN o[309]
    DIRECTION OUTPUT ;
    USE SIGNAL ;
    PORT
      LAYER M5 ;
        RECT  33.984 64.584 34.008 64.776 ;
    END
  END o[309]
  PIN o[30]
    DIRECTION OUTPUT ;
    USE SIGNAL ;
    PORT
      LAYER M5 ;
        RECT  20.592 64.584 20.616 64.776 ;
    END
  END o[30]
  PIN o[310]
    DIRECTION OUTPUT ;
    USE SIGNAL ;
    PORT
      LAYER M5 ;
        RECT  34.032 64.584 34.056 64.776 ;
    END
  END o[310]
  PIN o[311]
    DIRECTION OUTPUT ;
    USE SIGNAL ;
    PORT
      LAYER M5 ;
        RECT  34.08 64.584 34.104 64.776 ;
    END
  END o[311]
  PIN o[312]
    DIRECTION OUTPUT ;
    USE SIGNAL ;
    PORT
      LAYER M5 ;
        RECT  34.128 64.584 34.152 64.776 ;
    END
  END o[312]
  PIN o[313]
    DIRECTION OUTPUT ;
    USE SIGNAL ;
    PORT
      LAYER M5 ;
        RECT  34.176 64.584 34.2 64.776 ;
    END
  END o[313]
  PIN o[314]
    DIRECTION OUTPUT ;
    USE SIGNAL ;
    PORT
      LAYER M5 ;
        RECT  34.224 64.584 34.248 64.776 ;
    END
  END o[314]
  PIN o[315]
    DIRECTION OUTPUT ;
    USE SIGNAL ;
    PORT
      LAYER M5 ;
        RECT  34.272 64.584 34.296 64.776 ;
    END
  END o[315]
  PIN o[316]
    DIRECTION OUTPUT ;
    USE SIGNAL ;
    PORT
      LAYER M5 ;
        RECT  34.32 64.584 34.344 64.776 ;
    END
  END o[316]
  PIN o[317]
    DIRECTION OUTPUT ;
    USE SIGNAL ;
    PORT
      LAYER M5 ;
        RECT  34.368 64.584 34.392 64.776 ;
    END
  END o[317]
  PIN o[318]
    DIRECTION OUTPUT ;
    USE SIGNAL ;
    PORT
      LAYER M5 ;
        RECT  34.416 64.584 34.44 64.776 ;
    END
  END o[318]
  PIN o[319]
    DIRECTION OUTPUT ;
    USE SIGNAL ;
    PORT
      LAYER M5 ;
        RECT  34.464 64.584 34.488 64.776 ;
    END
  END o[319]
  PIN o[31]
    DIRECTION OUTPUT ;
    USE SIGNAL ;
    PORT
      LAYER M5 ;
        RECT  20.64 64.584 20.664 64.776 ;
    END
  END o[31]
  PIN o[320]
    DIRECTION OUTPUT ;
    USE SIGNAL ;
    PORT
      LAYER M5 ;
        RECT  34.512 64.584 34.536 64.776 ;
    END
  END o[320]
  PIN o[321]
    DIRECTION OUTPUT ;
    USE SIGNAL ;
    PORT
      LAYER M5 ;
        RECT  34.56 64.584 34.584 64.776 ;
    END
  END o[321]
  PIN o[322]
    DIRECTION OUTPUT ;
    USE SIGNAL ;
    PORT
      LAYER M5 ;
        RECT  34.608 64.584 34.632 64.776 ;
    END
  END o[322]
  PIN o[323]
    DIRECTION OUTPUT ;
    USE SIGNAL ;
    PORT
      LAYER M5 ;
        RECT  34.656 64.584 34.68 64.776 ;
    END
  END o[323]
  PIN o[324]
    DIRECTION OUTPUT ;
    USE SIGNAL ;
    PORT
      LAYER M5 ;
        RECT  34.704 64.584 34.728 64.776 ;
    END
  END o[324]
  PIN o[325]
    DIRECTION OUTPUT ;
    USE SIGNAL ;
    PORT
      LAYER M5 ;
        RECT  34.752 64.584 34.776 64.776 ;
    END
  END o[325]
  PIN o[326]
    DIRECTION OUTPUT ;
    USE SIGNAL ;
    PORT
      LAYER M5 ;
        RECT  34.8 64.584 34.824 64.776 ;
    END
  END o[326]
  PIN o[327]
    DIRECTION OUTPUT ;
    USE SIGNAL ;
    PORT
      LAYER M5 ;
        RECT  34.848 64.584 34.872 64.776 ;
    END
  END o[327]
  PIN o[328]
    DIRECTION OUTPUT ;
    USE SIGNAL ;
    PORT
      LAYER M5 ;
        RECT  34.896 64.584 34.92 64.776 ;
    END
  END o[328]
  PIN o[329]
    DIRECTION OUTPUT ;
    USE SIGNAL ;
    PORT
      LAYER M5 ;
        RECT  34.944 64.584 34.968 64.776 ;
    END
  END o[329]
  PIN o[32]
    DIRECTION OUTPUT ;
    USE SIGNAL ;
    PORT
      LAYER M5 ;
        RECT  20.688 64.584 20.712 64.776 ;
    END
  END o[32]
  PIN o[330]
    DIRECTION OUTPUT ;
    USE SIGNAL ;
    PORT
      LAYER M5 ;
        RECT  34.992 64.584 35.016 64.776 ;
    END
  END o[330]
  PIN o[331]
    DIRECTION OUTPUT ;
    USE SIGNAL ;
    PORT
      LAYER M5 ;
        RECT  35.04 64.584 35.064 64.776 ;
    END
  END o[331]
  PIN o[332]
    DIRECTION OUTPUT ;
    USE SIGNAL ;
    PORT
      LAYER M5 ;
        RECT  35.088 64.584 35.112 64.776 ;
    END
  END o[332]
  PIN o[333]
    DIRECTION OUTPUT ;
    USE SIGNAL ;
    PORT
      LAYER M5 ;
        RECT  35.136 64.584 35.16 64.776 ;
    END
  END o[333]
  PIN o[334]
    DIRECTION OUTPUT ;
    USE SIGNAL ;
    PORT
      LAYER M5 ;
        RECT  35.184 64.584 35.208 64.776 ;
    END
  END o[334]
  PIN o[335]
    DIRECTION OUTPUT ;
    USE SIGNAL ;
    PORT
      LAYER M5 ;
        RECT  35.232 64.584 35.256 64.776 ;
    END
  END o[335]
  PIN o[336]
    DIRECTION OUTPUT ;
    USE SIGNAL ;
    PORT
      LAYER M5 ;
        RECT  35.28 64.584 35.304 64.776 ;
    END
  END o[336]
  PIN o[337]
    DIRECTION OUTPUT ;
    USE SIGNAL ;
    PORT
      LAYER M5 ;
        RECT  35.328 64.584 35.352 64.776 ;
    END
  END o[337]
  PIN o[338]
    DIRECTION OUTPUT ;
    USE SIGNAL ;
    PORT
      LAYER M5 ;
        RECT  35.376 64.584 35.4 64.776 ;
    END
  END o[338]
  PIN o[339]
    DIRECTION OUTPUT ;
    USE SIGNAL ;
    PORT
      LAYER M5 ;
        RECT  35.424 64.584 35.448 64.776 ;
    END
  END o[339]
  PIN o[33]
    DIRECTION OUTPUT ;
    USE SIGNAL ;
    PORT
      LAYER M5 ;
        RECT  20.736 64.584 20.76 64.776 ;
    END
  END o[33]
  PIN o[340]
    DIRECTION OUTPUT ;
    USE SIGNAL ;
    PORT
      LAYER M5 ;
        RECT  35.472 64.584 35.496 64.776 ;
    END
  END o[340]
  PIN o[341]
    DIRECTION OUTPUT ;
    USE SIGNAL ;
    PORT
      LAYER M5 ;
        RECT  35.52 64.584 35.544 64.776 ;
    END
  END o[341]
  PIN o[342]
    DIRECTION OUTPUT ;
    USE SIGNAL ;
    PORT
      LAYER M5 ;
        RECT  35.568 64.584 35.592 64.776 ;
    END
  END o[342]
  PIN o[343]
    DIRECTION OUTPUT ;
    USE SIGNAL ;
    PORT
      LAYER M5 ;
        RECT  35.616 64.584 35.64 64.776 ;
    END
  END o[343]
  PIN o[344]
    DIRECTION OUTPUT ;
    USE SIGNAL ;
    PORT
      LAYER M5 ;
        RECT  35.664 64.584 35.688 64.776 ;
    END
  END o[344]
  PIN o[345]
    DIRECTION OUTPUT ;
    USE SIGNAL ;
    PORT
      LAYER M5 ;
        RECT  35.712 64.584 35.736 64.776 ;
    END
  END o[345]
  PIN o[346]
    DIRECTION OUTPUT ;
    USE SIGNAL ;
    PORT
      LAYER M5 ;
        RECT  35.76 64.584 35.784 64.776 ;
    END
  END o[346]
  PIN o[347]
    DIRECTION OUTPUT ;
    USE SIGNAL ;
    PORT
      LAYER M5 ;
        RECT  35.808 64.584 35.832 64.776 ;
    END
  END o[347]
  PIN o[348]
    DIRECTION OUTPUT ;
    USE SIGNAL ;
    PORT
      LAYER M5 ;
        RECT  35.856 64.584 35.88 64.776 ;
    END
  END o[348]
  PIN o[349]
    DIRECTION OUTPUT ;
    USE SIGNAL ;
    PORT
      LAYER M5 ;
        RECT  35.904 64.584 35.928 64.776 ;
    END
  END o[349]
  PIN o[34]
    DIRECTION OUTPUT ;
    USE SIGNAL ;
    PORT
      LAYER M5 ;
        RECT  20.784 64.584 20.808 64.776 ;
    END
  END o[34]
  PIN o[350]
    DIRECTION OUTPUT ;
    USE SIGNAL ;
    PORT
      LAYER M5 ;
        RECT  35.952 64.584 35.976 64.776 ;
    END
  END o[350]
  PIN o[351]
    DIRECTION OUTPUT ;
    USE SIGNAL ;
    PORT
      LAYER M5 ;
        RECT  36 64.584 36.024 64.776 ;
    END
  END o[351]
  PIN o[352]
    DIRECTION OUTPUT ;
    USE SIGNAL ;
    PORT
      LAYER M5 ;
        RECT  36.048 64.584 36.072 64.776 ;
    END
  END o[352]
  PIN o[353]
    DIRECTION OUTPUT ;
    USE SIGNAL ;
    PORT
      LAYER M5 ;
        RECT  36.096 64.584 36.12 64.776 ;
    END
  END o[353]
  PIN o[354]
    DIRECTION OUTPUT ;
    USE SIGNAL ;
    PORT
      LAYER M5 ;
        RECT  36.144 64.584 36.168 64.776 ;
    END
  END o[354]
  PIN o[355]
    DIRECTION OUTPUT ;
    USE SIGNAL ;
    PORT
      LAYER M5 ;
        RECT  36.192 64.584 36.216 64.776 ;
    END
  END o[355]
  PIN o[356]
    DIRECTION OUTPUT ;
    USE SIGNAL ;
    PORT
      LAYER M5 ;
        RECT  36.24 64.584 36.264 64.776 ;
    END
  END o[356]
  PIN o[357]
    DIRECTION OUTPUT ;
    USE SIGNAL ;
    PORT
      LAYER M5 ;
        RECT  36.288 64.584 36.312 64.776 ;
    END
  END o[357]
  PIN o[358]
    DIRECTION OUTPUT ;
    USE SIGNAL ;
    PORT
      LAYER M5 ;
        RECT  36.336 64.584 36.36 64.776 ;
    END
  END o[358]
  PIN o[359]
    DIRECTION OUTPUT ;
    USE SIGNAL ;
    PORT
      LAYER M5 ;
        RECT  36.384 64.584 36.408 64.776 ;
    END
  END o[359]
  PIN o[35]
    DIRECTION OUTPUT ;
    USE SIGNAL ;
    PORT
      LAYER M5 ;
        RECT  20.832 64.584 20.856 64.776 ;
    END
  END o[35]
  PIN o[360]
    DIRECTION OUTPUT ;
    USE SIGNAL ;
    PORT
      LAYER M5 ;
        RECT  36.432 64.584 36.456 64.776 ;
    END
  END o[360]
  PIN o[361]
    DIRECTION OUTPUT ;
    USE SIGNAL ;
    PORT
      LAYER M5 ;
        RECT  36.48 64.584 36.504 64.776 ;
    END
  END o[361]
  PIN o[362]
    DIRECTION OUTPUT ;
    USE SIGNAL ;
    PORT
      LAYER M5 ;
        RECT  36.528 64.584 36.552 64.776 ;
    END
  END o[362]
  PIN o[363]
    DIRECTION OUTPUT ;
    USE SIGNAL ;
    PORT
      LAYER M5 ;
        RECT  36.576 64.584 36.6 64.776 ;
    END
  END o[363]
  PIN o[364]
    DIRECTION OUTPUT ;
    USE SIGNAL ;
    PORT
      LAYER M5 ;
        RECT  36.624 64.584 36.648 64.776 ;
    END
  END o[364]
  PIN o[365]
    DIRECTION OUTPUT ;
    USE SIGNAL ;
    PORT
      LAYER M5 ;
        RECT  36.672 64.584 36.696 64.776 ;
    END
  END o[365]
  PIN o[366]
    DIRECTION OUTPUT ;
    USE SIGNAL ;
    PORT
      LAYER M5 ;
        RECT  36.72 64.584 36.744 64.776 ;
    END
  END o[366]
  PIN o[367]
    DIRECTION OUTPUT ;
    USE SIGNAL ;
    PORT
      LAYER M5 ;
        RECT  36.768 64.584 36.792 64.776 ;
    END
  END o[367]
  PIN o[368]
    DIRECTION OUTPUT ;
    USE SIGNAL ;
    PORT
      LAYER M5 ;
        RECT  36.816 64.584 36.84 64.776 ;
    END
  END o[368]
  PIN o[369]
    DIRECTION OUTPUT ;
    USE SIGNAL ;
    PORT
      LAYER M5 ;
        RECT  36.864 64.584 36.888 64.776 ;
    END
  END o[369]
  PIN o[36]
    DIRECTION OUTPUT ;
    USE SIGNAL ;
    PORT
      LAYER M5 ;
        RECT  20.88 64.584 20.904 64.776 ;
    END
  END o[36]
  PIN o[370]
    DIRECTION OUTPUT ;
    USE SIGNAL ;
    PORT
      LAYER M5 ;
        RECT  36.912 64.584 36.936 64.776 ;
    END
  END o[370]
  PIN o[371]
    DIRECTION OUTPUT ;
    USE SIGNAL ;
    PORT
      LAYER M5 ;
        RECT  36.96 64.584 36.984 64.776 ;
    END
  END o[371]
  PIN o[372]
    DIRECTION OUTPUT ;
    USE SIGNAL ;
    PORT
      LAYER M5 ;
        RECT  37.008 64.584 37.032 64.776 ;
    END
  END o[372]
  PIN o[373]
    DIRECTION OUTPUT ;
    USE SIGNAL ;
    PORT
      LAYER M5 ;
        RECT  37.056 64.584 37.08 64.776 ;
    END
  END o[373]
  PIN o[374]
    DIRECTION OUTPUT ;
    USE SIGNAL ;
    PORT
      LAYER M5 ;
        RECT  37.104 64.584 37.128 64.776 ;
    END
  END o[374]
  PIN o[375]
    DIRECTION OUTPUT ;
    USE SIGNAL ;
    PORT
      LAYER M5 ;
        RECT  37.152 64.584 37.176 64.776 ;
    END
  END o[375]
  PIN o[376]
    DIRECTION OUTPUT ;
    USE SIGNAL ;
    PORT
      LAYER M5 ;
        RECT  37.2 64.584 37.224 64.776 ;
    END
  END o[376]
  PIN o[377]
    DIRECTION OUTPUT ;
    USE SIGNAL ;
    PORT
      LAYER M5 ;
        RECT  37.248 64.584 37.272 64.776 ;
    END
  END o[377]
  PIN o[378]
    DIRECTION OUTPUT ;
    USE SIGNAL ;
    PORT
      LAYER M5 ;
        RECT  37.296 64.584 37.32 64.776 ;
    END
  END o[378]
  PIN o[379]
    DIRECTION OUTPUT ;
    USE SIGNAL ;
    PORT
      LAYER M5 ;
        RECT  37.344 64.584 37.368 64.776 ;
    END
  END o[379]
  PIN o[37]
    DIRECTION OUTPUT ;
    USE SIGNAL ;
    PORT
      LAYER M5 ;
        RECT  20.928 64.584 20.952 64.776 ;
    END
  END o[37]
  PIN o[380]
    DIRECTION OUTPUT ;
    USE SIGNAL ;
    PORT
      LAYER M5 ;
        RECT  37.392 64.584 37.416 64.776 ;
    END
  END o[380]
  PIN o[381]
    DIRECTION OUTPUT ;
    USE SIGNAL ;
    PORT
      LAYER M5 ;
        RECT  37.44 64.584 37.464 64.776 ;
    END
  END o[381]
  PIN o[382]
    DIRECTION OUTPUT ;
    USE SIGNAL ;
    PORT
      LAYER M5 ;
        RECT  37.488 64.584 37.512 64.776 ;
    END
  END o[382]
  PIN o[383]
    DIRECTION OUTPUT ;
    USE SIGNAL ;
    PORT
      LAYER M5 ;
        RECT  37.536 64.584 37.56 64.776 ;
    END
  END o[383]
  PIN o[384]
    DIRECTION OUTPUT ;
    USE SIGNAL ;
    PORT
      LAYER M5 ;
        RECT  37.584 64.584 37.608 64.776 ;
    END
  END o[384]
  PIN o[385]
    DIRECTION OUTPUT ;
    USE SIGNAL ;
    PORT
      LAYER M5 ;
        RECT  37.632 64.584 37.656 64.776 ;
    END
  END o[385]
  PIN o[386]
    DIRECTION OUTPUT ;
    USE SIGNAL ;
    PORT
      LAYER M5 ;
        RECT  37.68 64.584 37.704 64.776 ;
    END
  END o[386]
  PIN o[387]
    DIRECTION OUTPUT ;
    USE SIGNAL ;
    PORT
      LAYER M5 ;
        RECT  37.728 64.584 37.752 64.776 ;
    END
  END o[387]
  PIN o[388]
    DIRECTION OUTPUT ;
    USE SIGNAL ;
    PORT
      LAYER M5 ;
        RECT  37.776 64.584 37.8 64.776 ;
    END
  END o[388]
  PIN o[389]
    DIRECTION OUTPUT ;
    USE SIGNAL ;
    PORT
      LAYER M5 ;
        RECT  37.824 64.584 37.848 64.776 ;
    END
  END o[389]
  PIN o[38]
    DIRECTION OUTPUT ;
    USE SIGNAL ;
    PORT
      LAYER M5 ;
        RECT  20.976 64.584 21 64.776 ;
    END
  END o[38]
  PIN o[390]
    DIRECTION OUTPUT ;
    USE SIGNAL ;
    PORT
      LAYER M5 ;
        RECT  37.872 64.584 37.896 64.776 ;
    END
  END o[390]
  PIN o[391]
    DIRECTION OUTPUT ;
    USE SIGNAL ;
    PORT
      LAYER M5 ;
        RECT  37.92 64.584 37.944 64.776 ;
    END
  END o[391]
  PIN o[392]
    DIRECTION OUTPUT ;
    USE SIGNAL ;
    PORT
      LAYER M5 ;
        RECT  37.968 64.584 37.992 64.776 ;
    END
  END o[392]
  PIN o[393]
    DIRECTION OUTPUT ;
    USE SIGNAL ;
    PORT
      LAYER M5 ;
        RECT  38.016 64.584 38.04 64.776 ;
    END
  END o[393]
  PIN o[394]
    DIRECTION OUTPUT ;
    USE SIGNAL ;
    PORT
      LAYER M5 ;
        RECT  38.064 64.584 38.088 64.776 ;
    END
  END o[394]
  PIN o[395]
    DIRECTION OUTPUT ;
    USE SIGNAL ;
    PORT
      LAYER M5 ;
        RECT  38.112 64.584 38.136 64.776 ;
    END
  END o[395]
  PIN o[396]
    DIRECTION OUTPUT ;
    USE SIGNAL ;
    PORT
      LAYER M5 ;
        RECT  38.16 64.584 38.184 64.776 ;
    END
  END o[396]
  PIN o[397]
    DIRECTION OUTPUT ;
    USE SIGNAL ;
    PORT
      LAYER M5 ;
        RECT  38.208 64.584 38.232 64.776 ;
    END
  END o[397]
  PIN o[398]
    DIRECTION OUTPUT ;
    USE SIGNAL ;
    PORT
      LAYER M5 ;
        RECT  38.256 64.584 38.28 64.776 ;
    END
  END o[398]
  PIN o[399]
    DIRECTION OUTPUT ;
    USE SIGNAL ;
    PORT
      LAYER M5 ;
        RECT  38.304 64.584 38.328 64.776 ;
    END
  END o[399]
  PIN o[39]
    DIRECTION OUTPUT ;
    USE SIGNAL ;
    PORT
      LAYER M5 ;
        RECT  21.024 64.584 21.048 64.776 ;
    END
  END o[39]
  PIN o[3]
    DIRECTION OUTPUT ;
    USE SIGNAL ;
    PORT
      LAYER M5 ;
        RECT  19.296 64.584 19.32 64.776 ;
    END
  END o[3]
  PIN o[400]
    DIRECTION OUTPUT ;
    USE SIGNAL ;
    PORT
      LAYER M5 ;
        RECT  38.352 64.584 38.376 64.776 ;
    END
  END o[400]
  PIN o[401]
    DIRECTION OUTPUT ;
    USE SIGNAL ;
    PORT
      LAYER M5 ;
        RECT  38.4 64.584 38.424 64.776 ;
    END
  END o[401]
  PIN o[402]
    DIRECTION OUTPUT ;
    USE SIGNAL ;
    PORT
      LAYER M5 ;
        RECT  38.448 64.584 38.472 64.776 ;
    END
  END o[402]
  PIN o[403]
    DIRECTION OUTPUT ;
    USE SIGNAL ;
    PORT
      LAYER M5 ;
        RECT  38.496 64.584 38.52 64.776 ;
    END
  END o[403]
  PIN o[404]
    DIRECTION OUTPUT ;
    USE SIGNAL ;
    PORT
      LAYER M5 ;
        RECT  38.544 64.584 38.568 64.776 ;
    END
  END o[404]
  PIN o[405]
    DIRECTION OUTPUT ;
    USE SIGNAL ;
    PORT
      LAYER M5 ;
        RECT  38.592 64.584 38.616 64.776 ;
    END
  END o[405]
  PIN o[406]
    DIRECTION OUTPUT ;
    USE SIGNAL ;
    PORT
      LAYER M5 ;
        RECT  38.64 64.584 38.664 64.776 ;
    END
  END o[406]
  PIN o[407]
    DIRECTION OUTPUT ;
    USE SIGNAL ;
    PORT
      LAYER M5 ;
        RECT  38.688 64.584 38.712 64.776 ;
    END
  END o[407]
  PIN o[408]
    DIRECTION OUTPUT ;
    USE SIGNAL ;
    PORT
      LAYER M5 ;
        RECT  38.736 64.584 38.76 64.776 ;
    END
  END o[408]
  PIN o[409]
    DIRECTION OUTPUT ;
    USE SIGNAL ;
    PORT
      LAYER M5 ;
        RECT  38.784 64.584 38.808 64.776 ;
    END
  END o[409]
  PIN o[40]
    DIRECTION OUTPUT ;
    USE SIGNAL ;
    PORT
      LAYER M5 ;
        RECT  21.072 64.584 21.096 64.776 ;
    END
  END o[40]
  PIN o[410]
    DIRECTION OUTPUT ;
    USE SIGNAL ;
    PORT
      LAYER M5 ;
        RECT  38.832 64.584 38.856 64.776 ;
    END
  END o[410]
  PIN o[411]
    DIRECTION OUTPUT ;
    USE SIGNAL ;
    PORT
      LAYER M5 ;
        RECT  38.88 64.584 38.904 64.776 ;
    END
  END o[411]
  PIN o[412]
    DIRECTION OUTPUT ;
    USE SIGNAL ;
    PORT
      LAYER M5 ;
        RECT  38.928 64.584 38.952 64.776 ;
    END
  END o[412]
  PIN o[413]
    DIRECTION OUTPUT ;
    USE SIGNAL ;
    PORT
      LAYER M5 ;
        RECT  38.976 64.584 39 64.776 ;
    END
  END o[413]
  PIN o[414]
    DIRECTION OUTPUT ;
    USE SIGNAL ;
    PORT
      LAYER M5 ;
        RECT  39.024 64.584 39.048 64.776 ;
    END
  END o[414]
  PIN o[415]
    DIRECTION OUTPUT ;
    USE SIGNAL ;
    PORT
      LAYER M5 ;
        RECT  39.072 64.584 39.096 64.776 ;
    END
  END o[415]
  PIN o[416]
    DIRECTION OUTPUT ;
    USE SIGNAL ;
    PORT
      LAYER M5 ;
        RECT  39.12 64.584 39.144 64.776 ;
    END
  END o[416]
  PIN o[417]
    DIRECTION OUTPUT ;
    USE SIGNAL ;
    PORT
      LAYER M5 ;
        RECT  39.168 64.584 39.192 64.776 ;
    END
  END o[417]
  PIN o[418]
    DIRECTION OUTPUT ;
    USE SIGNAL ;
    PORT
      LAYER M5 ;
        RECT  39.216 64.584 39.24 64.776 ;
    END
  END o[418]
  PIN o[419]
    DIRECTION OUTPUT ;
    USE SIGNAL ;
    PORT
      LAYER M5 ;
        RECT  39.264 64.584 39.288 64.776 ;
    END
  END o[419]
  PIN o[41]
    DIRECTION OUTPUT ;
    USE SIGNAL ;
    PORT
      LAYER M5 ;
        RECT  21.12 64.584 21.144 64.776 ;
    END
  END o[41]
  PIN o[420]
    DIRECTION OUTPUT ;
    USE SIGNAL ;
    PORT
      LAYER M5 ;
        RECT  39.312 64.584 39.336 64.776 ;
    END
  END o[420]
  PIN o[421]
    DIRECTION OUTPUT ;
    USE SIGNAL ;
    PORT
      LAYER M5 ;
        RECT  39.36 64.584 39.384 64.776 ;
    END
  END o[421]
  PIN o[422]
    DIRECTION OUTPUT ;
    USE SIGNAL ;
    PORT
      LAYER M5 ;
        RECT  39.408 64.584 39.432 64.776 ;
    END
  END o[422]
  PIN o[423]
    DIRECTION OUTPUT ;
    USE SIGNAL ;
    PORT
      LAYER M5 ;
        RECT  39.456 64.584 39.48 64.776 ;
    END
  END o[423]
  PIN o[424]
    DIRECTION OUTPUT ;
    USE SIGNAL ;
    PORT
      LAYER M5 ;
        RECT  39.504 64.584 39.528 64.776 ;
    END
  END o[424]
  PIN o[425]
    DIRECTION OUTPUT ;
    USE SIGNAL ;
    PORT
      LAYER M5 ;
        RECT  39.552 64.584 39.576 64.776 ;
    END
  END o[425]
  PIN o[426]
    DIRECTION OUTPUT ;
    USE SIGNAL ;
    PORT
      LAYER M5 ;
        RECT  39.6 64.584 39.624 64.776 ;
    END
  END o[426]
  PIN o[427]
    DIRECTION OUTPUT ;
    USE SIGNAL ;
    PORT
      LAYER M5 ;
        RECT  39.648 64.584 39.672 64.776 ;
    END
  END o[427]
  PIN o[428]
    DIRECTION OUTPUT ;
    USE SIGNAL ;
    PORT
      LAYER M5 ;
        RECT  39.696 64.584 39.72 64.776 ;
    END
  END o[428]
  PIN o[429]
    DIRECTION OUTPUT ;
    USE SIGNAL ;
    PORT
      LAYER M5 ;
        RECT  39.744 64.584 39.768 64.776 ;
    END
  END o[429]
  PIN o[42]
    DIRECTION OUTPUT ;
    USE SIGNAL ;
    PORT
      LAYER M5 ;
        RECT  21.168 64.584 21.192 64.776 ;
    END
  END o[42]
  PIN o[430]
    DIRECTION OUTPUT ;
    USE SIGNAL ;
    PORT
      LAYER M5 ;
        RECT  39.792 64.584 39.816 64.776 ;
    END
  END o[430]
  PIN o[431]
    DIRECTION OUTPUT ;
    USE SIGNAL ;
    PORT
      LAYER M5 ;
        RECT  39.84 64.584 39.864 64.776 ;
    END
  END o[431]
  PIN o[432]
    DIRECTION OUTPUT ;
    USE SIGNAL ;
    PORT
      LAYER M5 ;
        RECT  39.888 64.584 39.912 64.776 ;
    END
  END o[432]
  PIN o[433]
    DIRECTION OUTPUT ;
    USE SIGNAL ;
    PORT
      LAYER M5 ;
        RECT  39.936 64.584 39.96 64.776 ;
    END
  END o[433]
  PIN o[434]
    DIRECTION OUTPUT ;
    USE SIGNAL ;
    PORT
      LAYER M5 ;
        RECT  39.984 64.584 40.008 64.776 ;
    END
  END o[434]
  PIN o[435]
    DIRECTION OUTPUT ;
    USE SIGNAL ;
    PORT
      LAYER M5 ;
        RECT  40.032 64.584 40.056 64.776 ;
    END
  END o[435]
  PIN o[436]
    DIRECTION OUTPUT ;
    USE SIGNAL ;
    PORT
      LAYER M5 ;
        RECT  40.08 64.584 40.104 64.776 ;
    END
  END o[436]
  PIN o[437]
    DIRECTION OUTPUT ;
    USE SIGNAL ;
    PORT
      LAYER M5 ;
        RECT  40.128 64.584 40.152 64.776 ;
    END
  END o[437]
  PIN o[438]
    DIRECTION OUTPUT ;
    USE SIGNAL ;
    PORT
      LAYER M5 ;
        RECT  40.176 64.584 40.2 64.776 ;
    END
  END o[438]
  PIN o[439]
    DIRECTION OUTPUT ;
    USE SIGNAL ;
    PORT
      LAYER M5 ;
        RECT  40.224 64.584 40.248 64.776 ;
    END
  END o[439]
  PIN o[43]
    DIRECTION OUTPUT ;
    USE SIGNAL ;
    PORT
      LAYER M5 ;
        RECT  21.216 64.584 21.24 64.776 ;
    END
  END o[43]
  PIN o[440]
    DIRECTION OUTPUT ;
    USE SIGNAL ;
    PORT
      LAYER M5 ;
        RECT  40.272 64.584 40.296 64.776 ;
    END
  END o[440]
  PIN o[441]
    DIRECTION OUTPUT ;
    USE SIGNAL ;
    PORT
      LAYER M5 ;
        RECT  40.32 64.584 40.344 64.776 ;
    END
  END o[441]
  PIN o[442]
    DIRECTION OUTPUT ;
    USE SIGNAL ;
    PORT
      LAYER M5 ;
        RECT  40.368 64.584 40.392 64.776 ;
    END
  END o[442]
  PIN o[443]
    DIRECTION OUTPUT ;
    USE SIGNAL ;
    PORT
      LAYER M5 ;
        RECT  40.416 64.584 40.44 64.776 ;
    END
  END o[443]
  PIN o[444]
    DIRECTION OUTPUT ;
    USE SIGNAL ;
    PORT
      LAYER M5 ;
        RECT  40.464 64.584 40.488 64.776 ;
    END
  END o[444]
  PIN o[445]
    DIRECTION OUTPUT ;
    USE SIGNAL ;
    PORT
      LAYER M5 ;
        RECT  40.512 64.584 40.536 64.776 ;
    END
  END o[445]
  PIN o[446]
    DIRECTION OUTPUT ;
    USE SIGNAL ;
    PORT
      LAYER M5 ;
        RECT  40.56 64.584 40.584 64.776 ;
    END
  END o[446]
  PIN o[447]
    DIRECTION OUTPUT ;
    USE SIGNAL ;
    PORT
      LAYER M5 ;
        RECT  40.608 64.584 40.632 64.776 ;
    END
  END o[447]
  PIN o[448]
    DIRECTION OUTPUT ;
    USE SIGNAL ;
    PORT
      LAYER M5 ;
        RECT  40.656 64.584 40.68 64.776 ;
    END
  END o[448]
  PIN o[449]
    DIRECTION OUTPUT ;
    USE SIGNAL ;
    PORT
      LAYER M5 ;
        RECT  40.704 64.584 40.728 64.776 ;
    END
  END o[449]
  PIN o[44]
    DIRECTION OUTPUT ;
    USE SIGNAL ;
    PORT
      LAYER M5 ;
        RECT  21.264 64.584 21.288 64.776 ;
    END
  END o[44]
  PIN o[450]
    DIRECTION OUTPUT ;
    USE SIGNAL ;
    PORT
      LAYER M5 ;
        RECT  40.752 64.584 40.776 64.776 ;
    END
  END o[450]
  PIN o[451]
    DIRECTION OUTPUT ;
    USE SIGNAL ;
    PORT
      LAYER M5 ;
        RECT  40.8 64.584 40.824 64.776 ;
    END
  END o[451]
  PIN o[452]
    DIRECTION OUTPUT ;
    USE SIGNAL ;
    PORT
      LAYER M5 ;
        RECT  40.848 64.584 40.872 64.776 ;
    END
  END o[452]
  PIN o[453]
    DIRECTION OUTPUT ;
    USE SIGNAL ;
    PORT
      LAYER M5 ;
        RECT  40.896 64.584 40.92 64.776 ;
    END
  END o[453]
  PIN o[454]
    DIRECTION OUTPUT ;
    USE SIGNAL ;
    PORT
      LAYER M5 ;
        RECT  40.944 64.584 40.968 64.776 ;
    END
  END o[454]
  PIN o[455]
    DIRECTION OUTPUT ;
    USE SIGNAL ;
    PORT
      LAYER M5 ;
        RECT  40.992 64.584 41.016 64.776 ;
    END
  END o[455]
  PIN o[456]
    DIRECTION OUTPUT ;
    USE SIGNAL ;
    PORT
      LAYER M5 ;
        RECT  41.04 64.584 41.064 64.776 ;
    END
  END o[456]
  PIN o[457]
    DIRECTION OUTPUT ;
    USE SIGNAL ;
    PORT
      LAYER M5 ;
        RECT  41.088 64.584 41.112 64.776 ;
    END
  END o[457]
  PIN o[458]
    DIRECTION OUTPUT ;
    USE SIGNAL ;
    PORT
      LAYER M5 ;
        RECT  41.136 64.584 41.16 64.776 ;
    END
  END o[458]
  PIN o[459]
    DIRECTION OUTPUT ;
    USE SIGNAL ;
    PORT
      LAYER M5 ;
        RECT  41.184 64.584 41.208 64.776 ;
    END
  END o[459]
  PIN o[45]
    DIRECTION OUTPUT ;
    USE SIGNAL ;
    PORT
      LAYER M5 ;
        RECT  21.312 64.584 21.336 64.776 ;
    END
  END o[45]
  PIN o[460]
    DIRECTION OUTPUT ;
    USE SIGNAL ;
    PORT
      LAYER M5 ;
        RECT  41.232 64.584 41.256 64.776 ;
    END
  END o[460]
  PIN o[461]
    DIRECTION OUTPUT ;
    USE SIGNAL ;
    PORT
      LAYER M5 ;
        RECT  41.28 64.584 41.304 64.776 ;
    END
  END o[461]
  PIN o[462]
    DIRECTION OUTPUT ;
    USE SIGNAL ;
    PORT
      LAYER M5 ;
        RECT  41.328 64.584 41.352 64.776 ;
    END
  END o[462]
  PIN o[463]
    DIRECTION OUTPUT ;
    USE SIGNAL ;
    PORT
      LAYER M5 ;
        RECT  41.376 64.584 41.4 64.776 ;
    END
  END o[463]
  PIN o[464]
    DIRECTION OUTPUT ;
    USE SIGNAL ;
    PORT
      LAYER M5 ;
        RECT  41.424 64.584 41.448 64.776 ;
    END
  END o[464]
  PIN o[465]
    DIRECTION OUTPUT ;
    USE SIGNAL ;
    PORT
      LAYER M5 ;
        RECT  41.472 64.584 41.496 64.776 ;
    END
  END o[465]
  PIN o[466]
    DIRECTION OUTPUT ;
    USE SIGNAL ;
    PORT
      LAYER M5 ;
        RECT  41.52 64.584 41.544 64.776 ;
    END
  END o[466]
  PIN o[467]
    DIRECTION OUTPUT ;
    USE SIGNAL ;
    PORT
      LAYER M5 ;
        RECT  41.568 64.584 41.592 64.776 ;
    END
  END o[467]
  PIN o[468]
    DIRECTION OUTPUT ;
    USE SIGNAL ;
    PORT
      LAYER M5 ;
        RECT  41.616 64.584 41.64 64.776 ;
    END
  END o[468]
  PIN o[469]
    DIRECTION OUTPUT ;
    USE SIGNAL ;
    PORT
      LAYER M5 ;
        RECT  41.664 64.584 41.688 64.776 ;
    END
  END o[469]
  PIN o[46]
    DIRECTION OUTPUT ;
    USE SIGNAL ;
    PORT
      LAYER M5 ;
        RECT  21.36 64.584 21.384 64.776 ;
    END
  END o[46]
  PIN o[470]
    DIRECTION OUTPUT ;
    USE SIGNAL ;
    PORT
      LAYER M5 ;
        RECT  41.712 64.584 41.736 64.776 ;
    END
  END o[470]
  PIN o[471]
    DIRECTION OUTPUT ;
    USE SIGNAL ;
    PORT
      LAYER M5 ;
        RECT  41.76 64.584 41.784 64.776 ;
    END
  END o[471]
  PIN o[472]
    DIRECTION OUTPUT ;
    USE SIGNAL ;
    PORT
      LAYER M5 ;
        RECT  41.808 64.584 41.832 64.776 ;
    END
  END o[472]
  PIN o[473]
    DIRECTION OUTPUT ;
    USE SIGNAL ;
    PORT
      LAYER M5 ;
        RECT  41.856 64.584 41.88 64.776 ;
    END
  END o[473]
  PIN o[474]
    DIRECTION OUTPUT ;
    USE SIGNAL ;
    PORT
      LAYER M5 ;
        RECT  41.904 64.584 41.928 64.776 ;
    END
  END o[474]
  PIN o[475]
    DIRECTION OUTPUT ;
    USE SIGNAL ;
    PORT
      LAYER M5 ;
        RECT  41.952 64.584 41.976 64.776 ;
    END
  END o[475]
  PIN o[476]
    DIRECTION OUTPUT ;
    USE SIGNAL ;
    PORT
      LAYER M5 ;
        RECT  42 64.584 42.024 64.776 ;
    END
  END o[476]
  PIN o[477]
    DIRECTION OUTPUT ;
    USE SIGNAL ;
    PORT
      LAYER M5 ;
        RECT  42.048 64.584 42.072 64.776 ;
    END
  END o[477]
  PIN o[478]
    DIRECTION OUTPUT ;
    USE SIGNAL ;
    PORT
      LAYER M5 ;
        RECT  42.096 64.584 42.12 64.776 ;
    END
  END o[478]
  PIN o[479]
    DIRECTION OUTPUT ;
    USE SIGNAL ;
    PORT
      LAYER M5 ;
        RECT  42.144 64.584 42.168 64.776 ;
    END
  END o[479]
  PIN o[47]
    DIRECTION OUTPUT ;
    USE SIGNAL ;
    PORT
      LAYER M5 ;
        RECT  21.408 64.584 21.432 64.776 ;
    END
  END o[47]
  PIN o[480]
    DIRECTION OUTPUT ;
    USE SIGNAL ;
    PORT
      LAYER M5 ;
        RECT  42.192 64.584 42.216 64.776 ;
    END
  END o[480]
  PIN o[481]
    DIRECTION OUTPUT ;
    USE SIGNAL ;
    PORT
      LAYER M5 ;
        RECT  42.24 64.584 42.264 64.776 ;
    END
  END o[481]
  PIN o[482]
    DIRECTION OUTPUT ;
    USE SIGNAL ;
    PORT
      LAYER M5 ;
        RECT  42.288 64.584 42.312 64.776 ;
    END
  END o[482]
  PIN o[483]
    DIRECTION OUTPUT ;
    USE SIGNAL ;
    PORT
      LAYER M5 ;
        RECT  42.336 64.584 42.36 64.776 ;
    END
  END o[483]
  PIN o[484]
    DIRECTION OUTPUT ;
    USE SIGNAL ;
    PORT
      LAYER M5 ;
        RECT  42.384 64.584 42.408 64.776 ;
    END
  END o[484]
  PIN o[485]
    DIRECTION OUTPUT ;
    USE SIGNAL ;
    PORT
      LAYER M5 ;
        RECT  42.432 64.584 42.456 64.776 ;
    END
  END o[485]
  PIN o[486]
    DIRECTION OUTPUT ;
    USE SIGNAL ;
    PORT
      LAYER M5 ;
        RECT  42.48 64.584 42.504 64.776 ;
    END
  END o[486]
  PIN o[487]
    DIRECTION OUTPUT ;
    USE SIGNAL ;
    PORT
      LAYER M5 ;
        RECT  42.528 64.584 42.552 64.776 ;
    END
  END o[487]
  PIN o[488]
    DIRECTION OUTPUT ;
    USE SIGNAL ;
    PORT
      LAYER M5 ;
        RECT  42.576 64.584 42.6 64.776 ;
    END
  END o[488]
  PIN o[489]
    DIRECTION OUTPUT ;
    USE SIGNAL ;
    PORT
      LAYER M5 ;
        RECT  42.624 64.584 42.648 64.776 ;
    END
  END o[489]
  PIN o[48]
    DIRECTION OUTPUT ;
    USE SIGNAL ;
    PORT
      LAYER M5 ;
        RECT  21.456 64.584 21.48 64.776 ;
    END
  END o[48]
  PIN o[490]
    DIRECTION OUTPUT ;
    USE SIGNAL ;
    PORT
      LAYER M5 ;
        RECT  42.672 64.584 42.696 64.776 ;
    END
  END o[490]
  PIN o[491]
    DIRECTION OUTPUT ;
    USE SIGNAL ;
    PORT
      LAYER M5 ;
        RECT  42.72 64.584 42.744 64.776 ;
    END
  END o[491]
  PIN o[492]
    DIRECTION OUTPUT ;
    USE SIGNAL ;
    PORT
      LAYER M5 ;
        RECT  42.768 64.584 42.792 64.776 ;
    END
  END o[492]
  PIN o[493]
    DIRECTION OUTPUT ;
    USE SIGNAL ;
    PORT
      LAYER M5 ;
        RECT  42.816 64.584 42.84 64.776 ;
    END
  END o[493]
  PIN o[494]
    DIRECTION OUTPUT ;
    USE SIGNAL ;
    PORT
      LAYER M5 ;
        RECT  42.864 64.584 42.888 64.776 ;
    END
  END o[494]
  PIN o[495]
    DIRECTION OUTPUT ;
    USE SIGNAL ;
    PORT
      LAYER M5 ;
        RECT  42.912 64.584 42.936 64.776 ;
    END
  END o[495]
  PIN o[496]
    DIRECTION OUTPUT ;
    USE SIGNAL ;
    PORT
      LAYER M5 ;
        RECT  42.96 64.584 42.984 64.776 ;
    END
  END o[496]
  PIN o[497]
    DIRECTION OUTPUT ;
    USE SIGNAL ;
    PORT
      LAYER M5 ;
        RECT  43.008 64.584 43.032 64.776 ;
    END
  END o[497]
  PIN o[498]
    DIRECTION OUTPUT ;
    USE SIGNAL ;
    PORT
      LAYER M5 ;
        RECT  43.056 64.584 43.08 64.776 ;
    END
  END o[498]
  PIN o[499]
    DIRECTION OUTPUT ;
    USE SIGNAL ;
    PORT
      LAYER M5 ;
        RECT  43.104 64.584 43.128 64.776 ;
    END
  END o[499]
  PIN o[49]
    DIRECTION OUTPUT ;
    USE SIGNAL ;
    PORT
      LAYER M5 ;
        RECT  21.504 64.584 21.528 64.776 ;
    END
  END o[49]
  PIN o[4]
    DIRECTION OUTPUT ;
    USE SIGNAL ;
    PORT
      LAYER M5 ;
        RECT  19.344 64.584 19.368 64.776 ;
    END
  END o[4]
  PIN o[500]
    DIRECTION OUTPUT ;
    USE SIGNAL ;
    PORT
      LAYER M5 ;
        RECT  43.152 64.584 43.176 64.776 ;
    END
  END o[500]
  PIN o[501]
    DIRECTION OUTPUT ;
    USE SIGNAL ;
    PORT
      LAYER M5 ;
        RECT  43.2 64.584 43.224 64.776 ;
    END
  END o[501]
  PIN o[502]
    DIRECTION OUTPUT ;
    USE SIGNAL ;
    PORT
      LAYER M5 ;
        RECT  43.248 64.584 43.272 64.776 ;
    END
  END o[502]
  PIN o[503]
    DIRECTION OUTPUT ;
    USE SIGNAL ;
    PORT
      LAYER M5 ;
        RECT  43.296 64.584 43.32 64.776 ;
    END
  END o[503]
  PIN o[504]
    DIRECTION OUTPUT ;
    USE SIGNAL ;
    PORT
      LAYER M5 ;
        RECT  43.344 64.584 43.368 64.776 ;
    END
  END o[504]
  PIN o[505]
    DIRECTION OUTPUT ;
    USE SIGNAL ;
    PORT
      LAYER M5 ;
        RECT  43.392 64.584 43.416 64.776 ;
    END
  END o[505]
  PIN o[506]
    DIRECTION OUTPUT ;
    USE SIGNAL ;
    PORT
      LAYER M5 ;
        RECT  43.44 64.584 43.464 64.776 ;
    END
  END o[506]
  PIN o[507]
    DIRECTION OUTPUT ;
    USE SIGNAL ;
    PORT
      LAYER M5 ;
        RECT  43.488 64.584 43.512 64.776 ;
    END
  END o[507]
  PIN o[508]
    DIRECTION OUTPUT ;
    USE SIGNAL ;
    PORT
      LAYER M5 ;
        RECT  43.536 64.584 43.56 64.776 ;
    END
  END o[508]
  PIN o[509]
    DIRECTION OUTPUT ;
    USE SIGNAL ;
    PORT
      LAYER M5 ;
        RECT  43.584 64.584 43.608 64.776 ;
    END
  END o[509]
  PIN o[50]
    DIRECTION OUTPUT ;
    USE SIGNAL ;
    PORT
      LAYER M5 ;
        RECT  21.552 64.584 21.576 64.776 ;
    END
  END o[50]
  PIN o[510]
    DIRECTION OUTPUT ;
    USE SIGNAL ;
    PORT
      LAYER M5 ;
        RECT  43.632 64.584 43.656 64.776 ;
    END
  END o[510]
  PIN o[511]
    DIRECTION OUTPUT ;
    USE SIGNAL ;
    PORT
      LAYER M5 ;
        RECT  43.68 64.584 43.704 64.776 ;
    END
  END o[511]
  PIN o[512]
    DIRECTION OUTPUT ;
    USE SIGNAL ;
    PORT
      LAYER M5 ;
        RECT  43.728 64.584 43.752 64.776 ;
    END
  END o[512]
  PIN o[513]
    DIRECTION OUTPUT ;
    USE SIGNAL ;
    PORT
      LAYER M5 ;
        RECT  43.776 64.584 43.8 64.776 ;
    END
  END o[513]
  PIN o[514]
    DIRECTION OUTPUT ;
    USE SIGNAL ;
    PORT
      LAYER M5 ;
        RECT  43.824 64.584 43.848 64.776 ;
    END
  END o[514]
  PIN o[51]
    DIRECTION OUTPUT ;
    USE SIGNAL ;
    PORT
      LAYER M5 ;
        RECT  21.6 64.584 21.624 64.776 ;
    END
  END o[51]
  PIN o[52]
    DIRECTION OUTPUT ;
    USE SIGNAL ;
    PORT
      LAYER M5 ;
        RECT  21.648 64.584 21.672 64.776 ;
    END
  END o[52]
  PIN o[53]
    DIRECTION OUTPUT ;
    USE SIGNAL ;
    PORT
      LAYER M5 ;
        RECT  21.696 64.584 21.72 64.776 ;
    END
  END o[53]
  PIN o[54]
    DIRECTION OUTPUT ;
    USE SIGNAL ;
    PORT
      LAYER M5 ;
        RECT  21.744 64.584 21.768 64.776 ;
    END
  END o[54]
  PIN o[55]
    DIRECTION OUTPUT ;
    USE SIGNAL ;
    PORT
      LAYER M5 ;
        RECT  21.792 64.584 21.816 64.776 ;
    END
  END o[55]
  PIN o[56]
    DIRECTION OUTPUT ;
    USE SIGNAL ;
    PORT
      LAYER M5 ;
        RECT  21.84 64.584 21.864 64.776 ;
    END
  END o[56]
  PIN o[57]
    DIRECTION OUTPUT ;
    USE SIGNAL ;
    PORT
      LAYER M5 ;
        RECT  21.888 64.584 21.912 64.776 ;
    END
  END o[57]
  PIN o[58]
    DIRECTION OUTPUT ;
    USE SIGNAL ;
    PORT
      LAYER M5 ;
        RECT  21.936 64.584 21.96 64.776 ;
    END
  END o[58]
  PIN o[59]
    DIRECTION OUTPUT ;
    USE SIGNAL ;
    PORT
      LAYER M5 ;
        RECT  21.984 64.584 22.008 64.776 ;
    END
  END o[59]
  PIN o[5]
    DIRECTION OUTPUT ;
    USE SIGNAL ;
    PORT
      LAYER M5 ;
        RECT  19.392 64.584 19.416 64.776 ;
    END
  END o[5]
  PIN o[60]
    DIRECTION OUTPUT ;
    USE SIGNAL ;
    PORT
      LAYER M5 ;
        RECT  22.032 64.584 22.056 64.776 ;
    END
  END o[60]
  PIN o[61]
    DIRECTION OUTPUT ;
    USE SIGNAL ;
    PORT
      LAYER M5 ;
        RECT  22.08 64.584 22.104 64.776 ;
    END
  END o[61]
  PIN o[62]
    DIRECTION OUTPUT ;
    USE SIGNAL ;
    PORT
      LAYER M5 ;
        RECT  22.128 64.584 22.152 64.776 ;
    END
  END o[62]
  PIN o[63]
    DIRECTION OUTPUT ;
    USE SIGNAL ;
    PORT
      LAYER M5 ;
        RECT  22.176 64.584 22.2 64.776 ;
    END
  END o[63]
  PIN o[64]
    DIRECTION OUTPUT ;
    USE SIGNAL ;
    PORT
      LAYER M5 ;
        RECT  22.224 64.584 22.248 64.776 ;
    END
  END o[64]
  PIN o[65]
    DIRECTION OUTPUT ;
    USE SIGNAL ;
    PORT
      LAYER M5 ;
        RECT  22.272 64.584 22.296 64.776 ;
    END
  END o[65]
  PIN o[66]
    DIRECTION OUTPUT ;
    USE SIGNAL ;
    PORT
      LAYER M5 ;
        RECT  22.32 64.584 22.344 64.776 ;
    END
  END o[66]
  PIN o[67]
    DIRECTION OUTPUT ;
    USE SIGNAL ;
    PORT
      LAYER M5 ;
        RECT  22.368 64.584 22.392 64.776 ;
    END
  END o[67]
  PIN o[68]
    DIRECTION OUTPUT ;
    USE SIGNAL ;
    PORT
      LAYER M5 ;
        RECT  22.416 64.584 22.44 64.776 ;
    END
  END o[68]
  PIN o[69]
    DIRECTION OUTPUT ;
    USE SIGNAL ;
    PORT
      LAYER M5 ;
        RECT  22.464 64.584 22.488 64.776 ;
    END
  END o[69]
  PIN o[6]
    DIRECTION OUTPUT ;
    USE SIGNAL ;
    PORT
      LAYER M5 ;
        RECT  19.44 64.584 19.464 64.776 ;
    END
  END o[6]
  PIN o[70]
    DIRECTION OUTPUT ;
    USE SIGNAL ;
    PORT
      LAYER M5 ;
        RECT  22.512 64.584 22.536 64.776 ;
    END
  END o[70]
  PIN o[71]
    DIRECTION OUTPUT ;
    USE SIGNAL ;
    PORT
      LAYER M5 ;
        RECT  22.56 64.584 22.584 64.776 ;
    END
  END o[71]
  PIN o[72]
    DIRECTION OUTPUT ;
    USE SIGNAL ;
    PORT
      LAYER M5 ;
        RECT  22.608 64.584 22.632 64.776 ;
    END
  END o[72]
  PIN o[73]
    DIRECTION OUTPUT ;
    USE SIGNAL ;
    PORT
      LAYER M5 ;
        RECT  22.656 64.584 22.68 64.776 ;
    END
  END o[73]
  PIN o[74]
    DIRECTION OUTPUT ;
    USE SIGNAL ;
    PORT
      LAYER M5 ;
        RECT  22.704 64.584 22.728 64.776 ;
    END
  END o[74]
  PIN o[75]
    DIRECTION OUTPUT ;
    USE SIGNAL ;
    PORT
      LAYER M5 ;
        RECT  22.752 64.584 22.776 64.776 ;
    END
  END o[75]
  PIN o[76]
    DIRECTION OUTPUT ;
    USE SIGNAL ;
    PORT
      LAYER M5 ;
        RECT  22.8 64.584 22.824 64.776 ;
    END
  END o[76]
  PIN o[77]
    DIRECTION OUTPUT ;
    USE SIGNAL ;
    PORT
      LAYER M5 ;
        RECT  22.848 64.584 22.872 64.776 ;
    END
  END o[77]
  PIN o[78]
    DIRECTION OUTPUT ;
    USE SIGNAL ;
    PORT
      LAYER M5 ;
        RECT  22.896 64.584 22.92 64.776 ;
    END
  END o[78]
  PIN o[79]
    DIRECTION OUTPUT ;
    USE SIGNAL ;
    PORT
      LAYER M5 ;
        RECT  22.944 64.584 22.968 64.776 ;
    END
  END o[79]
  PIN o[7]
    DIRECTION OUTPUT ;
    USE SIGNAL ;
    PORT
      LAYER M5 ;
        RECT  19.488 64.584 19.512 64.776 ;
    END
  END o[7]
  PIN o[80]
    DIRECTION OUTPUT ;
    USE SIGNAL ;
    PORT
      LAYER M5 ;
        RECT  22.992 64.584 23.016 64.776 ;
    END
  END o[80]
  PIN o[81]
    DIRECTION OUTPUT ;
    USE SIGNAL ;
    PORT
      LAYER M5 ;
        RECT  23.04 64.584 23.064 64.776 ;
    END
  END o[81]
  PIN o[82]
    DIRECTION OUTPUT ;
    USE SIGNAL ;
    PORT
      LAYER M5 ;
        RECT  23.088 64.584 23.112 64.776 ;
    END
  END o[82]
  PIN o[83]
    DIRECTION OUTPUT ;
    USE SIGNAL ;
    PORT
      LAYER M5 ;
        RECT  23.136 64.584 23.16 64.776 ;
    END
  END o[83]
  PIN o[84]
    DIRECTION OUTPUT ;
    USE SIGNAL ;
    PORT
      LAYER M5 ;
        RECT  23.184 64.584 23.208 64.776 ;
    END
  END o[84]
  PIN o[85]
    DIRECTION OUTPUT ;
    USE SIGNAL ;
    PORT
      LAYER M5 ;
        RECT  23.232 64.584 23.256 64.776 ;
    END
  END o[85]
  PIN o[86]
    DIRECTION OUTPUT ;
    USE SIGNAL ;
    PORT
      LAYER M5 ;
        RECT  23.28 64.584 23.304 64.776 ;
    END
  END o[86]
  PIN o[87]
    DIRECTION OUTPUT ;
    USE SIGNAL ;
    PORT
      LAYER M5 ;
        RECT  23.328 64.584 23.352 64.776 ;
    END
  END o[87]
  PIN o[88]
    DIRECTION OUTPUT ;
    USE SIGNAL ;
    PORT
      LAYER M5 ;
        RECT  23.376 64.584 23.4 64.776 ;
    END
  END o[88]
  PIN o[89]
    DIRECTION OUTPUT ;
    USE SIGNAL ;
    PORT
      LAYER M5 ;
        RECT  23.424 64.584 23.448 64.776 ;
    END
  END o[89]
  PIN o[8]
    DIRECTION OUTPUT ;
    USE SIGNAL ;
    PORT
      LAYER M5 ;
        RECT  19.536 64.584 19.56 64.776 ;
    END
  END o[8]
  PIN o[90]
    DIRECTION OUTPUT ;
    USE SIGNAL ;
    PORT
      LAYER M5 ;
        RECT  23.472 64.584 23.496 64.776 ;
    END
  END o[90]
  PIN o[91]
    DIRECTION OUTPUT ;
    USE SIGNAL ;
    PORT
      LAYER M5 ;
        RECT  23.52 64.584 23.544 64.776 ;
    END
  END o[91]
  PIN o[92]
    DIRECTION OUTPUT ;
    USE SIGNAL ;
    PORT
      LAYER M5 ;
        RECT  23.568 64.584 23.592 64.776 ;
    END
  END o[92]
  PIN o[93]
    DIRECTION OUTPUT ;
    USE SIGNAL ;
    PORT
      LAYER M5 ;
        RECT  23.616 64.584 23.64 64.776 ;
    END
  END o[93]
  PIN o[94]
    DIRECTION OUTPUT ;
    USE SIGNAL ;
    PORT
      LAYER M5 ;
        RECT  23.664 64.584 23.688 64.776 ;
    END
  END o[94]
  PIN o[95]
    DIRECTION OUTPUT ;
    USE SIGNAL ;
    PORT
      LAYER M5 ;
        RECT  23.712 64.584 23.736 64.776 ;
    END
  END o[95]
  PIN o[96]
    DIRECTION OUTPUT ;
    USE SIGNAL ;
    PORT
      LAYER M5 ;
        RECT  23.76 64.584 23.784 64.776 ;
    END
  END o[96]
  PIN o[97]
    DIRECTION OUTPUT ;
    USE SIGNAL ;
    PORT
      LAYER M5 ;
        RECT  23.808 64.584 23.832 64.776 ;
    END
  END o[97]
  PIN o[98]
    DIRECTION OUTPUT ;
    USE SIGNAL ;
    PORT
      LAYER M5 ;
        RECT  23.856 64.584 23.88 64.776 ;
    END
  END o[98]
  PIN o[99]
    DIRECTION OUTPUT ;
    USE SIGNAL ;
    PORT
      LAYER M5 ;
        RECT  23.904 64.584 23.928 64.776 ;
    END
  END o[99]
  PIN o[9]
    DIRECTION OUTPUT ;
    USE SIGNAL ;
    PORT
      LAYER M5 ;
        RECT  19.584 64.584 19.608 64.776 ;
    END
  END o[9]
  PIN rs[0]
    DIRECTION INPUT ;
    USE SIGNAL ;
    PORT
      LAYER M5 ;
        RECT  31.584 0 31.608 0.192 ;
    END
  END rs[0]
  PIN VDD
    DIRECTION INOUT ;
    USE POWER ;
    PORT
      LAYER M7 ;
        RECT  60.256 0.531 60.544 63.999 ;
        RECT  49.456 0.531 49.744 63.999 ;
        RECT  38.656 0.531 38.944 63.999 ;
        RECT  27.856 0.531 28.144 63.999 ;
        RECT  17.056 0.531 17.344 63.999 ;
        RECT  6.256 0.531 6.544 63.999 ;
      LAYER M6 ;
        RECT  0 60.972 0.032 61.26 ;
        RECT  0 55.572 0.032 55.86 ;
        RECT  0 50.172 0.032 50.46 ;
        RECT  0 44.772 0.032 45.06 ;
        RECT  0 39.372 0.032 39.66 ;
        RECT  0 33.972 0.032 34.26 ;
        RECT  0 28.572 0.032 28.86 ;
        RECT  0 23.172 0.032 23.46 ;
        RECT  0 17.772 0.032 18.06 ;
        RECT  0 12.372 0.032 12.66 ;
        RECT  0 6.972 0.032 7.26 ;
        RECT  0 1.572 0.032 1.86 ;
      LAYER M2 ;
        RECT  0 63.981 0.018 63.999 ;
        RECT  0 63.441 0.018 63.459 ;
        RECT  0 62.901 0.018 62.919 ;
        RECT  0 62.361 0.018 62.379 ;
        RECT  0 61.821 0.018 61.839 ;
        RECT  0 61.281 0.018 61.299 ;
        RECT  0 60.741 0.018 60.759 ;
        RECT  0 60.201 0.018 60.219 ;
        RECT  0 59.661 0.018 59.679 ;
        RECT  0 59.121 0.018 59.139 ;
        RECT  0 58.581 0.018 58.599 ;
        RECT  0 58.041 0.018 58.059 ;
        RECT  0 57.501 0.018 57.519 ;
        RECT  0 56.961 0.018 56.979 ;
        RECT  0 56.421 0.018 56.439 ;
        RECT  0 55.881 0.018 55.899 ;
        RECT  0 55.341 0.018 55.359 ;
        RECT  0 54.801 0.018 54.819 ;
        RECT  0 54.261 0.018 54.279 ;
        RECT  0 53.721 0.018 53.739 ;
        RECT  0 53.181 0.018 53.199 ;
        RECT  0 52.641 0.018 52.659 ;
        RECT  0 52.101 0.018 52.119 ;
        RECT  0 51.561 0.018 51.579 ;
        RECT  0 51.021 0.018 51.039 ;
        RECT  0 50.481 0.018 50.499 ;
        RECT  0 49.941 0.018 49.959 ;
        RECT  0 49.401 0.018 49.419 ;
        RECT  0 48.861 0.018 48.879 ;
        RECT  0 48.321 0.018 48.339 ;
        RECT  0 47.781 0.018 47.799 ;
        RECT  0 47.241 0.018 47.259 ;
        RECT  0 46.701 0.018 46.719 ;
        RECT  0 46.161 0.018 46.179 ;
        RECT  0 45.621 0.018 45.639 ;
        RECT  0 45.081 0.018 45.099 ;
        RECT  0 44.541 0.018 44.559 ;
        RECT  0 44.001 0.018 44.019 ;
        RECT  0 43.461 0.018 43.479 ;
        RECT  0 42.921 0.018 42.939 ;
        RECT  0 42.381 0.018 42.399 ;
        RECT  0 41.841 0.018 41.859 ;
        RECT  0 41.301 0.018 41.319 ;
        RECT  0 40.761 0.018 40.779 ;
        RECT  0 40.221 0.018 40.239 ;
        RECT  0 39.681 0.018 39.699 ;
        RECT  0 39.141 0.018 39.159 ;
        RECT  0 38.601 0.018 38.619 ;
        RECT  0 38.061 0.018 38.079 ;
        RECT  0 37.521 0.018 37.539 ;
        RECT  0 36.981 0.018 36.999 ;
        RECT  0 36.441 0.018 36.459 ;
        RECT  0 35.901 0.018 35.919 ;
        RECT  0 35.361 0.018 35.379 ;
        RECT  0 34.821 0.018 34.839 ;
        RECT  0 34.281 0.018 34.299 ;
        RECT  0 33.741 0.018 33.759 ;
        RECT  0 33.201 0.018 33.219 ;
        RECT  0 32.661 0.018 32.679 ;
        RECT  0 32.121 0.018 32.139 ;
        RECT  0 31.581 0.018 31.599 ;
        RECT  0 31.041 0.018 31.059 ;
        RECT  0 30.501 0.018 30.519 ;
        RECT  0 29.961 0.018 29.979 ;
        RECT  0 29.421 0.018 29.439 ;
        RECT  0 28.881 0.018 28.899 ;
        RECT  0 28.341 0.018 28.359 ;
        RECT  0 27.801 0.018 27.819 ;
        RECT  0 27.261 0.018 27.279 ;
        RECT  0 26.721 0.018 26.739 ;
        RECT  0 26.181 0.018 26.199 ;
        RECT  0 25.641 0.018 25.659 ;
        RECT  0 25.101 0.018 25.119 ;
        RECT  0 24.561 0.018 24.579 ;
        RECT  0 24.021 0.018 24.039 ;
        RECT  0 23.481 0.018 23.499 ;
        RECT  0 22.941 0.018 22.959 ;
        RECT  0 22.401 0.018 22.419 ;
        RECT  0 21.861 0.018 21.879 ;
        RECT  0 21.321 0.018 21.339 ;
        RECT  0 20.781 0.018 20.799 ;
        RECT  0 20.241 0.018 20.259 ;
        RECT  0 19.701 0.018 19.719 ;
        RECT  0 19.161 0.018 19.179 ;
        RECT  0 18.621 0.018 18.639 ;
        RECT  0 18.081 0.018 18.099 ;
        RECT  0 17.541 0.018 17.559 ;
        RECT  0 17.001 0.018 17.019 ;
        RECT  0 16.461 0.018 16.479 ;
        RECT  0 15.921 0.018 15.939 ;
        RECT  0 15.381 0.018 15.399 ;
        RECT  0 14.841 0.018 14.859 ;
        RECT  0 14.301 0.018 14.319 ;
        RECT  0 13.761 0.018 13.779 ;
        RECT  0 13.221 0.018 13.239 ;
        RECT  0 12.681 0.018 12.699 ;
        RECT  0 12.141 0.018 12.159 ;
        RECT  0 11.601 0.018 11.619 ;
        RECT  0 11.061 0.018 11.079 ;
        RECT  0 10.521 0.018 10.539 ;
        RECT  0 9.981 0.018 9.999 ;
        RECT  0 9.441 0.018 9.459 ;
        RECT  0 8.901 0.018 8.919 ;
        RECT  0 8.361 0.018 8.379 ;
        RECT  0 7.821 0.018 7.839 ;
        RECT  0 7.281 0.018 7.299 ;
        RECT  0 6.741 0.018 6.759 ;
        RECT  0 6.201 0.018 6.219 ;
        RECT  0 5.661 0.018 5.679 ;
        RECT  0 5.121 0.018 5.139 ;
        RECT  0 4.581 0.018 4.599 ;
        RECT  0 4.041 0.018 4.059 ;
        RECT  0 3.501 0.018 3.519 ;
        RECT  0 2.961 0.018 2.979 ;
        RECT  0 2.421 0.018 2.439 ;
        RECT  0 1.881 0.018 1.899 ;
        RECT  0 1.341 0.018 1.359 ;
        RECT  0 0.801 0.018 0.819 ;
      LAYER M1 ;
        RECT  0 63.981 0.018 63.999 ;
        RECT  0 63.441 0.018 63.459 ;
        RECT  0 62.901 0.018 62.919 ;
        RECT  0 62.361 0.018 62.379 ;
        RECT  0 61.821 0.018 61.839 ;
        RECT  0 61.281 0.018 61.299 ;
        RECT  0 60.741 0.018 60.759 ;
        RECT  0 60.201 0.018 60.219 ;
        RECT  0 59.661 0.018 59.679 ;
        RECT  0 59.121 0.018 59.139 ;
        RECT  0 58.581 0.018 58.599 ;
        RECT  0 58.041 0.018 58.059 ;
        RECT  0 57.501 0.018 57.519 ;
        RECT  0 56.961 0.018 56.979 ;
        RECT  0 56.421 0.018 56.439 ;
        RECT  0 55.881 0.018 55.899 ;
        RECT  0 55.341 0.018 55.359 ;
        RECT  0 54.801 0.018 54.819 ;
        RECT  0 54.261 0.018 54.279 ;
        RECT  0 53.721 0.018 53.739 ;
        RECT  0 53.181 0.018 53.199 ;
        RECT  0 52.641 0.018 52.659 ;
        RECT  0 52.101 0.018 52.119 ;
        RECT  0 51.561 0.018 51.579 ;
        RECT  0 51.021 0.018 51.039 ;
        RECT  0 50.481 0.018 50.499 ;
        RECT  0 49.941 0.018 49.959 ;
        RECT  0 49.401 0.018 49.419 ;
        RECT  0 48.861 0.018 48.879 ;
        RECT  0 48.321 0.018 48.339 ;
        RECT  0 47.781 0.018 47.799 ;
        RECT  0 47.241 0.018 47.259 ;
        RECT  0 46.701 0.018 46.719 ;
        RECT  0 46.161 0.018 46.179 ;
        RECT  0 45.621 0.018 45.639 ;
        RECT  0 45.081 0.018 45.099 ;
        RECT  0 44.541 0.018 44.559 ;
        RECT  0 44.001 0.018 44.019 ;
        RECT  0 43.461 0.018 43.479 ;
        RECT  0 42.921 0.018 42.939 ;
        RECT  0 42.381 0.018 42.399 ;
        RECT  0 41.841 0.018 41.859 ;
        RECT  0 41.301 0.018 41.319 ;
        RECT  0 40.761 0.018 40.779 ;
        RECT  0 40.221 0.018 40.239 ;
        RECT  0 39.681 0.018 39.699 ;
        RECT  0 39.141 0.018 39.159 ;
        RECT  0 38.601 0.018 38.619 ;
        RECT  0 38.061 0.018 38.079 ;
        RECT  0 37.521 0.018 37.539 ;
        RECT  0 36.981 0.018 36.999 ;
        RECT  0 36.441 0.018 36.459 ;
        RECT  0 35.901 0.018 35.919 ;
        RECT  0 35.361 0.018 35.379 ;
        RECT  0 34.821 0.018 34.839 ;
        RECT  0 34.281 0.018 34.299 ;
        RECT  0 33.741 0.018 33.759 ;
        RECT  0 33.201 0.018 33.219 ;
        RECT  0 32.661 0.018 32.679 ;
        RECT  0 32.121 0.018 32.139 ;
        RECT  0 31.581 0.018 31.599 ;
        RECT  0 31.041 0.018 31.059 ;
        RECT  0 30.501 0.018 30.519 ;
        RECT  0 29.961 0.018 29.979 ;
        RECT  0 29.421 0.018 29.439 ;
        RECT  0 28.881 0.018 28.899 ;
        RECT  0 28.341 0.018 28.359 ;
        RECT  0 27.801 0.018 27.819 ;
        RECT  0 27.261 0.018 27.279 ;
        RECT  0 26.721 0.018 26.739 ;
        RECT  0 26.181 0.018 26.199 ;
        RECT  0 25.641 0.018 25.659 ;
        RECT  0 25.101 0.018 25.119 ;
        RECT  0 24.561 0.018 24.579 ;
        RECT  0 24.021 0.018 24.039 ;
        RECT  0 23.481 0.018 23.499 ;
        RECT  0 22.941 0.018 22.959 ;
        RECT  0 22.401 0.018 22.419 ;
        RECT  0 21.861 0.018 21.879 ;
        RECT  0 21.321 0.018 21.339 ;
        RECT  0 20.781 0.018 20.799 ;
        RECT  0 20.241 0.018 20.259 ;
        RECT  0 19.701 0.018 19.719 ;
        RECT  0 19.161 0.018 19.179 ;
        RECT  0 18.621 0.018 18.639 ;
        RECT  0 18.081 0.018 18.099 ;
        RECT  0 17.541 0.018 17.559 ;
        RECT  0 17.001 0.018 17.019 ;
        RECT  0 16.461 0.018 16.479 ;
        RECT  0 15.921 0.018 15.939 ;
        RECT  0 15.381 0.018 15.399 ;
        RECT  0 14.841 0.018 14.859 ;
        RECT  0 14.301 0.018 14.319 ;
        RECT  0 13.761 0.018 13.779 ;
        RECT  0 13.221 0.018 13.239 ;
        RECT  0 12.681 0.018 12.699 ;
        RECT  0 12.141 0.018 12.159 ;
        RECT  0 11.601 0.018 11.619 ;
        RECT  0 11.061 0.018 11.079 ;
        RECT  0 10.521 0.018 10.539 ;
        RECT  0 9.981 0.018 9.999 ;
        RECT  0 9.441 0.018 9.459 ;
        RECT  0 8.901 0.018 8.919 ;
        RECT  0 8.361 0.018 8.379 ;
        RECT  0 7.821 0.018 7.839 ;
        RECT  0 7.281 0.018 7.299 ;
        RECT  0 6.741 0.018 6.759 ;
        RECT  0 6.201 0.018 6.219 ;
        RECT  0 5.661 0.018 5.679 ;
        RECT  0 5.121 0.018 5.139 ;
        RECT  0 4.581 0.018 4.599 ;
        RECT  0 4.041 0.018 4.059 ;
        RECT  0 3.501 0.018 3.519 ;
        RECT  0 2.961 0.018 2.979 ;
        RECT  0 2.421 0.018 2.439 ;
        RECT  0 1.881 0.018 1.899 ;
        RECT  0 1.341 0.018 1.359 ;
        RECT  0 0.801 0.018 0.819 ;
    END
  END VDD
  PIN VSS
    DIRECTION INOUT ;
    USE GROUND ;
    PORT
      LAYER M7 ;
        RECT  54.856 0.531 55.144 63.999 ;
        RECT  44.056 0.531 44.344 63.999 ;
        RECT  33.256 0.531 33.544 63.999 ;
        RECT  22.456 0.531 22.744 63.999 ;
        RECT  11.656 0.531 11.944 63.999 ;
        RECT  0.856 0.531 1.144 63.999 ;
      LAYER M6 ;
        RECT  0 60.396 0.032 60.684 ;
        RECT  0 54.996 0.032 55.284 ;
        RECT  0 49.596 0.032 49.884 ;
        RECT  0 44.196 0.032 44.484 ;
        RECT  0 38.796 0.032 39.084 ;
        RECT  0 33.396 0.032 33.684 ;
        RECT  0 27.996 0.032 28.284 ;
        RECT  0 22.596 0.032 22.884 ;
        RECT  0 17.196 0.032 17.484 ;
        RECT  0 11.796 0.032 12.084 ;
        RECT  0 6.396 0.032 6.684 ;
        RECT  0 0.996 0.032 1.284 ;
      LAYER M2 ;
        RECT  0 63.711 0.018 63.729 ;
        RECT  0 63.171 0.018 63.189 ;
        RECT  0 62.631 0.018 62.649 ;
        RECT  0 62.091 0.018 62.109 ;
        RECT  0 61.551 0.018 61.569 ;
        RECT  0 61.011 0.018 61.029 ;
        RECT  0 60.471 0.018 60.489 ;
        RECT  0 59.931 0.018 59.949 ;
        RECT  0 59.391 0.018 59.409 ;
        RECT  0 58.851 0.018 58.869 ;
        RECT  0 58.311 0.018 58.329 ;
        RECT  0 57.771 0.018 57.789 ;
        RECT  0 57.231 0.018 57.249 ;
        RECT  0 56.691 0.018 56.709 ;
        RECT  0 56.151 0.018 56.169 ;
        RECT  0 55.611 0.018 55.629 ;
        RECT  0 55.071 0.018 55.089 ;
        RECT  0 54.531 0.018 54.549 ;
        RECT  0 53.991 0.018 54.009 ;
        RECT  0 53.451 0.018 53.469 ;
        RECT  0 52.911 0.018 52.929 ;
        RECT  0 52.371 0.018 52.389 ;
        RECT  0 51.831 0.018 51.849 ;
        RECT  0 51.291 0.018 51.309 ;
        RECT  0 50.751 0.018 50.769 ;
        RECT  0 50.211 0.018 50.229 ;
        RECT  0 49.671 0.018 49.689 ;
        RECT  0 49.131 0.018 49.149 ;
        RECT  0 48.591 0.018 48.609 ;
        RECT  0 48.051 0.018 48.069 ;
        RECT  0 47.511 0.018 47.529 ;
        RECT  0 46.971 0.018 46.989 ;
        RECT  0 46.431 0.018 46.449 ;
        RECT  0 45.891 0.018 45.909 ;
        RECT  0 45.351 0.018 45.369 ;
        RECT  0 44.811 0.018 44.829 ;
        RECT  0 44.271 0.018 44.289 ;
        RECT  0 43.731 0.018 43.749 ;
        RECT  0 43.191 0.018 43.209 ;
        RECT  0 42.651 0.018 42.669 ;
        RECT  0 42.111 0.018 42.129 ;
        RECT  0 41.571 0.018 41.589 ;
        RECT  0 41.031 0.018 41.049 ;
        RECT  0 40.491 0.018 40.509 ;
        RECT  0 39.951 0.018 39.969 ;
        RECT  0 39.411 0.018 39.429 ;
        RECT  0 38.871 0.018 38.889 ;
        RECT  0 38.331 0.018 38.349 ;
        RECT  0 37.791 0.018 37.809 ;
        RECT  0 37.251 0.018 37.269 ;
        RECT  0 36.711 0.018 36.729 ;
        RECT  0 36.171 0.018 36.189 ;
        RECT  0 35.631 0.018 35.649 ;
        RECT  0 35.091 0.018 35.109 ;
        RECT  0 34.551 0.018 34.569 ;
        RECT  0 34.011 0.018 34.029 ;
        RECT  0 33.471 0.018 33.489 ;
        RECT  0 32.931 0.018 32.949 ;
        RECT  0 32.391 0.018 32.409 ;
        RECT  0 31.851 0.018 31.869 ;
        RECT  0 31.311 0.018 31.329 ;
        RECT  0 30.771 0.018 30.789 ;
        RECT  0 30.231 0.018 30.249 ;
        RECT  0 29.691 0.018 29.709 ;
        RECT  0 29.151 0.018 29.169 ;
        RECT  0 28.611 0.018 28.629 ;
        RECT  0 28.071 0.018 28.089 ;
        RECT  0 27.531 0.018 27.549 ;
        RECT  0 26.991 0.018 27.009 ;
        RECT  0 26.451 0.018 26.469 ;
        RECT  0 25.911 0.018 25.929 ;
        RECT  0 25.371 0.018 25.389 ;
        RECT  0 24.831 0.018 24.849 ;
        RECT  0 24.291 0.018 24.309 ;
        RECT  0 23.751 0.018 23.769 ;
        RECT  0 23.211 0.018 23.229 ;
        RECT  0 22.671 0.018 22.689 ;
        RECT  0 22.131 0.018 22.149 ;
        RECT  0 21.591 0.018 21.609 ;
        RECT  0 21.051 0.018 21.069 ;
        RECT  0 20.511 0.018 20.529 ;
        RECT  0 19.971 0.018 19.989 ;
        RECT  0 19.431 0.018 19.449 ;
        RECT  0 18.891 0.018 18.909 ;
        RECT  0 18.351 0.018 18.369 ;
        RECT  0 17.811 0.018 17.829 ;
        RECT  0 17.271 0.018 17.289 ;
        RECT  0 16.731 0.018 16.749 ;
        RECT  0 16.191 0.018 16.209 ;
        RECT  0 15.651 0.018 15.669 ;
        RECT  0 15.111 0.018 15.129 ;
        RECT  0 14.571 0.018 14.589 ;
        RECT  0 14.031 0.018 14.049 ;
        RECT  0 13.491 0.018 13.509 ;
        RECT  0 12.951 0.018 12.969 ;
        RECT  0 12.411 0.018 12.429 ;
        RECT  0 11.871 0.018 11.889 ;
        RECT  0 11.331 0.018 11.349 ;
        RECT  0 10.791 0.018 10.809 ;
        RECT  0 10.251 0.018 10.269 ;
        RECT  0 9.711 0.018 9.729 ;
        RECT  0 9.171 0.018 9.189 ;
        RECT  0 8.631 0.018 8.649 ;
        RECT  0 8.091 0.018 8.109 ;
        RECT  0 7.551 0.018 7.569 ;
        RECT  0 7.011 0.018 7.029 ;
        RECT  0 6.471 0.018 6.489 ;
        RECT  0 5.931 0.018 5.949 ;
        RECT  0 5.391 0.018 5.409 ;
        RECT  0 4.851 0.018 4.869 ;
        RECT  0 4.311 0.018 4.329 ;
        RECT  0 3.771 0.018 3.789 ;
        RECT  0 3.231 0.018 3.249 ;
        RECT  0 2.691 0.018 2.709 ;
        RECT  0 2.151 0.018 2.169 ;
        RECT  0 1.611 0.018 1.629 ;
        RECT  0 1.071 0.018 1.089 ;
        RECT  0 0.531 0.018 0.549 ;
      LAYER M1 ;
        RECT  0 63.711 0.018 63.729 ;
        RECT  0 63.171 0.018 63.189 ;
        RECT  0 62.631 0.018 62.649 ;
        RECT  0 62.091 0.018 62.109 ;
        RECT  0 61.551 0.018 61.569 ;
        RECT  0 61.011 0.018 61.029 ;
        RECT  0 60.471 0.018 60.489 ;
        RECT  0 59.931 0.018 59.949 ;
        RECT  0 59.391 0.018 59.409 ;
        RECT  0 58.851 0.018 58.869 ;
        RECT  0 58.311 0.018 58.329 ;
        RECT  0 57.771 0.018 57.789 ;
        RECT  0 57.231 0.018 57.249 ;
        RECT  0 56.691 0.018 56.709 ;
        RECT  0 56.151 0.018 56.169 ;
        RECT  0 55.611 0.018 55.629 ;
        RECT  0 55.071 0.018 55.089 ;
        RECT  0 54.531 0.018 54.549 ;
        RECT  0 53.991 0.018 54.009 ;
        RECT  0 53.451 0.018 53.469 ;
        RECT  0 52.911 0.018 52.929 ;
        RECT  0 52.371 0.018 52.389 ;
        RECT  0 51.831 0.018 51.849 ;
        RECT  0 51.291 0.018 51.309 ;
        RECT  0 50.751 0.018 50.769 ;
        RECT  0 50.211 0.018 50.229 ;
        RECT  0 49.671 0.018 49.689 ;
        RECT  0 49.131 0.018 49.149 ;
        RECT  0 48.591 0.018 48.609 ;
        RECT  0 48.051 0.018 48.069 ;
        RECT  0 47.511 0.018 47.529 ;
        RECT  0 46.971 0.018 46.989 ;
        RECT  0 46.431 0.018 46.449 ;
        RECT  0 45.891 0.018 45.909 ;
        RECT  0 45.351 0.018 45.369 ;
        RECT  0 44.811 0.018 44.829 ;
        RECT  0 44.271 0.018 44.289 ;
        RECT  0 43.731 0.018 43.749 ;
        RECT  0 43.191 0.018 43.209 ;
        RECT  0 42.651 0.018 42.669 ;
        RECT  0 42.111 0.018 42.129 ;
        RECT  0 41.571 0.018 41.589 ;
        RECT  0 41.031 0.018 41.049 ;
        RECT  0 40.491 0.018 40.509 ;
        RECT  0 39.951 0.018 39.969 ;
        RECT  0 39.411 0.018 39.429 ;
        RECT  0 38.871 0.018 38.889 ;
        RECT  0 38.331 0.018 38.349 ;
        RECT  0 37.791 0.018 37.809 ;
        RECT  0 37.251 0.018 37.269 ;
        RECT  0 36.711 0.018 36.729 ;
        RECT  0 36.171 0.018 36.189 ;
        RECT  0 35.631 0.018 35.649 ;
        RECT  0 35.091 0.018 35.109 ;
        RECT  0 34.551 0.018 34.569 ;
        RECT  0 34.011 0.018 34.029 ;
        RECT  0 33.471 0.018 33.489 ;
        RECT  0 32.931 0.018 32.949 ;
        RECT  0 32.391 0.018 32.409 ;
        RECT  0 31.851 0.018 31.869 ;
        RECT  0 31.311 0.018 31.329 ;
        RECT  0 30.771 0.018 30.789 ;
        RECT  0 30.231 0.018 30.249 ;
        RECT  0 29.691 0.018 29.709 ;
        RECT  0 29.151 0.018 29.169 ;
        RECT  0 28.611 0.018 28.629 ;
        RECT  0 28.071 0.018 28.089 ;
        RECT  0 27.531 0.018 27.549 ;
        RECT  0 26.991 0.018 27.009 ;
        RECT  0 26.451 0.018 26.469 ;
        RECT  0 25.911 0.018 25.929 ;
        RECT  0 25.371 0.018 25.389 ;
        RECT  0 24.831 0.018 24.849 ;
        RECT  0 24.291 0.018 24.309 ;
        RECT  0 23.751 0.018 23.769 ;
        RECT  0 23.211 0.018 23.229 ;
        RECT  0 22.671 0.018 22.689 ;
        RECT  0 22.131 0.018 22.149 ;
        RECT  0 21.591 0.018 21.609 ;
        RECT  0 21.051 0.018 21.069 ;
        RECT  0 20.511 0.018 20.529 ;
        RECT  0 19.971 0.018 19.989 ;
        RECT  0 19.431 0.018 19.449 ;
        RECT  0 18.891 0.018 18.909 ;
        RECT  0 18.351 0.018 18.369 ;
        RECT  0 17.811 0.018 17.829 ;
        RECT  0 17.271 0.018 17.289 ;
        RECT  0 16.731 0.018 16.749 ;
        RECT  0 16.191 0.018 16.209 ;
        RECT  0 15.651 0.018 15.669 ;
        RECT  0 15.111 0.018 15.129 ;
        RECT  0 14.571 0.018 14.589 ;
        RECT  0 14.031 0.018 14.049 ;
        RECT  0 13.491 0.018 13.509 ;
        RECT  0 12.951 0.018 12.969 ;
        RECT  0 12.411 0.018 12.429 ;
        RECT  0 11.871 0.018 11.889 ;
        RECT  0 11.331 0.018 11.349 ;
        RECT  0 10.791 0.018 10.809 ;
        RECT  0 10.251 0.018 10.269 ;
        RECT  0 9.711 0.018 9.729 ;
        RECT  0 9.171 0.018 9.189 ;
        RECT  0 8.631 0.018 8.649 ;
        RECT  0 8.091 0.018 8.109 ;
        RECT  0 7.551 0.018 7.569 ;
        RECT  0 7.011 0.018 7.029 ;
        RECT  0 6.471 0.018 6.489 ;
        RECT  0 5.931 0.018 5.949 ;
        RECT  0 5.391 0.018 5.409 ;
        RECT  0 4.851 0.018 4.869 ;
        RECT  0 4.311 0.018 4.329 ;
        RECT  0 3.771 0.018 3.789 ;
        RECT  0 3.231 0.018 3.249 ;
        RECT  0 2.691 0.018 2.709 ;
        RECT  0 2.151 0.018 2.169 ;
        RECT  0 1.611 0.018 1.629 ;
        RECT  0 1.071 0.018 1.089 ;
        RECT  0 0.531 0.018 0.549 ;
    END
  END VSS
  OBS
    LAYER RVTN ;
     RECT  0 0.54 63.018 0.675 ;
     RECT  0 0.945 63.018 1.215 ;
     RECT  0 1.485 63.018 1.755 ;
     RECT  0 2.025 63.018 2.295 ;
     RECT  0 2.565 63.018 2.835 ;
     RECT  0 3.105 63.018 3.375 ;
     RECT  0 3.645 63.018 3.915 ;
     RECT  0 4.185 63.018 4.455 ;
     RECT  0 4.725 63.018 4.995 ;
     RECT  0 5.265 63.018 5.535 ;
     RECT  0 5.805 63.018 6.075 ;
     RECT  0 6.345 63.018 6.615 ;
     RECT  0 6.885 63.018 7.155 ;
     RECT  0 7.425 63.018 7.695 ;
     RECT  0 7.965 63.018 8.235 ;
     RECT  0 8.505 63.018 8.775 ;
     RECT  0 9.045 63.018 9.315 ;
     RECT  0 9.585 63.018 9.855 ;
     RECT  0 10.125 63.018 10.395 ;
     RECT  0 10.665 63.018 10.935 ;
     RECT  0 11.205 63.018 11.475 ;
     RECT  0 11.745 63.018 12.015 ;
     RECT  0 12.285 63.018 12.555 ;
     RECT  0 12.825 63.018 13.095 ;
     RECT  0 13.365 63.018 13.635 ;
     RECT  0 13.905 63.018 14.175 ;
     RECT  0 14.445 63.018 14.715 ;
     RECT  0 14.985 63.018 15.255 ;
     RECT  0 15.525 63.018 15.795 ;
     RECT  0 16.065 63.018 16.335 ;
     RECT  0 16.605 63.018 16.875 ;
     RECT  0 17.145 63.018 17.415 ;
     RECT  0 17.685 63.018 17.955 ;
     RECT  0 18.225 63.018 18.495 ;
     RECT  0 18.765 63.018 19.035 ;
     RECT  0 19.305 63.018 19.575 ;
     RECT  0 19.845 63.018 20.115 ;
     RECT  0 20.385 63.018 20.655 ;
     RECT  0 20.925 63.018 21.195 ;
     RECT  0 21.465 63.018 21.735 ;
     RECT  0 22.005 63.018 22.275 ;
     RECT  0 22.545 63.018 22.815 ;
     RECT  0 23.085 63.018 23.355 ;
     RECT  0 23.625 63.018 23.895 ;
     RECT  0 24.165 63.018 24.435 ;
     RECT  0 24.705 63.018 24.975 ;
     RECT  0 25.245 63.018 25.515 ;
     RECT  0 25.785 63.018 26.055 ;
     RECT  0 26.325 63.018 26.595 ;
     RECT  0 26.865 63.018 27.135 ;
     RECT  0 27.405 63.018 27.675 ;
     RECT  0 27.945 63.018 28.215 ;
     RECT  0 28.485 63.018 28.755 ;
     RECT  0 29.025 63.018 29.295 ;
     RECT  0 29.565 63.018 29.835 ;
     RECT  0 30.105 63.018 30.375 ;
     RECT  0 30.645 63.018 30.915 ;
     RECT  0 31.185 63.018 31.455 ;
     RECT  0 31.725 63.018 31.995 ;
     RECT  0 32.265 63.018 32.535 ;
     RECT  0 32.805 63.018 33.075 ;
     RECT  0 33.345 63.018 33.615 ;
     RECT  0 33.885 63.018 34.155 ;
     RECT  0 34.425 63.018 34.695 ;
     RECT  0 34.965 63.018 35.235 ;
     RECT  0 35.505 63.018 35.775 ;
     RECT  0 36.045 63.018 36.315 ;
     RECT  0 36.585 63.018 36.855 ;
     RECT  0 37.125 63.018 37.395 ;
     RECT  0 37.665 63.018 37.935 ;
     RECT  0 38.205 63.018 38.475 ;
     RECT  0 38.745 63.018 39.015 ;
     RECT  0 39.285 63.018 39.555 ;
     RECT  0 39.825 63.018 40.095 ;
     RECT  0 40.365 63.018 40.635 ;
     RECT  0 40.905 63.018 41.175 ;
     RECT  0 41.445 63.018 41.715 ;
     RECT  0 41.985 63.018 42.255 ;
     RECT  0 42.525 63.018 42.795 ;
     RECT  0 43.065 63.018 43.335 ;
     RECT  0 43.605 63.018 43.875 ;
     RECT  0 44.145 63.018 44.415 ;
     RECT  0 44.685 63.018 44.955 ;
     RECT  0 45.225 63.018 45.495 ;
     RECT  0 45.765 63.018 46.035 ;
     RECT  0 46.305 63.018 46.575 ;
     RECT  0 46.845 63.018 47.115 ;
     RECT  0 47.385 63.018 47.655 ;
     RECT  0 47.925 63.018 48.195 ;
     RECT  0 48.465 63.018 48.735 ;
     RECT  0 49.005 63.018 49.275 ;
     RECT  0 49.545 63.018 49.815 ;
     RECT  0 50.085 63.018 50.355 ;
     RECT  0 50.625 63.018 50.895 ;
     RECT  0 51.165 63.018 51.435 ;
     RECT  0 51.705 63.018 51.975 ;
     RECT  0 52.245 63.018 52.515 ;
     RECT  0 52.785 63.018 53.055 ;
     RECT  0 53.325 63.018 53.595 ;
     RECT  0 53.865 63.018 54.135 ;
     RECT  0 54.405 63.018 54.675 ;
     RECT  0 54.945 63.018 55.215 ;
     RECT  0 55.485 63.018 55.755 ;
     RECT  0 56.025 63.018 56.295 ;
     RECT  0 56.565 63.018 56.835 ;
     RECT  0 57.105 63.018 57.375 ;
     RECT  0 57.645 63.018 57.915 ;
     RECT  0 58.185 63.018 58.455 ;
     RECT  0 58.725 63.018 58.995 ;
     RECT  0 59.265 63.018 59.535 ;
     RECT  0 59.805 63.018 60.075 ;
     RECT  0 60.345 63.018 60.615 ;
     RECT  0 60.885 63.018 61.155 ;
     RECT  0 61.425 63.018 61.695 ;
     RECT  0 61.965 63.018 62.235 ;
     RECT  0 62.505 63.018 62.775 ;
     RECT  0 63.045 63.018 63.315 ;
     RECT  0 63.585 63.018 63.855 ;
    LAYER RVTP ;
     RECT  0 0.675 63.018 0.945 ;
     RECT  0 1.215 63.018 1.485 ;
     RECT  0 1.755 63.018 2.025 ;
     RECT  0 2.295 63.018 2.565 ;
     RECT  0 2.835 63.018 3.105 ;
     RECT  0 3.375 63.018 3.645 ;
     RECT  0 3.915 63.018 4.185 ;
     RECT  0 4.455 63.018 4.725 ;
     RECT  0 4.995 63.018 5.265 ;
     RECT  0 5.535 63.018 5.805 ;
     RECT  0 6.075 63.018 6.345 ;
     RECT  0 6.615 63.018 6.885 ;
     RECT  0 7.155 63.018 7.425 ;
     RECT  0 7.695 63.018 7.965 ;
     RECT  0 8.235 63.018 8.505 ;
     RECT  0 8.775 63.018 9.045 ;
     RECT  0 9.315 63.018 9.585 ;
     RECT  0 9.855 63.018 10.125 ;
     RECT  0 10.395 63.018 10.665 ;
     RECT  0 10.935 63.018 11.205 ;
     RECT  0 11.475 63.018 11.745 ;
     RECT  0 12.015 63.018 12.285 ;
     RECT  0 12.555 63.018 12.825 ;
     RECT  0 13.095 63.018 13.365 ;
     RECT  0 13.635 63.018 13.905 ;
     RECT  0 14.175 63.018 14.445 ;
     RECT  0 14.715 63.018 14.985 ;
     RECT  0 15.255 63.018 15.525 ;
     RECT  0 15.795 63.018 16.065 ;
     RECT  0 16.335 63.018 16.605 ;
     RECT  0 16.875 63.018 17.145 ;
     RECT  0 17.415 63.018 17.685 ;
     RECT  0 17.955 63.018 18.225 ;
     RECT  0 18.495 63.018 18.765 ;
     RECT  0 19.035 63.018 19.305 ;
     RECT  0 19.575 63.018 19.845 ;
     RECT  0 20.115 63.018 20.385 ;
     RECT  0 20.655 63.018 20.925 ;
     RECT  0 21.195 63.018 21.465 ;
     RECT  0 21.735 63.018 22.005 ;
     RECT  0 22.275 63.018 22.545 ;
     RECT  0 22.815 63.018 23.085 ;
     RECT  0 23.355 63.018 23.625 ;
     RECT  0 23.895 63.018 24.165 ;
     RECT  0 24.435 63.018 24.705 ;
     RECT  0 24.975 63.018 25.245 ;
     RECT  0 25.515 63.018 25.785 ;
     RECT  0 26.055 63.018 26.325 ;
     RECT  0 26.595 63.018 26.865 ;
     RECT  0 27.135 63.018 27.405 ;
     RECT  0 27.675 63.018 27.945 ;
     RECT  0 28.215 63.018 28.485 ;
     RECT  0 28.755 63.018 29.025 ;
     RECT  0 29.295 63.018 29.565 ;
     RECT  0 29.835 63.018 30.105 ;
     RECT  0 30.375 63.018 30.645 ;
     RECT  0 30.915 63.018 31.185 ;
     RECT  0 31.455 63.018 31.725 ;
     RECT  0 31.995 63.018 32.265 ;
     RECT  0 32.535 63.018 32.805 ;
     RECT  0 33.075 63.018 33.345 ;
     RECT  0 33.615 63.018 33.885 ;
     RECT  0 34.155 63.018 34.425 ;
     RECT  0 34.695 63.018 34.965 ;
     RECT  0 35.235 63.018 35.505 ;
     RECT  0 35.775 63.018 36.045 ;
     RECT  0 36.315 63.018 36.585 ;
     RECT  0 36.855 63.018 37.125 ;
     RECT  0 37.395 63.018 37.665 ;
     RECT  0 37.935 63.018 38.205 ;
     RECT  0 38.475 63.018 38.745 ;
     RECT  0 39.015 63.018 39.285 ;
     RECT  0 39.555 63.018 39.825 ;
     RECT  0 40.095 63.018 40.365 ;
     RECT  0 40.635 63.018 40.905 ;
     RECT  0 41.175 63.018 41.445 ;
     RECT  0 41.715 63.018 41.985 ;
     RECT  0 42.255 63.018 42.525 ;
     RECT  0 42.795 63.018 43.065 ;
     RECT  0 43.335 63.018 43.605 ;
     RECT  0 43.875 63.018 44.145 ;
     RECT  0 44.415 63.018 44.685 ;
     RECT  0 44.955 63.018 45.225 ;
     RECT  0 45.495 63.018 45.765 ;
     RECT  0 46.035 63.018 46.305 ;
     RECT  0 46.575 63.018 46.845 ;
     RECT  0 47.115 63.018 47.385 ;
     RECT  0 47.655 63.018 47.925 ;
     RECT  0 48.195 63.018 48.465 ;
     RECT  0 48.735 63.018 49.005 ;
     RECT  0 49.275 63.018 49.545 ;
     RECT  0 49.815 63.018 50.085 ;
     RECT  0 50.355 63.018 50.625 ;
     RECT  0 50.895 63.018 51.165 ;
     RECT  0 51.435 63.018 51.705 ;
     RECT  0 51.975 63.018 52.245 ;
     RECT  0 52.515 63.018 52.785 ;
     RECT  0 53.055 63.018 53.325 ;
     RECT  0 53.595 63.018 53.865 ;
     RECT  0 54.135 63.018 54.405 ;
     RECT  0 54.675 63.018 54.945 ;
     RECT  0 55.215 63.018 55.485 ;
     RECT  0 55.755 63.018 56.025 ;
     RECT  0 56.295 63.018 56.565 ;
     RECT  0 56.835 63.018 57.105 ;
     RECT  0 57.375 63.018 57.645 ;
     RECT  0 57.915 63.018 58.185 ;
     RECT  0 58.455 63.018 58.725 ;
     RECT  0 58.995 63.018 59.265 ;
     RECT  0 59.535 63.018 59.805 ;
     RECT  0 60.075 63.018 60.345 ;
     RECT  0 60.615 63.018 60.885 ;
     RECT  0 61.155 63.018 61.425 ;
     RECT  0 61.695 63.018 61.965 ;
     RECT  0 62.235 63.018 62.505 ;
     RECT  0 62.775 63.018 63.045 ;
     RECT  0 63.315 63.018 63.585 ;
     RECT  0 63.855 63.018 63.99 ;
    LAYER M1 ;
     RECT  0 0.531 63.018 63.999 ;
    LAYER M2 ;
     RECT  0 0.531 12.523 63.999 ;
     RECT  12.523 0.531 13.351 64.044 ;
     RECT  13.351 0.531 18.499 64.08 ;
     RECT  18.499 0.531 20.803 64.188 ;
     RECT  20.803 0.531 23.279 64.422 ;
     RECT  23.279 0.531 24.655 64.224 ;
     RECT  24.655 0.531 26.527 64.35 ;
     RECT  26.527 0.531 27.527 64.539 ;
     RECT  27.527 0.531 29.219 64.224 ;
     RECT  29.219 0.531 29.975 64.08 ;
     RECT  29.975 0.531 30.191 64.044 ;
     RECT  30.191 0.531 31.171 63.999 ;
     RECT  31.171 0.531 34.223 64.044 ;
     RECT  34.223 0.531 63.018 63.999 ;
     RECT  63.018 21.168 63.023 21.186 ;
     RECT  63.018 22.824 63.023 22.842 ;
     RECT  63.018 40.338 63.023 40.356 ;
     RECT  63.018 46.512 63.023 46.53 ;
     RECT  63.018 55.53 63.023 55.548 ;
    LAYER M3 ;
     RECT  32.655 0.523 32.745 0.571 ;
     RECT  43.455 0.523 43.545 0.607 ;
     RECT  32.655 0.571 32.994 0.679 ;
     RECT  33.804 0.643 33.822 0.679 ;
     RECT  38.055 0.523 38.145 0.679 ;
     RECT  43.344 0.607 43.545 0.679 ;
     RECT  16.455 0.523 16.545 0.751 ;
     RECT  17.856 0.607 17.874 0.751 ;
     RECT  22.716 0.715 22.734 0.751 ;
     RECT  35.82 0.715 35.982 0.751 ;
     RECT  43.344 0.679 43.938 0.751 ;
     RECT  0.255 0.523 0.345 0.793 ;
     RECT  5.655 0.523 5.745 0.793 ;
     RECT  11.055 0.523 11.145 0.793 ;
     RECT  16.344 0.751 16.545 0.793 ;
     RECT  21.855 0.523 21.945 0.793 ;
     RECT  22.716 0.751 23.31 0.793 ;
     RECT  27.255 0.523 27.345 0.793 ;
     RECT  37.8 0.679 38.145 0.793 ;
     RECT  48.855 0.523 48.945 0.793 ;
     RECT  54.255 0.523 54.345 0.793 ;
     RECT  59.655 0.523 59.745 0.793 ;
     RECT  27.255 0.793 27.537 0.859 ;
     RECT  36.792 0.751 36.81 0.877 ;
     RECT  26.28 0.859 26.298 0.949 ;
     RECT  27.108 0.859 27.537 0.949 ;
     RECT  16.344 0.793 16.737 0.955 ;
     RECT  17.64 0.751 18.09 0.955 ;
     RECT  16.2 0.955 16.737 0.985 ;
     RECT  17.604 0.955 18.09 0.985 ;
     RECT  32.655 0.679 33.822 0.985 ;
     RECT  16.128 0.985 18.09 1.021 ;
     RECT  18.972 0.751 18.99 1.021 ;
     RECT  24.768 0.859 24.786 1.021 ;
     RECT  31.572 0.187 31.59 1.021 ;
     RECT  32.616 0.985 33.822 1.021 ;
     RECT  35.064 0.751 35.982 1.021 ;
     RECT  36.72 0.877 36.81 1.021 ;
     RECT  37.8 0.793 38.337 1.021 ;
     RECT  41.796 0.811 41.814 1.021 ;
     RECT  43.344 0.751 44.262 1.021 ;
     RECT  32.616 1.021 36.81 1.051 ;
     RECT  37.692 1.021 38.337 1.051 ;
     RECT  21.855 0.793 23.31 1.111 ;
     RECT  24.156 1.021 25.254 1.111 ;
     RECT  26.28 0.949 27.537 1.111 ;
     RECT  32.616 1.051 38.337 1.111 ;
     RECT  41.796 1.021 41.958 1.111 ;
     RECT  42.732 1.021 44.766 1.111 ;
     RECT  32.616 1.111 39.006 1.133 ;
     RECT  15.948 1.021 18.99 1.139 ;
     RECT  19.944 1.111 20.754 1.255 ;
     RECT  31.428 1.021 31.59 1.255 ;
     RECT  34.704 1.133 39.006 1.255 ;
     RECT  16.02 1.139 18.99 1.291 ;
     RECT  19.8 1.255 20.754 1.291 ;
     RECT  21.816 1.111 23.31 1.291 ;
     RECT  30.96 1.255 31.878 1.291 ;
     RECT  32.616 1.133 33.966 1.291 ;
     RECT  34.704 1.255 39.078 1.291 ;
     RECT  21.816 1.291 23.418 1.387 ;
     RECT  41.796 1.111 44.766 1.435 ;
     RECT  21.492 1.387 23.418 1.525 ;
     RECT  24.156 1.111 27.918 1.525 ;
     RECT  30.96 1.291 33.966 1.525 ;
     RECT  40.932 1.111 40.95 1.525 ;
     RECT  29.088 1.525 29.106 1.561 ;
     RECT  30.636 1.525 33.966 1.561 ;
     RECT  40.896 1.525 40.95 1.561 ;
     RECT  41.796 1.435 44.838 1.561 ;
     RECT  46.656 1.381 46.674 1.561 ;
     RECT  21.492 1.525 27.918 1.687 ;
     RECT  29.088 1.561 29.682 1.687 ;
     RECT  40.896 1.561 44.838 1.687 ;
     RECT  45.612 1.675 45.63 1.687 ;
     RECT  30.528 1.561 33.966 1.723 ;
     RECT  34.704 1.291 39.618 1.759 ;
     RECT  40.896 1.687 45.63 1.759 ;
     RECT  16.02 1.291 20.754 1.795 ;
     RECT  21.492 1.687 29.682 1.795 ;
     RECT  40.86 1.759 45.63 1.831 ;
     RECT  46.548 1.561 46.674 1.831 ;
     RECT  34.704 1.759 39.762 1.957 ;
     RECT  30.492 1.723 33.966 1.993 ;
     RECT  34.704 1.957 39.87 1.993 ;
     RECT  30.492 1.993 39.87 2.065 ;
     RECT  40.86 1.831 45.774 2.065 ;
     RECT  16.02 1.795 29.682 2.101 ;
     RECT  30.492 2.065 45.774 2.101 ;
     RECT  46.512 1.831 46.674 2.101 ;
     RECT  16.02 2.101 46.674 2.191 ;
     RECT  15.984 2.191 46.674 2.227 ;
     RECT  15.66 2.227 46.674 2.371 ;
     RECT  15.048 2.371 46.674 2.461 ;
     RECT  15.012 2.461 46.674 2.488 ;
     RECT  14.868 2.488 46.674 2.497 ;
     RECT  14.868 2.497 46.746 2.731 ;
     RECT  14.58 2.731 46.746 2.813 ;
     RECT  15.012 2.813 46.746 2.911 ;
     RECT  15.012 2.911 46.89 3.029 ;
     RECT  48.855 0.793 49.137 3.271 ;
     RECT  47.736 3.181 47.754 3.299 ;
     RECT  48.492 3.271 49.137 3.301 ;
     RECT  15.3 3.029 46.89 3.304 ;
     RECT  52.272 3.271 52.29 3.307 ;
     RECT  47.916 3.301 49.137 3.343 ;
     RECT  52.2 3.307 52.29 3.541 ;
     RECT  52.164 3.541 52.29 3.685 ;
     RECT  50.148 3.685 50.166 3.721 ;
     RECT  61.992 3.145 62.01 3.721 ;
     RECT  15.3 3.304 47.178 3.811 ;
     RECT  61.92 3.721 62.01 3.839 ;
     RECT  61.92 3.839 61.938 3.919 ;
     RECT  61.848 3.919 61.938 3.965 ;
     RECT  14.256 3.271 14.274 3.991 ;
     RECT  15.048 3.811 47.178 3.991 ;
     RECT  50.148 3.721 51.03 3.991 ;
     RECT  50.148 3.991 51.318 4.081 ;
     RECT  50.148 4.081 51.354 4.189 ;
     RECT  50.04 4.189 51.354 4.261 ;
     RECT  52.164 3.685 52.47 4.261 ;
     RECT  50.04 4.261 52.47 4.351 ;
     RECT  14.256 3.991 47.178 4.415 ;
     RECT  15.048 4.415 47.178 4.459 ;
     RECT  47.916 3.343 49.194 4.459 ;
     RECT  15.048 4.459 49.23 4.621 ;
     RECT  62.784 3.451 62.802 4.649 ;
     RECT  15.048 4.621 49.266 4.657 ;
     RECT  50.04 4.351 52.542 4.657 ;
     RECT  58.68 4.621 58.698 4.729 ;
     RECT  14.256 4.415 14.274 4.765 ;
     RECT  61.92 3.965 61.938 4.765 ;
     RECT  58.212 4.729 58.698 4.793 ;
     RECT  61.92 4.765 62.694 4.829 ;
     RECT  15.048 4.657 52.542 4.999 ;
     RECT  54.255 0.793 54.537 5.071 ;
     RECT  56.16 4.765 56.178 5.071 ;
     RECT  14.184 4.765 14.274 5.083 ;
     RECT  13.5 5.083 14.274 5.117 ;
     RECT  15.048 4.999 52.722 5.161 ;
     RECT  54.255 5.071 55.35 5.161 ;
     RECT  56.088 5.071 56.178 5.161 ;
     RECT  61.92 4.829 62.37 5.189 ;
     RECT  58.212 4.793 58.662 5.197 ;
     RECT  15.048 5.161 52.974 5.225 ;
     RECT  20.232 5.225 52.974 5.269 ;
     RECT  14.256 5.117 14.274 5.305 ;
     RECT  15.048 5.225 19.494 5.305 ;
     RECT  61.92 5.189 62.334 5.305 ;
     RECT  57.672 5.197 58.662 5.461 ;
     RECT  20.232 5.269 53.442 5.575 ;
     RECT  54.255 5.161 56.862 5.575 ;
     RECT  57.6 5.461 58.662 5.575 ;
     RECT  20.232 5.575 56.862 5.611 ;
     RECT  57.6 5.575 58.734 5.611 ;
     RECT  61.668 5.305 62.334 5.611 ;
     RECT  20.232 5.611 58.734 5.765 ;
     RECT  51.912 5.765 58.734 5.845 ;
     RECT  59.655 0.793 59.937 5.845 ;
     RECT  61.344 5.611 62.334 5.845 ;
     RECT  61.2 5.845 62.334 5.885 ;
     RECT  14.256 5.305 19.494 6.115 ;
     RECT  20.232 5.765 51.102 6.115 ;
     RECT  13.5 5.117 13.518 6.151 ;
     RECT  14.256 6.115 51.102 6.151 ;
     RECT  51.912 5.845 59.937 6.151 ;
     RECT  51.912 6.151 59.994 6.283 ;
     RECT  61.2 5.885 61.938 6.283 ;
     RECT  62.784 6.313 62.802 6.379 ;
     RECT  13.5 6.151 51.102 6.583 ;
     RECT  51.912 6.283 61.938 6.583 ;
     RECT  13.5 6.583 61.938 6.691 ;
     RECT  62.784 6.379 62.874 6.763 ;
     RECT  13.284 6.691 61.938 6.817 ;
     RECT  62.784 6.763 63.018 6.817 ;
     RECT  13.284 6.817 63.018 7.357 ;
     RECT  13.248 7.357 63.018 7.627 ;
     RECT  13.212 7.627 63.018 7.735 ;
     RECT  13.104 7.735 63.018 7.889 ;
     RECT  13.32 7.889 63.018 8.671 ;
     RECT  11.055 0.793 11.337 8.941 ;
     RECT  12.636 8.671 63.018 8.941 ;
     RECT  11.055 8.941 63.018 9.355 ;
     RECT  10.98 9.355 63.018 9.391 ;
     RECT  10.836 9.391 63.018 9.625 ;
     RECT  10.548 9.625 63.018 9.739 ;
     RECT  10.26 9.739 63.018 10.193 ;
     RECT  10.26 10.193 45.774 10.291 ;
     RECT  10.188 10.291 45.774 10.625 ;
     RECT  10.476 10.625 45.774 11.011 ;
     RECT  46.62 10.193 63.018 11.011 ;
     RECT  10.476 11.011 63.018 11.443 ;
     RECT  10.296 11.443 63.018 11.551 ;
     RECT  10.26 11.551 63.018 11.659 ;
     RECT  4.788 11.659 4.806 11.677 ;
     RECT  4.752 11.677 4.806 11.821 ;
     RECT  5.655 0.793 5.937 11.821 ;
     RECT  8.388 11.641 8.406 11.821 ;
     RECT  9.648 11.659 63.018 11.821 ;
     RECT  8.388 11.821 63.018 11.911 ;
     RECT  7.884 11.911 63.018 11.941 ;
     RECT  7.416 11.941 63.018 11.981 ;
     RECT  13.392 11.981 63.018 12.083 ;
     RECT  4.752 11.821 5.937 12.361 ;
     RECT  4.644 12.361 5.937 12.487 ;
     RECT  7.416 11.981 12.51 12.487 ;
     RECT  2.844 12.451 2.862 12.517 ;
     RECT  4.356 12.487 5.937 12.523 ;
     RECT  4.356 12.523 5.994 12.631 ;
     RECT  7.38 12.487 12.51 12.631 ;
     RECT  4.356 12.631 12.51 12.829 ;
     RECT  13.392 12.083 14.094 12.829 ;
     RECT  14.976 12.083 63.018 12.829 ;
     RECT  2.664 12.517 2.862 12.865 ;
     RECT  2.412 12.865 2.862 12.901 ;
     RECT  3.6 12.631 3.618 12.901 ;
     RECT  4.356 12.829 12.546 12.901 ;
     RECT  4.356 12.901 12.582 12.991 ;
     RECT  13.392 12.829 63.018 12.991 ;
     RECT  4.356 12.991 63.018 13.181 ;
     RECT  0.255 0.793 0.537 13.441 ;
     RECT  1.548 13.291 1.566 13.441 ;
     RECT  2.412 12.901 3.618 13.441 ;
     RECT  4.356 13.181 60.174 13.441 ;
     RECT  0.255 13.441 60.174 14.071 ;
     RECT  60.984 13.181 63.018 14.071 ;
     RECT  0.255 14.071 63.018 14.711 ;
     RECT  0.255 14.711 0.537 15.565 ;
     RECT  1.26 14.711 63.018 15.565 ;
     RECT  0.255 15.565 63.018 15.773 ;
     RECT  0.255 15.773 8.874 15.899 ;
     RECT  9.612 15.773 63.018 15.989 ;
     RECT  1.26 15.899 8.874 16.915 ;
     RECT  9.648 15.989 63.018 16.915 ;
     RECT  0.255 15.899 0.537 17.149 ;
     RECT  1.26 16.915 63.018 17.149 ;
     RECT  0.255 17.149 63.018 18.797 ;
     RECT  0.255 18.797 49.59 19.651 ;
     RECT  0.255 19.651 49.626 19.771 ;
     RECT  50.472 18.797 63.018 19.771 ;
     RECT  0.255 19.771 63.018 20.011 ;
     RECT  0.144 20.011 63.018 20.489 ;
     RECT  0.255 20.489 63.018 21.191 ;
     RECT  0.255 21.191 62.982 21.541 ;
     RECT  0.144 21.541 62.982 22.235 ;
     RECT  0.216 22.235 62.982 22.819 ;
     RECT  0.216 22.819 63.018 23.855 ;
     RECT  0.255 23.855 7.974 24.745 ;
     RECT  8.748 23.855 63.018 24.745 ;
     RECT  0.255 24.745 63.018 25.003 ;
     RECT  0.252 25.003 63.018 25.043 ;
     RECT  0.255 25.043 63.018 25.889 ;
     RECT  0.255 25.889 9.234 26.635 ;
     RECT  9.972 25.889 63.018 26.635 ;
     RECT  0.255 26.635 63.018 27.245 ;
     RECT  34.092 27.245 63.018 27.329 ;
     RECT  0.255 27.245 33.318 27.437 ;
     RECT  34.164 27.329 63.018 28.267 ;
     RECT  0.255 27.437 33.246 28.291 ;
     RECT  34.02 28.267 63.018 28.291 ;
     RECT  0.255 28.291 63.018 28.417 ;
     RECT  0.252 28.417 63.018 28.493 ;
     RECT  0.255 28.493 63.018 29.605 ;
     RECT  0.252 29.605 63.018 29.645 ;
     RECT  0.255 29.645 63.018 31.387 ;
     RECT  0.252 31.387 63.018 32.305 ;
     RECT  0.216 32.305 63.018 34.205 ;
     RECT  0.255 34.205 63.018 35.311 ;
     RECT  0.216 35.311 63.018 37.355 ;
     RECT  0.255 37.355 63.018 39.217 ;
     RECT  0.216 39.217 63.018 40.361 ;
     RECT  0.216 40.361 62.838 40.559 ;
     RECT  0.216 40.559 62.802 40.595 ;
     RECT  0.255 40.595 62.802 41.477 ;
     RECT  0.255 41.477 62.73 42.179 ;
     RECT  0.255 42.179 62.694 43.051 ;
     RECT  0.255 43.051 62.73 43.267 ;
     RECT  0.216 43.267 62.73 43.771 ;
     RECT  0.216 43.771 62.766 44.221 ;
     RECT  0.216 44.221 62.802 44.249 ;
     RECT  0.255 44.249 62.802 44.339 ;
     RECT  0.255 44.339 62.766 45.571 ;
     RECT  0.255 45.571 62.874 46.039 ;
     RECT  0.255 46.039 62.946 46.507 ;
     RECT  0.255 46.507 63.018 47.317 ;
     RECT  0.216 47.317 63.018 47.885 ;
     RECT  0.255 47.885 63.018 48.739 ;
     RECT  0.216 48.739 63.018 49.009 ;
     RECT  0.18 49.009 63.018 49.271 ;
     RECT  0.216 49.271 63.018 50.089 ;
     RECT  0.18 50.089 63.018 52.007 ;
     RECT  0.255 52.007 63.018 54.187 ;
     RECT  0.252 54.187 63.018 54.365 ;
     RECT  0.255 54.365 63.018 55.553 ;
     RECT  0.255 55.553 62.982 56.875 ;
     RECT  0.216 56.875 62.982 57.443 ;
     RECT  0.255 57.443 62.982 58.991 ;
     RECT  0.255 58.991 0.537 59.737 ;
     RECT  1.26 58.991 62.982 59.737 ;
     RECT  0.255 59.737 62.982 59.801 ;
     RECT  0.255 59.801 62.91 60.115 ;
     RECT  0.252 60.115 62.91 60.413 ;
     RECT  0.255 60.413 62.91 60.989 ;
     RECT  1.548 60.989 62.91 61.727 ;
     RECT  1.548 61.727 62.046 61.771 ;
     RECT  1.368 61.771 62.046 61.889 ;
     RECT  62.784 61.727 62.91 62.033 ;
     RECT  62.784 62.033 62.802 62.141 ;
     RECT  1.368 61.889 61.218 62.195 ;
     RECT  0.255 60.989 0.537 62.731 ;
     RECT  1.368 62.195 61.11 62.731 ;
     RECT  0.255 62.731 61.11 63.005 ;
     RECT  1.476 63.005 61.11 63.275 ;
     RECT  1.476 63.275 3.618 63.311 ;
     RECT  4.5 63.275 61.11 63.311 ;
     RECT  4.932 63.311 61.11 63.509 ;
     RECT  1.584 63.311 3.618 63.545 ;
     RECT  4.932 63.509 53.262 63.545 ;
     RECT  4.932 63.545 12.546 63.581 ;
     RECT  54 63.509 61.11 63.581 ;
     RECT  1.8 63.545 3.618 63.617 ;
     RECT  56.088 63.581 61.11 63.653 ;
     RECT  1.944 63.617 3.618 63.689 ;
     RECT  13.284 63.545 15.354 63.689 ;
     RECT  16.092 63.545 53.262 63.689 ;
     RECT  56.088 63.653 61.074 63.689 ;
     RECT  52.848 63.689 53.262 63.725 ;
     RECT  0.255 63.005 0.537 63.737 ;
     RECT  2.844 63.689 3.618 63.773 ;
     RECT  1.944 63.689 2.106 63.779 ;
     RECT  2.952 63.773 3.546 63.779 ;
     RECT  4.968 63.581 12.546 63.779 ;
     RECT  13.284 63.689 15.282 63.779 ;
     RECT  16.092 63.689 47.574 63.779 ;
     RECT  48.744 63.689 52.074 63.779 ;
     RECT  52.848 63.725 53.226 63.779 ;
     RECT  54 63.581 55.314 63.779 ;
     RECT  56.088 63.689 61.002 63.779 ;
     RECT  5.148 63.779 11.337 63.815 ;
     RECT  13.284 63.779 14.058 63.815 ;
     RECT  16.092 63.779 44.874 63.815 ;
     RECT  50.76 63.779 52.002 63.815 ;
     RECT  53.064 63.779 53.082 63.815 ;
     RECT  54.18 63.779 55.242 63.815 ;
     RECT  56.304 63.779 58.95 63.815 ;
     RECT  59.847 63.779 61.002 63.815 ;
     RECT  1.944 63.779 1.962 63.821 ;
     RECT  2.952 63.779 3.402 63.821 ;
     RECT  9.612 63.815 11.337 63.821 ;
     RECT  13.356 63.815 14.058 63.821 ;
     RECT  16.092 63.815 44.73 63.821 ;
     RECT  58.068 63.815 58.95 63.821 ;
     RECT  15.084 63.779 15.246 63.824 ;
     RECT  60.984 63.815 61.002 63.824 ;
     RECT  5.616 63.815 5.937 63.851 ;
     RECT  9.864 63.821 11.337 63.851 ;
     RECT  16.092 63.821 16.737 63.851 ;
     RECT  17.532 63.821 44.406 63.851 ;
     RECT  45.648 63.779 47.538 63.851 ;
     RECT  50.76 63.815 51.354 63.851 ;
     RECT  54.447 63.815 55.242 63.851 ;
     RECT  58.068 63.821 58.086 63.851 ;
     RECT  58.932 63.821 58.95 63.851 ;
     RECT  2.952 63.821 3.078 63.887 ;
     RECT  18.396 63.851 37.026 63.917 ;
     RECT  2.952 63.887 2.97 63.923 ;
     RECT  18.396 63.917 36.954 63.923 ;
     RECT  17.532 63.851 17.55 63.959 ;
     RECT  18.504 63.923 36.954 63.959 ;
     RECT  54.447 63.851 54.774 63.959 ;
     RECT  0.447 63.737 0.537 64.007 ;
     RECT  5.847 63.851 5.937 64.007 ;
     RECT  11.247 63.851 11.337 64.007 ;
     RECT  16.647 63.851 16.737 64.007 ;
     RECT  49.047 63.779 49.41 64.007 ;
     RECT  54.447 63.959 54.537 64.007 ;
     RECT  59.847 63.815 59.937 64.007 ;
     RECT  12.528 63.779 12.546 64.049 ;
     RECT  19.26 63.959 36.954 64.049 ;
     RECT  13.356 63.821 13.374 64.085 ;
     RECT  19.98 64.049 36.954 64.085 ;
     RECT  10.224 63.851 10.242 64.109 ;
     RECT  37.872 63.851 44.406 64.109 ;
     RECT  8.748 63.815 8.766 64.157 ;
     RECT  45.648 63.851 46.926 64.157 ;
     RECT  18.504 63.959 18.522 64.193 ;
     RECT  37.908 64.109 44.406 64.205 ;
     RECT  45.648 64.157 45.666 64.205 ;
     RECT  22.464 64.085 36.954 64.253 ;
     RECT  38.016 64.205 38.214 64.253 ;
     RECT  22.464 64.253 30.402 64.349 ;
     RECT  19.98 64.085 21.582 64.397 ;
     RECT  22.752 64.349 30.402 64.397 ;
     RECT  39.024 64.205 44.406 64.397 ;
     RECT  20.808 64.397 21.582 64.427 ;
     RECT  19.98 64.397 19.998 64.445 ;
     RECT  22.752 64.397 28.89 64.445 ;
     RECT  31.14 64.253 36.954 64.445 ;
     RECT  38.196 64.253 38.214 64.445 ;
     RECT  40.248 64.397 44.118 64.445 ;
     RECT  24.948 64.445 28.89 64.493 ;
     RECT  31.248 64.445 36.954 64.493 ;
     RECT  40.248 64.445 43.866 64.493 ;
     RECT  31.572 64.493 33.966 64.541 ;
     RECT  21.024 64.427 21.582 64.589 ;
     RECT  22.824 64.445 23.994 64.589 ;
     RECT  25.056 64.493 25.146 64.589 ;
     RECT  26.532 64.493 27.882 64.589 ;
     RECT  28.764 64.493 28.782 64.589 ;
     RECT  29.628 64.397 30.402 64.589 ;
     RECT  32.436 64.541 33.966 64.589 ;
     RECT  34.92 64.493 34.938 64.589 ;
     RECT  35.748 64.493 35.766 64.589 ;
     RECT  39.024 64.397 39.258 64.589 ;
     RECT  40.248 64.493 40.266 64.589 ;
     RECT  41.04 64.493 41.634 64.589 ;
     RECT  42.48 64.493 43.866 64.589 ;
     RECT  22.824 64.589 22.842 64.637 ;
     RECT  27.684 64.589 27.702 64.637 ;
     RECT  30.384 64.589 30.402 64.637 ;
     RECT  33.444 64.589 33.462 64.637 ;
     RECT  15.228 63.824 15.246 64.685 ;
     RECT  31.572 64.541 31.698 64.685 ;
     RECT  43.236 64.589 43.722 64.685 ;
     RECT  46.908 64.157 46.926 64.685 ;
     RECT  25.128 64.589 25.146 64.733 ;
     RECT  31.68 64.685 31.698 64.733 ;
     RECT  32.436 64.589 32.454 64.733 ;
     RECT  36.504 64.493 36.522 64.733 ;
     RECT  43.704 64.685 43.722 64.733 ;
     RECT  49.392 64.007 49.41 64.733 ;
    LAYER M4 ;
     RECT  0.092 22.176 0.133 22.2 ;
     RECT  0.092 20.016 0.248 20.04 ;
     RECT  0.133 22.176 0.248 22.824 ;
     RECT  0.133 25.008 0.248 25.032 ;
     RECT  0.133 28.464 0.248 28.488 ;
     RECT  0.133 29.616 0.248 29.64 ;
     RECT  0.133 31.392 0.248 31.416 ;
     RECT  0.205 34.176 0.248 34.2 ;
     RECT  0.205 36.288 0.248 36.312 ;
     RECT  0.205 39.312 0.248 39.336 ;
     RECT  0.133 49.44 0.248 49.464 ;
     RECT  0.241 54.192 0.248 54.216 ;
     RECT  0.133 57.408 0.248 57.432 ;
     RECT  0.248 0.528 0.352 63.732 ;
     RECT  0.352 0.798 0.44 63.732 ;
     RECT  0.44 0.798 0.544 64.002 ;
     RECT  0.544 48.96 0.659 48.984 ;
     RECT  0.544 26.112 0.94 31.8 ;
     RECT  0.544 39.312 1.139 41.064 ;
     RECT  0.544 13.824 1.235 14.616 ;
     RECT  0.544 16.272 1.379 19.992 ;
     RECT  1.379 16.272 1.42 18.168 ;
     RECT  0.94 26.208 1.42 31.8 ;
     RECT  1.42 26.208 1.469 29.928 ;
     RECT  1.469 26.208 1.475 26.328 ;
     RECT  1.235 13.824 1.523 13.848 ;
     RECT  0.544 33.36 1.523 37.032 ;
     RECT  0.544 43.536 1.532 43.56 ;
     RECT  0.544 57.504 1.532 59.208 ;
     RECT  1.42 30.96 1.537 31.8 ;
     RECT  1.532 57.264 1.537 59.208 ;
     RECT  1.532 43.536 1.573 44.088 ;
     RECT  0.544 62.016 1.573 63 ;
     RECT  1.475 26.208 1.613 26.232 ;
     RECT  0.544 54.192 1.613 55.32 ;
     RECT  1.532 13.296 1.619 13.32 ;
     RECT  1.537 56.352 1.628 59.208 ;
     RECT  1.613 54.192 1.645 54.696 ;
     RECT  0.544 60.672 1.645 60.696 ;
     RECT  1.139 39.312 1.676 40.68 ;
     RECT  0.544 47.712 1.681 47.736 ;
     RECT  0.544 50.64 1.724 51.384 ;
     RECT  1.573 43.536 1.753 45.528 ;
     RECT  1.42 16.272 1.757 17.112 ;
     RECT  1.469 27.36 1.757 29.928 ;
     RECT  1.379 19.344 1.789 19.992 ;
     RECT  1.724 50.64 1.789 51.576 ;
     RECT  1.676 39.12 1.813 40.68 ;
     RECT  1.757 16.272 1.825 16.296 ;
     RECT  1.628 55.968 1.861 59.208 ;
     RECT  1.645 60.384 1.861 60.696 ;
     RECT  1.42 18.144 1.865 18.168 ;
     RECT  1.523 33.36 1.865 35.88 ;
     RECT  1.753 42.768 1.868 45.528 ;
     RECT  1.573 61.968 1.909 63 ;
     RECT  0.544 52.704 1.916 53.064 ;
     RECT  1.645 54.096 1.916 54.696 ;
     RECT  1.868 42.144 1.933 45.528 ;
     RECT  1.909 61.968 1.933 63.288 ;
     RECT  1.789 50.016 1.957 51.576 ;
     RECT  1.916 52.704 1.957 54.696 ;
     RECT  1.861 55.968 1.964 60.696 ;
     RECT  1.813 38.688 1.969 40.68 ;
     RECT  1.964 55.968 1.969 60.936 ;
     RECT  1.933 61.968 1.969 63.816 ;
     RECT  1.865 33.84 2.045 35.88 ;
     RECT  1.757 27.648 2.081 29.928 ;
     RECT  1.933 42.144 2.101 45.912 ;
     RECT  1.789 19.344 2.113 20.664 ;
     RECT  0.544 21.648 2.113 24.456 ;
     RECT  2.101 42.048 2.147 45.912 ;
     RECT  1.537 30.96 2.149 31.848 ;
     RECT  1.969 38.16 2.252 40.68 ;
     RECT  2.081 27.648 2.291 29.256 ;
     RECT  2.149 30.96 2.291 31.944 ;
     RECT  2.113 19.344 2.293 24.456 ;
     RECT  2.113 25.68 2.293 25.704 ;
     RECT  1.523 36.864 2.293 37.032 ;
     RECT  2.252 38.16 2.293 40.824 ;
     RECT  2.147 42.048 2.293 42.312 ;
     RECT  1.681 47.712 2.293 48.456 ;
     RECT  1.957 50.016 2.293 54.696 ;
     RECT  2.293 36.864 2.38 42.312 ;
     RECT  2.38 38.16 2.405 42.312 ;
     RECT  2.293 19.344 2.473 25.704 ;
     RECT  2.396 14.496 2.509 14.52 ;
     RECT  2.405 38.16 2.572 38.472 ;
     RECT  2.509 14.16 2.588 14.52 ;
     RECT  2.293 47.712 2.617 54.696 ;
     RECT  2.617 47.328 2.629 54.696 ;
     RECT  1.969 55.968 2.629 63.816 ;
     RECT  2.147 43.536 2.653 45.912 ;
     RECT  2.629 47.328 2.653 63.816 ;
     RECT  2.473 18.768 2.677 25.704 ;
     RECT  2.629 12.528 2.716 12.552 ;
     RECT  2.291 30.96 2.732 30.984 ;
     RECT  2.588 13.968 2.797 14.52 ;
     RECT  1.825 15.744 2.797 16.296 ;
     RECT  2.045 35.856 2.797 35.88 ;
     RECT  2.38 36.864 2.797 37.032 ;
     RECT  2.617 17.568 2.833 17.592 ;
     RECT  2.677 18.768 2.833 25.752 ;
     RECT  2.797 35.856 2.837 37.032 ;
     RECT  2.572 38.16 2.837 38.184 ;
     RECT  2.545 32.544 2.867 32.568 ;
     RECT  2.797 13.968 2.869 16.296 ;
     RECT  2.833 17.568 2.869 25.752 ;
     RECT  2.291 27.648 2.869 29.064 ;
     RECT  2.045 33.84 2.869 34.776 ;
     RECT  2.653 43.536 2.976 63.816 ;
     RECT  2.837 36.48 3.089 37.032 ;
     RECT  2.976 63.264 3.089 63.816 ;
     RECT  2.405 39.456 3.116 42.312 ;
     RECT  2.976 43.536 3.116 62.04 ;
     RECT  2.869 27.216 3.161 29.064 ;
     RECT  2.869 13.968 3.212 25.752 ;
     RECT  3.212 13.968 3.229 25.896 ;
     RECT  3.116 39.456 3.299 62.04 ;
     RECT  2.869 32.928 3.301 34.776 ;
     RECT  3.301 32.928 3.305 35.352 ;
     RECT  3.161 27.312 3.308 29.064 ;
     RECT  2.732 30.384 3.308 30.984 ;
     RECT  3.308 27.312 3.341 30.984 ;
     RECT  3.299 50.64 3.395 62.04 ;
     RECT  3.089 63.744 3.413 63.816 ;
     RECT  3.305 32.976 3.449 35.352 ;
     RECT  3.341 28.176 3.481 30.984 ;
     RECT  3.299 39.456 3.491 49.56 ;
     RECT  3.395 54.672 3.491 57.576 ;
     RECT  3.491 41.04 3.593 49.56 ;
     RECT  3.229 13.632 3.629 25.896 ;
     RECT  3.449 32.976 3.629 33.288 ;
     RECT  3.413 63.744 3.629 63.768 ;
     RECT  3.449 34.752 3.836 35.352 ;
     RECT  3.089 36.48 3.836 36.888 ;
     RECT  3.481 28.176 3.841 31.752 ;
     RECT  3.491 39.456 3.841 40.056 ;
     RECT  3.395 58.656 3.949 62.04 ;
     RECT  3.593 41.04 3.953 48.264 ;
     RECT  3.629 14.16 3.971 25.896 ;
     RECT  3.836 34.752 3.989 36.888 ;
     RECT  3.629 32.976 3.997 33.048 ;
     RECT  3.989 34.992 4.025 36.888 ;
     RECT  3.445 37.92 4.057 37.944 ;
     RECT  3.841 39.312 4.057 40.056 ;
     RECT  3.971 14.208 4.201 25.896 ;
     RECT  3.953 41.04 4.205 46.2 ;
     RECT  4.025 35.568 4.213 36.888 ;
     RECT  4.057 37.92 4.213 40.056 ;
     RECT  3.949 58.656 4.273 62.76 ;
     RECT  3.395 50.64 4.3 53.592 ;
     RECT  3.593 49.488 4.453 49.56 ;
     RECT  4.3 50.64 4.453 52.536 ;
     RECT  4.273 58.656 4.453 63.288 ;
     RECT  3.491 54.672 4.492 57.24 ;
     RECT  3.997 33.024 4.499 33.048 ;
     RECT  4.213 35.568 4.525 40.056 ;
     RECT  4.205 41.04 4.525 43.128 ;
     RECT  4.525 35.568 4.54 43.128 ;
     RECT  4.453 58.368 4.547 63.288 ;
     RECT  4.3 53.52 4.549 53.592 ;
     RECT  4.492 54.672 4.549 57.096 ;
     RECT  4.549 53.52 4.595 57.096 ;
     RECT  4.595 55.824 4.601 57.096 ;
     RECT  4.547 58.464 4.601 63.288 ;
     RECT  3.841 28.176 4.633 31.992 ;
     RECT  4.633 27.984 4.636 31.992 ;
     RECT  3.953 47.568 4.669 48.264 ;
     RECT  4.636 27.984 4.741 30.552 ;
     RECT  4.345 12.528 4.748 12.552 ;
     RECT  4.201 14.208 4.813 26.376 ;
     RECT  4.669 47.568 4.844 48.456 ;
     RECT  4.453 49.488 4.844 52.536 ;
     RECT  4.636 31.632 4.988 31.992 ;
     RECT  4.601 61.728 5.093 63.288 ;
     RECT  4.54 35.568 5.173 36.12 ;
     RECT  5.093 61.728 5.281 63.336 ;
     RECT  5.281 61.728 5.353 63.432 ;
     RECT  4.813 14.208 5.381 26.808 ;
     RECT  4.741 27.936 5.381 30.552 ;
     RECT  5.381 14.208 5.461 30.552 ;
     RECT  4.54 37.584 5.509 43.128 ;
     RECT  4.205 44.16 5.509 46.2 ;
     RECT  4.601 58.464 5.509 60.696 ;
     RECT  5.173 35.376 5.533 36.12 ;
     RECT  5.509 37.584 5.533 46.2 ;
     RECT  5.461 14.112 5.605 30.552 ;
     RECT  4.988 31.632 5.605 32.76 ;
     RECT  5.509 58.128 5.641 60.696 ;
     RECT  5.353 61.728 5.641 63.768 ;
     RECT  4.748 11.664 5.648 12.552 ;
     RECT  5.605 14.112 5.648 33.384 ;
     RECT  5.533 35.376 5.648 46.2 ;
     RECT  4.844 47.568 5.648 52.536 ;
     RECT  4.595 53.52 5.648 54.744 ;
     RECT  4.601 56.352 5.648 57.096 ;
     RECT  5.641 58.128 5.648 63.768 ;
     RECT  5.648 0.528 5.752 63.768 ;
     RECT  5.752 0.798 5.84 63.768 ;
     RECT  5.84 0.798 5.944 64.002 ;
     RECT  5.944 12.528 6.005 22.248 ;
     RECT  6.005 12.528 6.083 22.056 ;
     RECT  5.944 56.352 6.083 63.624 ;
     RECT  6.083 14.016 6.131 22.056 ;
     RECT  6.083 56.352 6.185 58.056 ;
     RECT  6.083 12.528 6.227 12.984 ;
     RECT  5.944 39.12 6.257 55.08 ;
     RECT  5.944 23.28 6.275 31.512 ;
     RECT  6.185 56.64 6.412 58.056 ;
     RECT  6.412 56.88 6.509 58.056 ;
     RECT  6.257 39.12 6.689 46.824 ;
     RECT  6.275 23.28 6.748 30.84 ;
     RECT  6.748 23.28 6.755 30.744 ;
     RECT  6.509 56.88 6.755 57.864 ;
     RECT  6.227 12.96 6.761 12.984 ;
     RECT  6.131 14.352 6.761 22.056 ;
     RECT  6.257 47.856 6.797 55.08 ;
     RECT  5.944 35.136 6.803 37.848 ;
     RECT  6.083 59.088 6.851 63.624 ;
     RECT  6.761 14.448 6.869 22.056 ;
     RECT  6.869 17.76 7.045 22.056 ;
     RECT  6.755 23.28 7.045 30.552 ;
     RECT  7.045 17.76 7.049 30.552 ;
     RECT  6.869 14.448 7.085 16.776 ;
     RECT  6.689 39.12 7.085 44.472 ;
     RECT  6.803 35.904 7.117 37.848 ;
     RECT  7.049 17.808 7.157 30.552 ;
     RECT  6.797 47.856 7.187 47.88 ;
     RECT  5.944 32.496 7.189 33.384 ;
     RECT  7.148 34.656 7.189 34.68 ;
     RECT  7.157 17.808 7.229 30.456 ;
     RECT  6.689 45.84 7.285 46.824 ;
     RECT  7.229 18.096 7.345 30.168 ;
     RECT  6.797 54.576 7.369 55.08 ;
     RECT  7.285 45.84 7.372 47.256 ;
     RECT  7.085 14.448 7.427 16.68 ;
     RECT  7.345 24.096 7.517 30.168 ;
     RECT  6.851 59.088 7.549 63.48 ;
     RECT  7.517 24.096 7.564 25.272 ;
     RECT  7.388 11.952 7.585 11.976 ;
     RECT  7.564 24.096 7.619 25.224 ;
     RECT  7.189 32.496 7.619 34.68 ;
     RECT  7.117 35.904 7.717 38.04 ;
     RECT  7.085 39.12 7.717 39.192 ;
     RECT  7.372 45.84 7.717 47.208 ;
     RECT  7.619 32.496 7.729 33.624 ;
     RECT  6.755 56.88 7.741 57.672 ;
     RECT  7.717 35.904 7.765 39.192 ;
     RECT  7.585 11.952 7.801 12.456 ;
     RECT  7.369 54.576 7.801 55.704 ;
     RECT  7.765 34.896 7.841 39.192 ;
     RECT  6.797 48.96 7.861 53.592 ;
     RECT  7.801 54.576 7.861 56.52 ;
     RECT  7.861 48.96 7.907 56.52 ;
     RECT  7.729 32.016 7.909 33.624 ;
     RECT  7.619 24.24 7.913 25.224 ;
     RECT  7.741 57.552 7.957 57.672 ;
     RECT  7.549 58.656 7.957 63.48 ;
     RECT  7.907 50.592 8.003 56.52 ;
     RECT  7.801 11.952 8.021 12.6 ;
     RECT  8.003 50.592 8.051 56.328 ;
     RECT  7.841 34.896 8.093 38.424 ;
     RECT  7.085 40.176 8.149 44.472 ;
     RECT  8.021 12.432 8.3 12.6 ;
     RECT  7.517 26.304 8.3 30.168 ;
     RECT  7.909 31.728 8.3 33.624 ;
     RECT  8.3 12.432 8.339 13.464 ;
     RECT  7.717 45.696 8.377 47.208 ;
     RECT  8.339 13.44 8.387 13.464 ;
     RECT  7.427 14.448 8.437 15.192 ;
     RECT  7.345 18.096 8.453 23.112 ;
     RECT  7.427 16.272 8.485 16.68 ;
     RECT  8.149 40.176 8.485 44.616 ;
     RECT  7.957 57.552 8.485 63.48 ;
     RECT  8.485 57.552 8.489 63.528 ;
     RECT  8.453 18.144 8.525 23.112 ;
     RECT  8.485 39.504 8.531 44.616 ;
     RECT  8.377 45.696 8.531 47.256 ;
     RECT  8.051 54.48 8.531 56.328 ;
     RECT  8.489 57.552 8.531 59.64 ;
     RECT  8.489 60.672 8.531 63.528 ;
     RECT  8.531 54.48 8.533 54.792 ;
     RECT  8.051 50.592 8.579 53.448 ;
     RECT  8.437 14.448 8.593 15.288 ;
     RECT  8.485 16.272 8.593 17.112 ;
     RECT  8.533 54.48 8.597 54.696 ;
     RECT  7.913 24.816 8.629 25.224 ;
     RECT  8.3 26.304 8.629 33.624 ;
     RECT  8.629 24.816 8.633 33.624 ;
     RECT  7.907 48.96 8.633 49.608 ;
     RECT  8.633 24.816 8.723 31.368 ;
     RECT  8.533 47.856 8.732 47.88 ;
     RECT  8.633 48.96 8.732 49.56 ;
     RECT  8.531 60.864 8.737 63.528 ;
     RECT  8.531 43.824 8.773 44.616 ;
     RECT  8.531 45.696 8.773 46.824 ;
     RECT  8.093 34.896 8.777 38.184 ;
     RECT  8.525 18.192 8.809 23.112 ;
     RECT  8.773 43.824 8.867 46.824 ;
     RECT  8.723 24.816 8.881 24.936 ;
     RECT  8.777 34.896 8.908 37.032 ;
     RECT  8.723 26.256 8.963 31.368 ;
     RECT  8.531 56.064 8.981 56.328 ;
     RECT  8.531 39.504 8.989 42.792 ;
     RECT  8.809 18.192 9.061 23.304 ;
     RECT  8.881 24.624 9.061 24.936 ;
     RECT  8.963 26.256 9.107 31.176 ;
     RECT  8.989 39.216 9.107 42.792 ;
     RECT  8.633 32.448 9.109 33.624 ;
     RECT  8.531 57.552 9.109 58.728 ;
     RECT  8.908 36.336 9.137 37.032 ;
     RECT  8.777 38.016 9.137 38.184 ;
     RECT  8.593 14.448 9.155 17.112 ;
     RECT  9.061 18.192 9.155 24.936 ;
     RECT  9.107 39.744 9.173 42.792 ;
     RECT  9.173 40.032 9.217 42.792 ;
     RECT  9.109 32.448 9.245 34.776 ;
     RECT  8.867 43.824 9.245 44.472 ;
     RECT  9.245 32.448 9.251 33.624 ;
     RECT  9.245 43.824 9.251 43.848 ;
     RECT  9.109 57.504 9.281 58.728 ;
     RECT  9.157 11.952 9.299 12.264 ;
     RECT  9.299 11.952 9.425 11.976 ;
     RECT  9.251 33.072 9.497 33.624 ;
     RECT  9.217 40.944 9.497 42.792 ;
     RECT  9.281 57.84 9.533 58.728 ;
     RECT  8.579 50.688 9.565 53.448 ;
     RECT  8.597 54.576 9.565 54.696 ;
     RECT  9.497 33.072 9.569 33.096 ;
     RECT  9.155 18.192 9.596 22.824 ;
     RECT  8.732 47.856 9.596 49.56 ;
     RECT  9.565 50.688 9.596 54.696 ;
     RECT  9.497 42.336 9.637 42.792 ;
     RECT  8.867 45.552 9.637 46.824 ;
     RECT  9.596 47.856 9.637 54.696 ;
     RECT  8.981 56.064 9.637 56.472 ;
     RECT  8.737 60.864 9.673 64.152 ;
     RECT  9.637 45.552 9.692 56.472 ;
     RECT  9.533 57.888 9.733 58.728 ;
     RECT  9.673 60.096 9.733 64.152 ;
     RECT  9.245 34.752 9.757 34.776 ;
     RECT  9.637 42.336 9.785 43.512 ;
     RECT  9.155 14.448 9.788 17.016 ;
     RECT  9.692 45.552 9.821 56.52 ;
     RECT  9.733 57.888 9.821 64.152 ;
     RECT  9.785 42.768 9.827 43.512 ;
     RECT  9.301 12.96 9.884 13.176 ;
     RECT  9.788 14.208 9.884 17.016 ;
     RECT  9.821 59.952 9.916 64.152 ;
     RECT  9.827 42.768 10.073 43.08 ;
     RECT  9.884 12.96 10.124 17.016 ;
     RECT  9.596 18.048 10.124 22.824 ;
     RECT  9.137 38.16 10.213 38.184 ;
     RECT  9.497 40.944 10.213 41.16 ;
     RECT  9.155 23.952 10.249 24.936 ;
     RECT  9.107 26.304 10.249 31.176 ;
     RECT  10.213 38.16 10.261 38.952 ;
     RECT  10.124 12.96 10.405 22.824 ;
     RECT  10.249 23.952 10.405 31.176 ;
     RECT  10.213 40.56 10.405 41.16 ;
     RECT  9.637 11.664 10.412 11.688 ;
     RECT  10.405 12.96 10.412 31.176 ;
     RECT  10.412 11.664 10.501 31.176 ;
     RECT  10.261 37.68 10.501 38.952 ;
     RECT  10.405 40.176 10.501 41.16 ;
     RECT  10.249 9.744 10.537 9.768 ;
     RECT  10.501 37.68 10.537 41.16 ;
     RECT  9.821 48.96 10.537 56.52 ;
     RECT  9.821 57.888 10.537 58.632 ;
     RECT  10.537 9.648 10.604 9.768 ;
     RECT  10.501 11.664 10.789 31.368 ;
     RECT  10.033 35.328 10.789 35.352 ;
     RECT  10.405 33.024 10.825 33.048 ;
     RECT  10.537 48.96 10.825 58.632 ;
     RECT  9.916 59.952 10.825 60.552 ;
     RECT  10.604 9.648 10.837 10.344 ;
     RECT  10.789 11.664 10.837 31.656 ;
     RECT  9.821 45.552 10.837 47.736 ;
     RECT  10.837 9.648 10.841 31.656 ;
     RECT  10.841 9.648 10.861 31.704 ;
     RECT  10.825 32.736 10.861 33.048 ;
     RECT  10.537 37.68 10.861 41.208 ;
     RECT  10.837 45.552 10.861 47.928 ;
     RECT  10.825 48.96 10.861 60.552 ;
     RECT  10.861 9.648 10.933 33.048 ;
     RECT  10.933 9.36 11.048 33.048 ;
     RECT  10.789 34.704 11.048 35.352 ;
     RECT  9.137 36.336 11.048 36.36 ;
     RECT  10.861 37.44 11.048 41.208 ;
     RECT  10.073 43.056 11.048 43.08 ;
     RECT  10.861 45.552 11.048 60.552 ;
     RECT  9.916 61.584 11.048 64.152 ;
     RECT  11.048 0.528 11.152 64.152 ;
     RECT  11.152 0.798 11.344 64.152 ;
     RECT  11.344 45.552 11.441 47.736 ;
     RECT  11.344 18.192 11.459 38.952 ;
     RECT  11.344 55.776 11.513 56.472 ;
     RECT  11.344 40.848 11.555 44.328 ;
     RECT  11.459 18.192 11.585 32.04 ;
     RECT  11.344 49.056 11.651 54.552 ;
     RECT  11.585 18.96 11.74 32.04 ;
     RECT  11.651 49.104 11.765 49.896 ;
     RECT  11.459 33.312 11.788 38.952 ;
     RECT  11.344 12.48 11.837 16.68 ;
     RECT  11.74 19.008 11.837 32.04 ;
     RECT  11.441 45.552 11.837 47.64 ;
     RECT  11.344 9.072 11.945 11.496 ;
     RECT  11.788 33.84 12.124 38.952 ;
     RECT  11.945 9.072 12.275 9.48 ;
     RECT  11.555 44.304 12.275 44.328 ;
     RECT  11.837 13.92 12.337 16.68 ;
     RECT  11.837 45.552 12.337 47.256 ;
     RECT  12.337 13.92 12.409 17.112 ;
     RECT  11.945 10.56 12.449 11.496 ;
     RECT  11.651 51.216 12.553 54.552 ;
     RECT  11.344 57.552 12.563 64.152 ;
     RECT  12.553 51.216 12.572 54.648 ;
     RECT  12.409 13.92 12.589 17.208 ;
     RECT  12.572 51.216 12.613 54.792 ;
     RECT  11.513 56.064 12.613 56.472 ;
     RECT  12.613 51.216 12.62 56.472 ;
     RECT  12.563 57.552 12.62 58.152 ;
     RECT  11.555 40.848 12.661 43.128 ;
     RECT  12.62 51.216 12.665 58.152 ;
     RECT  11.837 19.104 12.755 32.04 ;
     RECT  11.765 49.152 12.764 49.896 ;
     RECT  12.124 38.736 12.769 38.952 ;
     RECT  12.337 44.592 12.805 47.256 ;
     RECT  12.661 40.848 12.809 43.32 ;
     RECT  12.665 51.216 12.809 57.864 ;
     RECT  12.764 48.768 12.85 49.896 ;
     RECT  11.837 12.48 12.877 12.744 ;
     RECT  12.589 13.92 12.877 17.256 ;
     RECT  12.85 48.672 12.908 49.896 ;
     RECT  12.809 51.216 12.908 53.592 ;
     RECT  12.755 23.376 12.956 32.04 ;
     RECT  12.124 33.84 12.956 37.464 ;
     RECT  12.755 19.104 12.961 22.344 ;
     RECT  12.449 10.56 12.985 10.92 ;
     RECT  12.877 12.48 13.013 17.256 ;
     RECT  12.809 42.288 13.052 43.32 ;
     RECT  13.013 12.48 13.091 17.304 ;
     RECT  12.809 40.848 13.091 41.064 ;
     RECT  13.091 12.48 13.093 14.664 ;
     RECT  12.956 23.376 13.093 37.464 ;
     RECT  13.093 23.376 13.165 37.608 ;
     RECT  12.769 38.736 13.165 39.576 ;
     RECT  13.093 11.952 13.205 14.664 ;
     RECT  12.961 19.104 13.213 22.2 ;
     RECT  13.196 7.392 13.237 7.416 ;
     RECT  12.275 9.072 13.273 9.096 ;
     RECT  13.237 7.392 13.309 7.992 ;
     RECT  12.985 10.512 13.309 10.92 ;
     RECT  13.165 23.376 13.333 39.576 ;
     RECT  12.908 48.672 13.388 53.592 ;
     RECT  13.333 23.376 13.42 39.672 ;
     RECT  13.091 15.744 13.525 17.304 ;
     RECT  13.052 42.288 13.561 43.608 ;
     RECT  12.805 44.592 13.561 47.304 ;
     RECT  13.309 7.2 13.628 7.992 ;
     RECT  13.309 10.416 13.633 10.92 ;
     RECT  12.809 54.624 13.633 57.864 ;
     RECT  13.273 9.072 13.669 9.24 ;
     RECT  13.561 42.288 13.669 47.304 ;
     RECT  13.388 48.624 13.669 53.592 ;
     RECT  13.42 23.376 13.673 39.384 ;
     RECT  13.628 6.816 13.741 7.992 ;
     RECT  13.669 9.072 13.741 9.288 ;
     RECT  13.669 42.288 13.756 53.592 ;
     RECT  13.756 42.288 13.82 47.208 ;
     RECT  13.091 41.04 13.849 41.064 ;
     RECT  13.82 42.24 13.849 47.208 ;
     RECT  13.633 54.624 13.889 58.2 ;
     RECT  13.741 6.816 13.921 9.288 ;
     RECT  13.633 10.32 13.921 10.92 ;
     RECT  13.673 34.08 13.925 39.384 ;
     RECT  13.889 54.624 14.033 55.272 ;
     RECT  13.921 6.816 14.173 10.92 ;
     RECT  13.205 11.952 14.173 14.52 ;
     RECT  13.889 56.256 14.173 58.2 ;
     RECT  14.173 6.816 14.197 14.52 ;
     RECT  13.756 48.96 14.204 53.592 ;
     RECT  14.033 54.624 14.204 55.224 ;
     RECT  14.197 6.192 14.237 14.52 ;
     RECT  13.525 15.744 14.237 17.448 ;
     RECT  13.673 23.376 14.237 33.048 ;
     RECT  14.173 56.256 14.257 58.392 ;
     RECT  14.204 48.96 14.291 55.224 ;
     RECT  13.213 19.104 14.317 22.008 ;
     RECT  14.237 23.04 14.317 33.048 ;
     RECT  13.849 41.04 14.492 47.208 ;
     RECT  14.291 48.96 14.501 53.352 ;
     RECT  14.291 54.624 14.573 55.224 ;
     RECT  14.573 54.72 14.579 55.224 ;
     RECT  14.237 6.192 14.581 17.448 ;
     RECT  13.489 5.088 14.588 5.112 ;
     RECT  13.925 36.288 14.605 39.384 ;
     RECT  14.492 40.368 14.605 47.208 ;
     RECT  14.588 4.224 14.675 5.112 ;
     RECT  13.925 34.08 14.689 35.304 ;
     RECT  14.605 36.288 14.716 47.208 ;
     RECT  14.716 41.808 14.725 47.208 ;
     RECT  14.725 41.808 14.732 47.832 ;
     RECT  14.501 48.96 14.732 53.256 ;
     RECT  14.732 41.808 14.819 53.256 ;
     RECT  14.569 2.784 14.821 2.808 ;
     RECT  14.675 5.088 14.821 5.112 ;
     RECT  14.581 6.192 14.821 17.544 ;
     RECT  14.821 5.088 14.905 17.544 ;
     RECT  14.821 2.496 14.908 2.808 ;
     RECT  14.905 5.088 14.908 8.856 ;
     RECT  12.563 59.568 14.965 64.152 ;
     RECT  14.579 54.768 15.001 55.224 ;
     RECT  14.257 56.256 15.001 58.296 ;
     RECT  14.905 9.888 15.073 17.544 ;
     RECT  15.001 54.768 15.077 58.296 ;
     RECT  15.073 9.888 15.109 17.88 ;
     RECT  15.109 9.888 15.116 17.976 ;
     RECT  14.317 19.104 15.116 33.048 ;
     RECT  14.689 34.608 15.157 35.304 ;
     RECT  14.716 36.288 15.157 40.344 ;
     RECT  14.819 41.808 15.185 47.88 ;
     RECT  14.908 6.48 15.203 8.856 ;
     RECT  14.908 2.784 15.205 2.808 ;
     RECT  14.965 59.28 15.217 64.152 ;
     RECT  15.077 55.968 15.244 58.296 ;
     RECT  15.244 56.016 15.289 58.296 ;
     RECT  15.217 59.28 15.289 64.68 ;
     RECT  15.116 9.888 15.293 33.048 ;
     RECT  15.293 17.856 15.389 33.048 ;
     RECT  15.293 9.888 15.437 16.68 ;
     RECT  14.819 48.96 15.437 53.256 ;
     RECT  15.437 9.888 15.443 11.688 ;
     RECT  15.443 10.32 15.473 11.688 ;
     RECT  15.077 54.768 15.541 54.984 ;
     RECT  15.157 34.608 15.685 40.344 ;
     RECT  15.205 2.784 15.829 3.96 ;
     RECT  14.908 5.088 15.829 5.112 ;
     RECT  15.437 50.784 15.829 53.256 ;
     RECT  15.829 50.784 15.865 53.592 ;
     RECT  15.541 54.624 15.865 54.984 ;
     RECT  15.685 34.512 16.124 40.344 ;
     RECT  16.009 1.68 16.189 1.704 ;
     RECT  15.185 41.808 16.268 47.832 ;
     RECT  15.437 48.96 16.268 49.512 ;
     RECT  16.268 41.808 16.309 49.512 ;
     RECT  15.437 12.768 16.333 16.68 ;
     RECT  15.389 17.856 16.333 33.336 ;
     RECT  16.333 12.768 16.441 33.336 ;
     RECT  16.189 0.96 16.448 1.704 ;
     RECT  15.829 2.784 16.448 5.112 ;
     RECT  15.203 6.672 16.448 8.856 ;
     RECT  15.473 10.32 16.448 11.256 ;
     RECT  16.441 12.48 16.448 33.336 ;
     RECT  16.124 34.512 16.448 40.536 ;
     RECT  16.309 41.76 16.448 49.512 ;
     RECT  15.865 50.784 16.448 54.984 ;
     RECT  15.289 56.016 16.448 64.68 ;
     RECT  16.448 0.528 16.552 64.68 ;
     RECT  16.552 0.798 16.744 64.68 ;
     RECT  16.744 10.896 16.913 10.92 ;
     RECT  16.744 0.96 17.123 5.544 ;
     RECT  16.744 12.48 17.129 32.52 ;
     RECT  16.744 34.368 17.237 64.68 ;
     RECT  17.237 35.712 17.267 64.68 ;
     RECT  17.129 18.144 17.345 32.52 ;
     RECT  17.123 0.96 17.363 3.96 ;
     RECT  17.267 41.136 17.453 64.68 ;
     RECT  16.744 6.816 17.525 9.672 ;
     RECT  17.525 7.2 17.597 9.672 ;
     RECT  17.363 2.928 17.603 3.96 ;
     RECT  17.453 41.136 17.603 49.56 ;
     RECT  17.363 0.96 17.633 1.944 ;
     RECT  17.603 3.312 17.669 3.96 ;
     RECT  17.597 7.344 17.669 9.672 ;
     RECT  17.345 18.192 17.777 32.52 ;
     RECT  17.633 1.056 17.836 1.944 ;
     RECT  17.804 11.376 17.845 11.4 ;
     RECT  17.129 12.48 17.845 17.064 ;
     RECT  17.237 34.368 17.881 34.488 ;
     RECT  17.777 18.528 17.885 32.52 ;
     RECT  17.881 33.888 17.917 34.488 ;
     RECT  17.123 5.136 17.948 5.544 ;
     RECT  17.669 8.496 17.948 9.672 ;
     RECT  17.948 5.136 18.029 6.216 ;
     RECT  18.029 6.192 18.035 6.216 ;
     RECT  17.669 3.312 18.281 3.624 ;
     RECT  17.917 33.504 18.284 34.488 ;
     RECT  17.267 35.712 18.284 39.576 ;
     RECT  17.836 1.392 18.317 1.944 ;
     RECT  17.885 18.72 18.349 32.52 ;
     RECT  18.284 33.504 18.349 39.576 ;
     RECT  17.948 8.496 18.385 10.056 ;
     RECT  18.349 18.72 18.385 39.576 ;
     RECT  17.603 41.136 18.385 44.184 ;
     RECT  17.603 45.264 18.421 49.56 ;
     RECT  17.453 50.592 18.421 64.68 ;
     RECT  18.385 18.72 18.425 44.184 ;
     RECT  18.385 8.496 18.457 10.296 ;
     RECT  17.845 11.376 18.457 17.064 ;
     RECT  18.421 45.264 18.604 64.68 ;
     RECT  18.604 45.264 18.641 54.12 ;
     RECT  17.669 7.344 18.661 7.368 ;
     RECT  18.457 8.496 18.661 17.064 ;
     RECT  18.029 5.136 18.677 5.16 ;
     RECT  18.317 1.92 18.709 1.944 ;
     RECT  18.661 7.344 18.716 17.064 ;
     RECT  18.716 6.816 18.745 17.064 ;
     RECT  18.641 45.264 18.785 54.072 ;
     RECT  18.425 19.056 18.803 44.184 ;
     RECT  18.709 1.92 18.817 2.088 ;
     RECT  18.745 6.816 18.908 17.592 ;
     RECT  18.803 34.512 19.181 44.184 ;
     RECT  19.181 34.56 19.253 44.184 ;
     RECT  18.817 1.92 19.321 3.048 ;
     RECT  19.004 4.512 19.321 4.536 ;
     RECT  18.803 19.056 19.325 33.432 ;
     RECT  18.908 6.816 19.379 17.976 ;
     RECT  19.379 6.816 19.393 13.464 ;
     RECT  19.325 19.056 19.469 33.384 ;
     RECT  19.379 14.448 19.537 17.976 ;
     RECT  19.469 19.056 19.537 32.52 ;
     RECT  19.253 34.752 19.537 44.184 ;
     RECT  18.785 45.264 19.537 50.04 ;
     RECT  19.393 6.336 19.541 13.464 ;
     RECT  19.321 1.92 19.753 4.536 ;
     RECT  19.753 1.68 19.772 4.536 ;
     RECT  18.785 51.072 19.789 54.072 ;
     RECT  19.537 34.752 19.813 50.04 ;
     RECT  19.789 51.072 19.813 54.168 ;
     RECT  19.772 1.296 19.859 4.536 ;
     RECT  19.813 34.752 19.861 54.168 ;
     RECT  18.604 55.152 19.861 64.68 ;
     RECT  19.859 1.68 20.003 4.536 ;
     RECT  20.003 2.064 20.037 4.536 ;
     RECT  20.037 2.064 20.045 2.856 ;
     RECT  20.037 4.512 20.339 4.536 ;
     RECT  19.541 6.72 20.429 13.464 ;
     RECT  19.537 14.448 20.429 32.52 ;
     RECT  20.365 33.6 20.437 33.624 ;
     RECT  20.396 4.56 20.473 5.112 ;
     RECT  20.429 6.72 20.533 32.52 ;
     RECT  20.437 33.552 20.533 33.624 ;
     RECT  19.861 34.752 20.533 64.68 ;
     RECT  20.045 2.496 20.549 2.856 ;
     RECT  20.533 6.72 20.797 64.68 ;
     RECT  20.549 2.496 21.553 2.616 ;
     RECT  20.473 4.56 21.553 5.208 ;
     RECT  21.553 4.464 21.625 5.208 ;
     RECT  21.625 4.464 21.633 5.544 ;
     RECT  20.797 6.624 21.633 64.68 ;
     RECT  21.553 2.496 21.692 2.76 ;
     RECT  21.633 4.464 21.692 64.68 ;
     RECT  21.481 1.392 21.848 1.416 ;
     RECT  21.692 2.496 21.848 3.288 ;
     RECT  21.692 4.368 21.848 64.68 ;
     RECT  21.848 0.528 21.952 64.68 ;
     RECT  21.952 0.798 22.144 64.68 ;
     RECT  22.144 6.72 22.259 40.68 ;
     RECT  22.144 2.496 22.313 5.64 ;
     RECT  22.144 44.976 22.924 64.68 ;
     RECT  22.259 12.864 23.02 40.68 ;
     RECT  22.313 2.784 23.068 5.64 ;
     RECT  22.144 1.008 23.116 1.032 ;
     RECT  23.068 2.784 23.213 3.768 ;
     RECT  22.144 41.76 23.245 43.896 ;
     RECT  22.924 44.976 23.245 59.064 ;
     RECT  23.02 19.056 23.276 40.68 ;
     RECT  23.245 41.76 23.276 59.064 ;
     RECT  23.068 4.944 23.353 5.64 ;
     RECT  22.259 6.72 23.353 11.88 ;
     RECT  23.213 3.312 23.411 3.768 ;
     RECT  23.411 3.696 23.452 3.768 ;
     RECT  23.353 4.944 23.461 11.88 ;
     RECT  23.02 12.864 23.461 17.736 ;
     RECT  23.276 19.056 23.537 59.064 ;
     RECT  23.461 4.944 23.603 17.736 ;
     RECT  23.537 34.656 23.645 59.064 ;
     RECT  23.645 44.976 23.941 59.064 ;
     RECT  23.645 34.656 23.987 43.896 ;
     RECT  22.924 60.288 23.989 64.68 ;
     RECT  23.965 2.16 24.073 2.184 ;
     RECT  23.941 44.976 24.133 59.256 ;
     RECT  23.989 60.24 24.133 64.68 ;
     RECT  23.603 6.048 24.14 17.736 ;
     RECT  23.537 19.056 24.14 33.528 ;
     RECT  24.073 1.824 24.277 2.184 ;
     RECT  24.14 6.048 24.365 33.528 ;
     RECT  24.277 1.776 24.517 2.184 ;
     RECT  23.452 3.744 24.517 3.768 ;
     RECT  23.603 4.944 24.517 5.064 ;
     RECT  24.133 44.976 24.604 64.68 ;
     RECT  23.987 38.448 24.62 43.896 ;
     RECT  24.604 44.976 24.62 53.4 ;
     RECT  24.517 3.312 24.653 5.064 ;
     RECT  24.365 10.368 24.721 33.528 ;
     RECT  23.987 34.656 24.721 37.08 ;
     RECT  24.517 1.2 24.757 2.184 ;
     RECT  24.365 6.048 24.793 9.384 ;
     RECT  24.793 5.136 24.877 9.384 ;
     RECT  24.62 38.448 24.977 53.4 ;
     RECT  24.721 10.368 25.009 37.08 ;
     RECT  24.757 0.864 25.091 2.184 ;
     RECT  24.604 54.384 25.117 64.68 ;
     RECT  25.117 54.384 25.265 64.728 ;
     RECT  25.265 55.968 25.276 64.728 ;
     RECT  25.276 56.016 25.523 64.728 ;
     RECT  25.091 1.536 25.585 2.184 ;
     RECT  24.653 3.312 25.585 4.104 ;
     RECT  25.265 54.384 25.667 54.888 ;
     RECT  25.585 1.536 25.669 4.104 ;
     RECT  24.877 5.136 25.669 5.16 ;
     RECT  25.009 10.368 25.669 37.464 ;
     RECT  24.977 38.448 25.669 53.352 ;
     RECT  25.669 10.368 25.763 53.352 ;
     RECT  25.763 12.768 25.769 37.656 ;
     RECT  25.769 32.4 25.841 33.144 ;
     RECT  25.669 1.536 25.877 5.16 ;
     RECT  25.877 2.208 25.909 5.16 ;
     RECT  24.877 6.576 25.909 9.384 ;
     RECT  25.763 10.368 25.909 11.784 ;
     RECT  25.763 38.64 25.913 53.352 ;
     RECT  25.769 34.176 26.057 37.656 ;
     RECT  25.913 52.08 26.377 53.352 ;
     RECT  25.667 54.384 26.377 54.696 ;
     RECT  26.377 52.08 26.677 54.696 ;
     RECT  25.523 56.064 26.677 64.728 ;
     RECT  25.909 2.208 26.809 11.784 ;
     RECT  25.769 12.768 26.809 31.368 ;
     RECT  26.809 2.208 26.837 31.368 ;
     RECT  25.841 32.448 26.837 33.144 ;
     RECT  26.057 34.224 26.917 37.656 ;
     RECT  25.913 38.64 26.917 50.76 ;
     RECT  26.677 52.08 26.953 64.728 ;
     RECT  26.245 0.864 27.025 0.888 ;
     RECT  26.917 34.224 27.025 50.76 ;
     RECT  26.953 51.936 27.025 64.728 ;
     RECT  26.837 2.208 27.205 33.144 ;
     RECT  27.025 34.224 27.205 64.728 ;
     RECT  27.025 0.864 27.248 1.224 ;
     RECT  27.205 2.208 27.248 64.728 ;
     RECT  27.248 0.528 27.352 64.728 ;
     RECT  27.352 0.798 27.544 64.728 ;
     RECT  27.544 2.688 27.683 64.728 ;
     RECT  27.683 2.688 27.857 47.352 ;
     RECT  27.857 2.688 28.067 30.984 ;
     RECT  28.067 2.688 28.145 3.144 ;
     RECT  27.683 48.576 28.649 64.728 ;
     RECT  28.649 48.576 28.693 54.84 ;
     RECT  28.693 48.48 28.793 54.84 ;
     RECT  28.145 2.688 28.897 2.856 ;
     RECT  28.649 55.824 28.937 64.728 ;
     RECT  28.067 4.128 29.041 30.984 ;
     RECT  27.857 31.968 29.041 47.352 ;
     RECT  28.793 48.48 29.041 54.744 ;
     RECT  28.897 2.64 29.077 2.856 ;
     RECT  29.041 3.84 29.077 30.984 ;
     RECT  29.041 31.968 29.077 54.744 ;
     RECT  29.077 3.84 29.117 54.744 ;
     RECT  29.077 2.256 29.185 2.856 ;
     RECT  29.117 3.84 29.185 36.36 ;
     RECT  28.937 60.192 29.267 64.728 ;
     RECT  28.937 55.824 29.411 59.16 ;
     RECT  29.185 2.256 29.549 36.36 ;
     RECT  29.549 2.256 29.729 17.736 ;
     RECT  29.117 37.392 29.797 54.744 ;
     RECT  29.411 55.824 29.797 59.064 ;
     RECT  29.729 4.56 29.837 17.736 ;
     RECT  29.797 37.392 30.125 59.064 ;
     RECT  29.549 18.768 30.181 36.36 ;
     RECT  30.125 37.392 30.181 40.44 ;
     RECT  30.125 41.856 30.373 59.064 ;
     RECT  29.267 60.336 30.373 64.728 ;
     RECT  30.181 18.768 30.449 40.44 ;
     RECT  29.729 2.256 30.481 3.432 ;
     RECT  29.837 4.608 30.613 17.736 ;
     RECT  30.449 18.768 30.613 38.232 ;
     RECT  30.613 4.608 30.629 38.232 ;
     RECT  30.481 1.728 30.901 3.432 ;
     RECT  30.629 4.608 30.901 37.56 ;
     RECT  30.901 1.728 30.989 37.56 ;
     RECT  30.989 4.704 30.995 37.56 ;
     RECT  30.989 2.352 31.084 3.624 ;
     RECT  30.449 39.216 31.093 40.44 ;
     RECT  30.373 41.856 31.093 64.728 ;
     RECT  31.561 0.192 31.645 0.216 ;
     RECT  30.995 4.944 31.66 37.56 ;
     RECT  31.66 5.376 31.909 37.56 ;
     RECT  31.093 39.216 31.909 64.728 ;
     RECT  31.084 2.352 32.053 3.432 ;
     RECT  32.053 2.352 32.533 4.296 ;
     RECT  32.533 1.68 32.648 4.296 ;
     RECT  31.909 5.376 32.648 64.728 ;
     RECT  32.648 0.528 32.752 64.728 ;
     RECT  32.752 0.798 32.944 64.728 ;
     RECT  32.944 1.68 33.635 64.728 ;
     RECT  33.635 1.68 33.653 51.432 ;
     RECT  33.653 3.84 33.869 51.432 ;
     RECT  33.869 6.144 34.019 51.432 ;
     RECT  33.653 1.68 34.333 2.856 ;
     RECT  34.019 39.072 34.499 51.432 ;
     RECT  34.499 39.6 34.693 51.432 ;
     RECT  34.333 1.104 34.741 2.856 ;
     RECT  33.869 3.84 34.741 4.44 ;
     RECT  34.693 39.6 34.801 51.672 ;
     RECT  33.635 52.848 34.801 64.728 ;
     RECT  34.741 1.104 34.805 4.44 ;
     RECT  34.805 1.104 34.877 3.96 ;
     RECT  34.019 6.144 34.981 38.04 ;
     RECT  34.981 5.712 35.061 38.04 ;
     RECT  35.061 5.712 35.653 38.232 ;
     RECT  34.801 39.6 35.653 51.768 ;
     RECT  35.653 5.712 35.773 51.768 ;
     RECT  34.801 52.752 35.773 64.728 ;
     RECT  34.877 1.104 35.809 3.432 ;
     RECT  35.809 0.72 35.893 3.432 ;
     RECT  35.773 4.896 35.957 64.728 ;
     RECT  35.893 1.056 35.996 3.432 ;
     RECT  35.996 1.056 36.236 3.72 ;
     RECT  35.957 4.896 36.236 5.208 ;
     RECT  35.957 6.288 36.353 64.728 ;
     RECT  36.353 6.288 36.425 38.808 ;
     RECT  36.353 40.032 36.533 64.728 ;
     RECT  36.236 1.056 36.961 5.208 ;
     RECT  36.425 6.288 36.961 17.496 ;
     RECT  36.533 40.032 36.965 64.488 ;
     RECT  36.425 18.48 37.573 38.808 ;
     RECT  36.965 40.032 37.573 64.44 ;
     RECT  36.961 1.056 37.621 17.496 ;
     RECT  37.573 18.48 37.621 64.44 ;
     RECT  37.621 1.056 38.048 64.44 ;
     RECT  38.048 0.528 38.152 64.44 ;
     RECT  38.152 0.798 38.197 64.44 ;
     RECT  38.197 0.798 38.344 64.488 ;
     RECT  38.344 2.016 38.513 37.992 ;
     RECT  38.344 39.216 38.513 47.352 ;
     RECT  38.344 51.168 38.765 64.488 ;
     RECT  38.513 39.648 39.011 47.352 ;
     RECT  38.765 56.64 39.013 64.488 ;
     RECT  39.011 39.648 39.017 47.256 ;
     RECT  38.513 2.16 39.337 37.992 ;
     RECT  38.344 48.528 39.373 50.136 ;
     RECT  39.017 39.648 39.493 47.208 ;
     RECT  39.337 2.16 39.697 38.28 ;
     RECT  39.013 56.64 39.733 64.584 ;
     RECT  39.373 48.528 39.769 50.184 ;
     RECT  38.765 51.168 39.769 55.08 ;
     RECT  39.769 48.528 39.877 55.08 ;
     RECT  39.733 56.064 39.877 64.584 ;
     RECT  39.697 2.16 39.881 38.568 ;
     RECT  39.881 2.208 40.061 38.568 ;
     RECT  39.493 39.552 40.201 47.208 ;
     RECT  40.201 39.552 40.213 47.352 ;
     RECT  39.877 48.528 40.213 64.584 ;
     RECT  40.061 5.136 40.381 38.568 ;
     RECT  40.213 39.552 40.381 64.584 ;
     RECT  40.061 2.208 41.029 3.96 ;
     RECT  40.381 5.136 41.029 64.584 ;
     RECT  41.029 2.208 41.245 64.584 ;
     RECT  41.785 0.816 42.179 0.84 ;
     RECT  41.245 1.968 42.572 64.584 ;
     RECT  42.572 1.824 42.805 64.584 ;
     RECT  42.805 1.056 43.225 64.584 ;
     RECT  43.225 1.056 43.333 64.68 ;
     RECT  43.333 0.864 43.448 64.68 ;
     RECT  43.448 0.528 43.552 64.68 ;
     RECT  43.552 0.798 43.693 64.68 ;
     RECT  43.693 0.798 43.744 64.728 ;
     RECT  43.744 0.864 43.805 64.728 ;
     RECT  43.805 1.104 43.913 64.728 ;
     RECT  43.913 1.104 43.955 54.984 ;
     RECT  43.955 1.44 44.003 54.984 ;
     RECT  44.003 52.56 44.051 54.984 ;
     RECT  44.003 1.44 44.489 51.48 ;
     RECT  44.489 1.44 44.849 3.72 ;
     RECT  44.051 52.56 45.013 54.936 ;
     RECT  44.849 1.68 45.101 3.72 ;
     RECT  45.101 1.68 45.34 3.672 ;
     RECT  45.013 52.512 45.529 54.936 ;
     RECT  43.913 56.064 45.529 64.728 ;
     RECT  44.489 4.752 45.565 51.48 ;
     RECT  45.529 52.512 45.565 64.728 ;
     RECT  45.34 1.68 45.676 1.704 ;
     RECT  45.565 4.752 46.109 64.728 ;
     RECT  46.109 7.728 46.181 64.728 ;
     RECT  46.181 45.6 46.289 64.728 ;
     RECT  45.34 2.784 46.309 3.672 ;
     RECT  46.109 4.752 46.309 6.696 ;
     RECT  46.309 2.784 46.397 6.696 ;
     RECT  46.397 3.312 46.721 6.696 ;
     RECT  46.289 64.656 46.937 64.728 ;
     RECT  46.181 7.728 47.317 44.424 ;
     RECT  46.289 45.6 47.317 63.576 ;
     RECT  46.721 4.752 47.473 6.696 ;
     RECT  47.317 7.728 47.473 63.576 ;
     RECT  47.473 4.752 47.804 63.576 ;
     RECT  46.721 3.312 47.893 3.48 ;
     RECT  47.804 4.656 47.893 63.576 ;
     RECT  47.893 3.312 48.689 63.576 ;
     RECT  48.689 3.312 48.848 63.72 ;
     RECT  48.848 0.528 48.952 63.732 ;
     RECT  48.952 0.798 49.04 63.732 ;
     RECT  46.937 64.704 49.04 64.728 ;
     RECT  49.04 0.798 49.144 64.728 ;
     RECT  49.144 64.704 49.421 64.728 ;
     RECT  49.144 6.384 50.147 63.72 ;
     RECT  49.144 3.696 50.188 5.304 ;
     RECT  50.147 6.384 50.285 51.864 ;
     RECT  50.188 4.416 50.348 5.304 ;
     RECT  50.285 6.384 50.348 50.568 ;
     RECT  50.348 4.416 50.573 50.568 ;
     RECT  50.573 4.704 50.681 50.568 ;
     RECT  50.681 4.704 50.753 50.232 ;
     RECT  50.147 52.848 50.825 63.72 ;
     RECT  50.753 4.704 50.86 50.04 ;
     RECT  50.285 51.648 51.157 51.864 ;
     RECT  50.825 52.848 51.157 63.672 ;
     RECT  51.157 51.648 51.473 63.672 ;
     RECT  50.86 4.704 51.865 4.728 ;
     RECT  50.86 6.384 51.901 50.04 ;
     RECT  51.865 4.704 51.925 5.304 ;
     RECT  51.925 4.704 51.941 5.352 ;
     RECT  51.941 4.752 51.973 5.352 ;
     RECT  51.901 6.336 51.973 50.04 ;
     RECT  51.473 55.968 51.973 63.672 ;
     RECT  51.973 4.752 52.261 50.04 ;
     RECT  52.261 4.752 52.316 50.184 ;
     RECT  52.316 4.752 52.396 50.424 ;
     RECT  52.396 5.28 52.549 50.424 ;
     RECT  51.473 51.648 52.549 54.984 ;
     RECT  52.549 5.28 52.661 54.984 ;
     RECT  51.973 55.968 53.029 63.72 ;
     RECT  52.661 5.664 53.057 54.984 ;
     RECT  53.029 55.968 53.116 63.768 ;
     RECT  53.057 5.712 53.125 54.984 ;
     RECT  53.116 55.968 53.125 63.72 ;
     RECT  53.125 5.712 53.129 63.72 ;
     RECT  53.129 55.584 53.273 63.72 ;
     RECT  53.129 5.712 54.097 54.408 ;
     RECT  53.273 55.584 54.097 63.624 ;
     RECT  54.097 5.712 54.248 63.624 ;
     RECT  54.248 0.528 54.352 63.732 ;
     RECT  54.352 0.798 54.44 63.732 ;
     RECT  54.44 0.798 54.544 64.002 ;
     RECT  54.544 5.664 54.929 63.672 ;
     RECT  54.929 5.76 55.577 63.672 ;
     RECT  55.577 5.76 56.051 53.352 ;
     RECT  56.051 5.76 56.636 53.112 ;
     RECT  56.636 5.616 56.657 53.112 ;
     RECT  55.577 54.384 56.732 63.672 ;
     RECT  56.657 5.616 56.765 48.984 ;
     RECT  56.732 54.384 56.819 63.768 ;
     RECT  56.819 54.384 57.017 63.72 ;
     RECT  56.657 50.4 57.085 53.112 ;
     RECT  57.017 54.384 57.085 63.672 ;
     RECT  56.765 5.616 57.548 48.792 ;
     RECT  57.548 5.472 57.635 48.792 ;
     RECT  57.085 50.4 57.836 63.672 ;
     RECT  57.635 6.24 57.881 48.792 ;
     RECT  57.836 49.824 57.923 63.672 ;
     RECT  57.923 50.16 58.547 63.672 ;
     RECT  58.547 52.704 58.741 63.672 ;
     RECT  57.881 6.24 58.813 48.696 ;
     RECT  58.813 6.192 58.988 48.696 ;
     RECT  58.988 6.144 59.077 48.696 ;
     RECT  59.077 6.144 59.137 48.984 ;
     RECT  59.137 6.144 59.173 49.176 ;
     RECT  58.547 50.16 59.173 51.72 ;
     RECT  59.173 6.144 59.648 51.72 ;
     RECT  58.741 52.704 59.648 63.816 ;
     RECT  59.648 0.528 59.752 63.816 ;
     RECT  59.752 0.798 59.84 63.816 ;
     RECT  59.84 0.798 59.944 64.002 ;
     RECT  59.944 5.328 60.467 59.64 ;
     RECT  59.944 62.16 60.833 63.816 ;
     RECT  60.467 45.984 60.844 59.64 ;
     RECT  60.844 45.984 60.851 47.016 ;
     RECT  60.844 48.048 60.851 59.64 ;
     RECT  60.851 45.984 60.979 46.92 ;
     RECT  59.944 60.672 60.997 60.696 ;
     RECT  60.833 62.16 60.997 62.184 ;
     RECT  60.833 63.6 61.013 63.816 ;
     RECT  60.979 45.984 61.085 46.872 ;
     RECT  61.013 63.6 61.085 63.624 ;
     RECT  60.997 60.672 61.229 62.184 ;
     RECT  61.229 60.672 61.373 62.136 ;
     RECT  60.851 48.432 61.445 59.64 ;
     RECT  60.467 5.328 61.571 45 ;
     RECT  61.445 52.704 61.661 59.64 ;
     RECT  61.445 48.432 61.733 51.72 ;
     RECT  61.661 52.752 61.733 59.64 ;
     RECT  61.373 60.672 61.733 60.936 ;
     RECT  61.733 49.44 61.769 51.72 ;
     RECT  61.571 13.344 61.813 45 ;
     RECT  61.085 45.984 61.813 46.728 ;
     RECT  61.733 48.432 61.813 48.456 ;
     RECT  61.733 58.512 61.813 59.64 ;
     RECT  61.813 47.856 61.841 48.456 ;
     RECT  61.813 13.344 61.877 46.728 ;
     RECT  61.769 50.688 61.877 51.72 ;
     RECT  61.813 58.512 61.9 59.832 ;
     RECT  61.82 3.936 61.907 3.96 ;
     RECT  61.877 15.072 61.913 46.728 ;
     RECT  61.913 15.072 61.949 46.632 ;
     RECT  61.769 49.44 61.949 49.464 ;
     RECT  61.733 52.752 61.949 57.336 ;
     RECT  61.949 52.752 62.021 55.896 ;
     RECT  62.021 55.296 62.029 55.896 ;
     RECT  62.029 55.776 62.057 55.896 ;
     RECT  61.949 57.312 62.092 57.336 ;
     RECT  61.949 15.072 62.129 44.808 ;
     RECT  62.057 55.776 62.147 55.8 ;
     RECT  61.571 5.328 62.201 12.312 ;
     RECT  61.877 13.344 62.201 14.04 ;
     RECT  62.129 18.576 62.201 44.808 ;
     RECT  61.9 58.512 62.201 59.784 ;
     RECT  62.201 5.328 62.273 5.352 ;
     RECT  62.201 6.384 62.273 8.472 ;
     RECT  62.129 15.072 62.273 17.4 ;
     RECT  61.949 46.032 62.273 46.632 ;
     RECT  62.021 52.752 62.284 53.976 ;
     RECT  62.201 9.888 62.309 12.312 ;
     RECT  61.841 47.856 62.339 47.928 ;
     RECT  61.733 60.912 62.417 60.936 ;
     RECT  62.201 13.344 62.453 13.992 ;
     RECT  62.284 53.952 62.489 53.976 ;
     RECT  62.201 58.512 62.489 58.536 ;
     RECT  62.273 7.92 62.525 8.472 ;
     RECT  61.877 50.736 62.561 51.72 ;
     RECT  62.201 59.76 62.561 59.784 ;
     RECT  62.561 50.736 62.572 51 ;
     RECT  62.572 50.736 62.597 50.76 ;
     RECT  62.309 10.128 62.633 12.312 ;
     RECT  62.633 10.176 62.669 12.312 ;
     RECT  62.525 8.208 62.705 8.472 ;
     RECT  62.669 10.176 62.705 10.2 ;
     RECT  62.453 13.968 62.705 13.992 ;
     RECT  62.273 15.072 62.705 15.192 ;
     RECT  62.273 16.32 62.705 17.4 ;
     RECT  62.201 18.72 62.705 44.808 ;
     RECT  62.629 4.8 62.716 4.824 ;
     RECT  62.705 8.208 62.741 8.232 ;
     RECT  62.339 47.904 62.777 47.928 ;
     RECT  62.284 52.752 62.777 52.776 ;
     RECT  62.705 16.32 62.813 17.112 ;
     RECT  62.705 18.96 62.813 18.984 ;
     RECT  61.373 62.112 62.813 62.136 ;
     RECT  62.813 17.088 62.849 17.112 ;
     RECT  62.273 46.608 62.849 46.632 ;
     RECT  62.273 6.384 62.885 6.792 ;
     RECT  62.705 19.968 62.892 44.808 ;
     RECT  62.669 11.52 62.921 12.312 ;
     RECT  62.921 11.52 62.957 11.544 ;
     RECT  62.885 6.768 63.029 6.792 ;
    LAYER M5 ;
     RECT  31.392 0.144 31.608 0.227 ;
     RECT  31.392 0.227 31.416 0.235 ;
     RECT  35.856 0.671 35.88 0.755 ;
     RECT  0.24 0.517 0.36 0.787 ;
     RECT  5.64 0.517 5.76 0.787 ;
     RECT  11.04 0.517 11.16 0.787 ;
     RECT  16.44 0.517 16.56 0.787 ;
     RECT  21.84 0.517 21.96 0.787 ;
     RECT  27.24 0.517 27.36 0.787 ;
     RECT  32.64 0.517 32.76 0.787 ;
     RECT  38.04 0.517 38.16 0.787 ;
     RECT  43.44 0.517 43.56 0.787 ;
     RECT  48.84 0.517 48.96 0.787 ;
     RECT  54.24 0.517 54.36 0.787 ;
     RECT  59.64 0.517 59.76 0.787 ;
     RECT  25.056 0.815 25.08 0.821 ;
     RECT  27.24 0.787 27.552 0.821 ;
     RECT  43.44 0.787 43.752 0.821 ;
     RECT  42.144 0.805 42.168 0.889 ;
     RECT  24.816 0.821 25.08 0.899 ;
     RECT  26.256 0.821 27.552 0.909 ;
     RECT  21.84 0.787 22.152 0.997 ;
     RECT  43.344 0.821 43.752 1.045 ;
     RECT  42.624 1.045 43.752 1.093 ;
     RECT  24.816 0.899 24.84 1.139 ;
     RECT  36.96 0.821 36.984 1.139 ;
     RECT  27.12 0.909 27.552 1.235 ;
     RECT  17.76 1.045 17.784 1.363 ;
     RECT  21.84 0.997 23.064 1.363 ;
     RECT  34.992 1.093 35.016 1.391 ;
     RECT  38.04 0.787 38.352 1.391 ;
     RECT  17.76 1.363 18.264 1.451 ;
     RECT  19.824 1.285 19.848 1.451 ;
     RECT  21.648 1.363 23.064 1.451 ;
     RECT  37.056 1.391 38.352 1.475 ;
     RECT  16.44 0.787 16.752 1.621 ;
     RECT  45.6 1.397 45.624 1.715 ;
     RECT  24.528 1.189 24.552 1.765 ;
     RECT  42.624 1.093 43.944 1.967 ;
     RECT  18.816 1.957 18.84 2.041 ;
     RECT  34.752 1.391 35.016 2.053 ;
     RECT  39.792 2.037 39.816 2.149 ;
     RECT  40.992 2.165 41.016 2.197 ;
     RECT  42.192 1.967 43.944 2.197 ;
     RECT  45.264 2.037 45.288 2.197 ;
     RECT  26.208 2.197 26.232 2.229 ;
     RECT  39.36 2.149 39.816 2.233 ;
     RECT  34.752 2.053 35.832 2.245 ;
     RECT  24.288 1.765 24.552 2.283 ;
     RECT  42.192 2.197 45.288 2.283 ;
     RECT  40.8 2.197 41.016 2.291 ;
     RECT  26.016 2.229 26.232 2.317 ;
     RECT  32.64 0.787 32.952 2.341 ;
     RECT  34.752 2.245 35.928 2.341 ;
     RECT  19.968 1.669 19.992 2.451 ;
     RECT  19.344 2.451 19.992 2.485 ;
     RECT  14.832 2.485 14.856 2.569 ;
     RECT  19.344 2.485 20.616 2.581 ;
     RECT  32.64 2.341 35.928 2.581 ;
     RECT  37.248 1.475 38.352 2.591 ;
     RECT  37.248 2.591 38.472 2.613 ;
     RECT  32.496 2.581 35.928 2.627 ;
     RECT  42.192 2.283 43.944 2.629 ;
     RECT  19.344 2.581 20.76 2.667 ;
     RECT  42.096 2.629 43.944 2.667 ;
     RECT  36.96 2.613 38.472 2.675 ;
     RECT  27.24 1.235 27.552 2.677 ;
     RECT  34.752 2.627 35.928 2.723 ;
     RECT  21.84 1.451 22.872 2.725 ;
     RECT  21.648 2.725 22.872 2.735 ;
     RECT  35.856 2.723 35.928 2.773 ;
     RECT  36.96 2.675 38.352 2.773 ;
     RECT  39.696 2.233 39.816 2.805 ;
     RECT  40.8 2.291 40.92 2.805 ;
     RECT  21.648 2.735 22.968 2.809 ;
     RECT  15.216 2.773 15.24 2.821 ;
     RECT  29.664 2.245 29.688 2.821 ;
     RECT  19.344 2.667 20.04 2.859 ;
     RECT  35.856 2.773 38.352 2.859 ;
     RECT  43.344 2.667 43.944 2.859 ;
     RECT  32.496 2.627 33.192 2.867 ;
     RECT  16.44 1.621 17.448 2.869 ;
     RECT  16.44 2.869 17.592 2.963 ;
     RECT  21.744 2.809 22.968 2.997 ;
     RECT  19.344 2.859 19.992 3.059 ;
     RECT  31.296 2.869 31.32 3.167 ;
     RECT  26.208 2.317 26.232 3.243 ;
     RECT  29.232 2.821 29.688 3.301 ;
     RECT  30.768 3.167 31.32 3.301 ;
     RECT  32.496 2.867 33.048 3.301 ;
     RECT  21.744 2.997 23.4 3.307 ;
     RECT  39.696 2.805 40.92 3.359 ;
     RECT  42.096 2.667 42.12 3.359 ;
     RECT  45.264 2.283 45.288 3.381 ;
     RECT  35.856 2.859 36.072 3.443 ;
     RECT  43.44 2.859 43.944 3.445 ;
     RECT  45.072 3.381 45.288 3.445 ;
     RECT  29.232 3.301 33.048 3.469 ;
     RECT  27.24 2.677 27.96 3.573 ;
     RECT  16.44 2.963 17.256 3.587 ;
     RECT  43.44 3.445 45.288 3.603 ;
     RECT  26.736 3.573 28.056 3.661 ;
     RECT  29.232 3.469 31.032 3.661 ;
     RECT  48.84 0.787 49.152 3.685 ;
     RECT  43.44 3.603 45.432 3.691 ;
     RECT  39.696 3.359 42.12 3.701 ;
     RECT  21.84 3.307 23.4 3.733 ;
     RECT  24.528 2.283 24.552 3.733 ;
     RECT  36.048 3.443 36.072 3.755 ;
     RECT  21.84 3.733 24.552 3.819 ;
     RECT  19.968 3.059 19.992 3.827 ;
     RECT  29.232 3.661 30.984 3.829 ;
     RECT  39.408 3.701 42.12 3.829 ;
     RECT  43.44 3.691 44.472 3.829 ;
     RECT  34.752 2.723 34.776 3.912 ;
     RECT  34.752 3.912 34.824 3.913 ;
     RECT  32.064 3.469 33.048 3.925 ;
     RECT  15.216 2.821 15.432 4.011 ;
     RECT  32.064 3.925 33.576 4.011 ;
     RECT  34.8 3.913 34.824 4.011 ;
     RECT  39.408 3.829 42.168 4.011 ;
     RECT  24.528 3.819 24.552 4.021 ;
     RECT  24.528 4.021 24.6 4.069 ;
     RECT  32.064 4.011 33.432 4.115 ;
     RECT  37.296 2.859 38.352 4.213 ;
     RECT  39.408 4.011 39.768 4.213 ;
     RECT  43.344 3.829 44.472 4.243 ;
     RECT  36.288 4.179 36.312 4.261 ;
     RECT  37.296 4.213 39.768 4.261 ;
     RECT  14.64 4.179 14.664 4.267 ;
     RECT  36.288 4.261 39.768 4.267 ;
     RECT  36.672 4.267 39.768 4.307 ;
     RECT  21.84 3.819 23.016 4.319 ;
     RECT  41.04 4.011 42.168 4.405 ;
     RECT  43.296 4.243 44.472 4.405 ;
     RECT  47.904 3.685 50.136 4.405 ;
     RECT  21.744 4.319 23.016 4.453 ;
     RECT  24.528 4.069 25.08 4.453 ;
     RECT  27.24 3.661 28.056 4.501 ;
     RECT  29.088 3.829 30.984 4.501 ;
     RECT  21.648 4.453 23.016 4.523 ;
     RECT  24.528 4.453 26.232 4.537 ;
     RECT  41.04 4.405 44.472 4.547 ;
     RECT  19.056 4.501 19.08 4.587 ;
     RECT  20.304 4.501 20.328 4.587 ;
     RECT  24.528 4.537 25.08 4.587 ;
     RECT  41.04 4.547 44.28 4.587 ;
     RECT  47.904 4.405 50.424 4.645 ;
     RECT  16.44 3.587 17.112 4.691 ;
     RECT  36.672 4.307 38.472 4.715 ;
     RECT  47.856 4.645 50.424 4.741 ;
     RECT  61.872 3.925 61.896 4.755 ;
     RECT  46.32 3.925 46.344 4.789 ;
     RECT  52.32 4.725 52.344 4.813 ;
     RECT  47.472 4.741 50.424 4.843 ;
     RECT  61.872 4.755 62.664 4.843 ;
     RECT  45.312 4.789 46.344 4.895 ;
     RECT  27.24 4.501 30.984 4.917 ;
     RECT  32.064 4.115 32.952 4.917 ;
     RECT  45.312 4.895 46.728 4.979 ;
     RECT  47.904 4.843 50.424 5.005 ;
     RECT  43.056 4.587 44.28 5.099 ;
     RECT  27.24 4.917 32.952 5.109 ;
     RECT  20.448 5.045 20.472 5.133 ;
     RECT  36.72 4.715 38.472 5.219 ;
     RECT  27.24 5.109 33.816 5.267 ;
     RECT  37.104 5.219 38.472 5.269 ;
     RECT  39.696 4.307 39.768 5.269 ;
     RECT  48.144 5.005 50.424 5.315 ;
     RECT  59.64 0.787 59.952 5.317 ;
     RECT  26.16 4.537 26.232 5.365 ;
     RECT  27.24 5.267 29.688 5.365 ;
     RECT  30.768 5.267 33.816 5.419 ;
     RECT  43.056 5.099 44.088 5.459 ;
     RECT  48.144 5.315 49.152 5.459 ;
     RECT  45.312 4.979 46.344 5.547 ;
     RECT  41.04 4.587 41.976 5.587 ;
     RECT  57.6 5.461 57.624 5.587 ;
     RECT  43.056 5.459 44.04 5.603 ;
     RECT  21.648 4.523 22.344 5.605 ;
     RECT  50.4 5.315 50.424 5.605 ;
     RECT  54.24 0.787 54.552 5.653 ;
     RECT  24.48 5.011 24.504 5.663 ;
     RECT  37.104 5.269 39.768 5.663 ;
     RECT  40.8 5.587 41.976 5.663 ;
     RECT  54.24 5.653 54.744 5.685 ;
     RECT  21.648 5.605 22.824 5.699 ;
     RECT  37.104 5.663 41.976 5.747 ;
     RECT  45.36 5.547 46.344 5.747 ;
     RECT  50.4 5.605 50.808 5.747 ;
     RECT  40.944 5.747 41.976 5.749 ;
     RECT  54.24 5.685 54.792 5.749 ;
     RECT  56.688 5.587 57.624 5.749 ;
     RECT  34.992 5.685 35.016 5.773 ;
     RECT  40.944 5.749 42.36 5.833 ;
     RECT  54.144 5.749 54.792 5.843 ;
     RECT  26.16 5.365 29.688 5.845 ;
     RECT  51.936 5.237 51.96 5.845 ;
     RECT  55.872 5.749 57.624 5.877 ;
     RECT  30.768 5.419 33.048 5.931 ;
     RECT  21.84 5.699 22.824 5.941 ;
     RECT  24.48 5.663 24.84 5.941 ;
     RECT  51.936 5.845 52.44 5.941 ;
     RECT  54.24 5.843 54.792 5.989 ;
     RECT  55.872 5.877 58.152 5.989 ;
     RECT  25.92 5.845 29.688 5.995 ;
     RECT  39.888 5.747 39.912 5.995 ;
     RECT  21.84 5.941 24.84 6.035 ;
     RECT  54.24 5.989 58.152 6.133 ;
     RECT  59.64 5.317 60.84 6.133 ;
     RECT  14.832 5.109 14.856 6.163 ;
     RECT  51.936 5.941 52.488 6.179 ;
     RECT  24.48 6.035 24.84 6.197 ;
     RECT  37.104 5.747 38.808 6.227 ;
     RECT  14.208 6.163 14.856 6.251 ;
     RECT  18 6.163 18.024 6.251 ;
     RECT  40.944 5.833 42.024 6.251 ;
     RECT  51.936 6.179 52.056 6.261 ;
     RECT  45.36 5.747 45.384 6.275 ;
     RECT  54.24 6.133 60.84 6.275 ;
     RECT  34.128 6.099 34.776 6.315 ;
     RECT  24.48 6.197 25.56 6.323 ;
     RECT  26.688 5.995 29.688 6.323 ;
     RECT  30.768 5.931 30.792 6.323 ;
     RECT  31.872 5.931 33.048 6.323 ;
     RECT  34.224 6.315 34.776 6.323 ;
     RECT  57.6 6.275 60.84 6.323 ;
     RECT  41.424 6.251 42.024 6.371 ;
     RECT  41.664 6.371 42.024 6.467 ;
     RECT  59.232 6.323 60.84 6.467 ;
     RECT  43.344 5.603 44.04 6.565 ;
     RECT  24.912 6.323 25.56 6.611 ;
     RECT  48.72 5.459 49.152 6.613 ;
     RECT  59.424 6.467 60.84 6.661 ;
     RECT  61.872 4.843 61.896 6.661 ;
     RECT  48.192 6.613 49.272 6.739 ;
     RECT  50.688 5.747 50.808 6.739 ;
     RECT  35.808 6.005 35.832 6.757 ;
     RECT  37.104 6.227 38.616 6.757 ;
     RECT  19.584 6.709 19.608 6.767 ;
     RECT  35.808 6.757 38.616 6.773 ;
     RECT  48.192 6.739 50.808 6.805 ;
     RECT  51.888 6.261 52.056 6.805 ;
     RECT  24.912 6.611 25.128 6.827 ;
     RECT  32.16 6.323 33.048 6.827 ;
     RECT  48.192 6.805 52.056 6.827 ;
     RECT  54.24 6.275 55.896 6.827 ;
     RECT  16.44 4.691 16.752 6.837 ;
     RECT  28.608 6.323 29.688 6.837 ;
     RECT  43.296 6.565 44.04 6.837 ;
     RECT  13.68 6.767 13.704 6.851 ;
     RECT  18.768 6.767 19.608 6.851 ;
     RECT  16.32 6.837 16.752 6.853 ;
     RECT  35.712 6.773 38.616 6.861 ;
     RECT  50.784 6.827 52.056 6.891 ;
     RECT  48.432 6.827 49.56 6.899 ;
     RECT  48.576 6.899 49.56 6.925 ;
     RECT  57.6 6.323 57.96 6.925 ;
     RECT  34.224 6.323 34.248 7.043 ;
     RECT  52.032 6.891 52.056 7.091 ;
     RECT  21.84 6.035 22.824 7.237 ;
     RECT  15.168 6.469 15.192 7.315 ;
     RECT  24.912 6.827 24.936 7.331 ;
     RECT  19.584 6.851 19.608 7.333 ;
     RECT  26.688 6.323 27.552 7.333 ;
     RECT  28.608 6.837 29.736 7.333 ;
     RECT  43.248 6.837 44.04 7.349 ;
     RECT  39.936 6.837 39.96 7.381 ;
     RECT  15.12 7.315 15.192 7.403 ;
     RECT  21.84 7.237 23.4 7.403 ;
     RECT  19.584 7.333 20.472 7.417 ;
     RECT  26.688 7.333 29.736 7.427 ;
     RECT  43.248 7.349 44.952 7.437 ;
     RECT  54.24 6.827 55.704 7.437 ;
     RECT  21.84 7.403 22.824 7.475 ;
     RECT  50.784 6.891 50.808 7.475 ;
     RECT  41.664 6.467 41.688 7.477 ;
     RECT  16.32 6.853 17.112 7.535 ;
     RECT  36.192 6.861 38.616 7.535 ;
     RECT  59.424 6.661 61.896 7.541 ;
     RECT  21.84 7.475 22.152 7.573 ;
     RECT  54.24 7.437 55.608 7.595 ;
     RECT  16.32 7.535 17.64 7.619 ;
     RECT  36.192 7.535 38.76 7.619 ;
     RECT  57.744 6.925 57.96 7.629 ;
     RECT  41.664 7.477 41.928 7.635 ;
     RECT  43.248 7.437 44.568 7.635 ;
     RECT  55.584 7.595 55.608 7.667 ;
     RECT  39.888 7.381 39.96 7.669 ;
     RECT  16.32 7.619 17.112 7.699 ;
     RECT  41.664 7.635 44.568 7.723 ;
     RECT  39.888 7.669 40.632 7.733 ;
     RECT  41.664 7.723 41.928 7.733 ;
     RECT  15.936 7.699 17.112 7.787 ;
     RECT  36.192 7.619 38.472 7.787 ;
     RECT  30.768 7.381 30.792 7.797 ;
     RECT  32.256 6.827 33.048 7.797 ;
     RECT  36.288 7.787 38.472 7.851 ;
     RECT  48.72 6.925 49.56 7.851 ;
     RECT  27.24 7.427 29.736 7.861 ;
     RECT  47.568 7.797 47.592 7.891 ;
     RECT  30.768 7.797 33.048 7.907 ;
     RECT  59.28 7.541 61.896 7.909 ;
     RECT  37.536 7.851 38.472 7.915 ;
     RECT  27.24 7.861 29.784 7.925 ;
     RECT  30.768 7.907 30.792 7.925 ;
     RECT  27.24 7.925 30.792 7.979 ;
     RECT  39.888 7.733 41.928 7.979 ;
     RECT  47.424 7.891 47.592 7.979 ;
     RECT  39.888 7.979 41.64 7.993 ;
     RECT  13.248 7.381 13.272 8.003 ;
     RECT  16.44 7.787 17.112 8.003 ;
     RECT  36.384 7.851 36.504 8.003 ;
     RECT  26.112 7.967 26.136 8.051 ;
     RECT  30.672 7.979 30.792 8.099 ;
     RECT  19.584 7.417 19.608 8.211 ;
     RECT  18.672 8.211 19.608 8.299 ;
     RECT  31.92 7.907 32.952 8.329 ;
     RECT  50.736 7.919 50.76 8.341 ;
     RECT  39.888 7.993 41.112 8.373 ;
     RECT  52.416 7.957 52.44 8.373 ;
     RECT  42.96 7.723 44.568 8.427 ;
     RECT  18.768 8.299 19.608 8.437 ;
     RECT  20.64 7.573 22.152 8.437 ;
     RECT  18.768 8.437 22.152 8.467 ;
     RECT  25.728 8.351 25.752 8.467 ;
     RECT  25.68 8.467 25.752 8.468 ;
     RECT  48.84 7.851 49.56 8.485 ;
     RECT  57.984 7.891 58.008 8.485 ;
     RECT  24.528 8.403 24.552 8.491 ;
     RECT  30.672 8.099 30.744 8.531 ;
     RECT  52.416 8.373 53.16 8.555 ;
     RECT  52.416 8.555 53.064 8.569 ;
     RECT  57.984 8.485 58.152 8.569 ;
     RECT  30.672 8.531 30.696 8.627 ;
     RECT  43.248 8.427 44.568 8.821 ;
     RECT  47.808 8.693 47.832 8.821 ;
     RECT  48.84 8.485 49.608 8.821 ;
     RECT  55.872 8.757 55.896 8.851 ;
     RECT  54.24 7.595 54.552 8.869 ;
     RECT  55.728 8.851 55.896 8.869 ;
     RECT  18.768 8.467 22.44 8.885 ;
     RECT  36.384 8.003 36.408 8.885 ;
     RECT  14.208 8.821 14.232 8.905 ;
     RECT  15.408 8.821 15.432 8.905 ;
     RECT  37.536 7.915 38.352 8.917 ;
     RECT  50.592 8.341 50.76 8.939 ;
     RECT  52.416 8.569 52.728 8.939 ;
     RECT  47.808 8.821 49.608 8.979 ;
     RECT  24.24 8.885 24.264 9.011 ;
     RECT  27.24 7.979 29.688 9.013 ;
     RECT  52.416 8.939 52.44 9.013 ;
     RECT  37.536 8.917 38.808 9.043 ;
     RECT  39.84 8.373 41.112 9.043 ;
     RECT  47.568 8.979 49.608 9.043 ;
     RECT  56.88 9.013 56.904 9.043 ;
     RECT  57.888 8.821 57.912 9.043 ;
     RECT  11.04 0.787 11.352 9.061 ;
     RECT  35.52 8.885 36.408 9.061 ;
     RECT  59.232 7.909 61.896 9.061 ;
     RECT  18.768 8.885 23.016 9.107 ;
     RECT  25.68 8.468 25.704 9.107 ;
     RECT  46.272 8.485 46.296 9.119 ;
     RECT  47.568 9.043 50.184 9.119 ;
     RECT  27.24 9.013 30.264 9.131 ;
     RECT  46.272 9.119 50.184 9.131 ;
     RECT  56.88 9.043 57.912 9.131 ;
     RECT  18.768 9.107 22.776 9.145 ;
     RECT  16.44 8.003 16.92 9.171 ;
     RECT  46.272 9.131 50.136 9.203 ;
     RECT  34.656 9.061 36.408 9.205 ;
     RECT  37.536 9.043 41.112 9.205 ;
     RECT  43.248 8.821 44.76 9.205 ;
     RECT  43.248 9.205 45.048 9.229 ;
     RECT  51.984 9.013 52.44 9.251 ;
     RECT  16.44 9.171 17.304 9.259 ;
     RECT  11.04 9.061 12.024 9.269 ;
     RECT  43.296 9.229 45.048 9.289 ;
     RECT  13.68 9.141 13.704 9.323 ;
     RECT  11.04 9.269 12.264 9.349 ;
     RECT  34.656 9.205 41.16 9.349 ;
     RECT  59.232 9.061 62.04 9.349 ;
     RECT  34.128 9.349 41.16 9.387 ;
     RECT  32.448 8.329 32.952 9.397 ;
     RECT  34.128 9.387 35.832 9.397 ;
     RECT  18.768 9.145 19.416 9.445 ;
     RECT  36.912 9.387 41.16 9.451 ;
     RECT  47.52 9.203 50.136 9.539 ;
     RECT  18.672 9.445 19.416 9.555 ;
     RECT  10.944 9.349 12.264 9.637 ;
     RECT  54.24 8.869 55.896 9.637 ;
     RECT  43.296 9.289 44.712 9.643 ;
     RECT  10.848 9.637 12.264 9.695 ;
     RECT  46.272 9.203 46.296 9.695 ;
     RECT  51.984 9.251 52.392 9.717 ;
     RECT  47.856 9.539 50.136 9.721 ;
     RECT  46.176 9.695 46.296 9.741 ;
     RECT  20.544 9.145 22.776 9.779 ;
     RECT  32.448 9.397 35.832 9.779 ;
     RECT  46.176 9.741 46.2 9.779 ;
     RECT  21.744 9.779 22.776 9.827 ;
     RECT  14.832 9.061 14.856 9.877 ;
     RECT  31.248 9.717 31.272 9.925 ;
     RECT  32.448 9.779 35.352 9.925 ;
     RECT  57.552 9.131 57.912 9.925 ;
     RECT  58.992 9.349 62.04 9.925 ;
     RECT  18.576 9.555 19.416 10.003 ;
     RECT  18 10.003 19.416 10.019 ;
     RECT  31.248 9.925 35.352 10.037 ;
     RECT  26.208 9.695 26.232 10.057 ;
     RECT  43.44 9.643 44.712 10.067 ;
     RECT  18 10.019 18.936 10.091 ;
     RECT  20.544 9.779 20.568 10.091 ;
     RECT  14.832 9.877 15.432 10.211 ;
     RECT  25.92 10.131 25.944 10.219 ;
     RECT  30.576 10.037 35.352 10.283 ;
     RECT  54.24 9.637 56.376 10.283 ;
     RECT  10.8 9.695 12.264 10.293 ;
     RECT  16.44 9.259 16.752 10.293 ;
     RECT  48.672 9.721 50.136 10.293 ;
     RECT  51.216 9.717 52.392 10.293 ;
     RECT  36.912 9.451 40.824 10.355 ;
     RECT  45.024 10.271 45.048 10.355 ;
     RECT  54.24 10.283 55.896 10.357 ;
     RECT  10.656 10.293 12.264 10.381 ;
     RECT  24.192 10.131 24.216 10.405 ;
     RECT  57.552 9.925 62.04 10.453 ;
     RECT  53.568 10.357 55.896 10.475 ;
     RECT  23.904 10.405 24.36 10.488 ;
     RECT  10.848 10.381 12.264 10.549 ;
     RECT  37.152 10.355 40.824 10.595 ;
     RECT  27.24 9.131 29.496 10.597 ;
     RECT  30.576 10.283 30.84 10.597 ;
     RECT  10.848 10.549 12.552 10.633 ;
     RECT  21.84 9.827 22.776 10.645 ;
     RECT  23.856 10.488 24.36 10.645 ;
     RECT  15.456 10.293 16.752 10.741 ;
     RECT  48.672 10.293 52.392 10.741 ;
     RECT  13.392 10.707 13.416 10.795 ;
     RECT  31.872 10.283 35.352 10.837 ;
     RECT  10.848 10.633 12.072 10.883 ;
     RECT  27.24 10.597 30.84 10.893 ;
     RECT  15.456 10.741 16.872 10.931 ;
     RECT  48.432 10.741 52.536 10.933 ;
     RECT  21.84 10.645 24.36 10.981 ;
     RECT  57.552 10.453 62.088 10.981 ;
     RECT  18.816 10.091 18.936 10.991 ;
     RECT  43.44 10.067 43.896 11.061 ;
     RECT  53.568 10.475 55.848 11.065 ;
     RECT  18.816 10.991 19.416 11.075 ;
     RECT  27.24 10.893 30.312 11.091 ;
     RECT  47.856 10.933 52.536 11.091 ;
     RECT  47.568 11.091 52.536 11.123 ;
     RECT  43.296 11.061 43.896 11.149 ;
     RECT  21.072 10.981 24.36 11.155 ;
     RECT  15.456 10.931 16.752 11.173 ;
     RECT  47.568 11.123 50.76 11.173 ;
     RECT  20.112 11.155 24.36 11.179 ;
     RECT  26.352 11.091 30.312 11.179 ;
     RECT  37.152 10.595 40.248 11.219 ;
     RECT  54.048 11.065 55.848 11.243 ;
     RECT  27.24 11.179 30.312 11.257 ;
     RECT  24.528 11.183 24.552 11.269 ;
     RECT  15.168 11.173 16.752 11.307 ;
     RECT  18.816 11.075 18.84 11.317 ;
     RECT  57.024 10.981 62.088 11.317 ;
     RECT  27.24 11.257 30.12 11.341 ;
     RECT  46.944 11.173 50.76 11.363 ;
     RECT  18.768 11.317 18.84 11.365 ;
     RECT  11.04 10.883 12.072 11.371 ;
     RECT  43.44 11.149 43.896 11.375 ;
     RECT  31.872 10.837 35.784 11.411 ;
     RECT  34.368 11.411 35.784 11.413 ;
     RECT  34.368 11.413 36.696 11.459 ;
     RECT  43.44 11.375 44.472 11.459 ;
     RECT  46.944 11.363 49.896 11.459 ;
     RECT  27.24 11.341 29.544 11.555 ;
     RECT  20.112 11.179 23.4 11.563 ;
     RECT  15.168 11.307 15.432 11.567 ;
     RECT  5.64 0.787 5.952 11.637 ;
     RECT  37.872 11.219 40.248 11.637 ;
     RECT  55.536 11.243 55.848 11.637 ;
     RECT  56.88 11.317 62.088 11.637 ;
     RECT  14.784 11.567 15.432 11.699 ;
     RECT  17.856 11.365 18.84 11.699 ;
     RECT  34.752 11.459 36.696 11.699 ;
     RECT  43.44 11.459 44.04 11.699 ;
     RECT  4.8 11.637 5.952 11.725 ;
     RECT  37.872 11.637 40.68 11.725 ;
     RECT  43.44 11.699 43.944 11.725 ;
     RECT  54.048 11.243 54.552 11.725 ;
     RECT  17.856 11.699 17.88 11.987 ;
     RECT  55.536 11.637 62.088 12.035 ;
     RECT  24.528 11.269 24.984 12.149 ;
     RECT  43.44 11.725 43.896 12.149 ;
     RECT  52.512 11.123 52.536 12.149 ;
     RECT  52.128 12.149 52.536 12.191 ;
     RECT  20.112 11.563 22.248 12.203 ;
     RECT  7.44 11.941 7.464 12.213 ;
     RECT  9.168 11.941 9.192 12.213 ;
     RECT  11.04 11.371 11.352 12.213 ;
     RECT  24.528 12.149 25.752 12.213 ;
     RECT  54.24 11.725 54.552 12.213 ;
     RECT  55.536 12.035 57.912 12.213 ;
     RECT  37.872 11.725 39.96 12.227 ;
     RECT  46.944 11.459 46.968 12.227 ;
     RECT  54.24 12.213 57.912 12.227 ;
     RECT  52.128 12.191 53.016 12.237 ;
     RECT  7.44 12.213 11.352 12.267 ;
     RECT  48.432 11.459 49.896 12.267 ;
     RECT  20.112 12.203 20.76 12.275 ;
     RECT  37.872 12.227 38.352 12.275 ;
     RECT  45.024 12.213 45.048 12.301 ;
     RECT  24 12.213 25.752 12.323 ;
     RECT  31.872 11.411 33.048 12.469 ;
     RECT  8.112 12.267 11.352 12.515 ;
     RECT  5.64 11.725 5.952 12.517 ;
     RECT  13.392 12.181 13.416 12.517 ;
     RECT  14.784 11.699 14.952 12.517 ;
     RECT  42.96 12.149 43.896 12.517 ;
     RECT  35.328 11.699 36.456 12.611 ;
     RECT  39.36 12.227 39.96 12.691 ;
     RECT  13.392 12.517 14.952 12.725 ;
     RECT  16.44 11.307 16.752 12.725 ;
     RECT  39.36 12.691 40.104 12.725 ;
     RECT  41.424 12.213 41.448 12.725 ;
     RECT  48.624 12.267 49.896 12.725 ;
     RECT  52.752 12.237 53.016 12.725 ;
     RECT  54.24 12.227 56.904 12.725 ;
     RECT  27.24 11.555 27.552 12.789 ;
     RECT  28.608 11.555 29.544 12.789 ;
     RECT  42.768 12.517 43.896 12.789 ;
     RECT  18.384 12.725 18.408 12.813 ;
     RECT  24.48 12.323 25.752 12.901 ;
     RECT  27.24 12.789 29.544 12.901 ;
     RECT  5.64 12.517 6.216 12.917 ;
     RECT  31.872 12.469 33.096 12.949 ;
     RECT  48.624 12.725 50.52 12.981 ;
     RECT  13.392 12.725 16.872 12.997 ;
     RECT  21.84 12.203 22.248 12.997 ;
     RECT  5.64 12.917 6.648 13.005 ;
     RECT  39.36 12.725 41.448 13.035 ;
     RECT  24.48 12.901 29.544 13.045 ;
     RECT  36.48 12.981 36.504 13.091 ;
     RECT  48.624 12.981 50.568 13.091 ;
     RECT  12.96 12.997 16.872 13.099 ;
     RECT  20.256 12.275 20.76 13.099 ;
     RECT  21.84 12.997 22.344 13.099 ;
     RECT  24.48 13.045 29.64 13.099 ;
     RECT  46.56 12.883 46.584 13.099 ;
     RECT  48.624 13.091 49.704 13.099 ;
     RECT  41.136 13.035 41.448 13.109 ;
     RECT  24.48 13.099 25.704 13.129 ;
     RECT  26.736 13.099 29.64 13.129 ;
     RECT  31.872 12.949 33.624 13.139 ;
     RECT  13.056 13.099 13.08 13.156 ;
     RECT  8.304 12.515 11.352 13.163 ;
     RECT  8.352 13.163 11.352 13.197 ;
     RECT  14.256 13.099 16.872 13.197 ;
     RECT  31.968 13.139 33.624 13.235 ;
     RECT  32.496 13.235 33.624 13.237 ;
     RECT  35.088 12.981 35.256 13.237 ;
     RECT  15.36 13.197 16.872 13.285 ;
     RECT  18.144 13.237 18.168 13.285 ;
     RECT  37.92 12.275 38.352 13.301 ;
     RECT  1.584 13.267 1.608 13.355 ;
     RECT  42.768 12.789 44.568 13.355 ;
     RECT  52.752 12.725 56.904 13.369 ;
     RECT  57.888 12.227 57.912 13.381 ;
     RECT  58.992 12.035 62.088 13.381 ;
     RECT  9.936 13.197 11.352 13.429 ;
     RECT  53.616 13.369 56.904 13.477 ;
     RECT  57.888 13.381 62.088 13.477 ;
     RECT  8.352 13.197 8.376 13.483 ;
     RECT  9.936 13.429 11.448 13.483 ;
     RECT  14.256 13.197 14.28 13.523 ;
     RECT  9.936 13.483 9.96 13.547 ;
     RECT  20.544 13.099 20.76 13.557 ;
     RECT  21.84 13.099 22.152 13.557 ;
     RECT  53.616 13.477 62.088 13.561 ;
     RECT  24.48 13.129 24.504 13.571 ;
     RECT  37.584 13.301 38.352 13.571 ;
     RECT  15.36 13.285 18.168 13.581 ;
     RECT  27.12 13.129 29.64 13.587 ;
     RECT  53.616 13.561 56.568 13.611 ;
     RECT  27.12 13.587 30.072 13.675 ;
     RECT  32.496 13.237 35.256 13.675 ;
     RECT  43.344 13.355 44.568 13.749 ;
     RECT  41.136 13.109 41.64 13.763 ;
     RECT  54.24 13.611 56.568 13.763 ;
     RECT  0.24 0.787 0.552 13.779 ;
     RECT  39.888 13.035 40.008 13.859 ;
     RECT  34.848 13.675 35.256 13.861 ;
     RECT  0.24 13.779 1.512 13.867 ;
     RECT  54.24 13.763 56.04 13.867 ;
     RECT  5.64 13.005 6.072 13.941 ;
     RECT  38.04 13.571 38.352 13.941 ;
     RECT  57.888 13.561 62.088 13.957 ;
     RECT  25.488 13.129 25.704 13.965 ;
     RECT  4.656 13.941 6.072 13.971 ;
     RECT  48.84 13.099 49.704 14.069 ;
     RECT  20.544 13.557 22.152 14.101 ;
     RECT  23.184 14.069 23.208 14.101 ;
     RECT  4.656 13.971 6.12 14.111 ;
     RECT  38.04 13.941 38.568 14.111 ;
     RECT  56.016 13.867 56.04 14.147 ;
     RECT  2.64 12.517 2.664 14.149 ;
     RECT  3.936 14.111 6.12 14.149 ;
     RECT  34.848 13.861 35.352 14.149 ;
     RECT  20.544 14.101 23.208 14.157 ;
     RECT  19.344 14.101 19.368 14.163 ;
     RECT  41.136 13.763 41.16 14.163 ;
     RECT  20.544 14.157 22.824 14.187 ;
     RECT  34.848 14.149 36.072 14.187 ;
     RECT  2.64 14.149 6.12 14.195 ;
     RECT  15.456 13.581 18.168 14.197 ;
     RECT  19.2 14.163 19.368 14.197 ;
     RECT  47.904 14.069 49.704 14.243 ;
     RECT  9.84 14.163 9.864 14.251 ;
     RECT  15.456 14.197 19.368 14.251 ;
     RECT  25.584 13.965 25.704 14.251 ;
     RECT  20.544 14.187 22.632 14.255 ;
     RECT  48.72 14.243 49.704 14.255 ;
     RECT  51.312 14.053 51.336 14.255 ;
     RECT  52.416 13.477 52.44 14.255 ;
     RECT  4.56 14.195 6.12 14.261 ;
     RECT  27.12 13.675 29.688 14.261 ;
     RECT  15.456 14.251 18.264 14.281 ;
     RECT  25.68 14.251 25.704 14.291 ;
     RECT  34.896 14.187 36.072 14.339 ;
     RECT  48.72 14.255 50.136 14.339 ;
     RECT  51.312 14.255 52.44 14.339 ;
     RECT  4.56 14.261 6.168 14.341 ;
     RECT  20.448 14.255 22.632 14.443 ;
     RECT  43.344 13.749 44.616 14.443 ;
     RECT  47.232 14.355 47.688 14.443 ;
     RECT  2.64 14.195 3.576 14.485 ;
     RECT  50.832 14.341 50.904 14.507 ;
     RECT  2.448 14.485 3.576 14.571 ;
     RECT  52.368 14.339 52.44 14.581 ;
     RECT  0.24 13.867 1.224 14.627 ;
     RECT  50.88 14.507 50.904 14.627 ;
     RECT  47.664 14.443 47.688 14.635 ;
     RECT  36.048 14.339 36.072 14.639 ;
     RECT  13.056 14.581 13.08 14.677 ;
     RECT  45.024 14.581 45.048 14.677 ;
     RECT  46.176 14.581 46.2 14.677 ;
     RECT  52.368 14.581 53.064 14.677 ;
     RECT  54.24 13.867 54.552 14.677 ;
     RECT  40.416 14.163 41.16 14.739 ;
     RECT  12.816 14.677 13.08 14.763 ;
     RECT  38.04 14.111 39.336 14.763 ;
     RECT  40.416 14.739 41.88 14.763 ;
     RECT  45.024 14.677 46.2 14.763 ;
     RECT  10.944 13.483 11.448 14.773 ;
     RECT  24.336 14.533 24.456 14.827 ;
     RECT  41.424 14.763 41.88 14.827 ;
     RECT  45.648 14.763 46.152 14.827 ;
     RECT  27.024 14.261 29.688 14.831 ;
     RECT  36.048 14.639 36.408 14.831 ;
     RECT  43.344 14.443 43.896 14.831 ;
     RECT  57.888 13.957 62.136 14.837 ;
     RECT  36.048 14.831 36.84 14.867 ;
     RECT  26.784 14.831 29.688 14.915 ;
     RECT  36.336 14.867 36.84 14.915 ;
     RECT  41.424 14.827 41.832 14.915 ;
     RECT  43.296 14.831 43.896 14.915 ;
     RECT  57.36 14.837 62.136 14.925 ;
     RECT  32.496 13.675 33.384 14.965 ;
     RECT  52.368 14.677 54.552 15.059 ;
     RECT  4.56 14.341 6.456 15.061 ;
     RECT  7.728 14.547 7.752 15.061 ;
     RECT  4.56 15.061 7.752 15.093 ;
     RECT  15.456 14.281 18.216 15.093 ;
     RECT  19.344 14.251 19.368 15.093 ;
     RECT  20.448 14.443 20.856 15.093 ;
     RECT  39.552 15.029 39.96 15.117 ;
     RECT  19.344 15.093 20.856 15.147 ;
     RECT  2.928 14.571 3.576 15.157 ;
     RECT  4.56 15.093 8.616 15.157 ;
     RECT  2.928 15.157 8.616 15.203 ;
     RECT  7.392 15.203 8.616 15.251 ;
     RECT  7.392 15.251 8.472 15.275 ;
     RECT  10.368 14.773 11.448 15.275 ;
     RECT  14.688 15.093 18.216 15.285 ;
     RECT  13.008 14.763 13.08 15.347 ;
     RECT  21.84 14.443 22.632 15.349 ;
     RECT  31.584 14.965 33.384 15.349 ;
     RECT  52.368 15.059 52.44 15.349 ;
     RECT  51.264 15.349 52.44 15.395 ;
     RECT  14.208 15.285 18.216 15.403 ;
     RECT  25.92 15.315 25.944 15.403 ;
     RECT  21.84 15.349 22.776 15.407 ;
     RECT  14.208 15.403 17.448 15.443 ;
     RECT  13.056 15.347 13.08 15.477 ;
     RECT  14.208 15.443 17.16 15.477 ;
     RECT  21.84 15.407 22.92 15.491 ;
     RECT  38.04 14.763 38.52 15.491 ;
     RECT  39.792 15.117 39.96 15.491 ;
     RECT  13.056 15.477 17.16 15.531 ;
     RECT  31.584 15.349 33.576 15.531 ;
     RECT  45.648 14.827 45.816 15.531 ;
     RECT  19.872 15.147 20.856 15.541 ;
     RECT  21.84 15.491 22.632 15.541 ;
     RECT  48.72 14.339 49.704 15.541 ;
     RECT  2.928 15.203 6.072 15.565 ;
     RECT  19.872 15.541 22.632 15.595 ;
     RECT  32.496 15.531 33.576 15.605 ;
     RECT  34.896 14.339 34.92 15.605 ;
     RECT  48.72 15.541 50.136 15.625 ;
     RECT  55.968 15.205 55.992 15.659 ;
     RECT  18.72 15.541 18.744 15.683 ;
     RECT  39.936 15.491 39.96 15.723 ;
     RECT  2.928 15.565 5.952 15.733 ;
     RECT  9.792 15.669 9.96 15.757 ;
     RECT  13.104 15.531 17.16 15.787 ;
     RECT  51.264 15.395 51.672 15.797 ;
     RECT  2.256 15.733 5.952 15.817 ;
     RECT  34.8 15.605 34.92 15.851 ;
     RECT  55.68 15.733 55.8 15.875 ;
     RECT  41.808 14.915 41.832 15.877 ;
     RECT  48.72 15.625 49.152 15.877 ;
     RECT  41.664 15.877 41.832 15.912 ;
     RECT  43.44 14.915 43.896 15.912 ;
     RECT  57.888 14.925 62.136 15.955 ;
     RECT  13.104 15.787 14.232 15.979 ;
     RECT  23.904 15.093 23.928 16.009 ;
     RECT  7.392 15.275 7.416 16.019 ;
     RECT  19.872 15.595 22.536 16.019 ;
     RECT  40.656 15.955 40.68 16.043 ;
     RECT  32.496 15.605 33.624 16.053 ;
     RECT  36.336 14.915 36.696 16.053 ;
     RECT  11.04 15.275 11.448 16.067 ;
     RECT  35.952 16.053 36.696 16.069 ;
     RECT  38.04 15.491 38.472 16.069 ;
     RECT  57.552 15.955 62.136 16.115 ;
     RECT  15.456 15.787 17.16 16.171 ;
     RECT  31.488 16.083 31.512 16.171 ;
     RECT  32.496 16.053 34.296 16.171 ;
     RECT  44.88 15.839 45.048 16.171 ;
     RECT  8.448 15.275 8.472 16.245 ;
     RECT  48.096 15.877 49.152 16.245 ;
     RECT  41.664 15.912 43.896 16.261 ;
     RECT  24 16.181 24.024 16.269 ;
     RECT  46.176 15.989 46.632 16.299 ;
     RECT  2.736 15.817 5.952 16.307 ;
     RECT  8.448 16.245 8.568 16.307 ;
     RECT  40.752 16.261 43.896 16.309 ;
     RECT  25.104 15.413 25.848 16.367 ;
     RECT  27.24 14.915 29.688 16.367 ;
     RECT  35.952 16.069 38.472 16.393 ;
     RECT  19.872 16.019 22.152 16.405 ;
     RECT  46.176 16.299 46.2 16.451 ;
     RECT  13.104 15.979 13.752 16.499 ;
     RECT  40.752 16.309 44.568 16.499 ;
     RECT  9.84 15.757 9.96 16.501 ;
     RECT  11.04 16.067 11.352 16.501 ;
     RECT  16.44 16.171 17.16 16.501 ;
     RECT  35.952 16.393 38.352 16.501 ;
     RECT  53.568 15.059 54.552 16.501 ;
     RECT  32.496 16.171 33.72 16.549 ;
     RECT  47.76 16.245 49.152 16.549 ;
     RECT  9.84 16.501 11.352 16.555 ;
     RECT  13.104 16.499 13.128 16.555 ;
     RECT  25.104 16.367 29.688 16.555 ;
     RECT  35.328 16.501 38.352 16.585 ;
     RECT  47.328 16.549 49.152 16.595 ;
     RECT  53.472 16.501 54.552 16.597 ;
     RECT  47.328 16.595 47.352 16.633 ;
     RECT  0.24 14.627 0.552 16.645 ;
     RECT  19.344 16.405 22.152 16.653 ;
     RECT  2.88 16.307 5.952 16.741 ;
     RECT  30.672 16.659 30.696 16.747 ;
     RECT  32.304 16.549 33.72 16.747 ;
     RECT  50.64 15.797 51.672 16.747 ;
     RECT  48.432 16.595 49.152 16.787 ;
     RECT  2.88 16.741 6.888 16.825 ;
     RECT  48.48 16.787 49.152 16.885 ;
     RECT  51.168 16.747 51.672 16.933 ;
     RECT  25.104 16.555 25.128 16.943 ;
     RECT  40.992 16.499 44.568 16.969 ;
     RECT  16.44 16.501 17.736 16.979 ;
     RECT  32.496 16.747 33.72 16.979 ;
     RECT  48.48 16.885 49.272 16.979 ;
     RECT  51.168 16.933 51.912 16.979 ;
     RECT  8.496 16.307 8.568 16.981 ;
     RECT  26.256 16.555 29.688 16.981 ;
     RECT  55.776 15.875 55.8 16.991 ;
     RECT  0.24 16.645 1.464 17.013 ;
     RECT  41.088 16.969 44.568 17.027 ;
     RECT  36.144 16.585 38.352 17.075 ;
     RECT  55.776 16.991 55.848 17.075 ;
     RECT  51.552 16.979 51.912 17.077 ;
     RECT  53.04 16.597 54.552 17.077 ;
     RECT  55.776 17.075 55.8 17.077 ;
     RECT  57.888 16.115 62.136 17.077 ;
     RECT  0.24 17.013 1.608 17.101 ;
     RECT  8.496 16.981 9.144 17.123 ;
     RECT  37.056 17.075 38.352 17.123 ;
     RECT  14.256 17.077 15.144 17.171 ;
     RECT  37.248 17.123 38.352 17.171 ;
     RECT  26.256 16.981 30.072 17.219 ;
     RECT  13.056 17.077 13.08 17.221 ;
     RECT  12.96 17.221 13.08 17.315 ;
     RECT  51.552 17.077 55.8 17.363 ;
     RECT  24.48 16.943 25.128 17.411 ;
     RECT  57.84 17.077 62.136 17.413 ;
     RECT  57.264 17.413 62.136 17.509 ;
     RECT  19.344 16.653 19.368 17.603 ;
     RECT  34.992 17.077 35.064 17.605 ;
     RECT  41.136 17.027 44.568 17.605 ;
     RECT  46.944 17.461 47.064 17.619 ;
     RECT  2.88 16.825 6.744 17.643 ;
     RECT  10.176 16.555 11.352 17.643 ;
     RECT  12.96 17.315 12.984 17.643 ;
     RECT  14.592 17.171 15.144 17.643 ;
     RECT  32.496 16.979 33.528 17.643 ;
     RECT  39.408 17.077 39.432 17.643 ;
     RECT  38.04 17.171 38.352 17.653 ;
     RECT  41.136 17.605 45.192 17.653 ;
     RECT  46.944 17.619 47.448 17.653 ;
     RECT  10.944 17.643 11.352 17.677 ;
     RECT  23.136 17.589 23.16 17.677 ;
     RECT  3.312 17.643 6.744 17.699 ;
     RECT  38.04 17.653 39.096 17.737 ;
     RECT  51.552 17.363 52.488 17.737 ;
     RECT  51.648 17.737 52.488 17.843 ;
     RECT  25.824 17.653 26.232 17.987 ;
     RECT  5.64 17.699 6.744 17.989 ;
     RECT  27.24 17.219 30.072 17.989 ;
     RECT  34.992 17.605 35.688 17.989 ;
     RECT  20.64 16.653 22.152 18.037 ;
     RECT  5.64 17.989 6.888 18.133 ;
     RECT  16.44 16.979 16.752 18.133 ;
     RECT  24.48 17.411 24.504 18.133 ;
     RECT  34.752 17.989 35.688 18.133 ;
     RECT  11.04 17.677 11.352 18.143 ;
     RECT  27.24 17.989 30.648 18.143 ;
     RECT  41.136 17.653 47.448 18.143 ;
     RECT  40.992 18.143 47.448 18.165 ;
     RECT  48.48 16.979 49.152 18.165 ;
     RECT  0.24 17.101 1.464 18.179 ;
     RECT  20.64 18.037 22.968 18.181 ;
     RECT  3.312 17.699 4.008 18.219 ;
     RECT  9.648 18.037 9.816 18.219 ;
     RECT  16.44 18.133 17.112 18.219 ;
     RECT  18.96 17.941 18.984 18.219 ;
     RECT  24.192 18.133 24.504 18.219 ;
     RECT  26.208 17.987 26.232 18.229 ;
     RECT  27.24 18.143 30.744 18.229 ;
     RECT  55.776 17.363 55.8 18.229 ;
     RECT  57.216 17.509 62.136 18.229 ;
     RECT  40.992 18.165 49.152 18.253 ;
     RECT  38.04 17.737 38.52 18.357 ;
     RECT  52.464 17.843 52.488 18.371 ;
     RECT  55.776 18.229 62.136 18.411 ;
     RECT  15.168 17.653 15.336 18.419 ;
     RECT  37.632 18.357 38.52 18.421 ;
     RECT  53.568 17.363 54.792 18.421 ;
     RECT  55.776 18.411 56.616 18.421 ;
     RECT  53.568 18.421 56.616 18.527 ;
     RECT  40.992 18.253 47.4 18.539 ;
     RECT  26.208 18.229 30.744 18.549 ;
     RECT  37.104 18.421 38.52 18.549 ;
     RECT  40.992 18.539 46.344 18.565 ;
     RECT  9.744 18.219 9.816 18.709 ;
     RECT  11.04 18.143 11.448 18.709 ;
     RECT  15.312 18.419 15.336 18.709 ;
     RECT  16.44 18.219 16.752 18.709 ;
     RECT  40.56 18.565 46.344 18.709 ;
     RECT  26.208 18.549 31.368 18.731 ;
     RECT  36.912 18.549 38.52 18.731 ;
     RECT  3.984 18.219 4.008 18.757 ;
     RECT  39.6 18.709 46.344 18.795 ;
     RECT  34.656 18.133 35.688 18.805 ;
     RECT  26.208 18.731 30.408 18.829 ;
     RECT  40.56 18.795 45.768 18.852 ;
     RECT  9.744 18.709 11.448 18.933 ;
     RECT  32.496 17.643 32.952 18.933 ;
     RECT  34.416 18.805 35.688 18.933 ;
     RECT  37.632 18.731 38.52 18.933 ;
     RECT  20.064 18.181 22.968 18.963 ;
     RECT  28.608 18.829 30.408 18.987 ;
     RECT  32.496 18.933 35.688 18.987 ;
     RECT  51.648 18.933 51.672 18.997 ;
     RECT  9.744 18.933 11.688 19.021 ;
     RECT  32.496 18.987 33.768 19.021 ;
     RECT  20.016 18.963 22.968 19.045 ;
     RECT  3.984 18.757 4.584 19.093 ;
     RECT  5.64 18.133 6.984 19.093 ;
     RECT  9.744 19.021 11.544 19.115 ;
     RECT  25.056 18.661 25.176 19.125 ;
     RECT  26.208 18.829 27.552 19.125 ;
     RECT  3.984 19.093 6.984 19.155 ;
     RECT  19.392 19.045 22.968 19.179 ;
     RECT  2.736 18.997 2.76 19.189 ;
     RECT  25.056 19.125 27.552 19.189 ;
     RECT  0.24 18.179 1.368 19.243 ;
     RECT  40.56 18.852 43.896 19.243 ;
     RECT  45.024 18.852 45.768 19.273 ;
     RECT  32.496 19.021 33.576 19.285 ;
     RECT  24.624 19.189 27.552 19.317 ;
     RECT  2.736 19.189 2.904 19.371 ;
     RECT  19.92 19.179 22.968 19.371 ;
     RECT  24.528 19.317 27.552 19.371 ;
     RECT  31.536 19.285 33.576 19.371 ;
     RECT  35.856 19.237 36.552 19.371 ;
     RECT  0.24 19.243 0.696 19.379 ;
     RECT  8.16 19.295 8.184 19.379 ;
     RECT  15.312 18.709 16.752 19.381 ;
     RECT  48.48 18.253 49.152 19.381 ;
     RECT  52.992 18.527 56.616 19.381 ;
     RECT  57.6 18.411 62.136 19.381 ;
     RECT  47.376 18.539 47.4 19.445 ;
     RECT  48.48 19.381 49.272 19.445 ;
     RECT  20.064 19.371 22.968 19.475 ;
     RECT  24.528 19.371 25.8 19.475 ;
     RECT  9.744 19.115 11.352 19.488 ;
     RECT  51.504 18.997 51.672 19.509 ;
     RECT  52.992 19.381 62.136 19.509 ;
     RECT  20.592 19.475 22.968 19.525 ;
     RECT  14.496 19.381 16.752 19.603 ;
     RECT  9.744 19.488 9.864 19.621 ;
     RECT  13.008 19.141 13.032 19.621 ;
     RECT  31.536 19.371 31.56 19.627 ;
     RECT  51.504 19.509 62.136 19.627 ;
     RECT  37.632 18.933 38.616 19.679 ;
     RECT  53.568 19.627 62.136 19.691 ;
     RECT  14.448 19.603 16.752 19.701 ;
     RECT  40.56 19.243 41.016 19.715 ;
     RECT  20.592 19.525 23.4 19.755 ;
     RECT  3.984 19.155 7.032 19.765 ;
     RECT  47.376 19.445 49.272 19.765 ;
     RECT  3.216 19.765 7.032 19.811 ;
     RECT  32.64 19.371 33.576 19.811 ;
     RECT  50.256 19.381 50.28 19.811 ;
     RECT  1.68 19.317 1.704 19.859 ;
     RECT  4.752 19.811 7.032 19.861 ;
     RECT  23.568 19.795 23.592 19.883 ;
     RECT  40.992 19.715 41.016 19.883 ;
     RECT  13.008 19.621 13.08 19.893 ;
     RECT  3.216 19.811 3.24 19.947 ;
     RECT  0.24 19.379 0.552 19.957 ;
     RECT  9.216 19.621 9.864 19.957 ;
     RECT  14.448 19.701 17.256 19.957 ;
     RECT  18.24 19.909 18.264 19.957 ;
     RECT  55.536 19.691 62.136 19.957 ;
     RECT  35.856 19.371 36.408 20.015 ;
     RECT  14.448 19.957 18.264 20.021 ;
     RECT  0.144 19.957 0.552 20.051 ;
     RECT  4.752 19.861 7.416 20.051 ;
     RECT  9.072 19.957 9.864 20.051 ;
     RECT  14.256 20.021 18.264 20.085 ;
     RECT  34.896 20.015 36.408 20.099 ;
     RECT  55.536 19.957 62.184 20.099 ;
     RECT  14.256 20.085 18.792 20.109 ;
     RECT  11.04 19.488 11.352 20.115 ;
     RECT  12.912 19.893 13.08 20.149 ;
     RECT  14.256 20.109 17.64 20.149 ;
     RECT  20.592 19.755 22.344 20.195 ;
     RECT  47.328 19.765 49.272 20.197 ;
     RECT  20.64 20.195 22.248 20.203 ;
     RECT  18.768 20.109 18.792 20.243 ;
     RECT  11.04 20.115 11.64 20.307 ;
     RECT  47.328 20.197 50.136 20.331 ;
     RECT  24.912 19.475 25.8 20.339 ;
     RECT  45.024 19.273 45.144 20.437 ;
     RECT  47.328 20.331 50.04 20.437 ;
     RECT  46.704 20.437 50.04 20.459 ;
     RECT  25.104 20.339 25.8 20.469 ;
     RECT  26.976 19.371 27.552 20.469 ;
     RECT  35.76 20.099 36.408 20.469 ;
     RECT  37.632 19.679 39.384 20.469 ;
     RECT  7.968 20.389 7.992 20.473 ;
     RECT  32.64 19.811 33.192 20.499 ;
     RECT  4.752 20.051 6.84 20.523 ;
     RECT  46.704 20.459 49.656 20.523 ;
     RECT  53.568 19.691 54.552 20.531 ;
     RECT  11.04 20.307 11.784 20.533 ;
     RECT  12.912 20.149 17.64 20.533 ;
     RECT  35.76 20.469 39.384 20.533 ;
     RECT  42.096 19.243 43.896 20.557 ;
     RECT  42.096 20.557 42.12 20.579 ;
     RECT  46.704 20.523 49.272 20.587 ;
     RECT  35.76 20.533 39.96 20.617 ;
     RECT  51.504 19.627 52.2 20.661 ;
     RECT  25.104 20.469 27.552 20.691 ;
     RECT  28.608 18.987 29.688 20.691 ;
     RECT  47.328 20.587 49.272 20.715 ;
     RECT  19.008 20.533 19.56 20.771 ;
     RECT  11.04 20.533 17.64 20.779 ;
     RECT  19.008 20.771 19.464 20.779 ;
     RECT  43.296 20.557 43.896 20.869 ;
     RECT  45.024 20.437 45.384 20.869 ;
     RECT  36.384 20.617 39.96 20.917 ;
     RECT  51.504 20.661 53.016 20.917 ;
     RECT  54.144 20.531 54.552 20.917 ;
     RECT  55.536 20.099 62.136 20.917 ;
     RECT  48.048 20.715 49.272 20.963 ;
     RECT  54.144 20.917 62.136 20.971 ;
     RECT  56.064 20.971 62.136 21.011 ;
     RECT  9.12 20.051 9.864 21.013 ;
     RECT  11.04 20.779 14.232 21.023 ;
     RECT  10.944 21.023 14.232 21.099 ;
     RECT  25.104 20.691 29.688 21.109 ;
     RECT  32.16 20.499 33.192 21.109 ;
     RECT  36.384 20.917 40.152 21.109 ;
     RECT  43.296 20.869 45.384 21.109 ;
     RECT  51.312 20.917 53.016 21.109 ;
     RECT  57.216 21.011 62.136 21.109 ;
     RECT  36.384 21.109 41.016 21.157 ;
     RECT  57.216 21.109 62.184 21.157 ;
     RECT  51.168 21.109 53.016 21.163 ;
     RECT  3.936 21.109 3.96 21.203 ;
     RECT  8.496 21.013 9.864 21.227 ;
     RECT  5.64 20.523 6.84 21.237 ;
     RECT  36.384 21.157 41.112 21.299 ;
     RECT  20.64 20.203 22.152 21.301 ;
     RECT  23.904 20.485 23.976 21.301 ;
     RECT  19.008 20.779 19.032 21.331 ;
     RECT  52.272 21.163 53.016 21.395 ;
     RECT  10.944 21.099 13.224 21.459 ;
     RECT  32.016 21.109 33.192 21.459 ;
     RECT  5.64 21.237 6.936 21.541 ;
     RECT  48.72 20.963 49.272 21.541 ;
     RECT  14.208 21.099 14.232 21.547 ;
     RECT  31.584 21.459 33.192 21.547 ;
     RECT  57.216 21.157 62.28 21.547 ;
     RECT  32.352 21.547 33.192 21.551 ;
     RECT  34.416 21.301 34.44 21.551 ;
     RECT  25.104 21.109 29.832 21.587 ;
     RECT  4.224 21.541 6.936 21.621 ;
     RECT  4.224 21.621 6.984 21.637 ;
     RECT  8.496 21.227 9.24 21.637 ;
     RECT  48.72 21.541 50.136 21.637 ;
     RECT  51.168 21.163 51.288 21.637 ;
     RECT  43.296 21.109 45.912 21.651 ;
     RECT  10.32 21.459 13.224 21.675 ;
     RECT  4.224 21.637 9.24 21.683 ;
     RECT  15.408 20.779 17.64 21.683 ;
     RECT  56.064 21.011 56.088 21.683 ;
     RECT  41.088 21.299 41.112 21.685 ;
     RECT  43.296 21.651 46.488 21.685 ;
     RECT  54.144 20.971 54.84 21.685 ;
     RECT  20.64 21.301 23.976 21.739 ;
     RECT  42.288 21.685 46.488 21.739 ;
     RECT  52.272 21.395 52.296 21.739 ;
     RECT  36.384 21.299 39.864 21.769 ;
     RECT  48.72 21.637 51.288 21.769 ;
     RECT  10.32 21.675 13.176 21.779 ;
     RECT  25.104 21.587 26.232 21.779 ;
     RECT  32.352 21.551 34.44 21.803 ;
     RECT  41.088 21.685 41.304 21.867 ;
     RECT  42.288 21.739 46.44 21.877 ;
     RECT  4.224 21.683 5.952 21.923 ;
     RECT  0.24 20.051 0.552 21.925 ;
     RECT  6.96 21.683 9.24 21.931 ;
     RECT  15.984 21.683 17.64 21.941 ;
     RECT  18.672 21.331 19.032 21.941 ;
     RECT  34.992 21.877 35.016 21.971 ;
     RECT  36.384 21.769 39.192 21.995 ;
     RECT  42.192 21.877 46.44 21.995 ;
     RECT  0.24 21.925 1.128 22.009 ;
     RECT  15.984 21.941 19.032 22.009 ;
     RECT  27.24 21.587 29.832 22.021 ;
     RECT  31.104 21.877 31.224 22.021 ;
     RECT  20.64 21.739 20.856 22.035 ;
     RECT  0.24 22.009 0.552 22.069 ;
     RECT  3.12 21.445 3.144 22.069 ;
     RECT  48.72 21.769 50.712 22.069 ;
     RECT  20.592 22.035 20.856 22.123 ;
     RECT  2.256 22.069 3.144 22.165 ;
     RECT  21.84 21.739 23.976 22.165 ;
     RECT  36.384 21.995 38.472 22.165 ;
     RECT  42.768 21.995 46.44 22.201 ;
     RECT  57.408 21.547 62.28 22.213 ;
     RECT  1.536 22.165 3.192 22.251 ;
     RECT  12.528 21.779 13.176 22.251 ;
     RECT  21.84 22.165 24.504 22.251 ;
     RECT  44.928 22.201 46.44 22.251 ;
     RECT  53.376 21.685 54.84 22.251 ;
     RECT  16.44 22.009 19.032 22.261 ;
     RECT  7.968 21.931 9.24 22.355 ;
     RECT  12.528 22.251 12.936 22.355 ;
     RECT  16.44 22.261 19.224 22.355 ;
     RECT  57.408 22.213 62.328 22.379 ;
     RECT  12.528 22.355 12.744 22.403 ;
     RECT  16.44 22.355 19.176 22.451 ;
     RECT  40.992 22.261 41.016 22.451 ;
     RECT  10.32 21.779 11.352 22.453 ;
     RECT  47.952 22.069 50.712 22.453 ;
     RECT  16.44 22.451 17.736 22.499 ;
     RECT  52.128 22.419 52.152 22.507 ;
     RECT  55.584 22.419 55.608 22.507 ;
     RECT  10.128 22.453 11.352 22.537 ;
     RECT  32.352 21.803 33.864 22.537 ;
     RECT  58.368 22.379 62.328 22.595 ;
     RECT  47.712 22.453 50.712 22.741 ;
     RECT  0.144 22.069 0.552 22.835 ;
     RECT  57.072 22.741 57.096 22.885 ;
     RECT  58.704 22.595 62.328 22.885 ;
     RECT  25.872 21.779 26.232 22.943 ;
     RECT  27.24 22.021 31.224 22.943 ;
     RECT  2.256 22.251 3.192 22.965 ;
     RECT  4.464 21.923 5.952 22.965 ;
     RECT  6.96 21.931 6.984 22.965 ;
     RECT  25.872 22.943 31.224 22.965 ;
     RECT  35.328 22.165 38.472 22.965 ;
     RECT  47.712 22.741 50.76 22.965 ;
     RECT  53.376 22.251 54.552 22.965 ;
     RECT  2.256 22.965 3.24 22.981 ;
     RECT  4.464 22.965 6.984 22.981 ;
     RECT  51.888 22.741 51.912 22.981 ;
     RECT  10.416 22.537 11.352 22.995 ;
     RECT  2.256 22.981 6.984 23.019 ;
     RECT  47.232 22.965 50.76 23.019 ;
     RECT  51.84 22.981 51.912 23.019 ;
     RECT  25.056 22.965 31.224 23.027 ;
     RECT  40.416 22.943 40.44 23.027 ;
     RECT  44.928 22.251 45.576 23.027 ;
     RECT  5.52 23.019 6.984 23.029 ;
     RECT  7.968 22.355 9.144 23.029 ;
     RECT  27.12 23.027 31.224 23.029 ;
     RECT  32.352 22.537 33.672 23.029 ;
     RECT  35.328 22.965 38.52 23.029 ;
     RECT  51.84 23.019 51.864 23.029 ;
     RECT  2.256 23.019 4.056 23.083 ;
     RECT  12.72 22.403 12.744 23.083 ;
     RECT  27.12 23.029 33.672 23.083 ;
     RECT  42.768 22.201 43.896 23.083 ;
     RECT  47.232 23.019 50.184 23.083 ;
     RECT  51.696 23.029 51.864 23.083 ;
     RECT  57.024 22.885 57.096 23.083 ;
     RECT  51.696 23.083 51.72 23.113 ;
     RECT  5.52 23.029 9.144 23.123 ;
     RECT  14.256 23.029 14.28 23.269 ;
     RECT  16.44 22.499 17.112 23.269 ;
     RECT  8.88 23.123 8.904 23.315 ;
     RECT  31.008 23.083 33.672 23.315 ;
     RECT  53.088 22.965 54.552 23.315 ;
     RECT  58.704 22.885 62.424 23.363 ;
     RECT  39.984 23.317 40.2 23.365 ;
     RECT  45.072 23.027 45.576 23.411 ;
     RECT  43.152 23.083 43.896 23.461 ;
     RECT  53.568 23.315 54.552 23.461 ;
     RECT  2.256 23.083 3.816 23.509 ;
     RECT  20.64 22.123 20.856 23.519 ;
     RECT  39.888 23.365 40.2 23.541 ;
     RECT  21.84 22.251 23.976 23.571 ;
     RECT  25.056 23.027 26.088 23.571 ;
     RECT  53.568 23.461 54.648 23.571 ;
     RECT  10.416 22.995 11.736 23.595 ;
     RECT  15.888 23.269 17.112 23.605 ;
     RECT  20.496 23.519 20.856 23.605 ;
     RECT  53.568 23.571 54.84 23.659 ;
     RECT  20.4 23.605 20.856 23.699 ;
     RECT  43.152 23.461 43.944 23.699 ;
     RECT  15.888 23.605 17.688 23.701 ;
     RECT  19.008 22.451 19.176 23.701 ;
     RECT  57.216 23.605 57.288 23.701 ;
     RECT  14.256 23.269 14.472 23.711 ;
     RECT  34.752 23.029 38.52 23.763 ;
     RECT  15.888 23.701 19.176 23.787 ;
     RECT  13.632 23.711 14.472 23.795 ;
     RECT  10.752 23.595 11.736 23.845 ;
     RECT  47.232 23.083 47.304 23.861 ;
     RECT  57.216 23.701 57.72 23.861 ;
     RECT  58.704 23.363 62.136 23.861 ;
     RECT  20.448 23.699 20.856 23.893 ;
     RECT  21.84 23.571 26.088 23.893 ;
     RECT  48.84 23.083 50.184 23.915 ;
     RECT  34.32 23.763 38.52 23.925 ;
     RECT  39.552 23.541 40.2 23.925 ;
     RECT  46.848 23.861 47.304 23.925 ;
     RECT  10.752 23.845 12.072 23.929 ;
     RECT  1.536 23.509 3.816 23.939 ;
     RECT  14.448 23.795 14.472 23.939 ;
     RECT  18.816 23.787 19.176 23.989 ;
     RECT  53.568 23.659 54.552 24.035 ;
     RECT  56.208 23.733 56.232 24.047 ;
     RECT  57.216 23.861 62.136 24.047 ;
     RECT  2.256 23.939 3.816 24.053 ;
     RECT  18.816 23.989 19.464 24.083 ;
     RECT  20.448 23.893 26.088 24.083 ;
     RECT  5.52 23.123 7.608 24.107 ;
     RECT  2.256 24.053 4.056 24.117 ;
     RECT  27.24 23.083 29.832 24.117 ;
     RECT  31.008 23.315 33.288 24.117 ;
     RECT  41.52 24.037 41.544 24.117 ;
     RECT  48.84 23.915 50.136 24.117 ;
     RECT  2.256 24.117 4.536 24.121 ;
     RECT  2.304 24.121 4.536 24.133 ;
     RECT  5.52 24.107 5.952 24.133 ;
     RECT  9.072 24.085 9.096 24.147 ;
     RECT  48.432 24.117 50.136 24.211 ;
     RECT  48.336 24.211 50.136 24.227 ;
     RECT  43.344 23.699 43.944 24.229 ;
     RECT  45.072 23.411 45.096 24.229 ;
     RECT  9.072 24.147 9.48 24.235 ;
     RECT  46.176 23.925 47.304 24.299 ;
     RECT  41.472 24.117 41.544 24.309 ;
     RECT  52.656 24.277 53.064 24.309 ;
     RECT  46.176 24.299 46.2 24.323 ;
     RECT  34.32 23.925 40.2 24.325 ;
     RECT  41.328 24.309 41.544 24.325 ;
     RECT  27.24 24.117 33.288 24.371 ;
     RECT  0.24 22.835 0.552 24.373 ;
     RECT  21.84 24.083 26.088 24.421 ;
     RECT  27.24 24.371 33.192 24.421 ;
     RECT  43.344 24.229 45.096 24.421 ;
     RECT  56.208 24.047 62.136 24.421 ;
     RECT  20.448 24.083 20.856 24.427 ;
     RECT  48.336 24.227 49.272 24.431 ;
     RECT  0.24 24.373 1.176 24.467 ;
     RECT  52.032 24.309 53.064 24.491 ;
     RECT  56.112 24.421 62.136 24.501 ;
     RECT  21.84 24.421 33.192 24.505 ;
     RECT  47.856 24.431 49.272 24.515 ;
     RECT  2.304 24.133 5.952 24.525 ;
     RECT  34.32 24.325 41.544 24.555 ;
     RECT  10.752 23.929 11.352 24.565 ;
     RECT  55.584 24.501 62.136 24.611 ;
     RECT  34.32 24.555 39.576 24.613 ;
     RECT  23.184 24.505 33.192 24.619 ;
     RECT  43.344 24.421 46.056 24.619 ;
     RECT  6.96 24.107 7.608 24.629 ;
     RECT  9.072 24.235 9.096 24.659 ;
     RECT  48.336 24.515 49.272 24.659 ;
     RECT  54.048 24.035 54.552 24.661 ;
     RECT  55.584 24.611 58.152 24.661 ;
     RECT  34.224 24.613 39.576 24.697 ;
     RECT  59.232 24.611 62.136 24.709 ;
     RECT  6.96 24.629 7.896 24.787 ;
     RECT  40.752 24.555 41.544 24.787 ;
     RECT  40.752 24.787 42.12 24.811 ;
     RECT  59.232 24.709 62.28 24.811 ;
     RECT  51.984 24.757 52.008 24.853 ;
     RECT  6.96 24.787 8.808 24.875 ;
     RECT  40.992 24.811 42.12 24.875 ;
     RECT  54.048 24.661 58.152 24.899 ;
     RECT  10.56 24.565 11.352 24.901 ;
     RECT  54.048 24.899 57.24 24.939 ;
     RECT  34.32 24.697 39.576 24.947 ;
     RECT  55.68 24.939 57.24 24.947 ;
     RECT  0.24 24.467 0.552 24.979 ;
     RECT  35.424 24.947 39.576 25.003 ;
     RECT  14.64 24.885 14.664 25.045 ;
     RECT  15.888 23.787 17.688 25.045 ;
     RECT  0.144 24.979 0.552 25.067 ;
     RECT  2.304 24.525 3.048 25.067 ;
     RECT  51.888 24.853 52.008 25.067 ;
     RECT  23.184 24.619 25.464 25.091 ;
     RECT  43.344 24.619 45.672 25.195 ;
     RECT  18.816 24.083 19.08 25.247 ;
     RECT  18.816 25.247 19.416 25.331 ;
     RECT  43.344 25.195 45.096 25.333 ;
     RECT  35.424 25.003 39.288 25.387 ;
     RECT  10.416 24.901 11.352 25.397 ;
     RECT  34.32 24.947 34.344 25.427 ;
     RECT  6.96 24.875 8.712 25.451 ;
     RECT  18.816 25.331 19.032 25.461 ;
     RECT  20.544 24.427 20.856 25.461 ;
     RECT  21.84 24.505 22.152 25.461 ;
     RECT  53.04 24.491 53.064 25.461 ;
     RECT  54.048 24.939 54.648 25.461 ;
     RECT  10.416 25.397 11.448 25.477 ;
     RECT  12.528 25.045 12.552 25.477 ;
     RECT  41.088 24.875 41.592 25.515 ;
     RECT  20.544 25.461 22.152 25.555 ;
     RECT  53.04 25.461 54.648 25.571 ;
     RECT  23.184 25.091 25.176 25.579 ;
     RECT  23.472 25.579 25.176 25.619 ;
     RECT  54 25.571 54.648 25.643 ;
     RECT  26.736 24.619 33.192 25.653 ;
     RECT  59.232 24.811 62.232 25.669 ;
     RECT  43.248 25.333 45.096 25.683 ;
     RECT  14.64 25.045 17.688 25.715 ;
     RECT  10.416 25.477 12.552 25.717 ;
     RECT  2.688 25.067 3.048 25.763 ;
     RECT  26.736 25.653 33.24 25.835 ;
     RECT  18.768 25.461 19.032 25.845 ;
     RECT  4.08 24.525 5.952 25.861 ;
     RECT  50.4 25.333 50.424 25.909 ;
     RECT  52.752 25.653 52.776 25.963 ;
     RECT  56.064 24.947 57.24 26.005 ;
     RECT  58.272 25.669 62.232 26.005 ;
     RECT  3.264 25.861 5.952 26.015 ;
     RECT  6.96 25.451 7.128 26.015 ;
     RECT  51.552 25.555 51.624 26.037 ;
     RECT  0.24 25.067 0.552 26.067 ;
     RECT  3.264 26.015 7.128 26.091 ;
     RECT  10.416 25.717 13.128 26.091 ;
     RECT  56.064 26.005 62.232 26.091 ;
     RECT  18.72 25.845 19.032 26.101 ;
     RECT  50.4 25.909 50.472 26.101 ;
     RECT  57.024 26.091 62.232 26.149 ;
     RECT  42.672 25.683 45.096 26.197 ;
     RECT  51.552 26.037 52.584 26.197 ;
     RECT  54.048 25.643 54.648 26.197 ;
     RECT  8.496 25.451 8.712 26.207 ;
     RECT  42.672 26.197 45.144 26.207 ;
     RECT  0.24 26.067 0.888 26.229 ;
     RECT  50.352 26.101 50.472 26.229 ;
     RECT  51.504 26.197 52.584 26.229 ;
     RECT  57.024 26.149 62.328 26.233 ;
     RECT  23.568 25.619 25.176 26.236 ;
     RECT  26.736 25.835 33.192 26.236 ;
     RECT  10.416 26.091 12.552 26.243 ;
     RECT  23.568 26.236 33.192 26.243 ;
     RECT  42.672 26.207 45.288 26.245 ;
     RECT  40.416 26.149 40.44 26.283 ;
     RECT  47.568 26.207 47.592 26.291 ;
     RECT  0.24 26.229 1.368 26.293 ;
     RECT  42.672 26.245 45.48 26.293 ;
     RECT  3.84 26.091 7.128 26.339 ;
     RECT  54.048 26.197 55.032 26.341 ;
     RECT  50.352 26.229 52.584 26.347 ;
     RECT  8.496 26.207 9.096 26.357 ;
     RECT  35.424 25.387 38.472 26.357 ;
     RECT  5.088 26.339 7.128 26.435 ;
     RECT  41.616 26.357 41.64 26.437 ;
     RECT  42.672 26.293 45.768 26.437 ;
     RECT  48.72 24.659 49.272 26.437 ;
     RECT  17.904 26.101 19.032 26.451 ;
     RECT  20.256 25.555 22.152 26.451 ;
     RECT  57.024 26.233 62.184 26.475 ;
     RECT  41.616 26.437 45.768 26.483 ;
     RECT  47.808 26.437 49.272 26.485 ;
     RECT  50.352 26.347 50.424 26.485 ;
     RECT  11.04 26.243 12.552 26.531 ;
     RECT  17.904 26.451 22.152 26.539 ;
     RECT  41.616 26.483 45.48 26.579 ;
     RECT  8.496 26.357 9.144 26.603 ;
     RECT  34.56 26.357 38.472 26.603 ;
     RECT  5.424 26.435 7.128 26.613 ;
     RECT  41.616 26.579 42.168 26.617 ;
     RECT  35.424 26.603 38.472 26.629 ;
     RECT  20.016 26.539 22.152 26.677 ;
     RECT  35.424 26.629 39.432 26.707 ;
     RECT  14.64 25.715 16.752 26.725 ;
     RECT  17.904 26.539 19.032 26.725 ;
     RECT  54.048 26.341 55.752 26.725 ;
     RECT  20.016 26.677 22.248 26.795 ;
     RECT  35.424 26.707 40.056 26.795 ;
     RECT  43.152 26.579 45.48 26.795 ;
     RECT  51.504 26.347 52.584 26.795 ;
     RECT  5.424 26.613 7.368 26.805 ;
     RECT  31.2 26.243 33.192 26.819 ;
     RECT  41.616 26.617 41.736 26.821 ;
     RECT  5.424 26.805 7.416 26.869 ;
     RECT  8.496 26.603 8.904 26.869 ;
     RECT  11.04 26.531 12.264 26.987 ;
     RECT  14.64 26.725 19.032 26.987 ;
     RECT  14.64 26.987 17.688 27.051 ;
     RECT  14.64 27.051 16.968 27.059 ;
     RECT  51.504 26.795 51.864 27.059 ;
     RECT  53.904 26.725 55.752 27.061 ;
     RECT  20.016 26.795 22.152 27.085 ;
     RECT  23.568 26.243 30.216 27.179 ;
     RECT  3.84 26.339 3.864 27.205 ;
     RECT  26.736 27.179 30.216 27.205 ;
     RECT  31.2 26.819 31.224 27.205 ;
     RECT  32.256 26.819 33.192 27.205 ;
     RECT  23.568 27.179 25.704 27.253 ;
     RECT  47.808 26.485 50.424 27.283 ;
     RECT  26.736 27.205 31.224 27.307 ;
     RECT  32.256 27.205 34.248 27.307 ;
     RECT  23.28 27.253 25.704 27.317 ;
     RECT  0.24 26.293 1.464 27.359 ;
     RECT  35.424 26.795 39.96 27.371 ;
     RECT  53.904 27.061 56.472 27.371 ;
     RECT  5.424 26.869 8.904 27.443 ;
     RECT  14.64 27.059 15.384 27.445 ;
     RECT  0.24 27.359 1.704 27.539 ;
     RECT  59.184 26.475 62.184 27.541 ;
     RECT  19.008 26.987 19.032 27.551 ;
     RECT  11.04 26.987 11.352 27.573 ;
     RECT  53.904 27.371 55.896 27.573 ;
     RECT  57.504 26.475 58.152 27.589 ;
     RECT  41.28 26.821 41.736 27.603 ;
     RECT  43.152 26.795 45.144 27.603 ;
     RECT  5.52 27.443 7.416 27.635 ;
     RECT  14.448 27.445 15.384 27.635 ;
     RECT  19.008 27.551 19.368 27.635 ;
     RECT  2.88 27.205 3.864 27.637 ;
     RECT  47.136 27.283 50.424 27.637 ;
     RECT  5.64 27.635 7.416 27.661 ;
     RECT  59.184 27.541 62.328 27.683 ;
     RECT  47.136 27.637 50.568 27.721 ;
     RECT  56.976 27.589 58.152 27.765 ;
     RECT  59.184 27.683 62.28 27.765 ;
     RECT  41.28 27.603 45.144 27.781 ;
     RECT  51.84 27.059 51.864 27.781 ;
     RECT  41.28 27.781 45.24 27.827 ;
     RECT  51.84 27.781 52.44 27.829 ;
     RECT  53.424 27.573 55.896 27.829 ;
     RECT  51.84 27.829 55.896 27.875 ;
     RECT  56.976 27.765 62.28 27.875 ;
     RECT  14.448 27.635 14.664 27.877 ;
     RECT  31.2 27.307 31.224 27.877 ;
     RECT  32.256 27.307 33.192 27.877 ;
     RECT  46.56 27.781 46.728 27.883 ;
     RECT  47.808 27.721 50.568 27.883 ;
     RECT  14.016 27.877 14.664 27.973 ;
     RECT  8.448 27.443 8.904 28.117 ;
     RECT  47.904 27.883 50.568 28.117 ;
     RECT  56.976 27.875 58.152 28.211 ;
     RECT  19.008 27.635 19.032 28.309 ;
     RECT  20.64 27.085 22.152 28.309 ;
     RECT  41.28 27.827 41.736 28.309 ;
     RECT  26.736 27.307 29.832 28.355 ;
     RECT  10.08 27.573 11.352 28.357 ;
     RECT  2.256 27.637 3.864 28.371 ;
     RECT  18.912 28.309 19.032 28.371 ;
     RECT  8.448 28.117 9.048 28.405 ;
     RECT  10.08 28.357 11.448 28.405 ;
     RECT  16.44 27.059 16.968 28.405 ;
     RECT  35.424 27.371 39.576 28.405 ;
     RECT  0.24 27.539 0.936 28.453 ;
     RECT  2.256 28.371 4.392 28.459 ;
     RECT  8.448 28.405 11.448 28.459 ;
     RECT  46.704 27.883 46.728 28.489 ;
     RECT  2.256 28.459 3.864 28.547 ;
     RECT  9.744 28.459 11.448 28.643 ;
     RECT  41.184 28.309 41.736 28.643 ;
     RECT  10.08 28.643 11.448 28.739 ;
     RECT  0.144 28.453 0.936 28.741 ;
     RECT  59.232 27.875 62.28 28.779 ;
     RECT  0.144 28.741 1.176 28.789 ;
     RECT  2.256 28.547 2.28 28.789 ;
     RECT  16.44 28.405 17.16 28.837 ;
     RECT  18.336 28.371 19.032 28.837 ;
     RECT  20.016 28.309 22.152 28.837 ;
     RECT  42.768 27.827 45.24 28.837 ;
     RECT  47.904 28.117 50.712 28.837 ;
     RECT  51.84 27.875 55.848 28.837 ;
     RECT  47.904 28.837 55.848 28.883 ;
     RECT  31.2 27.877 33.192 28.885 ;
     RECT  34.224 27.307 34.248 28.885 ;
     RECT  59.232 28.779 62.184 28.885 ;
     RECT  59.184 28.885 62.184 28.907 ;
     RECT  35.424 28.405 40.152 28.931 ;
     RECT  8.448 28.459 8.568 28.933 ;
     RECT  50.496 28.883 55.848 28.933 ;
     RECT  13.104 27.973 14.664 28.979 ;
     RECT  5.64 27.661 7.368 28.981 ;
     RECT  10.464 28.739 11.448 28.981 ;
     RECT  16.44 28.837 22.152 28.981 ;
     RECT  26.928 28.355 29.832 28.981 ;
     RECT  31.104 28.885 34.248 28.981 ;
     RECT  35.424 28.931 39.624 28.981 ;
     RECT  50.496 28.933 55.896 29.027 ;
     RECT  8.352 28.933 8.568 29.035 ;
     RECT  10.464 28.981 12.024 29.039 ;
     RECT  13.104 28.979 13.128 29.039 ;
     RECT  59.184 28.907 62.136 29.077 ;
     RECT  5.52 28.981 7.368 29.087 ;
     RECT  8.352 29.035 8.52 29.087 ;
     RECT  47.904 28.883 49.152 29.123 ;
     RECT  50.544 29.027 55.896 29.133 ;
     RECT  26.928 28.981 34.248 29.163 ;
     RECT  40.896 28.981 40.92 29.171 ;
     RECT  10.464 29.039 13.128 29.219 ;
     RECT  59.136 29.077 62.136 29.219 ;
     RECT  16.32 28.981 22.152 29.227 ;
     RECT  50.544 29.133 54.744 29.227 ;
     RECT  42.144 28.837 45.24 29.257 ;
     RECT  13.104 29.219 13.128 29.291 ;
     RECT  57.024 28.211 58.152 29.301 ;
     RECT  59.136 29.219 62.088 29.301 ;
     RECT  0.144 28.789 2.28 29.305 ;
     RECT  16.32 29.227 17.256 29.317 ;
     RECT  23.184 27.317 25.704 29.355 ;
     RECT  42.912 29.257 45.24 29.365 ;
     RECT  32.496 29.163 34.248 29.429 ;
     RECT  35.328 28.981 39.624 29.429 ;
     RECT  32.496 29.429 39.624 29.497 ;
     RECT  32.496 29.497 35.352 29.517 ;
     RECT  3.408 28.547 3.864 29.587 ;
     RECT  32.496 29.517 34.344 29.611 ;
     RECT  3.36 29.587 3.864 29.615 ;
     RECT  5.52 29.087 8.52 29.615 ;
     RECT  55.776 29.133 55.896 29.621 ;
     RECT  57.024 29.301 62.088 29.621 ;
     RECT  46.8 29.557 46.824 29.685 ;
     RECT  46.56 29.685 46.824 29.803 ;
     RECT  50.544 29.227 54.552 29.843 ;
     RECT  55.776 29.621 62.088 29.867 ;
     RECT  18.288 29.227 22.152 29.995 ;
     RECT  50.592 29.843 54.552 29.995 ;
     RECT  23.328 29.355 25.704 30.069 ;
     RECT  26.928 29.163 31.272 30.123 ;
     RECT  14.256 28.979 14.664 30.133 ;
     RECT  18.816 29.995 22.152 30.133 ;
     RECT  36.384 29.497 39.624 30.133 ;
     RECT  48.432 29.123 49.152 30.133 ;
     RECT  13.632 30.133 14.664 30.181 ;
     RECT  3.36 29.615 8.52 30.191 ;
     RECT  31.248 30.123 31.272 30.191 ;
     RECT  32.496 29.611 33.768 30.191 ;
     RECT  10.464 29.219 11.976 30.197 ;
     RECT  13.632 30.181 14.808 30.217 ;
     RECT  23.328 30.069 25.8 30.217 ;
     RECT  47.52 30.133 49.152 30.227 ;
     RECT  56.832 29.867 62.088 30.251 ;
     RECT  42.912 29.365 45.576 30.261 ;
     RECT  0.144 29.305 1.368 30.275 ;
     RECT  50.64 29.995 54.552 30.275 ;
     RECT  52.08 30.275 54.552 30.323 ;
     RECT  14.448 30.217 14.808 30.325 ;
     RECT  15.792 29.317 17.256 30.325 ;
     RECT  36.384 30.133 40.2 30.325 ;
     RECT  42.912 30.261 46.008 30.325 ;
     RECT  53.568 30.323 54.552 30.325 ;
     RECT  55.728 30.197 55.752 30.325 ;
     RECT  3.36 30.191 8.712 30.355 ;
     RECT  13.344 30.261 13.368 30.371 ;
     RECT  56.928 30.251 62.088 30.371 ;
     RECT  58.128 30.371 62.088 30.373 ;
     RECT  58.128 30.373 62.184 30.456 ;
     RECT  2.784 30.355 8.712 30.469 ;
     RECT  56.928 30.371 57.144 30.507 ;
     RECT  2.784 30.469 8.76 30.517 ;
     RECT  23.712 30.217 25.8 30.517 ;
     RECT  26.928 30.123 29.784 30.517 ;
     RECT  36.384 30.325 41.064 30.517 ;
     RECT  42.48 30.325 46.008 30.563 ;
     RECT  31.248 30.191 33.768 30.645 ;
     RECT  2.784 30.517 8.904 30.661 ;
     RECT  31.248 30.645 34.344 30.733 ;
     RECT  58.128 30.456 62.232 30.739 ;
     RECT  58.128 30.739 62.52 30.757 ;
     RECT  23.712 30.517 29.784 30.763 ;
     RECT  50.64 30.275 50.664 30.763 ;
     RECT  36.384 30.517 41.16 30.803 ;
     RECT  35.328 29.517 35.352 30.867 ;
     RECT  36.384 30.803 38.352 30.867 ;
     RECT  58.128 30.757 62.76 30.891 ;
     RECT  10.464 30.197 12.024 30.901 ;
     RECT  2.784 30.661 9.048 30.949 ;
     RECT  35.328 30.867 38.352 30.955 ;
     RECT  10.224 30.901 12.024 30.959 ;
     RECT  2.256 30.949 9.048 31.019 ;
     RECT  2.256 31.019 3.864 31.033 ;
     RECT  10.032 30.959 12.024 31.043 ;
     RECT  10.224 31.043 12.024 31.093 ;
     RECT  10.224 31.093 12.216 31.141 ;
     RECT  10.224 31.141 12.552 31.275 ;
     RECT  24.144 30.763 29.784 31.285 ;
     RECT  52.08 30.323 52.392 31.315 ;
     RECT  51.12 31.315 52.392 31.333 ;
     RECT  10.464 31.275 12.552 31.339 ;
     RECT  47.52 30.227 47.736 31.343 ;
     RECT  18.816 30.133 22.344 31.349 ;
     RECT  24.144 31.285 29.832 31.369 ;
     RECT  58.128 30.891 62.232 31.369 ;
     RECT  14.448 30.325 17.256 31.379 ;
     RECT  53.568 30.325 55.752 31.379 ;
     RECT  26.88 31.369 29.832 31.381 ;
     RECT  31.248 30.733 33.768 31.381 ;
     RECT  51.12 31.333 52.488 31.403 ;
     RECT  42.72 30.563 46.008 31.413 ;
     RECT  47.328 31.343 47.736 31.413 ;
     RECT  0.144 30.275 1.224 31.427 ;
     RECT  51.984 31.403 52.488 31.467 ;
     RECT  42.72 31.413 47.736 31.501 ;
     RECT  57.024 30.507 57.144 31.507 ;
     RECT  0.24 31.427 1.224 31.523 ;
     RECT  48.84 30.227 49.152 31.525 ;
     RECT  18.816 31.349 22.968 31.531 ;
     RECT  52.32 31.467 52.488 31.583 ;
     RECT  14.448 31.379 16.752 31.595 ;
     RECT  57.024 31.507 58.056 31.595 ;
     RECT  39.504 30.803 41.16 31.621 ;
     RECT  42.72 31.501 46.2 31.669 ;
     RECT  53.568 31.379 54.984 31.669 ;
     RECT  35.328 30.955 35.352 31.717 ;
     RECT  26.88 31.381 33.768 31.763 ;
     RECT  42.288 31.669 46.2 31.801 ;
     RECT  35.136 31.717 35.352 31.851 ;
     RECT  42.288 31.801 45.96 31.851 ;
     RECT  18.816 31.531 22.344 31.907 ;
     RECT  3.504 31.033 3.864 31.915 ;
     RECT  35.232 31.851 35.352 31.919 ;
     RECT  36.384 30.955 38.352 31.919 ;
     RECT  57.024 31.595 57.576 31.919 ;
     RECT  2.256 31.033 2.28 31.955 ;
     RECT  48.72 31.525 49.152 31.957 ;
     RECT  56.448 31.919 57.576 31.993 ;
     RECT  10.464 31.339 12.312 32.013 ;
     RECT  52.32 31.583 52.536 32.013 ;
     RECT  10.464 32.013 12.024 32.043 ;
     RECT  43.44 31.851 45.96 32.043 ;
     RECT  18.816 31.907 22.248 32.051 ;
     RECT  35.232 31.919 38.352 32.117 ;
     RECT  39.504 31.621 41.256 32.117 ;
     RECT  56.448 31.993 57.048 32.171 ;
     RECT  5.184 31.019 9.048 32.211 ;
     RECT  53.52 31.669 54.984 32.245 ;
     RECT  5.04 32.211 9.048 32.299 ;
     RECT  35.232 32.117 41.256 32.309 ;
     RECT  48.72 31.957 49.272 32.341 ;
     RECT  57.024 32.171 57.048 32.427 ;
     RECT  5.64 32.299 9.048 32.437 ;
     RECT  24.144 31.369 25.464 32.437 ;
     RECT  59.232 31.369 62.232 32.485 ;
     RECT  48.72 32.341 50.088 32.491 ;
     RECT  3.84 31.915 3.864 32.501 ;
     RECT  47.28 31.501 47.736 32.521 ;
     RECT  59.232 32.485 62.328 32.533 ;
     RECT  2.832 32.495 2.856 32.579 ;
     RECT  59.088 32.533 62.328 32.619 ;
     RECT  18.816 32.051 22.152 32.629 ;
     RECT  26.928 31.763 33.768 32.757 ;
     RECT  35.232 32.309 41.88 32.771 ;
     RECT  14.448 31.595 14.808 32.851 ;
     RECT  26.928 32.757 33.912 32.867 ;
     RECT  24.144 32.437 25.656 32.869 ;
     RECT  52.8 32.245 54.984 32.915 ;
     RECT  3.84 32.501 4.488 32.917 ;
     RECT  35.232 32.771 38.352 32.917 ;
     RECT  5.64 32.437 9.24 32.949 ;
     RECT  10.464 32.043 11.592 32.949 ;
     RECT  23.952 32.869 25.656 32.953 ;
     RECT  18.768 32.629 22.152 32.979 ;
     RECT  13.008 32.677 13.08 33.013 ;
     RECT  14.304 32.851 14.808 33.013 ;
     RECT  43.44 32.043 44.904 33.013 ;
     RECT  2.88 32.917 4.488 33.059 ;
     RECT  10.416 32.949 11.592 33.059 ;
     RECT  48.72 32.491 49.272 33.059 ;
     RECT  43.344 33.013 44.904 33.061 ;
     RECT  2.88 33.059 3.96 33.067 ;
     RECT  18.432 32.979 22.152 33.067 ;
     RECT  45.936 32.043 45.96 33.077 ;
     RECT  13.008 33.013 14.808 33.097 ;
     RECT  14.64 33.097 14.808 33.205 ;
     RECT  15.84 31.595 16.752 33.205 ;
     RECT  59.088 32.619 62.136 33.205 ;
     RECT  18.528 33.067 22.152 33.235 ;
     RECT  45.936 33.077 46.2 33.251 ;
     RECT  52.8 32.915 54.744 33.251 ;
     RECT  43.056 33.061 44.904 33.259 ;
     RECT  10.464 33.059 11.592 33.269 ;
     RECT  14.64 33.205 16.752 33.289 ;
     RECT  13.008 33.097 13.56 33.299 ;
     RECT  18.528 33.235 22.536 33.323 ;
     RECT  34.752 32.917 38.352 33.323 ;
     RECT  5.64 32.949 9.288 33.347 ;
     RECT  46.176 33.251 46.2 33.349 ;
     RECT  46.176 33.349 46.44 33.395 ;
     RECT  18.528 33.323 22.152 33.539 ;
     RECT  57.744 33.205 62.136 33.541 ;
     RECT  52.464 33.269 52.632 33.587 ;
     RECT  34.752 33.323 36.408 33.683 ;
     RECT  57.648 33.541 62.136 33.685 ;
     RECT  2.88 33.067 3.864 33.781 ;
     RECT  10.464 33.269 11.736 33.781 ;
     RECT  13.008 33.299 13.08 33.781 ;
     RECT  39.504 32.771 40.632 33.811 ;
     RECT  2.544 33.781 3.864 33.827 ;
     RECT  18.768 33.539 22.152 33.827 ;
     RECT  24.144 32.953 25.656 33.827 ;
     RECT  35.088 33.683 36.408 33.827 ;
     RECT  26.928 32.867 33.144 33.845 ;
     RECT  43.056 33.259 43.896 33.845 ;
     RECT  56.016 32.629 56.04 33.845 ;
     RECT  57.648 33.685 62.184 33.845 ;
     RECT  2.544 33.827 2.568 33.875 ;
     RECT  10.464 33.781 13.08 33.875 ;
     RECT  53.76 33.251 54.744 33.875 ;
     RECT  37.392 33.323 38.352 33.925 ;
     RECT  39.408 33.811 40.632 33.925 ;
     RECT  56.016 33.845 62.184 34.021 ;
     RECT  56.016 34.021 62.376 34.067 ;
     RECT  26.928 33.845 33.816 34.115 ;
     RECT  57.024 34.067 62.376 34.115 ;
     RECT  37.392 33.925 40.632 34.117 ;
     RECT  41.856 32.771 41.88 34.117 ;
     RECT  58.368 34.115 62.376 34.163 ;
     RECT  0.24 31.523 0.552 34.165 ;
     RECT  42.864 33.845 43.896 34.309 ;
     RECT  44.88 33.259 44.904 34.309 ;
     RECT  15.84 33.289 16.752 34.323 ;
     RECT  5.64 33.347 9.048 34.357 ;
     RECT  14.64 33.289 14.664 34.387 ;
     RECT  15.84 34.323 17.448 34.411 ;
     RECT  53.76 33.875 54.648 34.421 ;
     RECT  2.112 34.357 2.28 34.451 ;
     RECT  13.056 33.875 13.08 34.453 ;
     RECT  14.4 34.387 14.664 34.453 ;
     RECT  26.928 34.115 33.144 34.453 ;
     RECT  15.84 34.411 17.16 34.501 ;
     RECT  47.712 32.521 47.736 34.501 ;
     RECT  48.72 33.059 49.152 34.501 ;
     RECT  37.392 34.117 41.88 34.539 ;
     RECT  46.416 33.395 46.44 34.597 ;
     RECT  50.736 34.309 50.76 34.597 ;
     RECT  42.864 34.309 44.904 34.613 ;
     RECT  52.992 34.421 54.648 34.707 ;
     RECT  42.864 34.613 45.144 34.731 ;
     RECT  46.272 34.597 46.728 34.731 ;
     RECT  3.84 33.827 3.864 34.741 ;
     RECT  5.64 34.357 9.144 34.741 ;
     RECT  10.464 33.875 11.784 34.741 ;
     RECT  47.712 34.501 49.152 34.741 ;
     RECT  0.24 34.165 0.648 34.787 ;
     RECT  26.832 34.453 33.144 34.789 ;
     RECT  52.848 34.707 54.648 34.789 ;
     RECT  43.008 34.731 45.144 34.795 ;
     RECT  35.424 33.827 36.408 34.847 ;
     RECT  37.392 34.539 39.912 34.847 ;
     RECT  13.056 34.453 14.664 34.869 ;
     RECT  15.696 34.501 17.16 34.869 ;
     RECT  56.016 34.067 56.04 34.899 ;
     RECT  5.64 34.741 11.784 34.923 ;
     RECT  40.992 34.539 41.88 34.931 ;
     RECT  57.024 34.115 57.048 34.931 ;
     RECT  18.816 33.827 22.152 34.933 ;
     RECT  24.144 33.827 25.224 34.933 ;
     RECT  26.208 34.789 33.144 34.933 ;
     RECT  52.464 34.789 54.648 34.933 ;
     RECT  24.144 34.933 33.144 34.981 ;
     RECT  18.336 34.933 22.152 35.061 ;
     RECT  13.056 34.869 17.16 35.077 ;
     RECT  52.176 34.933 54.648 35.123 ;
     RECT  10.464 34.923 11.784 35.125 ;
     RECT  13.008 35.077 17.16 35.125 ;
     RECT  2.256 34.451 2.28 35.179 ;
     RECT  23.952 34.981 33.144 35.243 ;
     RECT  41.232 34.931 41.88 35.243 ;
     RECT  52.944 35.123 54.648 35.269 ;
     RECT  55.632 34.899 56.04 35.269 ;
     RECT  58.368 34.163 62.232 35.269 ;
     RECT  10.464 35.125 17.16 35.307 ;
     RECT  3.84 34.741 3.96 35.317 ;
     RECT  47.712 34.741 49.56 35.317 ;
     RECT  50.736 34.597 51.192 35.317 ;
     RECT  26.208 35.243 33.144 35.381 ;
     RECT  34.224 35.317 34.248 35.381 ;
     RECT  47.712 35.317 51.336 35.401 ;
     RECT  35.424 34.847 39.912 35.459 ;
     RECT  5.64 34.923 9.048 35.461 ;
     RECT  26.208 35.381 34.248 35.469 ;
     RECT  47.712 35.401 50.712 35.469 ;
     RECT  34.176 35.469 34.248 35.475 ;
     RECT  35.424 35.459 39.816 35.475 ;
     RECT  34.176 35.475 39.816 35.507 ;
     RECT  18.336 35.061 22.68 35.509 ;
     RECT  23.952 35.243 24.984 35.509 ;
     RECT  46.416 34.731 46.728 35.509 ;
     RECT  47.712 35.469 50.52 35.509 ;
     RECT  43.008 34.795 44.904 35.555 ;
     RECT  34.176 35.507 39.528 35.563 ;
     RECT  46.416 35.509 50.52 35.563 ;
     RECT  43.296 35.555 44.904 35.593 ;
     RECT  13.872 35.307 17.16 35.667 ;
     RECT  18.336 35.509 24.984 35.667 ;
     RECT  52.944 35.269 56.04 35.691 ;
     RECT  58.032 35.269 62.232 35.691 ;
     RECT  13.872 35.667 24.984 35.795 ;
     RECT  5.376 35.461 9.048 35.797 ;
     RECT  58.032 35.691 62.184 35.819 ;
     RECT  13.872 35.795 17.688 35.843 ;
     RECT  52.944 35.691 54.792 35.843 ;
     RECT  5.088 35.797 9.048 35.845 ;
     RECT  10.464 35.307 12.264 35.883 ;
     RECT  58.032 35.819 62.136 35.883 ;
     RECT  41.856 35.243 41.88 35.941 ;
     RECT  46.416 35.563 50.232 35.947 ;
     RECT  18.72 35.795 24.984 35.987 ;
     RECT  43.344 35.593 44.904 35.987 ;
     RECT  44.88 35.987 44.904 35.989 ;
     RECT  46.416 35.947 46.728 36.085 ;
     RECT  55.872 35.691 56.04 36.115 ;
     RECT  0.24 34.787 0.552 36.243 ;
     RECT  2.304 35.845 2.328 36.243 ;
     RECT  0.24 36.243 2.328 36.331 ;
     RECT  14.064 35.843 17.688 36.331 ;
     RECT  18.768 35.987 24.984 36.405 ;
     RECT  26.208 35.469 33.144 36.405 ;
     RECT  3.84 35.317 4.008 36.435 ;
     RECT  4.992 35.845 9.048 36.435 ;
     RECT  3.84 36.435 9.048 36.459 ;
     RECT  47.712 35.947 50.232 36.515 ;
     RECT  18.768 36.405 33.144 36.517 ;
     RECT  34.176 35.563 34.2 36.517 ;
     RECT  46.128 36.085 46.728 36.523 ;
     RECT  18.768 36.517 34.2 36.553 ;
     RECT  18.816 36.553 34.2 36.587 ;
     RECT  55.872 36.115 56.568 36.597 ;
     RECT  58.032 35.883 58.056 36.597 ;
     RECT  53.04 35.843 54.792 36.709 ;
     RECT  55.872 36.597 58.056 36.709 ;
     RECT  51.6 36.709 51.624 36.805 ;
     RECT  53.04 36.709 58.056 36.851 ;
     RECT  51.456 36.805 51.624 36.853 ;
     RECT  2.16 36.331 2.328 36.883 ;
     RECT  35.424 35.563 39.528 36.917 ;
     RECT  40.56 36.435 40.584 36.917 ;
     RECT  53.136 36.851 58.056 36.917 ;
     RECT  59.136 35.883 62.136 36.917 ;
     RECT  53.136 36.917 62.184 36.947 ;
     RECT  26.208 36.587 34.2 36.949 ;
     RECT  41.856 35.941 42.168 36.959 ;
     RECT  43.344 35.987 43.896 36.959 ;
     RECT  2.16 36.883 2.52 36.971 ;
     RECT  47.712 36.515 49.272 36.971 ;
     RECT  10.464 35.883 12.024 36.997 ;
     RECT  26.208 36.949 34.248 36.997 ;
     RECT  35.424 36.917 40.584 36.997 ;
     RECT  41.856 36.959 43.896 36.997 ;
     RECT  44.88 35.989 45.048 36.997 ;
     RECT  46.704 36.523 46.728 36.997 ;
     RECT  47.712 36.971 49.152 36.997 ;
     RECT  53.568 36.947 62.184 37.035 ;
     RECT  10.464 36.997 12.504 37.045 ;
     RECT  26.208 36.997 40.584 37.045 ;
     RECT  41.856 36.997 45.048 37.045 ;
     RECT  50.832 36.853 51.624 37.075 ;
     RECT  46.704 36.997 49.152 37.104 ;
     RECT  50.832 37.075 51.72 37.139 ;
     RECT  51.696 37.139 51.72 37.163 ;
     RECT  10.464 37.045 12.648 37.237 ;
     RECT  10.464 37.237 13.368 37.331 ;
     RECT  26.208 37.045 45.72 37.331 ;
     RECT  31.104 37.331 45.72 37.379 ;
     RECT  31.104 37.379 39.96 37.389 ;
     RECT  31.104 37.389 39.912 37.523 ;
     RECT  3.84 36.459 4.488 37.535 ;
     RECT  5.64 36.459 9.048 37.535 ;
     RECT  53.568 37.035 57.624 37.547 ;
     RECT  58.608 37.035 62.184 37.557 ;
     RECT  18.816 36.587 25.128 37.573 ;
     RECT  26.208 37.331 30.072 37.573 ;
     RECT  53.568 37.547 54.936 37.581 ;
     RECT  14.736 36.331 17.688 37.619 ;
     RECT  10.464 37.331 12.504 37.621 ;
     RECT  31.104 37.523 39.528 37.645 ;
     RECT  39.408 37.645 39.528 37.667 ;
     RECT  41.856 37.379 45.72 37.675 ;
     RECT  58.608 37.557 62.232 37.715 ;
     RECT  3.84 37.535 9.048 38.003 ;
     RECT  42.96 37.675 45.72 38.005 ;
     RECT  46.704 37.104 46.728 38.005 ;
     RECT  31.104 37.645 38.352 38.051 ;
     RECT  47.712 37.104 49.152 38.101 ;
     RECT  2.16 36.971 2.328 38.133 ;
     RECT  10.272 37.621 12.504 38.149 ;
     RECT  58.608 37.715 62.184 38.157 ;
     RECT  47.712 38.101 49.848 38.187 ;
     RECT  3.84 38.003 4.584 38.195 ;
     RECT  2.16 38.133 2.712 38.221 ;
     RECT  10.128 38.149 12.504 38.251 ;
     RECT  42.96 38.005 46.728 38.315 ;
     RECT  51.312 38.111 51.336 38.389 ;
     RECT  43.008 38.315 46.728 38.413 ;
     RECT  47.712 38.187 49.752 38.443 ;
     RECT  15.408 37.619 17.688 38.453 ;
     RECT  18.816 37.573 30.072 38.453 ;
     RECT  51.312 38.389 51.912 38.473 ;
     RECT  2.16 38.221 2.52 38.507 ;
     RECT  41.856 37.675 41.88 38.517 ;
     RECT  15.408 38.453 30.072 38.541 ;
     RECT  56.016 37.547 57.624 38.571 ;
     RECT  51.312 38.473 51.576 38.581 ;
     RECT  53.76 37.581 54.936 38.645 ;
     RECT  56.016 38.571 56.424 38.645 ;
     RECT  13.68 38.197 14.232 38.675 ;
     RECT  51.072 38.581 51.576 38.675 ;
     RECT  2.16 38.507 2.184 38.677 ;
     RECT  59.04 38.157 62.184 38.677 ;
     RECT  51.216 38.675 51.576 38.699 ;
     RECT  43.008 38.413 46.68 38.713 ;
     RECT  43.344 38.713 46.68 38.733 ;
     RECT  59.04 38.677 62.616 38.763 ;
     RECT  59.04 38.763 62.184 38.819 ;
     RECT  15.408 38.541 17.688 38.867 ;
     RECT  15.408 38.867 16.872 39.061 ;
     RECT  31.104 38.051 34.008 39.061 ;
     RECT  35.088 38.051 38.352 39.061 ;
     RECT  1.824 38.677 2.184 39.109 ;
     RECT  59.04 38.819 61.944 39.123 ;
     RECT  3.84 38.195 4.248 39.157 ;
     RECT  5.64 38.003 9.048 39.157 ;
     RECT  39.504 37.667 39.528 39.187 ;
     RECT  40.992 38.517 41.88 39.187 ;
     RECT  53.76 38.645 56.424 39.187 ;
     RECT  18.816 38.541 30.072 39.205 ;
     RECT  31.104 39.061 38.352 39.205 ;
     RECT  1.728 39.109 2.184 39.211 ;
     RECT  10.464 38.251 12.504 39.211 ;
     RECT  58.896 39.123 61.944 39.211 ;
     RECT  3.84 39.157 4.44 39.251 ;
     RECT  13.68 38.675 13.752 39.251 ;
     RECT  39.504 39.187 41.88 39.275 ;
     RECT  53.328 39.187 56.424 39.275 ;
     RECT  18.816 39.205 38.352 39.289 ;
     RECT  1.824 39.211 2.184 39.347 ;
     RECT  13.68 39.251 13.704 39.395 ;
     RECT  41.04 39.275 41.88 39.395 ;
     RECT  57.648 39.013 57.768 39.637 ;
     RECT  39.504 39.275 39.912 39.699 ;
     RECT  51.552 38.699 51.576 39.699 ;
     RECT  53.76 39.275 56.424 39.733 ;
     RECT  31.104 39.289 38.352 39.781 ;
     RECT  39.408 39.699 39.912 39.781 ;
     RECT  43.344 38.733 45.768 39.781 ;
     RECT  50.736 39.699 51.576 39.781 ;
     RECT  13.344 39.637 13.368 39.787 ;
     RECT  50.736 39.781 52.536 39.787 ;
     RECT  5.64 39.157 9.096 39.829 ;
     RECT  41.664 39.395 41.88 39.829 ;
     RECT  47.712 38.443 49.152 39.865 ;
     RECT  5.088 39.829 9.096 39.915 ;
     RECT  31.104 39.781 39.912 39.915 ;
     RECT  2.16 39.347 2.184 39.923 ;
     RECT  51.552 39.787 52.536 39.923 ;
     RECT  14.832 39.061 16.872 39.925 ;
     RECT  5.232 39.915 9.096 39.971 ;
     RECT  3.84 39.251 3.864 39.983 ;
     RECT  5.64 39.971 9.096 39.989 ;
     RECT  47.712 39.865 47.736 39.989 ;
     RECT  48.84 39.865 49.152 40.053 ;
     RECT  53.76 39.733 56.52 40.069 ;
     RECT  57.648 39.637 58.152 40.069 ;
     RECT  2.256 39.989 2.28 40.077 ;
     RECT  18.816 39.289 29.688 40.117 ;
     RECT  10.464 39.211 11.592 40.147 ;
     RECT  43.296 39.781 45.768 40.211 ;
     RECT  14.688 39.925 17.256 40.339 ;
     RECT  14.544 40.339 17.256 40.403 ;
     RECT  53.76 40.069 58.152 40.403 ;
     RECT  3.408 39.983 3.864 40.405 ;
     RECT  31.104 39.915 38.352 40.405 ;
     RECT  59.184 39.211 61.944 40.405 ;
     RECT  18.48 40.117 29.688 40.427 ;
     RECT  10.416 40.147 11.592 40.437 ;
     RECT  52.416 39.923 52.536 40.491 ;
     RECT  59.184 40.405 62.088 40.491 ;
     RECT  41.664 39.829 42.216 40.501 ;
     RECT  59.184 40.491 61.944 40.547 ;
     RECT  10.272 40.437 11.592 40.549 ;
     RECT  57.408 40.403 58.152 40.595 ;
     RECT  41.616 40.501 42.216 40.597 ;
     RECT  46.944 39.989 47.736 40.597 ;
     RECT  41.04 40.597 42.216 40.629 ;
     RECT  43.296 40.211 45.624 40.629 ;
     RECT  10.224 40.549 11.592 40.633 ;
     RECT  39.408 39.915 39.912 40.741 ;
     RECT  41.04 40.629 45.624 40.741 ;
     RECT  0.24 36.331 0.552 40.757 ;
     RECT  5.64 39.989 9.192 40.845 ;
     RECT  30.768 40.405 38.352 40.875 ;
     RECT  5.64 40.845 9.144 40.931 ;
     RECT  13.056 40.837 13.08 40.991 ;
     RECT  14.544 40.403 16.968 40.991 ;
     RECT  46.848 40.597 47.736 41.003 ;
     RECT  59.184 40.547 61.56 41.029 ;
     RECT  13.056 40.991 16.968 41.067 ;
     RECT  18.48 40.427 25.368 41.067 ;
     RECT  0.24 40.757 1.128 41.075 ;
     RECT  13.68 41.067 16.968 41.075 ;
     RECT  5.64 40.931 9.096 41.077 ;
     RECT  47.712 41.003 47.736 41.077 ;
     RECT  48.84 40.053 49.272 41.077 ;
     RECT  52.416 40.491 52.44 41.077 ;
     RECT  2.304 40.405 3.864 41.171 ;
     RECT  10.272 40.633 11.592 41.171 ;
     RECT  47.712 41.077 49.272 41.195 ;
     RECT  26.448 40.427 29.688 41.205 ;
     RECT  39.408 40.741 45.624 41.269 ;
     RECT  52.272 41.077 52.44 41.269 ;
     RECT  26.448 41.205 30.072 41.293 ;
     RECT  55.968 40.403 56.04 41.413 ;
     RECT  2.304 41.171 3.432 41.459 ;
     RECT  31.104 40.875 38.352 41.461 ;
     RECT  39.408 41.269 45.672 41.461 ;
     RECT  26.448 41.293 30.024 41.485 ;
     RECT  57.6 40.595 58.152 41.485 ;
     RECT  53.76 40.403 54.552 41.491 ;
     RECT  55.536 41.413 56.04 41.491 ;
     RECT  51.6 41.269 52.44 41.567 ;
     RECT  53.76 41.491 56.04 41.567 ;
     RECT  51.6 41.567 56.04 41.579 ;
     RECT  31.104 41.461 45.672 41.589 ;
     RECT  46.704 41.509 46.728 41.589 ;
     RECT  51.6 41.579 54.888 41.699 ;
     RECT  51.6 41.699 54.648 41.771 ;
     RECT  57.6 41.485 57.624 41.781 ;
     RECT  3.408 41.459 3.432 41.835 ;
     RECT  57.312 41.781 57.624 41.845 ;
     RECT  59.136 41.029 61.56 41.893 ;
     RECT  26.448 41.485 29.976 41.939 ;
     RECT  59.136 41.893 61.896 41.973 ;
     RECT  2.304 41.459 2.328 42.037 ;
     RECT  5.136 41.077 9.096 42.037 ;
     RECT  18.48 41.067 25.272 42.037 ;
     RECT  2.112 42.037 2.328 42.083 ;
     RECT  10.464 41.171 11.592 42.085 ;
     RECT  2.112 42.083 2.136 42.101 ;
     RECT  18.48 42.037 25.32 42.101 ;
     RECT  26.448 41.939 29.688 42.101 ;
     RECT  51.6 41.771 54.552 42.101 ;
     RECT  58.704 41.973 61.896 42.133 ;
     RECT  13.872 41.075 16.968 42.165 ;
     RECT  18.48 42.101 29.688 42.165 ;
     RECT  31.104 41.589 46.728 42.165 ;
     RECT  47.712 41.195 49.152 42.165 ;
     RECT  4.512 42.037 9.096 42.179 ;
     RECT  58.704 42.133 62.232 42.179 ;
     RECT  1.92 42.101 2.136 42.189 ;
     RECT  57.024 41.845 57.624 42.253 ;
     RECT  10.464 42.085 12.552 42.277 ;
     RECT  13.872 42.165 29.688 42.277 ;
     RECT  31.104 42.165 49.152 42.323 ;
     RECT  57.024 42.253 57.528 42.323 ;
     RECT  4.512 42.179 4.536 42.325 ;
     RECT  51.216 42.101 54.552 42.335 ;
     RECT  31.104 42.323 46.872 42.419 ;
     RECT  47.952 42.323 49.152 42.485 ;
     RECT  50.16 42.085 50.184 42.485 ;
     RECT  51.168 42.335 54.552 42.505 ;
     RECT  56.016 41.579 56.04 42.579 ;
     RECT  31.104 42.419 45.048 42.603 ;
     RECT  3.456 42.613 3.48 42.661 ;
     RECT  4.464 42.325 4.536 42.661 ;
     RECT  58.8 42.179 62.232 42.671 ;
     RECT  46.128 42.419 46.872 42.731 ;
     RECT  3.456 42.661 4.536 42.745 ;
     RECT  58.8 42.671 62.376 42.755 ;
     RECT  10.464 42.277 29.688 42.765 ;
     RECT  13.104 42.765 25.176 42.795 ;
     RECT  2.112 42.189 2.136 42.803 ;
     RECT  4.512 42.745 4.536 42.803 ;
     RECT  13.104 42.795 17.112 42.829 ;
     RECT  51.888 42.505 54.552 42.869 ;
     RECT  55.728 42.579 56.04 42.869 ;
     RECT  51.888 42.869 56.04 42.933 ;
     RECT  57.024 42.323 57.384 42.933 ;
     RECT  13.104 42.829 16.872 42.987 ;
     RECT  47.952 42.485 50.184 42.995 ;
     RECT  50.16 42.995 50.184 42.997 ;
     RECT  58.8 42.755 61.896 43.115 ;
     RECT  50.16 42.997 50.712 43.187 ;
     RECT  51.888 42.933 57.384 43.187 ;
     RECT  26.256 42.765 29.688 43.189 ;
     RECT  47.952 42.995 49.152 43.243 ;
     RECT  57.264 43.187 57.384 43.283 ;
     RECT  57.504 43.295 57.528 43.379 ;
     RECT  59.232 43.115 61.896 43.379 ;
     RECT  5.64 42.179 9.096 43.445 ;
     RECT  10.464 42.765 11.976 43.445 ;
     RECT  35.424 42.603 45.048 43.509 ;
     RECT  46.128 42.731 46.728 43.509 ;
     RECT  51.888 43.187 56.04 43.509 ;
     RECT  5.64 43.445 11.976 43.563 ;
     RECT  35.424 43.509 46.728 43.597 ;
     RECT  40.464 43.597 46.728 43.667 ;
     RECT  3.168 43.219 3.192 43.669 ;
     RECT  51.84 43.509 56.04 43.701 ;
     RECT  31.104 42.603 34.392 43.765 ;
     RECT  35.424 43.597 39.432 43.765 ;
     RECT  40.464 43.667 43.992 43.789 ;
     RECT  13.104 42.987 16.752 43.819 ;
     RECT  26.256 43.189 29.784 43.861 ;
     RECT  31.104 43.765 39.432 43.861 ;
     RECT  59.64 43.379 61.896 43.861 ;
     RECT  2.784 43.669 3.192 43.871 ;
     RECT  5.64 43.563 9.24 43.883 ;
     RECT  10.464 43.563 11.976 43.893 ;
     RECT  13.104 43.819 13.128 43.893 ;
     RECT  26.256 43.861 39.432 43.909 ;
     RECT  26.208 43.909 39.432 43.947 ;
     RECT  1.92 43.871 3.528 43.955 ;
     RECT  5.64 43.883 9.144 43.955 ;
     RECT  18.384 42.795 25.176 43.957 ;
     RECT  26.208 43.947 30.024 43.957 ;
     RECT  50.304 43.187 50.712 43.957 ;
     RECT  51.792 43.701 56.04 43.957 ;
     RECT  5.64 43.955 6.312 44.005 ;
     RECT  14.256 43.819 16.752 44.021 ;
     RECT  45.024 43.667 46.728 44.051 ;
     RECT  5.52 44.005 6.312 44.089 ;
     RECT  3.984 44.015 4.008 44.099 ;
     RECT  45.024 44.051 46.152 44.099 ;
     RECT  50.304 43.957 56.04 44.099 ;
     RECT  1.584 44.021 1.608 44.109 ;
     RECT  2.592 43.955 2.808 44.109 ;
     RECT  59.64 43.861 62.088 44.437 ;
     RECT  8.16 43.955 9.144 44.483 ;
     RECT  50.688 44.099 56.04 44.591 ;
     RECT  31.104 43.947 39.432 44.597 ;
     RECT  40.464 43.789 43.896 44.597 ;
     RECT  50.688 44.591 56.856 44.597 ;
     RECT  58.704 44.437 62.088 44.597 ;
     RECT  8.16 44.483 9.048 44.651 ;
     RECT  18.384 43.957 30.024 44.651 ;
     RECT  14.256 44.021 17.352 44.665 ;
     RECT  31.104 44.597 43.896 44.675 ;
     RECT  50.688 44.597 57.144 44.685 ;
     RECT  31.104 44.675 41.208 44.723 ;
     RECT  58.704 44.597 62.184 44.819 ;
     RECT  50.688 44.685 57 44.867 ;
     RECT  14.352 44.665 17.352 44.965 ;
     RECT  18.384 44.651 29.784 44.965 ;
     RECT  14.352 44.965 29.784 45.059 ;
     RECT  10.464 43.893 13.128 45.139 ;
     RECT  48.72 43.243 49.152 45.143 ;
     RECT  42.24 44.675 43.896 45.157 ;
     RECT  45.264 44.099 45.768 45.157 ;
     RECT  48.48 45.143 49.152 45.157 ;
     RECT  10.464 45.139 13.272 45.227 ;
     RECT  48.48 45.157 49.56 45.301 ;
     RECT  50.688 44.867 56.472 45.301 ;
     RECT  14.352 45.059 25.416 45.355 ;
     RECT  58.704 44.819 62.088 45.493 ;
     RECT  47.328 45.139 47.352 45.541 ;
     RECT  48.48 45.301 56.472 45.541 ;
     RECT  47.328 45.541 56.472 45.547 ;
     RECT  2.784 44.109 2.808 45.599 ;
     RECT  42.24 45.157 45.768 45.599 ;
     RECT  47.328 45.547 54.696 45.599 ;
     RECT  58.128 45.493 62.088 45.635 ;
     RECT  8.208 44.651 9.048 45.651 ;
     RECT  58.416 45.635 62.088 45.675 ;
     RECT  58.416 45.675 58.44 45.683 ;
     RECT  26.448 45.059 29.784 45.685 ;
     RECT  42.24 45.599 54.696 45.731 ;
     RECT  7.728 45.651 9.048 45.739 ;
     RECT  15.456 45.355 25.416 45.739 ;
     RECT  14.352 45.355 14.376 45.803 ;
     RECT  10.464 45.227 11.976 45.817 ;
     RECT  56.016 45.547 56.472 45.829 ;
     RECT  42.24 45.731 51.384 45.867 ;
     RECT  2.784 45.599 3 45.877 ;
     RECT  2.784 45.877 3.336 45.923 ;
     RECT  18.48 45.739 25.416 46.021 ;
     RECT  26.448 45.685 29.832 46.021 ;
     RECT  42.24 45.867 47.688 46.029 ;
     RECT  34.368 44.723 41.208 46.117 ;
     RECT  42.24 46.029 47.352 46.117 ;
     RECT  56.016 45.829 56.52 46.175 ;
     RECT  34.368 46.117 47.352 46.187 ;
     RECT  5.64 44.089 6.264 46.197 ;
     RECT  31.104 44.723 33.384 46.197 ;
     RECT  48.84 45.867 51.384 46.251 ;
     RECT  52.416 45.731 54.696 46.259 ;
     RECT  30.912 46.197 33.384 46.261 ;
     RECT  5.64 46.197 6.312 46.285 ;
     RECT  13.248 45.227 13.272 46.291 ;
     RECT  13.152 46.291 13.272 46.309 ;
     RECT  18.48 46.021 29.832 46.453 ;
     RECT  30.816 46.261 33.384 46.453 ;
     RECT  34.368 46.187 44.232 46.453 ;
     RECT  15.456 45.739 17.304 46.499 ;
     RECT  59.52 45.675 62.088 46.559 ;
     RECT  3.312 45.923 3.336 46.581 ;
     RECT  4.56 46.165 4.584 46.581 ;
     RECT  59.52 46.559 62.184 46.643 ;
     RECT  3.312 46.581 4.584 46.699 ;
     RECT  3.312 46.699 3.864 46.739 ;
     RECT  18.48 46.453 44.232 46.739 ;
     RECT  45.36 46.187 47.352 46.763 ;
     RECT  7.872 45.739 9.048 46.789 ;
     RECT  13.152 46.309 13.752 46.789 ;
     RECT  7.872 46.789 9.096 46.803 ;
     RECT  18.48 46.739 35.4 46.835 ;
     RECT  10.464 45.817 11.688 46.883 ;
     RECT  15.456 46.499 17.016 47.059 ;
     RECT  56.016 46.175 56.904 47.077 ;
     RECT  57.888 47.029 57.912 47.077 ;
     RECT  48.84 46.251 50.952 47.087 ;
     RECT  13.152 46.789 13.848 47.125 ;
     RECT  14.928 47.059 17.016 47.125 ;
     RECT  7.44 46.803 9.096 47.187 ;
     RECT  13.056 47.125 17.016 47.211 ;
     RECT  13.056 47.211 13.704 47.221 ;
     RECT  7.296 47.187 9.096 47.275 ;
     RECT  48.72 47.087 50.952 47.279 ;
     RECT  52.8 46.259 54.696 47.279 ;
     RECT  56.016 47.077 57.912 47.279 ;
     RECT  45.648 46.763 47.352 47.305 ;
     RECT  12.816 47.221 13.704 47.315 ;
     RECT  36.384 46.739 44.232 47.317 ;
     RECT  48.72 47.279 51.288 47.327 ;
     RECT  52.416 47.279 58.104 47.327 ;
     RECT  45.648 47.305 46.152 47.363 ;
     RECT  10.464 46.883 11.64 47.413 ;
     RECT  18.48 46.835 35.352 47.413 ;
     RECT  8.208 47.275 9.096 47.443 ;
     RECT  10.224 47.413 11.64 47.443 ;
     RECT  59.52 46.643 62.088 47.471 ;
     RECT  36.384 47.317 44.28 47.497 ;
     RECT  59.232 47.471 62.088 47.555 ;
     RECT  18.144 47.413 35.352 47.603 ;
     RECT  48.72 47.327 58.104 47.605 ;
     RECT  59.424 47.555 62.088 47.605 ;
     RECT  3.312 46.739 3.528 47.669 ;
     RECT  42.48 47.497 44.28 47.669 ;
     RECT  0.24 41.075 0.552 47.701 ;
     RECT  1.68 47.663 1.704 47.701 ;
     RECT  2.88 47.669 3.528 47.723 ;
     RECT  5.64 46.285 6.216 47.763 ;
     RECT  0.24 47.701 1.704 47.787 ;
     RECT  2.88 47.723 2.904 47.797 ;
     RECT  4.848 47.763 6.216 47.797 ;
     RECT  30.816 47.603 35.352 47.797 ;
     RECT  36.384 47.497 41.496 47.797 ;
     RECT  42.48 47.669 44.376 47.797 ;
     RECT  14.736 47.211 17.016 47.843 ;
     RECT  14.784 47.843 17.016 47.845 ;
     RECT  18.144 47.603 29.784 47.845 ;
     RECT  42.48 47.797 44.568 47.845 ;
     RECT  45.648 47.363 45.816 47.845 ;
     RECT  4.848 47.797 7.176 47.851 ;
     RECT  2.256 47.797 2.904 47.881 ;
     RECT  47.616 47.797 47.64 47.881 ;
     RECT  48.72 47.605 58.152 47.881 ;
     RECT  5.64 47.851 7.176 47.891 ;
     RECT  50.256 47.881 57.624 47.891 ;
     RECT  59.424 47.605 62.328 47.891 ;
     RECT  59.424 47.891 62.184 47.939 ;
     RECT  48.72 47.881 49.152 48.047 ;
     RECT  13.056 47.315 13.704 48.083 ;
     RECT  50.928 47.891 57.624 48.171 ;
     RECT  42.48 47.845 45.816 48.373 ;
     RECT  2.88 47.881 2.904 48.419 ;
     RECT  50.928 48.171 54.696 48.419 ;
     RECT  42.48 48.373 46.2 48.501 ;
     RECT  14.784 47.845 29.784 48.515 ;
     RECT  13.056 48.083 13.464 48.629 ;
     RECT  59.424 47.939 62.088 48.629 ;
     RECT  56.016 48.171 57.624 48.659 ;
     RECT  50.928 48.419 54.648 48.683 ;
     RECT  18.384 48.515 29.784 48.709 ;
     RECT  30.816 47.797 41.496 48.709 ;
     RECT  12.912 48.629 13.464 48.723 ;
     RECT  18.384 48.709 41.496 48.723 ;
     RECT  42.48 48.501 46.44 48.723 ;
     RECT  18.384 48.723 46.44 48.811 ;
     RECT  59.376 48.629 62.088 48.821 ;
     RECT  57.6 48.659 57.624 48.841 ;
     RECT  56.016 48.659 56.616 48.875 ;
     RECT  48.288 48.047 49.152 48.885 ;
     RECT  0.24 47.787 0.552 48.915 ;
     RECT  8.208 47.443 11.64 48.949 ;
     RECT  18.384 48.811 45.816 48.995 ;
     RECT  59.088 48.821 62.088 48.995 ;
     RECT  0.24 48.915 0.648 49.003 ;
     RECT  18.384 48.995 45.288 49.003 ;
     RECT  5.64 47.891 6.36 49.013 ;
     RECT  7.44 48.949 11.64 49.013 ;
     RECT  48.288 48.885 50.904 49.077 ;
     RECT  5.64 49.013 11.64 49.141 ;
     RECT  12.816 48.723 13.464 49.141 ;
     RECT  14.784 48.515 17.016 49.141 ;
     RECT  18.384 49.003 44.808 49.187 ;
     RECT  0.24 49.003 0.552 49.269 ;
     RECT  4.272 48.229 4.296 49.269 ;
     RECT  5.64 49.141 17.016 49.269 ;
     RECT  4.272 49.269 17.016 49.387 ;
     RECT  47.904 49.077 50.904 49.461 ;
     RECT  51.936 48.683 54.648 49.461 ;
     RECT  0.144 49.269 0.552 49.475 ;
     RECT  4.272 49.387 13.272 49.523 ;
     RECT  4.272 49.523 11.592 49.525 ;
     RECT  47.04 49.461 50.904 49.549 ;
     RECT  18.384 49.187 44.472 49.571 ;
     RECT  18.48 49.571 44.472 49.619 ;
     RECT  51.936 49.461 54.696 49.813 ;
     RECT  2.304 49.247 2.328 49.909 ;
     RECT  3.84 49.525 11.592 49.909 ;
     RECT  51.36 49.813 54.696 49.939 ;
     RECT  45.504 49.967 45.624 50.005 ;
     RECT  57.888 49.813 57.912 50.027 ;
     RECT  2.304 49.909 11.592 50.037 ;
     RECT  59.376 48.995 62.088 50.037 ;
     RECT  45.504 50.005 45.864 50.091 ;
     RECT  51.36 49.939 54.984 50.091 ;
     RECT  1.824 50.037 11.592 50.125 ;
     RECT  58.704 50.037 62.088 50.195 ;
     RECT  47.04 49.549 50.376 50.243 ;
     RECT  13.248 49.523 13.272 50.389 ;
     RECT  14.592 49.387 17.016 50.389 ;
     RECT  42.192 49.619 44.472 50.533 ;
     RECT  42.192 50.533 44.52 50.549 ;
     RECT  45.504 50.091 45.576 50.549 ;
     RECT  8.016 50.125 11.592 50.581 ;
     RECT  18.48 49.619 41.208 50.581 ;
     RECT  42.192 50.549 45.576 50.581 ;
     RECT  47.04 50.243 50.136 50.603 ;
     RECT  8.016 50.581 11.64 50.667 ;
     RECT  52.368 50.091 54.984 50.667 ;
     RECT  13.248 50.389 17.4 50.725 ;
     RECT  18.48 50.581 45.576 50.725 ;
     RECT  13.248 50.725 45.576 50.731 ;
     RECT  47.04 50.603 49.992 50.731 ;
     RECT  47.04 50.731 49.896 50.761 ;
     RECT  57.36 50.677 57.384 50.761 ;
     RECT  13.248 50.731 14.376 50.805 ;
     RECT  56.016 48.875 56.04 50.869 ;
     RECT  12.96 50.805 14.376 50.893 ;
     RECT  15.456 50.731 45.576 50.923 ;
     RECT  52.992 50.667 54.984 50.933 ;
     RECT  56.016 50.869 57 50.933 ;
     RECT  47.04 50.761 49.152 50.965 ;
     RECT  59.088 50.195 62.088 50.965 ;
     RECT  13.056 50.893 14.376 50.987 ;
     RECT  15.456 50.923 16.92 50.987 ;
     RECT  52.992 50.933 57 51.051 ;
     RECT  59.088 50.965 62.52 51.051 ;
     RECT  55.536 51.051 56.616 51.059 ;
     RECT  18.048 50.923 45.576 51.115 ;
     RECT  13.056 50.987 14.328 51.155 ;
     RECT  59.088 51.051 62.472 51.157 ;
     RECT  58.752 51.157 62.472 51.243 ;
     RECT  1.872 50.125 6.984 51.301 ;
     RECT  8.016 50.667 11.592 51.301 ;
     RECT  31.104 51.115 45.576 51.301 ;
     RECT  46.8 50.965 49.152 51.301 ;
     RECT  0.24 49.475 0.552 51.311 ;
     RECT  1.872 51.301 11.592 51.311 ;
     RECT  31.104 51.301 49.152 51.337 ;
     RECT  13.536 51.155 14.328 51.347 ;
     RECT  0.24 51.311 11.592 51.395 ;
     RECT  1.776 51.395 11.592 51.405 ;
     RECT  45.216 51.337 49.152 51.469 ;
     RECT  1.776 51.405 9.144 51.563 ;
     RECT  59.64 51.243 62.472 51.563 ;
     RECT  3.936 51.563 9.048 51.627 ;
     RECT  50.976 51.603 51 51.733 ;
     RECT  1.776 51.563 2.808 51.755 ;
     RECT  31.104 51.337 43.992 51.819 ;
     RECT  50.976 51.733 51.96 51.819 ;
     RECT  50.976 51.819 51.192 51.829 ;
     RECT  50.736 51.829 51.192 51.913 ;
     RECT  15.456 50.987 16.752 51.973 ;
     RECT  18.048 51.115 29.784 51.973 ;
     RECT  52.992 51.051 54.552 51.973 ;
     RECT  10.224 51.405 11.592 52.019 ;
     RECT  56.016 51.059 56.616 52.055 ;
     RECT  52.608 51.973 54.552 52.165 ;
     RECT  56.016 52.055 57.096 52.165 ;
     RECT  15.456 51.973 29.784 52.179 ;
     RECT  31.104 51.819 35.352 52.179 ;
     RECT  10.656 52.019 11.592 52.309 ;
     RECT  45.456 51.469 49.152 52.357 ;
     RECT  45.456 52.357 50.136 52.403 ;
     RECT  47.616 52.403 50.136 52.459 ;
     RECT  45.456 52.403 46.008 52.463 ;
     RECT  52.608 52.165 54.696 52.469 ;
     RECT  45.36 52.463 46.008 52.501 ;
     RECT  8.112 51.627 9.048 52.533 ;
     RECT  3.936 51.627 7.128 52.547 ;
     RECT  1.968 51.755 2.808 52.549 ;
     RECT  3.936 52.547 4.248 52.549 ;
     RECT  45.024 52.501 46.008 52.651 ;
     RECT  36.384 51.819 43.992 52.661 ;
     RECT  45.024 52.651 45.528 52.661 ;
     RECT  5.52 52.547 7.128 52.703 ;
     RECT  8.112 52.533 9.336 52.703 ;
     RECT  59.64 51.563 62.088 52.703 ;
     RECT  58.512 52.243 58.536 52.725 ;
     RECT  59.64 52.703 62.184 52.725 ;
     RECT  0.24 51.395 0.552 52.755 ;
     RECT  52.608 52.469 54.744 52.755 ;
     RECT  52.608 52.755 54.936 52.779 ;
     RECT  13.536 51.347 14.28 52.789 ;
     RECT  15.456 52.179 35.352 52.789 ;
     RECT  53.76 52.779 54.936 52.819 ;
     RECT  56.016 52.165 57.24 52.819 ;
     RECT  47.616 52.459 49.152 52.843 ;
     RECT  53.76 52.819 57.24 52.873 ;
     RECT  53.76 52.873 56.04 52.883 ;
     RECT  0.24 52.755 0.696 52.917 ;
     RECT  51.168 51.913 51.192 52.947 ;
     RECT  0.24 52.917 0.792 53.005 ;
     RECT  13.536 52.789 35.352 53.029 ;
     RECT  36.384 52.661 45.528 53.029 ;
     RECT  50.784 52.947 51.192 53.035 ;
     RECT  52.608 52.779 52.632 53.075 ;
     RECT  57.216 52.873 57.24 53.075 ;
     RECT  58.512 52.725 62.184 53.123 ;
     RECT  10.656 52.309 11.976 53.125 ;
     RECT  47.856 52.843 49.152 53.171 ;
     RECT  1.968 52.549 4.248 53.219 ;
     RECT  58.512 53.123 59.952 53.237 ;
     RECT  13.536 53.029 45.528 53.267 ;
     RECT  53.808 52.883 56.04 53.315 ;
     RECT  56.016 53.315 56.04 53.363 ;
     RECT  5.52 52.703 9.336 53.365 ;
     RECT  10.608 53.125 11.976 53.365 ;
     RECT  13.536 53.267 14.328 53.419 ;
     RECT  58.368 53.237 59.952 53.419 ;
     RECT  2.736 53.219 4.248 53.459 ;
     RECT  61.008 53.123 62.184 53.493 ;
     RECT  52.272 53.429 52.296 53.555 ;
     RECT  5.52 53.365 11.976 53.557 ;
     RECT  2.736 53.459 3.432 53.581 ;
     RECT  4.464 53.557 11.976 53.581 ;
     RECT  61.008 53.493 62.232 53.581 ;
     RECT  48.48 53.171 49.152 53.603 ;
     RECT  48.72 53.603 49.152 53.651 ;
     RECT  58.368 53.419 58.584 53.685 ;
     RECT  13.536 53.419 14.28 53.803 ;
     RECT  52.176 53.779 52.2 53.867 ;
     RECT  15.456 53.267 45.528 53.995 ;
     RECT  57.408 53.685 58.584 53.995 ;
     RECT  43.296 53.995 45.528 53.999 ;
     RECT  7.872 53.581 11.976 54.037 ;
     RECT  53.808 53.315 54.552 54.037 ;
     RECT  53.568 54.037 54.552 54.123 ;
     RECT  43.296 53.999 45.576 54.133 ;
     RECT  59.64 53.419 59.952 54.133 ;
     RECT  61.008 53.581 62.088 54.133 ;
     RECT  0.24 53.005 0.552 54.181 ;
     RECT  43.296 54.133 45.96 54.227 ;
     RECT  58.128 53.995 58.584 54.421 ;
     RECT  59.64 54.133 62.088 54.421 ;
     RECT  47.04 54.355 47.064 54.443 ;
     RECT  2.736 53.581 3.384 54.517 ;
     RECT  56.736 54.469 56.952 54.517 ;
     RECT  0.24 54.181 0.888 54.563 ;
     RECT  14.256 53.803 14.28 54.581 ;
     RECT  15.456 53.995 42.168 54.581 ;
     RECT  2.256 54.517 3.384 54.6 ;
     RECT  4.464 53.581 6.84 54.611 ;
     RECT  43.296 54.227 45.72 54.611 ;
     RECT  2.208 54.6 3.384 54.661 ;
     RECT  4.464 54.611 6.216 54.661 ;
     RECT  7.872 54.037 12.552 54.661 ;
     RECT  2.208 54.661 6.216 54.699 ;
     RECT  47.232 54.565 47.256 54.699 ;
     RECT  2.64 54.699 6.216 54.707 ;
     RECT  45.024 54.611 45.72 54.707 ;
     RECT  56.4 54.517 56.952 54.709 ;
     RECT  2.64 54.707 6.12 54.755 ;
     RECT  14.256 54.581 42.168 54.755 ;
     RECT  45.408 54.707 45.72 54.755 ;
     RECT  7.872 54.661 13.032 54.773 ;
     RECT  47.376 54.709 47.592 54.773 ;
     RECT  48.84 53.651 49.152 54.773 ;
     RECT  50.688 54.767 50.712 54.773 ;
     RECT  0.24 54.563 0.696 54.803 ;
     RECT  14.736 54.755 42.168 54.803 ;
     RECT  7.776 54.773 13.032 54.837 ;
     RECT  56.16 54.709 56.952 54.837 ;
     RECT  50.496 54.773 50.712 54.851 ;
     RECT  47.376 54.773 49.152 54.861 ;
     RECT  51.888 54.815 51.912 54.899 ;
     RECT  53.04 54.517 53.064 54.912 ;
     RECT  7.776 54.837 13.704 54.925 ;
     RECT  7.776 54.925 13.128 55.139 ;
     RECT  55.776 54.837 56.952 55.235 ;
     RECT  58.128 54.421 62.088 55.237 ;
     RECT  14.736 54.803 41.208 55.331 ;
     RECT  56.352 55.235 56.952 55.343 ;
     RECT  58.08 55.237 62.088 55.343 ;
     RECT  48.48 54.861 49.152 55.391 ;
     RECT  50.496 54.851 50.52 55.391 ;
     RECT  14.736 55.331 40.488 55.403 ;
     RECT  54.24 54.123 54.552 55.413 ;
     RECT  7.824 55.139 13.128 55.427 ;
     RECT  2.64 54.755 4.584 55.467 ;
     RECT  2.64 55.467 4.44 55.619 ;
     RECT  2.64 55.619 4.296 55.763 ;
     RECT  56.352 55.343 62.088 55.765 ;
     RECT  46.176 55.349 46.2 55.813 ;
     RECT  56.352 55.765 62.136 55.851 ;
     RECT  48.48 55.391 50.52 55.891 ;
     RECT  54.096 55.413 54.744 55.919 ;
     RECT  2.64 55.763 4.104 55.925 ;
     RECT  48.48 55.891 51.096 55.967 ;
     RECT  52.464 55.925 52.488 55.967 ;
     RECT  7.824 55.427 13.032 55.979 ;
     RECT  48.48 55.967 52.488 55.979 ;
     RECT  2.496 55.925 4.104 56.005 ;
     RECT  43.296 54.611 44.04 56.019 ;
     RECT  43.296 56.019 44.568 56.053 ;
     RECT  45.648 55.813 46.2 56.053 ;
     RECT  56.352 55.851 62.088 56.077 ;
     RECT  56.352 56.077 58.104 56.099 ;
     RECT  42.288 55.919 42.312 56.101 ;
     RECT  43.296 56.053 46.296 56.101 ;
     RECT  2.304 56.005 4.104 56.181 ;
     RECT  14.736 55.403 17.16 56.181 ;
     RECT  7.968 55.979 13.032 56.195 ;
     RECT  42.288 56.101 46.296 56.245 ;
     RECT  47.376 54.861 47.4 56.245 ;
     RECT  42.288 56.245 47.4 56.275 ;
     RECT  1.68 56.181 4.104 56.341 ;
     RECT  42.048 56.275 47.4 56.341 ;
     RECT  48.48 55.979 50.184 56.341 ;
     RECT  54.096 55.919 55.272 56.341 ;
     RECT  56.352 56.099 57.624 56.341 ;
     RECT  7.968 56.195 11.592 56.427 ;
     RECT  41.76 56.341 50.184 56.427 ;
     RECT  41.76 56.427 42.024 56.435 ;
     RECT  14.64 56.181 17.16 56.437 ;
     RECT  18.288 55.403 40.488 56.437 ;
     RECT  7.968 56.427 9.768 56.483 ;
     RECT  9.456 56.483 9.768 56.531 ;
     RECT  51.264 55.979 52.488 56.533 ;
     RECT  9.456 56.531 9.624 56.555 ;
     RECT  5.64 54.755 6.12 56.595 ;
     RECT  54.096 56.341 57.624 56.627 ;
     RECT  14.64 56.437 40.488 56.629 ;
     RECT  41.76 56.435 41.976 56.629 ;
     RECT  51.264 56.533 53.112 56.693 ;
     RECT  54.096 56.627 57.24 56.693 ;
     RECT  12.672 56.195 13.032 56.773 ;
     RECT  14.64 56.629 41.976 56.773 ;
     RECT  47.808 56.427 50.184 56.804 ;
     RECT  12.672 56.773 41.976 56.811 ;
     RECT  51.264 56.693 57.24 56.867 ;
     RECT  43.056 56.427 46.68 56.875 ;
     RECT  1.632 56.341 4.104 56.979 ;
     RECT  5.64 56.595 6.36 56.979 ;
     RECT  51.888 56.867 57.24 57.011 ;
     RECT  1.632 56.979 6.36 57.013 ;
     RECT  7.968 56.483 8.232 57.013 ;
     RECT  48.096 56.804 50.184 57.013 ;
     RECT  48.096 57.013 50.76 57.059 ;
     RECT  51.888 57.011 56.376 57.059 ;
     RECT  12.672 56.811 16.872 57.067 ;
     RECT  1.632 57.013 8.232 57.107 ;
     RECT  17.952 56.811 41.976 57.131 ;
     RECT  14.64 57.067 16.872 57.155 ;
     RECT  2.88 57.107 8.232 57.195 ;
     RECT  51.888 57.059 56.328 57.195 ;
     RECT  2.88 57.195 4.44 57.259 ;
     RECT  0.24 54.803 0.552 57.363 ;
     RECT  0.144 57.363 0.552 57.397 ;
     RECT  1.584 57.205 1.608 57.397 ;
     RECT  10.944 56.427 11.592 57.397 ;
     RECT  0.144 57.397 1.608 57.451 ;
     RECT  48.84 57.059 50.76 57.451 ;
     RECT  10.8 57.397 11.592 57.481 ;
     RECT  5.52 57.195 8.232 57.493 ;
     RECT  9.456 56.555 9.48 57.493 ;
     RECT  0.24 57.451 1.608 57.539 ;
     RECT  43.056 56.875 46.152 57.541 ;
     RECT  59.232 56.077 62.088 57.541 ;
     RECT  5.52 57.493 9.48 57.635 ;
     RECT  42.768 57.541 46.152 57.683 ;
     RECT  42.768 57.683 46.008 57.771 ;
     RECT  12.672 57.067 13.416 57.875 ;
     RECT  47.328 57.781 47.352 57.875 ;
     RECT  17.952 57.131 41.784 57.877 ;
     RECT  2.88 57.259 4.008 57.899 ;
     RECT  5.52 57.635 6.744 57.913 ;
     RECT  51.888 57.195 55.896 58.037 ;
     RECT  15.984 57.155 16.872 58.079 ;
     RECT  17.904 57.877 41.784 58.079 ;
     RECT  14.64 57.155 14.904 58.101 ;
     RECT  15.984 58.079 41.784 58.101 ;
     RECT  42.768 57.771 45.672 58.101 ;
     RECT  15.984 58.101 45.672 58.105 ;
     RECT  48.84 57.451 50.088 58.115 ;
     RECT  10.848 57.481 11.592 58.117 ;
     RECT  12.672 57.875 13.128 58.117 ;
     RECT  51.264 58.037 55.896 58.125 ;
     RECT  14.4 58.101 14.904 58.211 ;
     RECT  7.824 57.635 9.48 58.219 ;
     RECT  3.216 57.899 4.008 58.229 ;
     RECT  5.52 57.913 6.12 58.229 ;
     RECT  15.984 58.105 44.472 58.323 ;
     RECT  14.208 58.357 14.232 58.441 ;
     RECT  58.656 57.541 62.088 58.463 ;
     RECT  51.84 58.125 55.896 58.485 ;
     RECT  57.456 58.421 57.48 58.485 ;
     RECT  8.112 58.219 9.48 58.539 ;
     RECT  51.84 58.485 57.48 58.549 ;
     RECT  9.648 58.549 9.672 58.597 ;
     RECT  10.848 58.117 13.128 58.597 ;
     RECT  9.648 58.597 13.128 58.681 ;
     RECT  9.648 58.681 9.768 58.691 ;
     RECT  51.84 58.549 57.624 58.691 ;
     RECT  51.84 58.691 56.472 58.739 ;
     RECT  57.6 58.691 57.624 58.825 ;
     RECT  10.848 58.681 13.128 58.869 ;
     RECT  58.656 58.463 62.184 59.077 ;
     RECT  10.848 58.869 13.368 59.123 ;
     RECT  57.744 59.077 62.184 59.179 ;
     RECT  2.112 58.131 2.232 59.183 ;
     RECT  3.216 58.229 6.12 59.183 ;
     RECT  2.112 59.183 6.12 59.269 ;
     RECT  15.36 58.323 44.472 59.307 ;
     RECT  16.32 59.307 44.472 59.315 ;
     RECT  48.84 58.115 49.752 59.381 ;
     RECT  18.816 59.315 44.472 59.509 ;
     RECT  47.184 59.221 47.208 59.615 ;
     RECT  57.84 59.179 62.184 59.627 ;
     RECT  47.184 59.615 47.304 59.637 ;
     RECT  8.112 58.539 8.52 59.651 ;
     RECT  46.848 59.637 47.304 59.699 ;
     RECT  2.112 59.269 6.696 59.701 ;
     RECT  51.84 58.739 55.272 59.701 ;
     RECT  56.352 58.739 56.472 59.701 ;
     RECT  16.32 59.315 17.688 59.725 ;
     RECT  18.816 59.509 44.616 59.747 ;
     RECT  48.672 59.381 49.752 59.747 ;
     RECT  51.84 59.701 56.472 59.749 ;
     RECT  18.816 59.747 43.992 59.755 ;
     RECT  2.112 59.701 6.888 59.765 ;
     RECT  45.648 58.105 45.672 59.765 ;
     RECT  46.848 59.699 47.208 59.765 ;
     RECT  8.112 59.651 8.232 59.807 ;
     RECT  51.84 59.749 56.568 59.819 ;
     RECT  9.744 58.691 9.768 59.829 ;
     RECT  61.056 59.627 62.184 59.833 ;
     RECT  2.016 59.765 6.888 59.853 ;
     RECT  9.696 59.829 9.768 59.941 ;
     RECT  45.648 59.765 47.208 59.989 ;
     RECT  10.848 59.123 12.072 60.085 ;
     RECT  13.056 59.123 13.368 60.085 ;
     RECT  52.752 59.819 56.568 60.181 ;
     RECT  57.84 59.627 59.952 60.181 ;
     RECT  48.84 59.747 49.752 60.229 ;
     RECT  18.816 59.755 43.896 60.267 ;
     RECT  52.752 60.181 59.952 60.267 ;
     RECT  14.544 59.605 15.144 60.277 ;
     RECT  16.32 59.725 17.496 60.277 ;
     RECT  48.84 60.229 49.8 60.277 ;
     RECT  51.264 59.999 51.288 60.277 ;
     RECT  52.752 60.267 56.904 60.301 ;
     RECT  4.56 59.853 6.888 60.325 ;
     RECT  7.968 59.807 8.232 60.325 ;
     RECT  10.848 60.085 13.368 60.331 ;
     RECT  61.056 59.833 61.848 60.331 ;
     RECT  58.128 60.267 59.952 60.361 ;
     RECT  9.696 59.941 9.864 60.373 ;
     RECT  10.848 60.331 11.976 60.373 ;
     RECT  44.976 59.989 47.208 60.467 ;
     RECT  58.704 60.361 59.952 60.467 ;
     RECT  53.04 60.301 56.904 60.515 ;
     RECT  4.56 60.325 8.232 60.661 ;
     RECT  13.008 60.331 13.368 60.661 ;
     RECT  14.496 60.277 17.496 60.661 ;
     RECT  13.008 60.661 17.496 60.709 ;
     RECT  48.84 60.277 51.288 60.767 ;
     RECT  4.56 60.661 8.52 60.789 ;
     RECT  4.56 60.789 8.664 60.819 ;
     RECT  9.696 60.373 11.976 60.819 ;
     RECT  4.56 60.819 11.976 60.843 ;
     RECT  13.008 60.709 17.64 60.853 ;
     RECT  18.816 60.267 40.488 60.853 ;
     RECT  45.024 60.467 47.208 60.853 ;
     RECT  48.72 60.767 51.288 60.853 ;
     RECT  7.968 60.843 11.976 60.907 ;
     RECT  13.008 60.853 40.488 60.907 ;
     RECT  45.024 60.853 51.864 60.907 ;
     RECT  45.84 60.907 51.864 60.937 ;
     RECT  2.016 59.853 3.432 60.947 ;
     RECT  45.84 60.937 47.64 60.947 ;
     RECT  62.16 60.853 62.184 60.947 ;
     RECT  53.088 60.515 56.904 60.995 ;
     RECT  45.84 60.947 46.296 61.043 ;
     RECT  2.256 60.947 3.432 61.189 ;
     RECT  4.56 60.843 6.936 61.189 ;
     RECT  48.72 60.937 51.864 61.235 ;
     RECT  54.048 60.995 56.904 61.381 ;
     RECT  41.808 60.267 43.896 61.395 ;
     RECT  9.84 60.907 11.976 61.419 ;
     RECT  45.888 61.043 46.296 61.419 ;
     RECT  8.496 60.907 8.664 61.427 ;
     RECT  54.048 61.381 57.72 61.523 ;
     RECT  61.056 60.331 61.128 61.525 ;
     RECT  56.448 61.523 57.72 61.557 ;
     RECT  2.256 61.189 6.936 61.619 ;
     RECT  13.68 60.907 40.488 61.621 ;
     RECT  41.472 61.395 43.896 61.621 ;
     RECT  53.04 61.765 53.064 61.813 ;
     RECT  56.448 61.557 58.152 61.843 ;
     RECT  59.232 60.467 59.952 61.843 ;
     RECT  8.496 61.427 8.52 61.877 ;
     RECT  8.064 61.877 8.52 61.941 ;
     RECT  9.936 61.419 11.976 61.941 ;
     RECT  13.68 61.621 43.896 61.957 ;
     RECT  2.832 61.619 6.936 62.005 ;
     RECT  7.92 61.941 8.52 62.005 ;
     RECT  2.832 62.005 8.52 62.051 ;
     RECT  61.008 61.525 61.128 62.051 ;
     RECT  2.832 62.051 3.048 62.059 ;
     RECT  61.008 62.051 61.08 62.059 ;
     RECT  46.08 61.419 46.296 62.111 ;
     RECT  47.472 60.947 47.64 62.111 ;
     RECT  46.08 62.111 47.64 62.133 ;
     RECT  48.72 61.235 49.32 62.133 ;
     RECT  13.536 61.957 43.896 62.137 ;
     RECT  61.056 62.059 61.08 62.195 ;
     RECT  16.44 62.137 43.896 62.197 ;
     RECT  46.08 62.133 49.32 62.197 ;
     RECT  52.896 61.813 53.064 62.197 ;
     RECT  54.048 61.523 55.464 62.197 ;
     RECT  50.448 61.235 51.864 62.325 ;
     RECT  52.896 62.197 55.464 62.325 ;
     RECT  9.936 61.941 12.36 62.437 ;
     RECT  4.032 62.051 8.52 62.453 ;
     RECT  9.84 62.437 12.36 62.453 ;
     RECT  62.16 62.101 62.184 62.507 ;
     RECT  50.448 62.325 55.464 62.531 ;
     RECT  54.144 62.531 55.464 62.547 ;
     RECT  56.448 61.843 59.952 62.547 ;
     RECT  2.832 62.059 2.904 62.581 ;
     RECT  16.44 62.197 43.944 62.581 ;
     RECT  44.928 62.111 44.952 62.581 ;
     RECT  16.44 62.581 44.952 62.709 ;
     RECT  54.144 62.547 59.952 62.723 ;
     RECT  4.032 62.453 12.36 62.771 ;
     RECT  1.92 62.581 2.904 62.797 ;
     RECT  59.28 62.723 59.952 62.797 ;
     RECT  16.44 62.709 45 62.837 ;
     RECT  46.08 62.197 49.464 62.837 ;
     RECT  4.512 62.771 12.36 62.879 ;
     RECT  13.536 62.137 15.096 62.879 ;
     RECT  16.44 62.837 49.464 62.955 ;
     RECT  4.512 62.879 15.096 62.963 ;
     RECT  4.56 62.963 15.096 63.019 ;
     RECT  59.64 62.797 59.952 63.023 ;
     RECT  4.56 63.019 15 63.049 ;
     RECT  47.76 62.955 49.464 63.097 ;
     RECT  59.64 63.023 60.456 63.107 ;
     RECT  16.44 62.955 46.776 63.109 ;
     RECT  47.856 63.097 49.464 63.117 ;
     RECT  13.056 63.049 15 63.147 ;
     RECT  16.32 63.109 46.776 63.205 ;
     RECT  54.144 62.723 57.816 63.251 ;
     RECT  16.272 63.205 46.776 63.285 ;
     RECT  13.056 63.147 13.08 63.289 ;
     RECT  16.128 63.285 46.776 63.289 ;
     RECT  1.92 62.797 1.944 63.299 ;
     RECT  4.56 63.049 11.688 63.299 ;
     RECT  47.856 63.117 49.152 63.299 ;
     RECT  50.448 62.531 53.112 63.339 ;
     RECT  5.136 63.299 11.352 63.347 ;
     RECT  52.224 63.339 53.112 63.347 ;
     RECT  54.24 63.251 57.816 63.347 ;
     RECT  14.784 63.147 14.856 63.395 ;
     RECT  52.224 63.347 53.064 63.395 ;
     RECT  5.472 63.347 11.352 63.443 ;
     RECT  16.128 63.289 46.248 63.477 ;
     RECT  5.52 63.443 7.992 63.491 ;
     RECT  55.92 63.347 57.624 63.491 ;
     RECT  9.072 63.443 11.352 63.539 ;
     RECT  56.256 63.491 57.048 63.539 ;
     RECT  15.984 63.477 46.248 63.587 ;
     RECT  16.128 63.587 46.248 63.595 ;
     RECT  16.44 63.595 46.248 63.635 ;
     RECT  50.448 63.339 50.712 63.637 ;
     RECT  50.352 63.637 50.712 63.673 ;
     RECT  59.64 63.107 60.072 63.683 ;
     RECT  5.52 63.491 6.888 63.723 ;
     RECT  9.792 63.539 11.352 63.723 ;
     RECT  50.352 63.673 50.616 63.723 ;
     RECT  10.224 63.723 11.352 63.731 ;
     RECT  48.72 63.299 49.152 63.731 ;
     RECT  56.784 63.539 57 63.731 ;
     RECT  0.24 57.539 0.552 63.743 ;
     RECT  11.04 63.731 11.352 63.743 ;
     RECT  16.44 63.635 44.472 63.743 ;
     RECT  48.84 63.731 49.152 63.743 ;
     RECT  54.24 63.347 54.552 63.743 ;
     RECT  59.64 63.683 59.952 63.743 ;
     RECT  53.04 63.395 53.064 63.779 ;
     RECT  56.784 63.731 56.808 63.779 ;
     RECT  45.888 63.635 46.248 63.787 ;
     RECT  5.52 63.723 5.952 63.817 ;
     RECT  14.832 63.395 14.856 63.851 ;
     RECT  16.632 63.743 44.472 63.875 ;
     RECT  18.24 63.875 44.472 63.923 ;
     RECT  0.432 63.743 0.552 64.013 ;
     RECT  5.832 63.817 5.952 64.013 ;
     RECT  11.232 63.743 11.352 64.013 ;
     RECT  16.632 63.875 17.208 64.013 ;
     RECT  49.032 63.743 49.152 64.013 ;
     RECT  54.432 63.743 54.552 64.013 ;
     RECT  59.832 63.743 59.952 64.013 ;
     RECT  17.184 64.013 17.208 64.107 ;
     RECT  46.224 63.787 46.248 64.363 ;
     RECT  18.528 63.923 44.472 64.491 ;
     RECT  18.768 64.491 43.896 64.499 ;
     RECT  18.768 64.499 43.848 64.595 ;
     RECT  19.008 64.595 43.848 64.683 ;
     RECT  50.352 63.723 50.376 64.683 ;
     RECT  19.152 64.683 43.848 64.72 ;
     RECT  27.12 64.72 27.864 64.747 ;
     RECT  31.968 64.72 31.992 64.747 ;
     RECT  35.568 64.72 36.504 64.747 ;
     RECT  38.544 64.72 39.096 64.747 ;
     RECT  40.176 64.72 40.2 64.747 ;
     RECT  41.376 64.72 41.4 64.747 ;
    LAYER M6 ;
     RECT  0 22.596 0.133 23.46 ;
     RECT  0 49.596 0.133 50.46 ;
     RECT  0.133 49.28 0.613 50.46 ;
     RECT  0 54.996 0.629 55.86 ;
     RECT  0 17.196 0.661 18.06 ;
     RECT  0.133 19.968 0.661 20 ;
     RECT  0.133 25.024 0.693 25.056 ;
     RECT  0 27.996 0.693 28.86 ;
     RECT  0.629 52.8 0.757 52.832 ;
     RECT  0.629 54.72 0.853 55.86 ;
     RECT  0.133 22.08 1.093 23.46 ;
     RECT  0 38.796 1.093 39.66 ;
     RECT  0.613 48.96 1.093 50.46 ;
     RECT  1.093 21.952 1.141 23.46 ;
     RECT  0.693 25.024 1.141 28.86 ;
     RECT  0.661 17.196 1.259 20 ;
     RECT  1.093 48.96 1.381 51.36 ;
     RECT  1.141 21.952 1.387 28.86 ;
     RECT  1.381 47.744 1.451 51.36 ;
     RECT  0 11.796 1.477 12.66 ;
     RECT  1.189 14.528 1.477 14.56 ;
     RECT  1.259 17.196 1.573 19.36 ;
     RECT  0 44.196 1.573 45.06 ;
     RECT  0.133 57.408 1.573 57.44 ;
     RECT  0.853 54.4 1.621 55.86 ;
     RECT  1.573 57.216 1.621 57.44 ;
     RECT  1.451 47.744 1.669 47.84 ;
     RECT  1.387 27.392 1.715 28.86 ;
     RECT  1.451 49.28 1.765 51.36 ;
     RECT  0.757 52.8 1.765 52.96 ;
     RECT  1.573 44.032 1.909 45.06 ;
     RECT  1.89 42.112 1.963 42.144 ;
     RECT  0 60.396 2.005 61.26 ;
     RECT  1.715 27.648 2.082 28.86 ;
     RECT  1.765 49.28 2.082 52.96 ;
     RECT  0 33.396 2.101 34.26 ;
     RECT  1.909 43.904 2.101 45.06 ;
     RECT  1.621 54.4 2.101 57.44 ;
     RECT  1.477 11.796 2.245 14.56 ;
     RECT  1.573 17.024 2.245 19.36 ;
     RECT  2.082 27.648 2.245 29.024 ;
     RECT  2.101 33.396 2.245 34.4 ;
     RECT  1.477 36.288 2.245 36.32 ;
     RECT  2.101 54.4 2.245 58.4 ;
     RECT  2.005 59.776 2.245 61.26 ;
     RECT  1.89 62.592 2.245 62.624 ;
     RECT  1.669 47.68 2.291 47.84 ;
     RECT  1.093 38.796 2.293 40.8 ;
     RECT  2.245 33.396 2.339 36.32 ;
     RECT  2.082 49.28 2.421 53.088 ;
     RECT  2.245 54.4 2.421 62.624 ;
     RECT  2.293 38.144 2.443 40.8 ;
     RECT  2.443 36.928 2.485 40.8 ;
     RECT  2.485 36.928 2.723 41.376 ;
     RECT  2.245 27.648 2.773 29.28 ;
     RECT  2.245 11.796 2.795 19.36 ;
     RECT  2.773 27.648 2.821 30.432 ;
     RECT  2.339 33.396 2.821 35.168 ;
     RECT  2.421 49.28 2.869 62.624 ;
     RECT  2.101 42.688 2.965 45.06 ;
     RECT  2.965 42.688 3.051 45.664 ;
     RECT  1.387 22.08 3.109 25.696 ;
     RECT  2.795 13.952 3.125 19.36 ;
     RECT  3.125 13.952 3.189 19.808 ;
     RECT  3.109 21.504 3.253 25.696 ;
     RECT  2.291 47.68 3.301 47.712 ;
     RECT  2.723 38.796 3.397 41.376 ;
     RECT  3.051 42.688 3.397 45.06 ;
     RECT  2.821 27.648 3.493 31.008 ;
     RECT  2.821 32.512 3.493 35.168 ;
     RECT  2.869 49.28 3.509 62.752 ;
     RECT  3.397 38.796 3.539 45.06 ;
     RECT  3.493 27.648 3.563 35.168 ;
     RECT  3.539 38.796 3.587 42.72 ;
     RECT  3.253 21.504 3.829 26.08 ;
     RECT  3.563 27.648 3.829 31.008 ;
     RECT  3.301 46.592 3.829 47.712 ;
     RECT  3.563 32.512 3.877 35.168 ;
     RECT  2.723 36.928 3.877 36.96 ;
     RECT  3.829 46.592 3.898 47.84 ;
     RECT  3.189 13.952 3.925 19.936 ;
     RECT  3.829 21.504 3.925 31.008 ;
     RECT  3.898 46.656 3.957 47.84 ;
     RECT  3.509 49.152 3.957 62.752 ;
     RECT  3.539 44.032 4.019 45.06 ;
     RECT  3.925 13.952 4.307 31.008 ;
     RECT  3.877 32.512 4.386 36.96 ;
     RECT  3.587 38.796 4.386 42.4 ;
     RECT  3.957 46.656 4.405 62.752 ;
     RECT  4.307 13.952 4.595 30.944 ;
     RECT  4.405 46.656 4.595 63.328 ;
     RECT  4.595 13.952 4.691 30.56 ;
     RECT  2.795 11.796 4.789 12.66 ;
     RECT  4.386 32.512 5.029 42.4 ;
     RECT  5.029 32.256 5.099 42.4 ;
     RECT  4.595 47.68 5.109 63.328 ;
     RECT  4.341 64.64 5.109 64.672 ;
     RECT  4.691 14.144 5.291 30.56 ;
     RECT  4.019 44.196 5.301 45.06 ;
     RECT  5.099 32.832 5.315 42.4 ;
     RECT  5.291 22.08 5.483 30.56 ;
     RECT  5.301 43.904 5.621 45.06 ;
     RECT  5.621 43.904 6.005 46.24 ;
     RECT  4.789 11.648 6.037 12.66 ;
     RECT  5.291 14.144 6.037 20.704 ;
     RECT  5.315 38.796 6.114 42.4 ;
     RECT  6.005 43.904 6.114 46.304 ;
     RECT  5.483 22.208 6.229 30.56 ;
     RECT  0 0.996 6.645 1.86 ;
     RECT  6.037 11.648 6.699 20.704 ;
     RECT  6.699 11.796 6.805 20.704 ;
     RECT  6.229 22.208 6.805 30.816 ;
     RECT  6.114 38.796 6.837 46.304 ;
     RECT  6.805 11.796 6.899 30.816 ;
     RECT  6.837 38.336 7.157 46.304 ;
     RECT  5.109 47.68 7.157 64.672 ;
     RECT  5.315 32.832 7.475 36.896 ;
     RECT  7.475 32.96 7.541 36.896 ;
     RECT  7.157 38.336 7.541 64.672 ;
     RECT  6.899 17.196 7.925 30.816 ;
     RECT  6.899 11.796 8.533 15.52 ;
     RECT  7.925 17.196 8.533 31.136 ;
     RECT  7.541 32.96 8.811 64.672 ;
     RECT  8.533 11.796 8.917 31.136 ;
     RECT  8.811 32.96 8.917 36.192 ;
     RECT  8.917 11.796 8.949 31.328 ;
     RECT  8.917 32.704 8.949 36.192 ;
     RECT  8.811 37.632 9.131 64.672 ;
     RECT  8.949 11.796 10.549 36.192 ;
     RECT  9.131 37.632 10.549 41.76 ;
     RECT  10.549 11.796 10.731 41.76 ;
     RECT  10.645 10.304 10.789 10.336 ;
     RECT  10.731 16 10.835 41.76 ;
     RECT  9.131 43.456 11.243 64.672 ;
     RECT  11.243 43.456 11.307 56.48 ;
     RECT  11.307 43.456 11.435 56.416 ;
     RECT  10.835 25.408 11.445 41.76 ;
     RECT  11.435 43.456 11.445 50.72 ;
     RECT  10.731 11.796 11.459 14.624 ;
     RECT  10.835 16 11.459 23.904 ;
     RECT  11.445 25.408 11.459 50.72 ;
     RECT  11.435 52.224 11.987 56.416 ;
     RECT  10.789 9.728 12.021 10.336 ;
     RECT  11.459 11.796 12.021 12.66 ;
     RECT  11.459 14.272 12.075 14.624 ;
     RECT  11.459 16.512 12.075 23.904 ;
     RECT  11.459 25.536 12.075 47.968 ;
     RECT  11.243 58.56 12.075 64.672 ;
     RECT  12.075 19.392 12.083 23.904 ;
     RECT  12.021 9.728 12.229 12.66 ;
     RECT  12.075 25.664 12.331 47.968 ;
     RECT  12.331 25.664 12.563 31.328 ;
     RECT  11.987 53.76 12.661 56.416 ;
     RECT  12.075 14.592 12.805 14.624 ;
     RECT  12.331 32.704 12.805 47.968 ;
     RECT  11.459 49.28 12.805 50.72 ;
     RECT  12.805 32.704 12.853 50.72 ;
     RECT  11.987 52.224 12.853 52.256 ;
     RECT  12.229 9.28 12.949 12.66 ;
     RECT  12.805 14.592 12.997 14.752 ;
     RECT  12.075 16.512 12.997 18.06 ;
     RECT  12.083 19.392 13.043 23.648 ;
     RECT  12.997 14.592 13.091 18.06 ;
     RECT  12.853 32.704 13.091 52.256 ;
     RECT  12.661 53.76 13.381 57.056 ;
     RECT  12.075 58.688 13.381 64.672 ;
     RECT  0 6.396 13.429 7.26 ;
     RECT  13.043 19.648 13.621 23.648 ;
     RECT  13.091 32.896 13.621 52.256 ;
     RECT  13.381 53.76 13.621 64.672 ;
     RECT  12.949 9.28 13.669 13.088 ;
     RECT  13.669 9.152 13.685 13.088 ;
     RECT  13.621 32.896 13.715 64.672 ;
     RECT  13.685 8.96 14.197 13.088 ;
     RECT  13.621 19.648 14.485 23.776 ;
     RECT  14.485 19.392 14.629 23.776 ;
     RECT  12.563 25.728 14.629 30.56 ;
     RECT  13.715 32.896 14.677 51.296 ;
     RECT  14.629 4.224 14.709 4.256 ;
     RECT  13.429 6.208 14.709 7.26 ;
     RECT  14.677 32.32 14.754 51.296 ;
     RECT  14.197 8.832 14.773 13.088 ;
     RECT  13.091 14.72 14.773 18.06 ;
     RECT  14.629 19.392 14.773 30.56 ;
     RECT  14.754 32.192 14.773 51.296 ;
     RECT  6.645 0.996 14.867 2.528 ;
     RECT  14.709 3.968 14.867 7.26 ;
     RECT  14.867 6.396 15.093 7.26 ;
     RECT  14.773 8.832 15.157 18.06 ;
     RECT  14.773 19.392 15.157 51.296 ;
     RECT  15.157 8.832 15.203 51.296 ;
     RECT  14.867 3.968 15.443 4 ;
     RECT  15.093 6.396 15.797 7.392 ;
     RECT  15.203 8.832 15.797 35.104 ;
     RECT  15.797 6.396 15.851 35.104 ;
     RECT  15.851 10.304 15.875 35.104 ;
     RECT  15.875 10.56 16.067 35.104 ;
     RECT  15.203 36.672 16.309 51.296 ;
     RECT  13.715 52.608 16.309 64.672 ;
     RECT  16.309 36.672 16.355 64.672 ;
     RECT  16.355 36.672 16.837 40.864 ;
     RECT  16.501 3.392 16.883 3.424 ;
     RECT  15.851 6.396 16.931 8.992 ;
     RECT  16.067 19.712 16.933 35.104 ;
     RECT  16.837 36.608 16.933 40.864 ;
     RECT  16.933 19.712 16.939 40.864 ;
     RECT  14.867 0.996 17.077 1.86 ;
     RECT  16.931 8.96 17.269 8.992 ;
     RECT  17.077 0.996 17.557 2.016 ;
     RECT  17.557 0.996 17.643 2.912 ;
     RECT  16.355 42.176 17.699 64.672 ;
     RECT  17.699 42.176 17.795 42.208 ;
     RECT  16.931 6.396 17.989 7.584 ;
     RECT  17.269 8.96 17.989 9.248 ;
     RECT  16.067 10.56 17.989 18.208 ;
     RECT  17.989 8.96 18.165 18.208 ;
     RECT  16.939 19.712 18.165 40.608 ;
     RECT  18.165 8.96 18.421 40.608 ;
     RECT  17.989 6.208 18.613 7.584 ;
     RECT  18.421 8.96 18.613 40.8 ;
     RECT  19.045 4.544 19.061 4.576 ;
     RECT  18.613 6.208 19.061 40.8 ;
     RECT  17.699 43.648 19.189 64.672 ;
     RECT  19.061 4.544 19.285 40.8 ;
     RECT  19.285 4.544 19.317 41.312 ;
     RECT  19.189 43.648 19.317 64.736 ;
     RECT  17.643 0.996 19.333 2.016 ;
     RECT  19.333 0.996 19.957 3.04 ;
     RECT  19.317 4.544 19.957 64.736 ;
     RECT  19.957 0.996 20.051 64.736 ;
     RECT  20.051 0.996 20.267 37.472 ;
     RECT  20.267 9.6 21.099 37.472 ;
     RECT  21.099 17.196 21.685 37.472 ;
     RECT  20.051 38.796 21.685 64.736 ;
     RECT  21.099 9.6 21.779 15.712 ;
     RECT  20.267 0.996 21.813 7.904 ;
     RECT  21.779 10.56 22.259 15.712 ;
     RECT  21.685 17.196 22.259 64.736 ;
     RECT  21.813 0.996 22.451 8.992 ;
     RECT  22.259 38.796 22.955 64.736 ;
     RECT  22.955 53.056 23.083 64.736 ;
     RECT  22.259 10.56 23.157 15.584 ;
     RECT  22.259 17.196 23.747 37.472 ;
     RECT  22.451 0.996 23.797 8.928 ;
     RECT  23.157 10.496 23.797 15.584 ;
     RECT  23.797 0.996 23.861 15.584 ;
     RECT  23.747 17.196 23.861 37.344 ;
     RECT  23.861 0.996 24.805 37.344 ;
     RECT  22.955 38.796 25.333 51.616 ;
     RECT  23.083 53.184 25.333 64.736 ;
     RECT  24.805 0.832 25.461 37.344 ;
     RECT  25.333 38.796 25.461 64.736 ;
     RECT  25.461 0.832 25.771 64.736 ;
     RECT  25.771 0.832 26.219 35.296 ;
     RECT  26.219 0.832 26.243 4.576 ;
     RECT  26.243 0.832 26.291 1.86 ;
     RECT  25.771 36.864 27.059 64.736 ;
     RECT  26.219 5.888 27.109 35.296 ;
     RECT  27.059 36.864 27.109 37.344 ;
     RECT  27.109 5.888 27.781 37.344 ;
     RECT  26.243 3.264 27.877 3.872 ;
     RECT  27.781 5.696 27.877 37.344 ;
     RECT  27.059 38.656 27.898 64.736 ;
     RECT  27.877 3.264 27.971 4.192 ;
     RECT  27.877 5.568 28.405 37.344 ;
     RECT  27.898 38.656 28.405 64.672 ;
     RECT  27.971 3.584 28.453 4.192 ;
     RECT  28.405 5.568 28.453 64.672 ;
     RECT  28.453 3.584 28.547 64.672 ;
     RECT  28.547 3.584 28.595 41.888 ;
     RECT  28.547 43.2 29.171 64.672 ;
     RECT  29.171 52.224 29.237 64.672 ;
     RECT  28.595 3.584 29.291 37.472 ;
     RECT  29.291 37.312 29.483 37.472 ;
     RECT  29.171 43.2 29.795 50.848 ;
     RECT  29.291 3.584 30.114 35.872 ;
     RECT  29.795 43.584 30.453 50.848 ;
     RECT  29.237 52.224 30.453 64.736 ;
     RECT  30.114 3.392 30.757 35.872 ;
     RECT  28.595 38.796 30.773 41.888 ;
     RECT  26.291 0.996 31.029 1.86 ;
     RECT  29.483 37.44 31.141 37.472 ;
     RECT  30.773 38.796 31.141 42.016 ;
     RECT  31.029 0.192 31.285 1.86 ;
     RECT  30.757 3.2 31.285 35.872 ;
     RECT  31.285 0.192 31.349 35.872 ;
     RECT  31.349 0.192 31.354 36.064 ;
     RECT  31.354 0.192 31.427 1.86 ;
     RECT  30.453 43.584 31.429 64.736 ;
     RECT  31.354 3.2 31.525 36.064 ;
     RECT  31.141 37.44 31.525 42.016 ;
     RECT  31.525 3.2 31.723 42.016 ;
     RECT  31.429 43.328 32.003 64.736 ;
     RECT  32.003 43.328 33.013 64.672 ;
     RECT  31.723 3.2 33.059 41.12 ;
     RECT  33.013 43.264 33.141 64.672 ;
     RECT  33.059 3.328 33.445 41.12 ;
     RECT  33.445 3.328 34.597 41.568 ;
     RECT  33.141 42.944 34.597 64.672 ;
     RECT  34.597 3.328 35.253 64.672 ;
     RECT  31.427 0.996 35.797 1.86 ;
     RECT  35.253 3.328 35.797 64.736 ;
     RECT  35.797 0.996 35.845 64.736 ;
     RECT  35.845 0.704 37.091 64.736 ;
     RECT  37.091 0.704 37.227 37.472 ;
     RECT  37.091 38.796 37.675 64.736 ;
     RECT  37.227 0.996 38.485 37.472 ;
     RECT  37.675 38.796 38.485 40.224 ;
     RECT  37.675 41.92 38.965 64.736 ;
     RECT  38.485 0.996 39.157 40.224 ;
     RECT  38.965 41.536 39.157 64.736 ;
     RECT  39.157 0.996 41.451 64.736 ;
     RECT  41.451 0.996 42.133 64.672 ;
     RECT  42.133 0.832 43.379 64.672 ;
     RECT  43.379 0.996 44.483 64.672 ;
     RECT  44.483 0.996 45.299 3.68 ;
     RECT  45.299 3.648 45.675 3.68 ;
     RECT  44.483 5.056 45.739 64.672 ;
     RECT  45.739 5.056 46.309 57.76 ;
     RECT  46.309 4.8 46.891 57.76 ;
     RECT  46.891 38.796 47.285 57.76 ;
     RECT  47.285 38.796 47.363 57.824 ;
     RECT  46.891 4.8 47.845 37.472 ;
     RECT  45.739 59.648 48.661 64.672 ;
     RECT  47.845 4.736 48.709 37.472 ;
     RECT  47.363 38.796 48.709 57.12 ;
     RECT  48.709 4.736 48.757 57.12 ;
     RECT  48.757 4.736 49.191 57.952 ;
     RECT  48.661 59.392 49.191 64.672 ;
     RECT  49.191 4.736 50.387 64.672 ;
     RECT  50.387 4.736 50.627 63.712 ;
     RECT  50.627 4.736 51.923 63.648 ;
     RECT  51.923 4.736 52.355 37.472 ;
     RECT  52.355 5.696 53.557 37.472 ;
     RECT  51.923 38.796 53.557 63.648 ;
     RECT  53.557 5.696 53.603 63.648 ;
     RECT  53.603 17.088 54.763 63.648 ;
     RECT  53.603 5.696 54.803 15.648 ;
     RECT  54.763 17.088 55.523 45.536 ;
     RECT  55.523 17.088 55.813 45.472 ;
     RECT  54.803 5.76 56.003 15.648 ;
     RECT  56.003 5.76 56.677 14.752 ;
     RECT  54.763 46.976 56.773 63.648 ;
     RECT  55.813 17.024 56.821 45.472 ;
     RECT  56.773 46.976 56.821 63.712 ;
     RECT  56.821 17.024 56.875 63.712 ;
     RECT  56.677 5.632 56.939 14.752 ;
     RECT  56.875 17.024 57.251 63.648 ;
     RECT  56.939 5.888 57.349 14.752 ;
     RECT  57.349 5.888 57.397 14.88 ;
     RECT  57.251 17.024 57.397 56.608 ;
     RECT  57.397 5.888 57.587 56.608 ;
     RECT  57.587 16.576 57.635 56.608 ;
     RECT  57.587 5.888 58.163 14.752 ;
     RECT  57.251 58.24 58.645 63.648 ;
     RECT  57.635 16.576 58.731 56.032 ;
     RECT  58.645 58.112 59.381 63.648 ;
     RECT  58.163 6.208 59.413 14.752 ;
     RECT  58.731 16.576 59.507 51.424 ;
     RECT  58.731 52.736 59.509 56.032 ;
     RECT  59.413 6.208 59.555 15.136 ;
     RECT  45.299 0.996 59.76 1.86 ;
     RECT  59.507 16.96 60.083 51.424 ;
     RECT  59.381 57.6 60.083 63.648 ;
     RECT  59.555 6.272 60.131 15.136 ;
     RECT  59.509 52.736 60.277 56.224 ;
     RECT  60.083 57.6 60.277 63.072 ;
     RECT  60.131 6.272 60.467 9.44 ;
     RECT  60.131 10.752 60.467 15.136 ;
     RECT  60.277 52.736 60.467 63.072 ;
     RECT  59.76 1.572 60.544 1.86 ;
     RECT  60.467 6.972 60.544 9.44 ;
     RECT  60.083 17.024 60.544 51.424 ;
     RECT  60.544 40 60.661 51.424 ;
     RECT  60.467 52.736 60.661 62.496 ;
     RECT  60.544 18.624 60.755 38.688 ;
     RECT  60.544 7.552 60.803 9.44 ;
     RECT  60.803 7.552 60.899 8.928 ;
     RECT  60.544 17.024 60.899 17.056 ;
     RECT  60.661 40 60.971 62.496 ;
     RECT  60.467 10.752 60.995 14.752 ;
     RECT  60.971 41.792 60.995 62.496 ;
     RECT  60.899 7.936 61.043 8.928 ;
     RECT  60.995 12.48 61.043 14.752 ;
     RECT  60.995 49.216 61.043 62.496 ;
     RECT  60.995 10.752 61.139 10.784 ;
     RECT  60.755 18.752 61.235 38.688 ;
     RECT  60.995 41.792 61.283 43.168 ;
     RECT  61.043 12.48 61.419 14.304 ;
     RECT  61.043 8.896 61.475 8.928 ;
     RECT  61.419 12.48 61.475 14.176 ;
     RECT  61.235 18.752 61.611 38.368 ;
     RECT  61.475 13.184 61.619 14.176 ;
     RECT  61.611 18.752 61.619 23.072 ;
     RECT  60.995 44.608 61.619 47.84 ;
     RECT  61.611 24.768 61.667 38.368 ;
     RECT  61.283 42.048 61.667 43.168 ;
     RECT  61.043 49.216 61.667 60.896 ;
     RECT  61.619 19.904 61.715 23.072 ;
     RECT  61.619 14.144 61.811 14.176 ;
     RECT  61.619 46.144 61.859 47.84 ;
     RECT  61.667 49.216 61.859 55.904 ;
     RECT  61.667 42.048 61.867 42.912 ;
     RECT  61.859 49.536 61.867 49.568 ;
     RECT  61.715 19.904 61.931 22.432 ;
     RECT  61.859 51.008 61.931 55.904 ;
     RECT  61.931 19.904 62.003 22.304 ;
     RECT  60.971 40 62.123 40.48 ;
     RECT  61.867 42.048 62.123 42.72 ;
     RECT  61.667 57.344 62.123 60.896 ;
     RECT  62.003 19.968 62.195 22.304 ;
     RECT  61.667 24.768 62.195 28.896 ;
     RECT  61.667 30.4 62.195 38.368 ;
     RECT  61.619 44.608 62.195 44.64 ;
     RECT  61.859 46.592 62.195 47.84 ;
     RECT  61.931 51.008 62.195 53.536 ;
     RECT  62.123 58.496 62.195 60.896 ;
     RECT  61.043 62.464 62.195 62.496 ;
     RECT  62.195 24.768 62.243 26.208 ;
     RECT  62.195 30.528 62.243 32.608 ;
     RECT  62.195 33.92 62.243 35.68 ;
     RECT  62.123 42.176 62.243 42.72 ;
     RECT  62.195 27.904 62.251 28.768 ;
     RECT  62.243 30.784 62.251 31.072 ;
     RECT  62.243 33.92 62.251 34.208 ;
     RECT  62.195 51.008 62.251 51.68 ;
     RECT  62.195 53.504 62.251 53.536 ;
     RECT  61.931 55.808 62.251 55.84 ;
     RECT  62.195 21.248 62.291 22.304 ;
     RECT  62.243 24.768 62.291 24.8 ;
     RECT  62.251 28.736 62.291 28.768 ;
     RECT  62.291 22.272 62.339 22.304 ;
     RECT  62.243 26.176 62.339 26.208 ;
     RECT  62.243 32.576 62.339 32.608 ;
     RECT  62.195 47.616 62.339 47.84 ;
     RECT  62.243 42.496 62.379 42.72 ;
     RECT  62.339 47.808 62.379 47.84 ;
     RECT  62.379 42.688 62.398 42.72 ;
     RECT  62.251 51.008 62.483 51.552 ;
     RECT  62.251 30.784 62.531 30.88 ;
     RECT  62.483 51.008 62.531 51.04 ;
     RECT  62.251 34.176 62.571 34.208 ;
     RECT  62.195 37.568 62.571 38.368 ;
     RECT  62.123 40 62.581 40.032 ;
     RECT  61.237 4.8 62.675 4.832 ;
     RECT  62.581 38.72 62.763 40.032 ;
     RECT  62.531 30.848 62.771 30.88 ;
    LAYER M7 ;
     RECT  37.184 0.693 37.216 0.821 ;
     RECT  17.056 0.531 17.344 1.397 ;
     RECT  31.04 0.181 31.072 1.397 ;
     RECT  44.056 0.531 44.344 1.397 ;
     RECT  24.832 0.821 24.864 1.973 ;
     RECT  36.48 0.821 37.216 2.101 ;
     RECT  42.752 1.397 44.344 2.219 ;
     RECT  24.192 1.973 24.864 2.229 ;
     RECT  35.84 2.101 37.216 2.229 ;
     RECT  38.656 0.531 38.944 2.229 ;
     RECT  42.944 2.219 44.344 2.229 ;
     RECT  6.256 0.531 6.544 2.485 ;
     RECT  22.456 0.531 22.744 2.613 ;
     RECT  22.336 2.613 22.744 2.741 ;
     RECT  21.12 2.741 22.744 2.805 ;
     RECT  17.056 1.397 17.632 2.923 ;
     RECT  20.096 2.805 22.744 2.987 ;
     RECT  20.224 2.987 22.744 3.189 ;
     RECT  24.192 2.229 26.144 3.189 ;
     RECT  40.896 2.805 40.928 3.189 ;
     RECT  35.84 2.229 38.944 3.253 ;
     RECT  40.768 3.189 40.928 3.253 ;
     RECT  17.056 2.923 17.344 3.381 ;
     RECT  31.04 1.397 31.328 3.381 ;
     RECT  42.944 2.229 44.832 3.637 ;
     RECT  33.256 0.531 33.544 3.957 ;
     RECT  35.84 3.253 40.928 3.957 ;
     RECT  20.224 3.189 26.208 4.075 ;
     RECT  30.144 3.381 31.904 4.213 ;
     RECT  33.256 3.957 41.568 4.213 ;
     RECT  20.224 4.075 23.392 4.533 ;
     RECT  24.832 4.075 26.208 4.651 ;
     RECT  30.144 4.213 41.568 4.651 ;
     RECT  49.456 0.531 49.744 4.725 ;
     RECT  60.256 0.531 60.544 4.789 ;
     RECT  14.72 3.957 14.752 5.163 ;
     RECT  42.944 3.637 45.664 5.227 ;
     RECT  48.768 4.725 49.744 5.301 ;
     RECT  27.856 0.531 28.144 5.557 ;
     RECT  30.272 4.651 41.568 5.621 ;
     RECT  30.272 5.621 41.632 5.739 ;
     RECT  19.072 4.533 23.392 5.877 ;
     RECT  24.832 4.651 26.144 5.877 ;
     RECT  51.904 5.365 51.936 6.069 ;
     RECT  35.2 5.739 41.632 6.133 ;
     RECT  42.944 5.227 44.768 6.133 ;
     RECT  16.512 3.381 17.344 6.197 ;
     RECT  19.072 5.877 26.144 6.197 ;
     RECT  27.856 5.557 28.512 6.197 ;
     RECT  30.272 5.739 33.544 6.197 ;
     RECT  56.896 5.621 56.928 6.197 ;
     RECT  60.256 4.789 61.28 6.197 ;
     RECT  13.44 6.197 13.472 6.773 ;
     RECT  48.448 5.301 49.744 6.773 ;
     RECT  51.904 6.069 52.064 6.773 ;
     RECT  35.2 6.133 44.768 6.891 ;
     RECT  47.424 6.773 52.064 6.891 ;
     RECT  27.856 6.197 33.544 7.349 ;
     RECT  35.2 6.891 41.76 7.349 ;
     RECT  54.856 0.531 55.144 7.349 ;
     RECT  56.768 6.197 56.928 7.349 ;
     RECT  15.104 7.349 15.136 7.733 ;
     RECT  16.512 6.197 26.144 7.733 ;
     RECT  59.072 6.197 61.28 7.979 ;
     RECT  15.104 7.733 26.144 8.043 ;
     RECT  27.456 7.349 41.76 8.107 ;
     RECT  43.136 6.891 44.768 8.373 ;
     RECT  52.032 6.891 52.064 8.501 ;
     RECT  48.768 6.891 50.72 8.747 ;
     RECT  47.424 6.891 47.456 8.821 ;
     RECT  52.032 8.501 52.448 8.885 ;
     RECT  42.944 8.373 44.768 9.195 ;
     RECT  27.456 8.107 41.056 9.259 ;
     RECT  47.424 8.821 47.776 9.707 ;
     RECT  43.264 9.195 44.768 9.717 ;
     RECT  13.44 6.773 13.728 9.973 ;
     RECT  15.104 8.043 26.08 9.973 ;
     RECT  49.456 8.747 50.72 10.357 ;
     RECT  52.032 8.885 52.768 10.357 ;
     RECT  60.032 7.979 61.28 10.741 ;
     RECT  27.456 9.259 40.736 11.061 ;
     RECT  43.264 9.717 44.896 11.061 ;
     RECT  43.264 11.061 45.664 11.115 ;
     RECT  47.68 9.707 47.776 11.125 ;
     RECT  47.552 11.125 47.776 11.179 ;
     RECT  11.656 0.531 11.944 11.317 ;
     RECT  27.456 11.061 41.12 11.381 ;
     RECT  43.584 11.115 45.664 11.435 ;
     RECT  47.552 11.179 47.712 11.435 ;
     RECT  13.44 9.973 26.08 11.691 ;
     RECT  59.904 10.741 61.28 11.691 ;
     RECT  27.456 11.381 41.44 12.149 ;
     RECT  54.856 7.349 57.632 12.203 ;
     RECT  6.256 2.485 6.688 12.213 ;
     RECT  13.44 11.691 13.472 12.267 ;
     RECT  60.256 11.691 61.28 12.469 ;
     RECT  8.128 12.213 9.312 12.725 ;
     RECT  49.456 10.357 52.768 12.725 ;
     RECT  6.256 12.213 6.752 12.779 ;
     RECT  14.848 11.691 26.08 12.779 ;
     RECT  6.256 12.779 6.688 12.971 ;
     RECT  14.848 12.779 15.456 13.045 ;
     RECT  17.056 12.779 26.08 13.045 ;
     RECT  27.456 12.149 41.632 13.045 ;
     RECT  47.552 11.435 47.584 13.099 ;
     RECT  17.056 13.045 41.632 13.291 ;
     RECT  54.856 12.203 56.608 13.355 ;
     RECT  43.776 11.435 45.664 13.365 ;
     RECT  8.128 12.725 9.888 13.429 ;
     RECT  11.656 11.317 12.064 13.429 ;
     RECT  56.576 13.355 56.608 13.493 ;
     RECT  43.648 13.365 45.664 13.557 ;
     RECT  49.456 12.725 52.896 13.557 ;
     RECT  56.576 13.493 57.44 13.739 ;
     RECT  8.128 13.429 12.064 13.867 ;
     RECT  2.752 13.813 2.784 14.005 ;
     RECT  6.256 12.971 6.544 14.005 ;
     RECT  14.784 13.045 15.456 14.069 ;
     RECT  6.08 14.005 6.544 14.133 ;
     RECT  2.624 14.005 2.784 14.197 ;
     RECT  14.784 14.069 15.712 14.261 ;
     RECT  17.056 13.291 17.344 14.261 ;
     RECT  60.256 12.469 61.408 14.315 ;
     RECT  18.816 13.291 41.632 14.453 ;
     RECT  49.456 13.557 53.472 14.581 ;
     RECT  14.784 14.261 17.344 14.709 ;
     RECT  18.816 14.453 42.016 14.763 ;
     RECT  43.648 13.557 46.752 14.891 ;
     RECT  4.864 14.133 6.544 14.965 ;
     RECT  13.696 14.709 17.344 15.093 ;
     RECT  18.816 14.763 41.888 15.093 ;
     RECT  8.576 13.867 12.064 15.147 ;
     RECT  4.8 14.965 6.544 15.221 ;
     RECT  9.28 15.147 12.064 15.285 ;
     RECT  13.696 15.093 41.888 15.285 ;
     RECT  9.28 15.285 41.888 15.467 ;
     RECT  48.448 14.581 53.472 15.467 ;
     RECT  44.056 14.891 46.752 15.915 ;
     RECT  2.624 14.197 3.424 16.043 ;
     RECT  17.056 15.467 41.888 16.043 ;
     RECT  48.448 15.467 50.72 16.043 ;
     RECT  57.408 13.739 57.44 16.043 ;
     RECT  41.856 16.043 41.888 16.171 ;
     RECT  48.448 16.043 49.888 16.171 ;
     RECT  3.392 16.043 3.424 16.309 ;
     RECT  4.8 15.221 7.52 16.309 ;
     RECT  52.544 15.467 53.472 16.555 ;
     RECT  45.696 15.915 46.752 16.565 ;
     RECT  52.544 16.555 52.768 16.821 ;
     RECT  52.352 16.821 52.768 16.949 ;
     RECT  0.856 0.531 1.144 17.013 ;
     RECT  54.856 13.355 55.144 17.013 ;
     RECT  14.144 15.467 15.712 17.131 ;
     RECT  0.856 17.013 1.696 17.589 ;
     RECT  3.392 16.309 7.52 17.589 ;
     RECT  9.28 15.467 11.944 17.589 ;
     RECT  45.696 16.565 47.136 17.589 ;
     RECT  48.448 16.171 49.744 17.589 ;
     RECT  54.856 17.013 56.16 17.589 ;
     RECT  51.84 16.949 52.768 17.707 ;
     RECT  14.592 17.131 15.712 18.165 ;
     RECT  17.056 16.043 40.416 18.165 ;
     RECT  44.056 15.915 44.344 18.165 ;
     RECT  45.696 17.589 49.744 18.165 ;
     RECT  54.856 17.589 56.416 18.293 ;
     RECT  14.592 18.165 40.416 18.485 ;
     RECT  52.736 17.707 52.768 18.549 ;
     RECT  54.856 18.293 57.44 18.549 ;
     RECT  0.704 17.589 1.696 18.923 ;
     RECT  44.056 18.165 49.744 19.115 ;
     RECT  14.592 18.485 40.672 19.189 ;
     RECT  52.736 18.549 57.44 19.189 ;
     RECT  60.256 14.315 61.28 19.253 ;
     RECT  3.136 17.589 7.52 19.317 ;
     RECT  9.28 17.589 13.024 19.317 ;
     RECT  44.056 19.115 44.344 19.317 ;
     RECT  0.856 18.923 1.696 19.371 ;
     RECT  58.944 19.253 61.28 19.509 ;
     RECT  3.136 19.317 13.024 19.691 ;
     RECT  51.52 19.189 57.44 19.691 ;
     RECT  3.136 19.691 12.96 19.819 ;
     RECT  58.752 19.509 61.28 19.893 ;
     RECT  0.856 19.371 1.248 20.011 ;
     RECT  57.408 19.691 57.44 20.213 ;
     RECT  58.752 19.893 61.92 20.213 ;
     RECT  43.584 19.317 44.344 20.469 ;
     RECT  45.632 19.115 49.744 20.469 ;
     RECT  43.584 20.469 49.744 20.587 ;
     RECT  3.2 19.819 12.96 21.045 ;
     RECT  14.592 19.189 41.632 21.045 ;
     RECT  3.2 21.045 41.632 21.163 ;
     RECT  51.52 19.691 56.096 21.163 ;
     RECT  51.52 21.163 55.144 21.355 ;
     RECT  57.408 20.213 61.92 21.493 ;
     RECT  47.808 20.587 49.744 21.557 ;
     RECT  0.856 20.011 1.144 21.941 ;
     RECT  0.856 21.941 1.376 22.197 ;
     RECT  3.2 21.163 40.672 22.443 ;
     RECT  57.216 21.493 61.92 22.443 ;
     RECT  0.856 22.197 1.568 22.453 ;
     RECT  3.2 22.443 14.112 22.453 ;
     RECT  43.584 20.587 46.496 22.453 ;
     RECT  52.032 21.355 55.144 22.453 ;
     RECT  43.264 22.453 46.496 23.029 ;
     RECT  47.808 21.557 50.144 23.029 ;
     RECT  52.032 22.453 55.648 23.029 ;
     RECT  0.856 22.453 14.112 23.595 ;
     RECT  57.216 22.443 61.6 23.659 ;
     RECT  51.712 23.029 55.648 23.787 ;
     RECT  57.792 23.659 61.6 23.915 ;
     RECT  15.936 22.443 40.672 24.171 ;
     RECT  43.264 23.029 50.144 24.171 ;
     RECT  17.056 24.171 40.672 24.309 ;
     RECT  43.264 24.171 49.744 24.309 ;
     RECT  58.112 23.915 61.6 24.555 ;
     RECT  43.136 24.309 49.744 24.619 ;
     RECT  43.136 24.619 47.584 24.683 ;
     RECT  43.136 24.683 45.408 24.821 ;
     RECT  0.856 23.595 3.168 25.013 ;
     RECT  4.544 23.595 14.112 25.013 ;
     RECT  0.704 25.013 14.112 25.451 ;
     RECT  51.712 23.787 55.144 25.707 ;
     RECT  42.688 24.821 45.408 25.771 ;
     RECT  43.136 25.771 45.408 25.835 ;
     RECT  49.024 24.619 49.744 25.835 ;
     RECT  4.352 25.451 14.112 25.899 ;
     RECT  58.112 24.555 58.272 25.909 ;
     RECT  53.568 25.707 55.144 26.037 ;
     RECT  53.568 26.037 56.096 26.101 ;
     RECT  58.112 25.909 58.912 26.101 ;
     RECT  17.056 24.309 41.376 26.229 ;
     RECT  46.72 24.683 47.584 26.283 ;
     RECT  46.72 26.283 46.752 26.347 ;
     RECT  43.392 25.835 45.408 26.485 ;
     RECT  51.712 25.707 52.128 26.741 ;
     RECT  53.568 26.101 58.912 26.741 ;
     RECT  60.256 24.555 61.6 26.741 ;
     RECT  0.704 25.451 2.72 26.859 ;
     RECT  53.568 26.741 61.6 27.243 ;
     RECT  0.856 26.859 2.72 27.435 ;
     RECT  4.352 25.899 12.768 27.637 ;
     RECT  2.496 27.435 2.72 27.691 ;
     RECT  43.392 26.485 45.792 27.829 ;
     RECT  17.056 26.229 41.76 27.883 ;
     RECT  53.568 27.243 56.096 27.883 ;
     RECT  57.664 27.243 61.6 27.893 ;
     RECT  49.456 25.835 49.744 28.405 ;
     RECT  51.648 26.741 52.128 28.405 ;
     RECT  53.568 27.883 55.264 28.405 ;
     RECT  0.856 27.435 1.144 28.981 ;
     RECT  2.496 27.691 2.528 28.981 ;
     RECT  43.328 27.829 45.792 28.981 ;
     RECT  43.328 28.981 45.984 29.045 ;
     RECT  4.032 27.637 12.768 29.099 ;
     RECT  49.456 28.405 55.264 29.099 ;
     RECT  42.688 29.045 45.984 29.557 ;
     RECT  49.456 29.099 55.144 29.621 ;
     RECT  48.704 29.621 55.144 29.739 ;
     RECT  14.08 25.899 14.112 30.133 ;
     RECT  57.664 27.893 62.24 30.315 ;
     RECT  4.032 29.099 12.32 30.443 ;
     RECT  15.68 30.709 15.712 30.901 ;
     RECT  42.688 29.557 46.816 31.467 ;
     RECT  13.632 30.133 14.112 31.541 ;
     RECT  15.424 30.901 15.712 31.541 ;
     RECT  0.856 28.981 2.528 31.861 ;
     RECT  4.352 30.443 12.32 31.861 ;
     RECT  0.856 31.861 12.32 31.979 ;
     RECT  57.92 30.315 62.24 32.117 ;
     RECT  13.632 31.541 15.712 32.309 ;
     RECT  17.056 27.883 40.8 32.309 ;
     RECT  51.84 29.739 55.144 32.555 ;
     RECT  0.856 31.979 11.944 32.747 ;
     RECT  42.688 31.467 45.984 32.811 ;
     RECT  51.84 32.555 52.832 32.885 ;
     RECT  13.632 32.309 40.8 33.205 ;
     RECT  57.6 32.117 62.24 33.323 ;
     RECT  0.856 32.747 8.8 33.835 ;
     RECT  42.88 32.811 45.984 33.899 ;
     RECT  57.728 33.323 62.24 34.165 ;
     RECT  10.112 32.747 11.944 34.357 ;
     RECT  13.632 33.205 41.504 34.357 ;
     RECT  0.856 33.835 2.144 34.411 ;
     RECT  51.584 32.885 52.832 34.421 ;
     RECT  54.144 32.555 55.144 34.421 ;
     RECT  10.112 34.357 41.504 34.475 ;
     RECT  51.584 34.421 55.144 34.603 ;
     RECT  48.704 29.739 49.744 34.677 ;
     RECT  3.52 33.835 8.8 34.741 ;
     RECT  10.112 34.475 14.368 34.741 ;
     RECT  48.704 34.677 50.08 34.741 ;
     RECT  51.584 34.603 52.832 34.741 ;
     RECT  15.936 34.475 41.504 35.115 ;
     RECT  16.064 35.115 41.504 35.125 ;
     RECT  16.064 35.125 41.824 35.189 ;
     RECT  43.136 33.899 45.984 35.189 ;
     RECT  57.728 34.165 62.56 35.189 ;
     RECT  54.144 34.603 55.144 35.317 ;
     RECT  57.024 35.189 62.56 35.317 ;
     RECT  16.064 35.189 45.984 35.701 ;
     RECT  3.52 34.741 14.368 35.883 ;
     RECT  48.704 34.741 52.832 35.947 ;
     RECT  16.064 35.701 46.752 36.085 ;
     RECT  3.52 35.883 14.24 36.917 ;
     RECT  54.144 35.317 62.56 36.981 ;
     RECT  2.496 36.917 14.24 37.355 ;
     RECT  54.016 36.981 62.56 37.611 ;
     RECT  0.856 34.411 1.144 38.133 ;
     RECT  2.496 37.355 11.944 38.133 ;
     RECT  16.064 36.085 46.88 38.379 ;
     RECT  54.016 37.611 61.344 38.379 ;
     RECT  13.632 37.355 14.24 38.453 ;
     RECT  13.632 38.453 14.688 39.157 ;
     RECT  54.016 38.379 60.544 39.221 ;
     RECT  13.632 39.157 14.752 39.733 ;
     RECT  48.704 35.947 51.616 39.925 ;
     RECT  53.504 39.221 60.544 39.925 ;
     RECT  13.376 39.733 14.752 39.979 ;
     RECT  48.704 39.925 60.544 39.979 ;
     RECT  62.72 38.709 62.752 39.989 ;
     RECT  62.336 39.989 62.752 40.043 ;
     RECT  13.376 39.979 14.688 40.107 ;
     RECT  16.064 38.379 46.752 40.299 ;
     RECT  48.704 39.979 56.032 40.363 ;
     RECT  62.336 40.043 62.368 40.437 ;
     RECT  16.192 40.299 46.752 40.629 ;
     RECT  0.856 38.133 11.944 40.811 ;
     RECT  57.344 39.979 60.544 40.821 ;
     RECT  62.08 40.437 62.368 40.821 ;
     RECT  16.192 40.629 46.88 40.885 ;
     RECT  48.704 40.363 55.904 40.885 ;
     RECT  57.344 40.821 62.368 41.835 ;
     RECT  16.192 40.885 55.904 41.845 ;
     RECT  16.192 41.845 56.032 42.027 ;
     RECT  0.856 40.811 1.144 42.101 ;
     RECT  2.496 40.811 11.944 42.101 ;
     RECT  0.856 42.101 11.944 42.677 ;
     RECT  13.376 40.107 14.368 42.677 ;
     RECT  16.192 42.027 55.968 42.731 ;
     RECT  57.536 41.835 62.368 42.731 ;
     RECT  48 42.731 55.968 43.243 ;
     RECT  48.448 43.243 55.968 43.445 ;
     RECT  57.536 42.731 61.856 43.445 ;
     RECT  48.448 43.445 61.856 43.627 ;
     RECT  0.856 42.677 14.368 43.947 ;
     RECT  48.448 43.627 58.464 44.075 ;
     RECT  59.904 43.627 61.856 44.523 ;
     RECT  3.008 43.947 14.112 45.675 ;
     RECT  16.192 42.731 46.24 45.675 ;
     RECT  48.448 44.075 55.144 46.005 ;
     RECT  56.832 44.075 58.464 46.251 ;
     RECT  16.192 45.675 45.984 46.581 ;
     RECT  56.96 46.251 58.464 46.901 ;
     RECT  60.256 44.523 61.856 46.901 ;
     RECT  3.52 45.675 14.112 47.157 ;
     RECT  15.872 46.581 45.984 47.221 ;
     RECT  47.808 46.005 55.144 47.221 ;
     RECT  56.96 46.901 61.856 47.339 ;
     RECT  15.872 47.221 55.144 47.467 ;
     RECT  0.856 43.947 1.144 47.733 ;
     RECT  0.856 47.733 1.44 47.797 ;
     RECT  3.52 47.157 14.432 47.797 ;
     RECT  57.856 47.339 61.856 47.797 ;
     RECT  54.856 47.467 55.144 48.501 ;
     RECT  15.872 47.467 53.536 49.067 ;
     RECT  0.856 47.797 14.432 50.037 ;
     RECT  57.856 47.797 62.368 50.677 ;
     RECT  54.856 48.501 55.264 50.933 ;
     RECT  0.856 50.037 14.624 50.987 ;
     RECT  16.448 49.067 53.536 50.997 ;
     RECT  54.856 50.933 55.584 50.997 ;
     RECT  57.344 50.677 62.368 51.051 ;
     RECT  13.632 50.987 14.624 51.307 ;
     RECT  16.32 50.997 53.536 51.637 ;
     RECT  54.856 50.997 55.84 51.637 ;
     RECT  16.32 51.637 55.84 52.587 ;
     RECT  0.856 50.987 12.256 52.789 ;
     RECT  13.632 51.307 14.432 52.789 ;
     RECT  16.32 52.587 53.216 52.789 ;
     RECT  54.592 52.587 55.84 52.789 ;
     RECT  57.344 51.051 62.24 52.789 ;
     RECT  13.632 52.789 53.216 53.035 ;
     RECT  0.64 52.789 12.256 53.099 ;
     RECT  13.632 53.035 53.088 53.227 ;
     RECT  0.64 53.099 1.144 54.763 ;
     RECT  14.08 53.227 53.088 54.837 ;
     RECT  0.856 54.763 1.144 55.349 ;
     RECT  2.432 53.099 12.256 55.349 ;
     RECT  54.592 52.789 62.24 55.851 ;
     RECT  14.08 54.837 53.152 55.979 ;
     RECT  54.592 55.851 62.112 56.043 ;
     RECT  16.32 55.979 53.152 56.491 ;
     RECT  54.592 56.043 57.632 56.565 ;
     RECT  54.08 56.565 57.632 57.003 ;
     RECT  14.08 55.979 14.88 57.643 ;
     RECT  16.32 56.491 52.512 57.707 ;
     RECT  57.6 57.003 57.632 58.101 ;
     RECT  59.392 56.043 62.112 58.101 ;
     RECT  57.6 58.101 62.112 58.347 ;
     RECT  54.08 57.003 56.288 58.613 ;
     RECT  57.6 58.347 60.544 58.613 ;
     RECT  62.08 58.347 62.112 58.923 ;
     RECT  0.856 55.349 12.256 58.997 ;
     RECT  14.08 57.643 14.112 58.997 ;
     RECT  17.056 57.707 52.512 59.125 ;
     RECT  54.08 58.613 60.544 59.125 ;
     RECT  17.056 59.125 60.544 59.253 ;
     RECT  0.856 58.997 14.112 59.637 ;
     RECT  0.856 59.637 14.688 59.883 ;
     RECT  14.08 59.883 14.688 60.213 ;
     RECT  16.064 59.253 60.544 60.213 ;
     RECT  14.08 60.213 60.544 60.267 ;
     RECT  14.08 60.267 57.952 60.843 ;
     RECT  14.08 60.843 53.024 60.907 ;
     RECT  0.856 59.883 12.256 61.611 ;
     RECT  54.336 60.843 57.952 61.611 ;
     RECT  15.936 60.907 53.024 61.867 ;
     RECT  3.264 61.611 12.256 62.005 ;
     RECT  14.08 60.907 14.56 62.005 ;
     RECT  59.52 60.267 60.544 62.005 ;
     RECT  3.264 62.005 14.56 62.197 ;
     RECT  15.936 61.867 52.192 62.197 ;
     RECT  54.336 61.611 57.824 62.251 ;
     RECT  3.264 62.197 52.192 62.443 ;
     RECT  3.392 62.443 52.192 62.571 ;
     RECT  0.856 61.611 1.952 62.635 ;
     RECT  54.72 62.251 57.824 62.699 ;
     RECT  3.392 62.571 13.92 62.763 ;
     RECT  16.128 62.571 52.192 62.763 ;
     RECT  59.264 62.005 60.544 62.763 ;
     RECT  48.448 62.763 52.192 62.891 ;
     RECT  4.352 62.763 13.92 62.955 ;
     RECT  48.576 62.891 52.192 62.955 ;
     RECT  16.128 62.763 46.176 63.083 ;
     RECT  4.352 62.955 13.088 63.147 ;
     RECT  48.576 62.955 51.936 63.211 ;
     RECT  10.496 63.147 13.088 63.275 ;
     RECT  48.576 63.211 51.872 63.275 ;
     RECT  51.264 63.275 51.872 63.339 ;
     RECT  54.856 62.699 57.824 63.339 ;
     RECT  60.032 62.763 60.544 63.339 ;
     RECT  16.128 63.083 42.72 63.403 ;
     RECT  44.056 63.083 46.176 63.403 ;
     RECT  44.056 63.403 45.792 63.467 ;
     RECT  51.264 63.339 51.488 63.467 ;
     RECT  54.856 63.339 56.928 63.531 ;
     RECT  4.352 63.147 9.12 63.595 ;
     RECT  45.76 63.467 45.792 63.595 ;
     RECT  51.456 63.467 51.488 63.595 ;
     RECT  56.832 63.531 56.928 63.595 ;
     RECT  48.576 63.275 49.744 63.723 ;
     RECT  56.832 63.595 56.864 63.723 ;
     RECT  17.056 63.403 42.72 63.851 ;
     RECT  0.856 62.635 1.144 63.999 ;
     RECT  10.496 63.275 11.944 63.999 ;
     RECT  17.056 63.851 17.344 63.999 ;
     RECT  44.056 63.467 44.344 63.999 ;
     RECT  49.456 63.723 49.744 63.999 ;
     RECT  54.856 63.531 55.144 63.999 ;
     RECT  60.256 63.339 60.544 63.999 ;
     RECT  10.496 63.999 10.72 64.171 ;
     RECT  10.496 64.171 10.528 64.235 ;
     RECT  18.688 63.851 42.72 64.235 ;
     RECT  4.352 63.595 8.224 64.299 ;
     RECT  4.352 64.299 7.712 64.363 ;
     RECT  18.688 64.235 42.336 64.363 ;
     RECT  4.352 64.363 6.752 64.427 ;
     RECT  4.352 64.427 6.112 64.491 ;
     RECT  18.688 64.363 42.272 64.491 ;
     RECT  4.352 64.491 5.6 64.555 ;
     RECT  4.352 64.555 5.536 64.619 ;
     RECT  19.2 64.491 21.472 64.619 ;
     RECT  22.848 64.491 29.28 64.619 ;
     RECT  30.848 64.491 32.352 64.619 ;
     RECT  34.432 64.491 36.832 64.619 ;
     RECT  4.352 64.619 4.384 64.683 ;
     RECT  19.2 64.619 19.424 64.683 ;
     RECT  22.848 64.619 22.88 64.683 ;
     RECT  24.704 64.619 29.28 64.683 ;
     RECT  31.04 64.619 32.224 64.683 ;
     RECT  39.04 64.491 42.272 64.683 ;
     RECT  19.2 64.683 19.232 64.747 ;
     RECT  20.928 64.619 21.472 64.747 ;
     RECT  26.752 64.683 27.872 64.747 ;
     RECT  29.248 64.683 29.28 64.747 ;
     RECT  35.264 64.619 36.832 64.747 ;
     RECT  39.04 64.683 40.032 64.747 ;
     RECT  41.408 64.683 41.44 64.747 ;
  END
END dsfd_r2l_vr_512x1__hsel
END LIBRARY
